VERSION 5.8 ;
BUSBITCHARS "[]" ;
DIVIDERCHAR "/" ;
UNITS
    DATABASE MICRONS 1000 ;
END UNITS

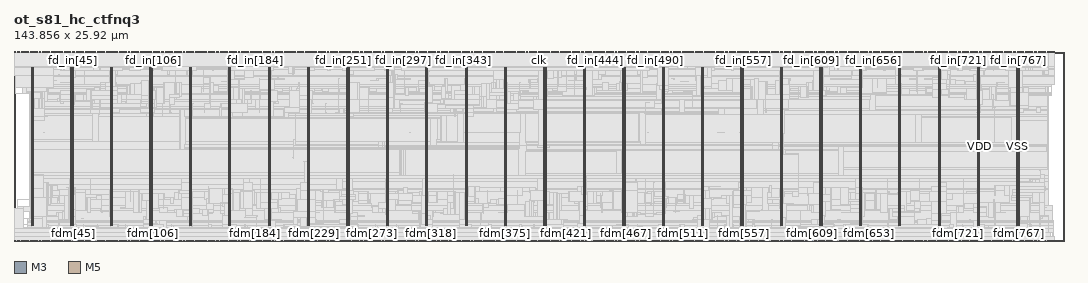
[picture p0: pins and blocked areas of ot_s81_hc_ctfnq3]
MACRO ot_s81_hc_ctfnq3
  FOREIGN ot_s81_hc_ctfnq3 0 0 ;
  CLASS BLOCK ;
  SIZE 143.856 BY 25.92 ;
  PIN clk
    DIRECTION INPUT ;
    USE SIGNAL ;
    PORT
      LAYER M3 ;
        RECT  71.892 25.882 71.91 25.92 ;
    END
  END clk
  PIN fd_in[0]
    DIRECTION INPUT ;
    USE SIGNAL ;
    PORT
      LAYER M5 ;
        RECT  0.048 25.836 0.072 25.92 ;
    END
  END fd_in[0]
  PIN fd_in[100]
    DIRECTION INPUT ;
    USE SIGNAL ;
    PORT
      LAYER M5 ;
        RECT  18 25.836 18.024 25.92 ;
    END
  END fd_in[100]
  PIN fd_in[101]
    DIRECTION INPUT ;
    USE SIGNAL ;
    PORT
      LAYER M5 ;
        RECT  18.192 25.836 18.216 25.92 ;
    END
  END fd_in[101]
  PIN fd_in[102]
    DIRECTION INPUT ;
    USE SIGNAL ;
    PORT
      LAYER M5 ;
        RECT  18.336 25.836 18.36 25.92 ;
    END
  END fd_in[102]
  PIN fd_in[103]
    DIRECTION INPUT ;
    USE SIGNAL ;
    PORT
      LAYER M5 ;
        RECT  18.528 25.836 18.552 25.92 ;
    END
  END fd_in[103]
  PIN fd_in[104]
    DIRECTION INPUT ;
    USE SIGNAL ;
    PORT
      LAYER M5 ;
        RECT  18.72 25.836 18.744 25.92 ;
    END
  END fd_in[104]
  PIN fd_in[105]
    DIRECTION INPUT ;
    USE SIGNAL ;
    PORT
      LAYER M5 ;
        RECT  18.864 25.836 18.888 25.92 ;
    END
  END fd_in[105]
  PIN fd_in[106]
    DIRECTION INPUT ;
    USE SIGNAL ;
    PORT
      LAYER M5 ;
        RECT  19.056 25.836 19.08 25.92 ;
    END
  END fd_in[106]
  PIN fd_in[107]
    DIRECTION INPUT ;
    USE SIGNAL ;
    PORT
      LAYER M5 ;
        RECT  19.248 25.836 19.272 25.92 ;
    END
  END fd_in[107]
  PIN fd_in[108]
    DIRECTION INPUT ;
    USE SIGNAL ;
    PORT
      LAYER M5 ;
        RECT  19.44 25.836 19.464 25.92 ;
    END
  END fd_in[108]
  PIN fd_in[109]
    DIRECTION INPUT ;
    USE SIGNAL ;
    PORT
      LAYER M5 ;
        RECT  19.584 25.836 19.608 25.92 ;
    END
  END fd_in[109]
  PIN fd_in[10]
    DIRECTION INPUT ;
    USE SIGNAL ;
    PORT
      LAYER M5 ;
        RECT  1.872 25.836 1.896 25.92 ;
    END
  END fd_in[10]
  PIN fd_in[110]
    DIRECTION INPUT ;
    USE SIGNAL ;
    PORT
      LAYER M5 ;
        RECT  19.776 25.836 19.8 25.92 ;
    END
  END fd_in[110]
  PIN fd_in[111]
    DIRECTION INPUT ;
    USE SIGNAL ;
    PORT
      LAYER M5 ;
        RECT  19.968 25.836 19.992 25.92 ;
    END
  END fd_in[111]
  PIN fd_in[112]
    DIRECTION INPUT ;
    USE SIGNAL ;
    PORT
      LAYER M5 ;
        RECT  20.16 25.836 20.184 25.92 ;
    END
  END fd_in[112]
  PIN fd_in[113]
    DIRECTION INPUT ;
    USE SIGNAL ;
    PORT
      LAYER M5 ;
        RECT  20.304 25.836 20.328 25.92 ;
    END
  END fd_in[113]
  PIN fd_in[114]
    DIRECTION INPUT ;
    USE SIGNAL ;
    PORT
      LAYER M5 ;
        RECT  20.496 25.836 20.52 25.92 ;
    END
  END fd_in[114]
  PIN fd_in[115]
    DIRECTION INPUT ;
    USE SIGNAL ;
    PORT
      LAYER M5 ;
        RECT  20.688 25.836 20.712 25.92 ;
    END
  END fd_in[115]
  PIN fd_in[116]
    DIRECTION INPUT ;
    USE SIGNAL ;
    PORT
      LAYER M5 ;
        RECT  20.88 25.836 20.904 25.92 ;
    END
  END fd_in[116]
  PIN fd_in[117]
    DIRECTION INPUT ;
    USE SIGNAL ;
    PORT
      LAYER M5 ;
        RECT  21.024 25.836 21.048 25.92 ;
    END
  END fd_in[117]
  PIN fd_in[118]
    DIRECTION INPUT ;
    USE SIGNAL ;
    PORT
      LAYER M5 ;
        RECT  21.216 25.836 21.24 25.92 ;
    END
  END fd_in[118]
  PIN fd_in[119]
    DIRECTION INPUT ;
    USE SIGNAL ;
    PORT
      LAYER M5 ;
        RECT  21.408 25.836 21.432 25.92 ;
    END
  END fd_in[119]
  PIN fd_in[11]
    DIRECTION INPUT ;
    USE SIGNAL ;
    PORT
      LAYER M5 ;
        RECT  2.016 25.836 2.04 25.92 ;
    END
  END fd_in[11]
  PIN fd_in[120]
    DIRECTION INPUT ;
    USE SIGNAL ;
    PORT
      LAYER M5 ;
        RECT  21.552 25.836 21.576 25.92 ;
    END
  END fd_in[120]
  PIN fd_in[121]
    DIRECTION INPUT ;
    USE SIGNAL ;
    PORT
      LAYER M5 ;
        RECT  21.744 25.836 21.768 25.92 ;
    END
  END fd_in[121]
  PIN fd_in[122]
    DIRECTION INPUT ;
    USE SIGNAL ;
    PORT
      LAYER M5 ;
        RECT  21.936 25.836 21.96 25.92 ;
    END
  END fd_in[122]
  PIN fd_in[123]
    DIRECTION INPUT ;
    USE SIGNAL ;
    PORT
      LAYER M5 ;
        RECT  22.128 25.836 22.152 25.92 ;
    END
  END fd_in[123]
  PIN fd_in[124]
    DIRECTION INPUT ;
    USE SIGNAL ;
    PORT
      LAYER M5 ;
        RECT  22.272 25.836 22.296 25.92 ;
    END
  END fd_in[124]
  PIN fd_in[125]
    DIRECTION INPUT ;
    USE SIGNAL ;
    PORT
      LAYER M5 ;
        RECT  22.464 25.836 22.488 25.92 ;
    END
  END fd_in[125]
  PIN fd_in[126]
    DIRECTION INPUT ;
    USE SIGNAL ;
    PORT
      LAYER M5 ;
        RECT  22.656 25.836 22.68 25.92 ;
    END
  END fd_in[126]
  PIN fd_in[127]
    DIRECTION INPUT ;
    USE SIGNAL ;
    PORT
      LAYER M5 ;
        RECT  22.848 25.836 22.872 25.92 ;
    END
  END fd_in[127]
  PIN fd_in[128]
    DIRECTION INPUT ;
    USE SIGNAL ;
    PORT
      LAYER M5 ;
        RECT  22.992 25.836 23.016 25.92 ;
    END
  END fd_in[128]
  PIN fd_in[129]
    DIRECTION INPUT ;
    USE SIGNAL ;
    PORT
      LAYER M5 ;
        RECT  23.184 25.836 23.208 25.92 ;
    END
  END fd_in[129]
  PIN fd_in[12]
    DIRECTION INPUT ;
    USE SIGNAL ;
    PORT
      LAYER M5 ;
        RECT  2.208 25.836 2.232 25.92 ;
    END
  END fd_in[12]
  PIN fd_in[130]
    DIRECTION INPUT ;
    USE SIGNAL ;
    PORT
      LAYER M5 ;
        RECT  23.376 25.836 23.4 25.92 ;
    END
  END fd_in[130]
  PIN fd_in[131]
    DIRECTION INPUT ;
    USE SIGNAL ;
    PORT
      LAYER M5 ;
        RECT  23.568 25.836 23.592 25.92 ;
    END
  END fd_in[131]
  PIN fd_in[132]
    DIRECTION INPUT ;
    USE SIGNAL ;
    PORT
      LAYER M5 ;
        RECT  23.712 25.836 23.736 25.92 ;
    END
  END fd_in[132]
  PIN fd_in[133]
    DIRECTION INPUT ;
    USE SIGNAL ;
    PORT
      LAYER M5 ;
        RECT  23.904 25.836 23.928 25.92 ;
    END
  END fd_in[133]
  PIN fd_in[134]
    DIRECTION INPUT ;
    USE SIGNAL ;
    PORT
      LAYER M5 ;
        RECT  24.096 25.836 24.12 25.92 ;
    END
  END fd_in[134]
  PIN fd_in[135]
    DIRECTION INPUT ;
    USE SIGNAL ;
    PORT
      LAYER M5 ;
        RECT  24.288 25.836 24.312 25.92 ;
    END
  END fd_in[135]
  PIN fd_in[136]
    DIRECTION INPUT ;
    USE SIGNAL ;
    PORT
      LAYER M5 ;
        RECT  24.432 25.836 24.456 25.92 ;
    END
  END fd_in[136]
  PIN fd_in[137]
    DIRECTION INPUT ;
    USE SIGNAL ;
    PORT
      LAYER M5 ;
        RECT  24.624 25.836 24.648 25.92 ;
    END
  END fd_in[137]
  PIN fd_in[138]
    DIRECTION INPUT ;
    USE SIGNAL ;
    PORT
      LAYER M5 ;
        RECT  24.816 25.836 24.84 25.92 ;
    END
  END fd_in[138]
  PIN fd_in[139]
    DIRECTION INPUT ;
    USE SIGNAL ;
    PORT
      LAYER M5 ;
        RECT  24.96 25.836 24.984 25.92 ;
    END
  END fd_in[139]
  PIN fd_in[13]
    DIRECTION INPUT ;
    USE SIGNAL ;
    PORT
      LAYER M5 ;
        RECT  2.4 25.836 2.424 25.92 ;
    END
  END fd_in[13]
  PIN fd_in[140]
    DIRECTION INPUT ;
    USE SIGNAL ;
    PORT
      LAYER M5 ;
        RECT  25.152 25.836 25.176 25.92 ;
    END
  END fd_in[140]
  PIN fd_in[141]
    DIRECTION INPUT ;
    USE SIGNAL ;
    PORT
      LAYER M5 ;
        RECT  25.344 25.836 25.368 25.92 ;
    END
  END fd_in[141]
  PIN fd_in[142]
    DIRECTION INPUT ;
    USE SIGNAL ;
    PORT
      LAYER M5 ;
        RECT  25.536 25.836 25.56 25.92 ;
    END
  END fd_in[142]
  PIN fd_in[143]
    DIRECTION INPUT ;
    USE SIGNAL ;
    PORT
      LAYER M5 ;
        RECT  25.68 25.836 25.704 25.92 ;
    END
  END fd_in[143]
  PIN fd_in[144]
    DIRECTION INPUT ;
    USE SIGNAL ;
    PORT
      LAYER M5 ;
        RECT  25.872 25.836 25.896 25.92 ;
    END
  END fd_in[144]
  PIN fd_in[145]
    DIRECTION INPUT ;
    USE SIGNAL ;
    PORT
      LAYER M5 ;
        RECT  26.064 25.836 26.088 25.92 ;
    END
  END fd_in[145]
  PIN fd_in[146]
    DIRECTION INPUT ;
    USE SIGNAL ;
    PORT
      LAYER M5 ;
        RECT  26.256 25.836 26.28 25.92 ;
    END
  END fd_in[146]
  PIN fd_in[147]
    DIRECTION INPUT ;
    USE SIGNAL ;
    PORT
      LAYER M5 ;
        RECT  26.4 25.836 26.424 25.92 ;
    END
  END fd_in[147]
  PIN fd_in[148]
    DIRECTION INPUT ;
    USE SIGNAL ;
    PORT
      LAYER M5 ;
        RECT  26.592 25.836 26.616 25.92 ;
    END
  END fd_in[148]
  PIN fd_in[149]
    DIRECTION INPUT ;
    USE SIGNAL ;
    PORT
      LAYER M5 ;
        RECT  26.784 25.836 26.808 25.92 ;
    END
  END fd_in[149]
  PIN fd_in[14]
    DIRECTION INPUT ;
    USE SIGNAL ;
    PORT
      LAYER M5 ;
        RECT  2.544 25.836 2.568 25.92 ;
    END
  END fd_in[14]
  PIN fd_in[150]
    DIRECTION INPUT ;
    USE SIGNAL ;
    PORT
      LAYER M5 ;
        RECT  26.976 25.836 27 25.92 ;
    END
  END fd_in[150]
  PIN fd_in[151]
    DIRECTION INPUT ;
    USE SIGNAL ;
    PORT
      LAYER M5 ;
        RECT  27.12 25.836 27.144 25.92 ;
    END
  END fd_in[151]
  PIN fd_in[152]
    DIRECTION INPUT ;
    USE SIGNAL ;
    PORT
      LAYER M5 ;
        RECT  27.312 25.836 27.336 25.92 ;
    END
  END fd_in[152]
  PIN fd_in[153]
    DIRECTION INPUT ;
    USE SIGNAL ;
    PORT
      LAYER M5 ;
        RECT  27.504 25.836 27.528 25.92 ;
    END
  END fd_in[153]
  PIN fd_in[154]
    DIRECTION INPUT ;
    USE SIGNAL ;
    PORT
      LAYER M5 ;
        RECT  27.696 25.836 27.72 25.92 ;
    END
  END fd_in[154]
  PIN fd_in[155]
    DIRECTION INPUT ;
    USE SIGNAL ;
    PORT
      LAYER M5 ;
        RECT  27.84 25.836 27.864 25.92 ;
    END
  END fd_in[155]
  PIN fd_in[156]
    DIRECTION INPUT ;
    USE SIGNAL ;
    PORT
      LAYER M5 ;
        RECT  28.032 25.836 28.056 25.92 ;
    END
  END fd_in[156]
  PIN fd_in[157]
    DIRECTION INPUT ;
    USE SIGNAL ;
    PORT
      LAYER M5 ;
        RECT  28.224 25.836 28.248 25.92 ;
    END
  END fd_in[157]
  PIN fd_in[158]
    DIRECTION INPUT ;
    USE SIGNAL ;
    PORT
      LAYER M5 ;
        RECT  28.368 25.836 28.392 25.92 ;
    END
  END fd_in[158]
  PIN fd_in[159]
    DIRECTION INPUT ;
    USE SIGNAL ;
    PORT
      LAYER M5 ;
        RECT  28.56 25.836 28.584 25.92 ;
    END
  END fd_in[159]
  PIN fd_in[15]
    DIRECTION INPUT ;
    USE SIGNAL ;
    PORT
      LAYER M5 ;
        RECT  2.736 25.836 2.76 25.92 ;
    END
  END fd_in[15]
  PIN fd_in[160]
    DIRECTION INPUT ;
    USE SIGNAL ;
    PORT
      LAYER M5 ;
        RECT  28.752 25.836 28.776 25.92 ;
    END
  END fd_in[160]
  PIN fd_in[161]
    DIRECTION INPUT ;
    USE SIGNAL ;
    PORT
      LAYER M5 ;
        RECT  28.944 25.836 28.968 25.92 ;
    END
  END fd_in[161]
  PIN fd_in[162]
    DIRECTION INPUT ;
    USE SIGNAL ;
    PORT
      LAYER M5 ;
        RECT  29.088 25.836 29.112 25.92 ;
    END
  END fd_in[162]
  PIN fd_in[163]
    DIRECTION INPUT ;
    USE SIGNAL ;
    PORT
      LAYER M5 ;
        RECT  29.28 25.836 29.304 25.92 ;
    END
  END fd_in[163]
  PIN fd_in[164]
    DIRECTION INPUT ;
    USE SIGNAL ;
    PORT
      LAYER M5 ;
        RECT  29.472 25.836 29.496 25.92 ;
    END
  END fd_in[164]
  PIN fd_in[165]
    DIRECTION INPUT ;
    USE SIGNAL ;
    PORT
      LAYER M5 ;
        RECT  29.664 25.836 29.688 25.92 ;
    END
  END fd_in[165]
  PIN fd_in[166]
    DIRECTION INPUT ;
    USE SIGNAL ;
    PORT
      LAYER M5 ;
        RECT  29.808 25.836 29.832 25.92 ;
    END
  END fd_in[166]
  PIN fd_in[167]
    DIRECTION INPUT ;
    USE SIGNAL ;
    PORT
      LAYER M5 ;
        RECT  30 25.836 30.024 25.92 ;
    END
  END fd_in[167]
  PIN fd_in[168]
    DIRECTION INPUT ;
    USE SIGNAL ;
    PORT
      LAYER M5 ;
        RECT  30.192 25.836 30.216 25.92 ;
    END
  END fd_in[168]
  PIN fd_in[169]
    DIRECTION INPUT ;
    USE SIGNAL ;
    PORT
      LAYER M5 ;
        RECT  30.384 25.836 30.408 25.92 ;
    END
  END fd_in[169]
  PIN fd_in[16]
    DIRECTION INPUT ;
    USE SIGNAL ;
    PORT
      LAYER M5 ;
        RECT  2.928 25.836 2.952 25.92 ;
    END
  END fd_in[16]
  PIN fd_in[170]
    DIRECTION INPUT ;
    USE SIGNAL ;
    PORT
      LAYER M5 ;
        RECT  30.528 25.836 30.552 25.92 ;
    END
  END fd_in[170]
  PIN fd_in[171]
    DIRECTION INPUT ;
    USE SIGNAL ;
    PORT
      LAYER M5 ;
        RECT  30.72 25.836 30.744 25.92 ;
    END
  END fd_in[171]
  PIN fd_in[172]
    DIRECTION INPUT ;
    USE SIGNAL ;
    PORT
      LAYER M5 ;
        RECT  30.912 25.836 30.936 25.92 ;
    END
  END fd_in[172]
  PIN fd_in[173]
    DIRECTION INPUT ;
    USE SIGNAL ;
    PORT
      LAYER M5 ;
        RECT  31.104 25.836 31.128 25.92 ;
    END
  END fd_in[173]
  PIN fd_in[174]
    DIRECTION INPUT ;
    USE SIGNAL ;
    PORT
      LAYER M5 ;
        RECT  31.248 25.836 31.272 25.92 ;
    END
  END fd_in[174]
  PIN fd_in[175]
    DIRECTION INPUT ;
    USE SIGNAL ;
    PORT
      LAYER M5 ;
        RECT  31.44 25.836 31.464 25.92 ;
    END
  END fd_in[175]
  PIN fd_in[176]
    DIRECTION INPUT ;
    USE SIGNAL ;
    PORT
      LAYER M5 ;
        RECT  31.632 25.836 31.656 25.92 ;
    END
  END fd_in[176]
  PIN fd_in[177]
    DIRECTION INPUT ;
    USE SIGNAL ;
    PORT
      LAYER M5 ;
        RECT  31.776 25.836 31.8 25.92 ;
    END
  END fd_in[177]
  PIN fd_in[178]
    DIRECTION INPUT ;
    USE SIGNAL ;
    PORT
      LAYER M5 ;
        RECT  31.968 25.836 31.992 25.92 ;
    END
  END fd_in[178]
  PIN fd_in[179]
    DIRECTION INPUT ;
    USE SIGNAL ;
    PORT
      LAYER M5 ;
        RECT  32.16 25.836 32.184 25.92 ;
    END
  END fd_in[179]
  PIN fd_in[17]
    DIRECTION INPUT ;
    USE SIGNAL ;
    PORT
      LAYER M5 ;
        RECT  3.12 25.836 3.144 25.92 ;
    END
  END fd_in[17]
  PIN fd_in[180]
    DIRECTION INPUT ;
    USE SIGNAL ;
    PORT
      LAYER M5 ;
        RECT  32.352 25.836 32.376 25.92 ;
    END
  END fd_in[180]
  PIN fd_in[181]
    DIRECTION INPUT ;
    USE SIGNAL ;
    PORT
      LAYER M5 ;
        RECT  32.496 25.836 32.52 25.92 ;
    END
  END fd_in[181]
  PIN fd_in[182]
    DIRECTION INPUT ;
    USE SIGNAL ;
    PORT
      LAYER M5 ;
        RECT  32.688 25.836 32.712 25.92 ;
    END
  END fd_in[182]
  PIN fd_in[183]
    DIRECTION INPUT ;
    USE SIGNAL ;
    PORT
      LAYER M5 ;
        RECT  32.88 25.836 32.904 25.92 ;
    END
  END fd_in[183]
  PIN fd_in[184]
    DIRECTION INPUT ;
    USE SIGNAL ;
    PORT
      LAYER M5 ;
        RECT  33.072 25.836 33.096 25.92 ;
    END
  END fd_in[184]
  PIN fd_in[185]
    DIRECTION INPUT ;
    USE SIGNAL ;
    PORT
      LAYER M5 ;
        RECT  33.216 25.836 33.24 25.92 ;
    END
  END fd_in[185]
  PIN fd_in[186]
    DIRECTION INPUT ;
    USE SIGNAL ;
    PORT
      LAYER M5 ;
        RECT  33.408 25.836 33.432 25.92 ;
    END
  END fd_in[186]
  PIN fd_in[187]
    DIRECTION INPUT ;
    USE SIGNAL ;
    PORT
      LAYER M5 ;
        RECT  33.6 25.836 33.624 25.92 ;
    END
  END fd_in[187]
  PIN fd_in[188]
    DIRECTION INPUT ;
    USE SIGNAL ;
    PORT
      LAYER M5 ;
        RECT  33.792 25.836 33.816 25.92 ;
    END
  END fd_in[188]
  PIN fd_in[189]
    DIRECTION INPUT ;
    USE SIGNAL ;
    PORT
      LAYER M5 ;
        RECT  33.936 25.836 33.96 25.92 ;
    END
  END fd_in[189]
  PIN fd_in[18]
    DIRECTION INPUT ;
    USE SIGNAL ;
    PORT
      LAYER M5 ;
        RECT  3.264 25.836 3.288 25.92 ;
    END
  END fd_in[18]
  PIN fd_in[190]
    DIRECTION INPUT ;
    USE SIGNAL ;
    PORT
      LAYER M5 ;
        RECT  34.128 25.836 34.152 25.92 ;
    END
  END fd_in[190]
  PIN fd_in[191]
    DIRECTION INPUT ;
    USE SIGNAL ;
    PORT
      LAYER M5 ;
        RECT  34.32 25.836 34.344 25.92 ;
    END
  END fd_in[191]
  PIN fd_in[192]
    DIRECTION INPUT ;
    USE SIGNAL ;
    PORT
      LAYER M5 ;
        RECT  34.512 25.836 34.536 25.92 ;
    END
  END fd_in[192]
  PIN fd_in[193]
    DIRECTION INPUT ;
    USE SIGNAL ;
    PORT
      LAYER M5 ;
        RECT  34.656 25.836 34.68 25.92 ;
    END
  END fd_in[193]
  PIN fd_in[194]
    DIRECTION INPUT ;
    USE SIGNAL ;
    PORT
      LAYER M5 ;
        RECT  34.848 25.836 34.872 25.92 ;
    END
  END fd_in[194]
  PIN fd_in[195]
    DIRECTION INPUT ;
    USE SIGNAL ;
    PORT
      LAYER M5 ;
        RECT  35.04 25.836 35.064 25.92 ;
    END
  END fd_in[195]
  PIN fd_in[196]
    DIRECTION INPUT ;
    USE SIGNAL ;
    PORT
      LAYER M5 ;
        RECT  35.184 25.836 35.208 25.92 ;
    END
  END fd_in[196]
  PIN fd_in[197]
    DIRECTION INPUT ;
    USE SIGNAL ;
    PORT
      LAYER M5 ;
        RECT  35.376 25.836 35.4 25.92 ;
    END
  END fd_in[197]
  PIN fd_in[198]
    DIRECTION INPUT ;
    USE SIGNAL ;
    PORT
      LAYER M5 ;
        RECT  35.568 25.836 35.592 25.92 ;
    END
  END fd_in[198]
  PIN fd_in[199]
    DIRECTION INPUT ;
    USE SIGNAL ;
    PORT
      LAYER M5 ;
        RECT  35.76 25.836 35.784 25.92 ;
    END
  END fd_in[199]
  PIN fd_in[19]
    DIRECTION INPUT ;
    USE SIGNAL ;
    PORT
      LAYER M5 ;
        RECT  3.456 25.836 3.48 25.92 ;
    END
  END fd_in[19]
  PIN fd_in[1]
    DIRECTION INPUT ;
    USE SIGNAL ;
    PORT
      LAYER M5 ;
        RECT  0.24 25.836 0.264 25.92 ;
    END
  END fd_in[1]
  PIN fd_in[200]
    DIRECTION INPUT ;
    USE SIGNAL ;
    PORT
      LAYER M5 ;
        RECT  35.904 25.836 35.928 25.92 ;
    END
  END fd_in[200]
  PIN fd_in[201]
    DIRECTION INPUT ;
    USE SIGNAL ;
    PORT
      LAYER M5 ;
        RECT  36.096 25.836 36.12 25.92 ;
    END
  END fd_in[201]
  PIN fd_in[202]
    DIRECTION INPUT ;
    USE SIGNAL ;
    PORT
      LAYER M5 ;
        RECT  36.288 25.836 36.312 25.92 ;
    END
  END fd_in[202]
  PIN fd_in[203]
    DIRECTION INPUT ;
    USE SIGNAL ;
    PORT
      LAYER M5 ;
        RECT  36.48 25.836 36.504 25.92 ;
    END
  END fd_in[203]
  PIN fd_in[204]
    DIRECTION INPUT ;
    USE SIGNAL ;
    PORT
      LAYER M5 ;
        RECT  36.624 25.836 36.648 25.92 ;
    END
  END fd_in[204]
  PIN fd_in[205]
    DIRECTION INPUT ;
    USE SIGNAL ;
    PORT
      LAYER M5 ;
        RECT  36.816 25.836 36.84 25.92 ;
    END
  END fd_in[205]
  PIN fd_in[206]
    DIRECTION INPUT ;
    USE SIGNAL ;
    PORT
      LAYER M5 ;
        RECT  37.008 25.836 37.032 25.92 ;
    END
  END fd_in[206]
  PIN fd_in[207]
    DIRECTION INPUT ;
    USE SIGNAL ;
    PORT
      LAYER M5 ;
        RECT  37.2 25.836 37.224 25.92 ;
    END
  END fd_in[207]
  PIN fd_in[208]
    DIRECTION INPUT ;
    USE SIGNAL ;
    PORT
      LAYER M5 ;
        RECT  37.344 25.836 37.368 25.92 ;
    END
  END fd_in[208]
  PIN fd_in[209]
    DIRECTION INPUT ;
    USE SIGNAL ;
    PORT
      LAYER M5 ;
        RECT  37.536 25.836 37.56 25.92 ;
    END
  END fd_in[209]
  PIN fd_in[20]
    DIRECTION INPUT ;
    USE SIGNAL ;
    PORT
      LAYER M5 ;
        RECT  3.648 25.836 3.672 25.92 ;
    END
  END fd_in[20]
  PIN fd_in[210]
    DIRECTION INPUT ;
    USE SIGNAL ;
    PORT
      LAYER M5 ;
        RECT  37.728 25.836 37.752 25.92 ;
    END
  END fd_in[210]
  PIN fd_in[211]
    DIRECTION INPUT ;
    USE SIGNAL ;
    PORT
      LAYER M5 ;
        RECT  37.92 25.836 37.944 25.92 ;
    END
  END fd_in[211]
  PIN fd_in[212]
    DIRECTION INPUT ;
    USE SIGNAL ;
    PORT
      LAYER M5 ;
        RECT  38.064 25.836 38.088 25.92 ;
    END
  END fd_in[212]
  PIN fd_in[213]
    DIRECTION INPUT ;
    USE SIGNAL ;
    PORT
      LAYER M5 ;
        RECT  38.256 25.836 38.28 25.92 ;
    END
  END fd_in[213]
  PIN fd_in[214]
    DIRECTION INPUT ;
    USE SIGNAL ;
    PORT
      LAYER M5 ;
        RECT  38.448 25.836 38.472 25.92 ;
    END
  END fd_in[214]
  PIN fd_in[215]
    DIRECTION INPUT ;
    USE SIGNAL ;
    PORT
      LAYER M5 ;
        RECT  38.592 25.836 38.616 25.92 ;
    END
  END fd_in[215]
  PIN fd_in[216]
    DIRECTION INPUT ;
    USE SIGNAL ;
    PORT
      LAYER M5 ;
        RECT  38.784 25.836 38.808 25.92 ;
    END
  END fd_in[216]
  PIN fd_in[217]
    DIRECTION INPUT ;
    USE SIGNAL ;
    PORT
      LAYER M5 ;
        RECT  38.976 25.836 39 25.92 ;
    END
  END fd_in[217]
  PIN fd_in[218]
    DIRECTION INPUT ;
    USE SIGNAL ;
    PORT
      LAYER M5 ;
        RECT  39.168 25.836 39.192 25.92 ;
    END
  END fd_in[218]
  PIN fd_in[219]
    DIRECTION INPUT ;
    USE SIGNAL ;
    PORT
      LAYER M5 ;
        RECT  39.312 25.836 39.336 25.92 ;
    END
  END fd_in[219]
  PIN fd_in[21]
    DIRECTION INPUT ;
    USE SIGNAL ;
    PORT
      LAYER M5 ;
        RECT  3.84 25.836 3.864 25.92 ;
    END
  END fd_in[21]
  PIN fd_in[220]
    DIRECTION INPUT ;
    USE SIGNAL ;
    PORT
      LAYER M5 ;
        RECT  39.504 25.836 39.528 25.92 ;
    END
  END fd_in[220]
  PIN fd_in[221]
    DIRECTION INPUT ;
    USE SIGNAL ;
    PORT
      LAYER M5 ;
        RECT  39.696 25.836 39.72 25.92 ;
    END
  END fd_in[221]
  PIN fd_in[222]
    DIRECTION INPUT ;
    USE SIGNAL ;
    PORT
      LAYER M5 ;
        RECT  39.888 25.836 39.912 25.92 ;
    END
  END fd_in[222]
  PIN fd_in[223]
    DIRECTION INPUT ;
    USE SIGNAL ;
    PORT
      LAYER M5 ;
        RECT  40.032 25.836 40.056 25.92 ;
    END
  END fd_in[223]
  PIN fd_in[224]
    DIRECTION INPUT ;
    USE SIGNAL ;
    PORT
      LAYER M5 ;
        RECT  40.224 25.836 40.248 25.92 ;
    END
  END fd_in[224]
  PIN fd_in[225]
    DIRECTION INPUT ;
    USE SIGNAL ;
    PORT
      LAYER M5 ;
        RECT  40.416 25.836 40.44 25.92 ;
    END
  END fd_in[225]
  PIN fd_in[226]
    DIRECTION INPUT ;
    USE SIGNAL ;
    PORT
      LAYER M5 ;
        RECT  40.608 25.836 40.632 25.92 ;
    END
  END fd_in[226]
  PIN fd_in[227]
    DIRECTION INPUT ;
    USE SIGNAL ;
    PORT
      LAYER M5 ;
        RECT  40.752 25.836 40.776 25.92 ;
    END
  END fd_in[227]
  PIN fd_in[228]
    DIRECTION INPUT ;
    USE SIGNAL ;
    PORT
      LAYER M5 ;
        RECT  40.944 25.836 40.968 25.92 ;
    END
  END fd_in[228]
  PIN fd_in[229]
    DIRECTION INPUT ;
    USE SIGNAL ;
    PORT
      LAYER M5 ;
        RECT  41.136 25.836 41.16 25.92 ;
    END
  END fd_in[229]
  PIN fd_in[22]
    DIRECTION INPUT ;
    USE SIGNAL ;
    PORT
      LAYER M5 ;
        RECT  3.984 25.836 4.008 25.92 ;
    END
  END fd_in[22]
  PIN fd_in[230]
    DIRECTION INPUT ;
    USE SIGNAL ;
    PORT
      LAYER M5 ;
        RECT  41.28 25.836 41.304 25.92 ;
    END
  END fd_in[230]
  PIN fd_in[231]
    DIRECTION INPUT ;
    USE SIGNAL ;
    PORT
      LAYER M5 ;
        RECT  41.472 25.836 41.496 25.92 ;
    END
  END fd_in[231]
  PIN fd_in[232]
    DIRECTION INPUT ;
    USE SIGNAL ;
    PORT
      LAYER M5 ;
        RECT  41.664 25.836 41.688 25.92 ;
    END
  END fd_in[232]
  PIN fd_in[233]
    DIRECTION INPUT ;
    USE SIGNAL ;
    PORT
      LAYER M5 ;
        RECT  41.856 25.836 41.88 25.92 ;
    END
  END fd_in[233]
  PIN fd_in[234]
    DIRECTION INPUT ;
    USE SIGNAL ;
    PORT
      LAYER M5 ;
        RECT  42 25.836 42.024 25.92 ;
    END
  END fd_in[234]
  PIN fd_in[235]
    DIRECTION INPUT ;
    USE SIGNAL ;
    PORT
      LAYER M5 ;
        RECT  42.192 25.836 42.216 25.92 ;
    END
  END fd_in[235]
  PIN fd_in[236]
    DIRECTION INPUT ;
    USE SIGNAL ;
    PORT
      LAYER M5 ;
        RECT  42.384 25.836 42.408 25.92 ;
    END
  END fd_in[236]
  PIN fd_in[237]
    DIRECTION INPUT ;
    USE SIGNAL ;
    PORT
      LAYER M5 ;
        RECT  42.576 25.836 42.6 25.92 ;
    END
  END fd_in[237]
  PIN fd_in[238]
    DIRECTION INPUT ;
    USE SIGNAL ;
    PORT
      LAYER M5 ;
        RECT  42.72 25.836 42.744 25.92 ;
    END
  END fd_in[238]
  PIN fd_in[239]
    DIRECTION INPUT ;
    USE SIGNAL ;
    PORT
      LAYER M5 ;
        RECT  42.912 25.836 42.936 25.92 ;
    END
  END fd_in[239]
  PIN fd_in[23]
    DIRECTION INPUT ;
    USE SIGNAL ;
    PORT
      LAYER M5 ;
        RECT  4.176 25.836 4.2 25.92 ;
    END
  END fd_in[23]
  PIN fd_in[240]
    DIRECTION INPUT ;
    USE SIGNAL ;
    PORT
      LAYER M5 ;
        RECT  43.104 25.836 43.128 25.92 ;
    END
  END fd_in[240]
  PIN fd_in[241]
    DIRECTION INPUT ;
    USE SIGNAL ;
    PORT
      LAYER M5 ;
        RECT  43.296 25.836 43.32 25.92 ;
    END
  END fd_in[241]
  PIN fd_in[242]
    DIRECTION INPUT ;
    USE SIGNAL ;
    PORT
      LAYER M5 ;
        RECT  43.44 25.836 43.464 25.92 ;
    END
  END fd_in[242]
  PIN fd_in[243]
    DIRECTION INPUT ;
    USE SIGNAL ;
    PORT
      LAYER M5 ;
        RECT  43.632 25.836 43.656 25.92 ;
    END
  END fd_in[243]
  PIN fd_in[244]
    DIRECTION INPUT ;
    USE SIGNAL ;
    PORT
      LAYER M5 ;
        RECT  43.824 25.836 43.848 25.92 ;
    END
  END fd_in[244]
  PIN fd_in[245]
    DIRECTION INPUT ;
    USE SIGNAL ;
    PORT
      LAYER M5 ;
        RECT  44.016 25.836 44.04 25.92 ;
    END
  END fd_in[245]
  PIN fd_in[246]
    DIRECTION INPUT ;
    USE SIGNAL ;
    PORT
      LAYER M5 ;
        RECT  44.16 25.836 44.184 25.92 ;
    END
  END fd_in[246]
  PIN fd_in[247]
    DIRECTION INPUT ;
    USE SIGNAL ;
    PORT
      LAYER M5 ;
        RECT  44.352 25.836 44.376 25.92 ;
    END
  END fd_in[247]
  PIN fd_in[248]
    DIRECTION INPUT ;
    USE SIGNAL ;
    PORT
      LAYER M5 ;
        RECT  44.544 25.836 44.568 25.92 ;
    END
  END fd_in[248]
  PIN fd_in[249]
    DIRECTION INPUT ;
    USE SIGNAL ;
    PORT
      LAYER M5 ;
        RECT  44.688 25.836 44.712 25.92 ;
    END
  END fd_in[249]
  PIN fd_in[24]
    DIRECTION INPUT ;
    USE SIGNAL ;
    PORT
      LAYER M5 ;
        RECT  4.368 25.836 4.392 25.92 ;
    END
  END fd_in[24]
  PIN fd_in[250]
    DIRECTION INPUT ;
    USE SIGNAL ;
    PORT
      LAYER M5 ;
        RECT  44.88 25.836 44.904 25.92 ;
    END
  END fd_in[250]
  PIN fd_in[251]
    DIRECTION INPUT ;
    USE SIGNAL ;
    PORT
      LAYER M5 ;
        RECT  45.072 25.836 45.096 25.92 ;
    END
  END fd_in[251]
  PIN fd_in[252]
    DIRECTION INPUT ;
    USE SIGNAL ;
    PORT
      LAYER M5 ;
        RECT  45.264 25.836 45.288 25.92 ;
    END
  END fd_in[252]
  PIN fd_in[253]
    DIRECTION INPUT ;
    USE SIGNAL ;
    PORT
      LAYER M5 ;
        RECT  45.408 25.836 45.432 25.92 ;
    END
  END fd_in[253]
  PIN fd_in[254]
    DIRECTION INPUT ;
    USE SIGNAL ;
    PORT
      LAYER M5 ;
        RECT  45.6 25.836 45.624 25.92 ;
    END
  END fd_in[254]
  PIN fd_in[255]
    DIRECTION INPUT ;
    USE SIGNAL ;
    PORT
      LAYER M5 ;
        RECT  45.792 25.836 45.816 25.92 ;
    END
  END fd_in[255]
  PIN fd_in[256]
    DIRECTION INPUT ;
    USE SIGNAL ;
    PORT
      LAYER M5 ;
        RECT  45.984 25.836 46.008 25.92 ;
    END
  END fd_in[256]
  PIN fd_in[257]
    DIRECTION INPUT ;
    USE SIGNAL ;
    PORT
      LAYER M5 ;
        RECT  46.128 25.836 46.152 25.92 ;
    END
  END fd_in[257]
  PIN fd_in[258]
    DIRECTION INPUT ;
    USE SIGNAL ;
    PORT
      LAYER M5 ;
        RECT  46.32 25.836 46.344 25.92 ;
    END
  END fd_in[258]
  PIN fd_in[259]
    DIRECTION INPUT ;
    USE SIGNAL ;
    PORT
      LAYER M5 ;
        RECT  46.512 25.836 46.536 25.92 ;
    END
  END fd_in[259]
  PIN fd_in[25]
    DIRECTION INPUT ;
    USE SIGNAL ;
    PORT
      LAYER M5 ;
        RECT  4.56 25.836 4.584 25.92 ;
    END
  END fd_in[25]
  PIN fd_in[260]
    DIRECTION INPUT ;
    USE SIGNAL ;
    PORT
      LAYER M5 ;
        RECT  46.704 25.836 46.728 25.92 ;
    END
  END fd_in[260]
  PIN fd_in[261]
    DIRECTION INPUT ;
    USE SIGNAL ;
    PORT
      LAYER M5 ;
        RECT  46.848 25.836 46.872 25.92 ;
    END
  END fd_in[261]
  PIN fd_in[262]
    DIRECTION INPUT ;
    USE SIGNAL ;
    PORT
      LAYER M5 ;
        RECT  47.04 25.836 47.064 25.92 ;
    END
  END fd_in[262]
  PIN fd_in[263]
    DIRECTION INPUT ;
    USE SIGNAL ;
    PORT
      LAYER M5 ;
        RECT  47.232 25.836 47.256 25.92 ;
    END
  END fd_in[263]
  PIN fd_in[264]
    DIRECTION INPUT ;
    USE SIGNAL ;
    PORT
      LAYER M5 ;
        RECT  47.424 25.836 47.448 25.92 ;
    END
  END fd_in[264]
  PIN fd_in[265]
    DIRECTION INPUT ;
    USE SIGNAL ;
    PORT
      LAYER M5 ;
        RECT  47.568 25.836 47.592 25.92 ;
    END
  END fd_in[265]
  PIN fd_in[266]
    DIRECTION INPUT ;
    USE SIGNAL ;
    PORT
      LAYER M5 ;
        RECT  47.76 25.836 47.784 25.92 ;
    END
  END fd_in[266]
  PIN fd_in[267]
    DIRECTION INPUT ;
    USE SIGNAL ;
    PORT
      LAYER M5 ;
        RECT  47.952 25.836 47.976 25.92 ;
    END
  END fd_in[267]
  PIN fd_in[268]
    DIRECTION INPUT ;
    USE SIGNAL ;
    PORT
      LAYER M5 ;
        RECT  48.096 25.836 48.12 25.92 ;
    END
  END fd_in[268]
  PIN fd_in[269]
    DIRECTION INPUT ;
    USE SIGNAL ;
    PORT
      LAYER M5 ;
        RECT  48.288 25.836 48.312 25.92 ;
    END
  END fd_in[269]
  PIN fd_in[26]
    DIRECTION INPUT ;
    USE SIGNAL ;
    PORT
      LAYER M5 ;
        RECT  4.704 25.836 4.728 25.92 ;
    END
  END fd_in[26]
  PIN fd_in[270]
    DIRECTION INPUT ;
    USE SIGNAL ;
    PORT
      LAYER M5 ;
        RECT  48.48 25.836 48.504 25.92 ;
    END
  END fd_in[270]
  PIN fd_in[271]
    DIRECTION INPUT ;
    USE SIGNAL ;
    PORT
      LAYER M5 ;
        RECT  48.672 25.836 48.696 25.92 ;
    END
  END fd_in[271]
  PIN fd_in[272]
    DIRECTION INPUT ;
    USE SIGNAL ;
    PORT
      LAYER M5 ;
        RECT  48.816 25.836 48.84 25.92 ;
    END
  END fd_in[272]
  PIN fd_in[273]
    DIRECTION INPUT ;
    USE SIGNAL ;
    PORT
      LAYER M5 ;
        RECT  49.008 25.836 49.032 25.92 ;
    END
  END fd_in[273]
  PIN fd_in[274]
    DIRECTION INPUT ;
    USE SIGNAL ;
    PORT
      LAYER M5 ;
        RECT  49.2 25.836 49.224 25.92 ;
    END
  END fd_in[274]
  PIN fd_in[275]
    DIRECTION INPUT ;
    USE SIGNAL ;
    PORT
      LAYER M5 ;
        RECT  49.392 25.836 49.416 25.92 ;
    END
  END fd_in[275]
  PIN fd_in[276]
    DIRECTION INPUT ;
    USE SIGNAL ;
    PORT
      LAYER M5 ;
        RECT  49.536 25.836 49.56 25.92 ;
    END
  END fd_in[276]
  PIN fd_in[277]
    DIRECTION INPUT ;
    USE SIGNAL ;
    PORT
      LAYER M5 ;
        RECT  49.728 25.836 49.752 25.92 ;
    END
  END fd_in[277]
  PIN fd_in[278]
    DIRECTION INPUT ;
    USE SIGNAL ;
    PORT
      LAYER M5 ;
        RECT  49.92 25.836 49.944 25.92 ;
    END
  END fd_in[278]
  PIN fd_in[279]
    DIRECTION INPUT ;
    USE SIGNAL ;
    PORT
      LAYER M5 ;
        RECT  50.112 25.836 50.136 25.92 ;
    END
  END fd_in[279]
  PIN fd_in[27]
    DIRECTION INPUT ;
    USE SIGNAL ;
    PORT
      LAYER M5 ;
        RECT  4.896 25.836 4.92 25.92 ;
    END
  END fd_in[27]
  PIN fd_in[280]
    DIRECTION INPUT ;
    USE SIGNAL ;
    PORT
      LAYER M5 ;
        RECT  50.256 25.836 50.28 25.92 ;
    END
  END fd_in[280]
  PIN fd_in[281]
    DIRECTION INPUT ;
    USE SIGNAL ;
    PORT
      LAYER M5 ;
        RECT  50.448 25.836 50.472 25.92 ;
    END
  END fd_in[281]
  PIN fd_in[282]
    DIRECTION INPUT ;
    USE SIGNAL ;
    PORT
      LAYER M5 ;
        RECT  50.64 25.836 50.664 25.92 ;
    END
  END fd_in[282]
  PIN fd_in[283]
    DIRECTION INPUT ;
    USE SIGNAL ;
    PORT
      LAYER M5 ;
        RECT  50.832 25.836 50.856 25.92 ;
    END
  END fd_in[283]
  PIN fd_in[284]
    DIRECTION INPUT ;
    USE SIGNAL ;
    PORT
      LAYER M5 ;
        RECT  50.976 25.836 51 25.92 ;
    END
  END fd_in[284]
  PIN fd_in[285]
    DIRECTION INPUT ;
    USE SIGNAL ;
    PORT
      LAYER M5 ;
        RECT  51.168 25.836 51.192 25.92 ;
    END
  END fd_in[285]
  PIN fd_in[286]
    DIRECTION INPUT ;
    USE SIGNAL ;
    PORT
      LAYER M5 ;
        RECT  51.36 25.836 51.384 25.92 ;
    END
  END fd_in[286]
  PIN fd_in[287]
    DIRECTION INPUT ;
    USE SIGNAL ;
    PORT
      LAYER M5 ;
        RECT  51.504 25.836 51.528 25.92 ;
    END
  END fd_in[287]
  PIN fd_in[288]
    DIRECTION INPUT ;
    USE SIGNAL ;
    PORT
      LAYER M5 ;
        RECT  51.696 25.836 51.72 25.92 ;
    END
  END fd_in[288]
  PIN fd_in[289]
    DIRECTION INPUT ;
    USE SIGNAL ;
    PORT
      LAYER M5 ;
        RECT  51.888 25.836 51.912 25.92 ;
    END
  END fd_in[289]
  PIN fd_in[28]
    DIRECTION INPUT ;
    USE SIGNAL ;
    PORT
      LAYER M5 ;
        RECT  5.088 25.836 5.112 25.92 ;
    END
  END fd_in[28]
  PIN fd_in[290]
    DIRECTION INPUT ;
    USE SIGNAL ;
    PORT
      LAYER M5 ;
        RECT  52.08 25.836 52.104 25.92 ;
    END
  END fd_in[290]
  PIN fd_in[291]
    DIRECTION INPUT ;
    USE SIGNAL ;
    PORT
      LAYER M5 ;
        RECT  52.224 25.836 52.248 25.92 ;
    END
  END fd_in[291]
  PIN fd_in[292]
    DIRECTION INPUT ;
    USE SIGNAL ;
    PORT
      LAYER M5 ;
        RECT  52.416 25.836 52.44 25.92 ;
    END
  END fd_in[292]
  PIN fd_in[293]
    DIRECTION INPUT ;
    USE SIGNAL ;
    PORT
      LAYER M5 ;
        RECT  52.608 25.836 52.632 25.92 ;
    END
  END fd_in[293]
  PIN fd_in[294]
    DIRECTION INPUT ;
    USE SIGNAL ;
    PORT
      LAYER M5 ;
        RECT  52.8 25.836 52.824 25.92 ;
    END
  END fd_in[294]
  PIN fd_in[295]
    DIRECTION INPUT ;
    USE SIGNAL ;
    PORT
      LAYER M5 ;
        RECT  52.944 25.836 52.968 25.92 ;
    END
  END fd_in[295]
  PIN fd_in[296]
    DIRECTION INPUT ;
    USE SIGNAL ;
    PORT
      LAYER M5 ;
        RECT  53.136 25.836 53.16 25.92 ;
    END
  END fd_in[296]
  PIN fd_in[297]
    DIRECTION INPUT ;
    USE SIGNAL ;
    PORT
      LAYER M5 ;
        RECT  53.328 25.836 53.352 25.92 ;
    END
  END fd_in[297]
  PIN fd_in[298]
    DIRECTION INPUT ;
    USE SIGNAL ;
    PORT
      LAYER M5 ;
        RECT  53.52 25.836 53.544 25.92 ;
    END
  END fd_in[298]
  PIN fd_in[299]
    DIRECTION INPUT ;
    USE SIGNAL ;
    PORT
      LAYER M5 ;
        RECT  53.664 25.836 53.688 25.92 ;
    END
  END fd_in[299]
  PIN fd_in[29]
    DIRECTION INPUT ;
    USE SIGNAL ;
    PORT
      LAYER M5 ;
        RECT  5.232 25.836 5.256 25.92 ;
    END
  END fd_in[29]
  PIN fd_in[2]
    DIRECTION INPUT ;
    USE SIGNAL ;
    PORT
      LAYER M5 ;
        RECT  0.432 25.836 0.456 25.92 ;
    END
  END fd_in[2]
  PIN fd_in[300]
    DIRECTION INPUT ;
    USE SIGNAL ;
    PORT
      LAYER M5 ;
        RECT  53.856 25.836 53.88 25.92 ;
    END
  END fd_in[300]
  PIN fd_in[301]
    DIRECTION INPUT ;
    USE SIGNAL ;
    PORT
      LAYER M5 ;
        RECT  54.048 25.836 54.072 25.92 ;
    END
  END fd_in[301]
  PIN fd_in[302]
    DIRECTION INPUT ;
    USE SIGNAL ;
    PORT
      LAYER M5 ;
        RECT  54.24 25.836 54.264 25.92 ;
    END
  END fd_in[302]
  PIN fd_in[303]
    DIRECTION INPUT ;
    USE SIGNAL ;
    PORT
      LAYER M5 ;
        RECT  54.384 25.836 54.408 25.92 ;
    END
  END fd_in[303]
  PIN fd_in[304]
    DIRECTION INPUT ;
    USE SIGNAL ;
    PORT
      LAYER M5 ;
        RECT  54.576 25.836 54.6 25.92 ;
    END
  END fd_in[304]
  PIN fd_in[305]
    DIRECTION INPUT ;
    USE SIGNAL ;
    PORT
      LAYER M5 ;
        RECT  54.768 25.836 54.792 25.92 ;
    END
  END fd_in[305]
  PIN fd_in[306]
    DIRECTION INPUT ;
    USE SIGNAL ;
    PORT
      LAYER M5 ;
        RECT  54.912 25.836 54.936 25.92 ;
    END
  END fd_in[306]
  PIN fd_in[307]
    DIRECTION INPUT ;
    USE SIGNAL ;
    PORT
      LAYER M5 ;
        RECT  55.104 25.836 55.128 25.92 ;
    END
  END fd_in[307]
  PIN fd_in[308]
    DIRECTION INPUT ;
    USE SIGNAL ;
    PORT
      LAYER M5 ;
        RECT  55.296 25.836 55.32 25.92 ;
    END
  END fd_in[308]
  PIN fd_in[309]
    DIRECTION INPUT ;
    USE SIGNAL ;
    PORT
      LAYER M5 ;
        RECT  55.488 25.836 55.512 25.92 ;
    END
  END fd_in[309]
  PIN fd_in[30]
    DIRECTION INPUT ;
    USE SIGNAL ;
    PORT
      LAYER M5 ;
        RECT  5.424 25.836 5.448 25.92 ;
    END
  END fd_in[30]
  PIN fd_in[310]
    DIRECTION INPUT ;
    USE SIGNAL ;
    PORT
      LAYER M5 ;
        RECT  55.632 25.836 55.656 25.92 ;
    END
  END fd_in[310]
  PIN fd_in[311]
    DIRECTION INPUT ;
    USE SIGNAL ;
    PORT
      LAYER M5 ;
        RECT  55.824 25.836 55.848 25.92 ;
    END
  END fd_in[311]
  PIN fd_in[312]
    DIRECTION INPUT ;
    USE SIGNAL ;
    PORT
      LAYER M5 ;
        RECT  56.016 25.836 56.04 25.92 ;
    END
  END fd_in[312]
  PIN fd_in[313]
    DIRECTION INPUT ;
    USE SIGNAL ;
    PORT
      LAYER M5 ;
        RECT  56.208 25.836 56.232 25.92 ;
    END
  END fd_in[313]
  PIN fd_in[314]
    DIRECTION INPUT ;
    USE SIGNAL ;
    PORT
      LAYER M5 ;
        RECT  56.352 25.836 56.376 25.92 ;
    END
  END fd_in[314]
  PIN fd_in[315]
    DIRECTION INPUT ;
    USE SIGNAL ;
    PORT
      LAYER M5 ;
        RECT  56.544 25.836 56.568 25.92 ;
    END
  END fd_in[315]
  PIN fd_in[316]
    DIRECTION INPUT ;
    USE SIGNAL ;
    PORT
      LAYER M5 ;
        RECT  56.736 25.836 56.76 25.92 ;
    END
  END fd_in[316]
  PIN fd_in[317]
    DIRECTION INPUT ;
    USE SIGNAL ;
    PORT
      LAYER M5 ;
        RECT  56.928 25.836 56.952 25.92 ;
    END
  END fd_in[317]
  PIN fd_in[318]
    DIRECTION INPUT ;
    USE SIGNAL ;
    PORT
      LAYER M5 ;
        RECT  57.072 25.836 57.096 25.92 ;
    END
  END fd_in[318]
  PIN fd_in[319]
    DIRECTION INPUT ;
    USE SIGNAL ;
    PORT
      LAYER M5 ;
        RECT  57.264 25.836 57.288 25.92 ;
    END
  END fd_in[319]
  PIN fd_in[31]
    DIRECTION INPUT ;
    USE SIGNAL ;
    PORT
      LAYER M5 ;
        RECT  5.616 25.836 5.64 25.92 ;
    END
  END fd_in[31]
  PIN fd_in[320]
    DIRECTION INPUT ;
    USE SIGNAL ;
    PORT
      LAYER M5 ;
        RECT  57.456 25.836 57.48 25.92 ;
    END
  END fd_in[320]
  PIN fd_in[321]
    DIRECTION INPUT ;
    USE SIGNAL ;
    PORT
      LAYER M5 ;
        RECT  57.6 25.836 57.624 25.92 ;
    END
  END fd_in[321]
  PIN fd_in[322]
    DIRECTION INPUT ;
    USE SIGNAL ;
    PORT
      LAYER M5 ;
        RECT  57.792 25.836 57.816 25.92 ;
    END
  END fd_in[322]
  PIN fd_in[323]
    DIRECTION INPUT ;
    USE SIGNAL ;
    PORT
      LAYER M5 ;
        RECT  57.984 25.836 58.008 25.92 ;
    END
  END fd_in[323]
  PIN fd_in[324]
    DIRECTION INPUT ;
    USE SIGNAL ;
    PORT
      LAYER M5 ;
        RECT  58.176 25.836 58.2 25.92 ;
    END
  END fd_in[324]
  PIN fd_in[325]
    DIRECTION INPUT ;
    USE SIGNAL ;
    PORT
      LAYER M5 ;
        RECT  58.32 25.836 58.344 25.92 ;
    END
  END fd_in[325]
  PIN fd_in[326]
    DIRECTION INPUT ;
    USE SIGNAL ;
    PORT
      LAYER M5 ;
        RECT  58.512 25.836 58.536 25.92 ;
    END
  END fd_in[326]
  PIN fd_in[327]
    DIRECTION INPUT ;
    USE SIGNAL ;
    PORT
      LAYER M5 ;
        RECT  58.704 25.836 58.728 25.92 ;
    END
  END fd_in[327]
  PIN fd_in[328]
    DIRECTION INPUT ;
    USE SIGNAL ;
    PORT
      LAYER M5 ;
        RECT  58.896 25.836 58.92 25.92 ;
    END
  END fd_in[328]
  PIN fd_in[329]
    DIRECTION INPUT ;
    USE SIGNAL ;
    PORT
      LAYER M5 ;
        RECT  59.04 25.836 59.064 25.92 ;
    END
  END fd_in[329]
  PIN fd_in[32]
    DIRECTION INPUT ;
    USE SIGNAL ;
    PORT
      LAYER M5 ;
        RECT  5.808 25.836 5.832 25.92 ;
    END
  END fd_in[32]
  PIN fd_in[330]
    DIRECTION INPUT ;
    USE SIGNAL ;
    PORT
      LAYER M5 ;
        RECT  59.232 25.836 59.256 25.92 ;
    END
  END fd_in[330]
  PIN fd_in[331]
    DIRECTION INPUT ;
    USE SIGNAL ;
    PORT
      LAYER M5 ;
        RECT  59.424 25.836 59.448 25.92 ;
    END
  END fd_in[331]
  PIN fd_in[332]
    DIRECTION INPUT ;
    USE SIGNAL ;
    PORT
      LAYER M5 ;
        RECT  59.616 25.836 59.64 25.92 ;
    END
  END fd_in[332]
  PIN fd_in[333]
    DIRECTION INPUT ;
    USE SIGNAL ;
    PORT
      LAYER M5 ;
        RECT  59.76 25.836 59.784 25.92 ;
    END
  END fd_in[333]
  PIN fd_in[334]
    DIRECTION INPUT ;
    USE SIGNAL ;
    PORT
      LAYER M5 ;
        RECT  59.952 25.836 59.976 25.92 ;
    END
  END fd_in[334]
  PIN fd_in[335]
    DIRECTION INPUT ;
    USE SIGNAL ;
    PORT
      LAYER M5 ;
        RECT  60.144 25.836 60.168 25.92 ;
    END
  END fd_in[335]
  PIN fd_in[336]
    DIRECTION INPUT ;
    USE SIGNAL ;
    PORT
      LAYER M5 ;
        RECT  60.336 25.836 60.36 25.92 ;
    END
  END fd_in[336]
  PIN fd_in[337]
    DIRECTION INPUT ;
    USE SIGNAL ;
    PORT
      LAYER M5 ;
        RECT  60.48 25.836 60.504 25.92 ;
    END
  END fd_in[337]
  PIN fd_in[338]
    DIRECTION INPUT ;
    USE SIGNAL ;
    PORT
      LAYER M5 ;
        RECT  60.672 25.836 60.696 25.92 ;
    END
  END fd_in[338]
  PIN fd_in[339]
    DIRECTION INPUT ;
    USE SIGNAL ;
    PORT
      LAYER M5 ;
        RECT  60.864 25.836 60.888 25.92 ;
    END
  END fd_in[339]
  PIN fd_in[33]
    DIRECTION INPUT ;
    USE SIGNAL ;
    PORT
      LAYER M5 ;
        RECT  5.952 25.836 5.976 25.92 ;
    END
  END fd_in[33]
  PIN fd_in[340]
    DIRECTION INPUT ;
    USE SIGNAL ;
    PORT
      LAYER M5 ;
        RECT  61.008 25.836 61.032 25.92 ;
    END
  END fd_in[340]
  PIN fd_in[341]
    DIRECTION INPUT ;
    USE SIGNAL ;
    PORT
      LAYER M5 ;
        RECT  61.2 25.836 61.224 25.92 ;
    END
  END fd_in[341]
  PIN fd_in[342]
    DIRECTION INPUT ;
    USE SIGNAL ;
    PORT
      LAYER M5 ;
        RECT  61.392 25.836 61.416 25.92 ;
    END
  END fd_in[342]
  PIN fd_in[343]
    DIRECTION INPUT ;
    USE SIGNAL ;
    PORT
      LAYER M5 ;
        RECT  61.584 25.836 61.608 25.92 ;
    END
  END fd_in[343]
  PIN fd_in[344]
    DIRECTION INPUT ;
    USE SIGNAL ;
    PORT
      LAYER M5 ;
        RECT  61.728 25.836 61.752 25.92 ;
    END
  END fd_in[344]
  PIN fd_in[345]
    DIRECTION INPUT ;
    USE SIGNAL ;
    PORT
      LAYER M5 ;
        RECT  61.92 25.836 61.944 25.92 ;
    END
  END fd_in[345]
  PIN fd_in[346]
    DIRECTION INPUT ;
    USE SIGNAL ;
    PORT
      LAYER M5 ;
        RECT  62.112 25.836 62.136 25.92 ;
    END
  END fd_in[346]
  PIN fd_in[347]
    DIRECTION INPUT ;
    USE SIGNAL ;
    PORT
      LAYER M5 ;
        RECT  62.304 25.836 62.328 25.92 ;
    END
  END fd_in[347]
  PIN fd_in[348]
    DIRECTION INPUT ;
    USE SIGNAL ;
    PORT
      LAYER M5 ;
        RECT  62.448 25.836 62.472 25.92 ;
    END
  END fd_in[348]
  PIN fd_in[349]
    DIRECTION INPUT ;
    USE SIGNAL ;
    PORT
      LAYER M5 ;
        RECT  62.64 25.836 62.664 25.92 ;
    END
  END fd_in[349]
  PIN fd_in[34]
    DIRECTION INPUT ;
    USE SIGNAL ;
    PORT
      LAYER M5 ;
        RECT  6.144 25.836 6.168 25.92 ;
    END
  END fd_in[34]
  PIN fd_in[350]
    DIRECTION INPUT ;
    USE SIGNAL ;
    PORT
      LAYER M5 ;
        RECT  62.832 25.836 62.856 25.92 ;
    END
  END fd_in[350]
  PIN fd_in[351]
    DIRECTION INPUT ;
    USE SIGNAL ;
    PORT
      LAYER M5 ;
        RECT  63.024 25.836 63.048 25.92 ;
    END
  END fd_in[351]
  PIN fd_in[352]
    DIRECTION INPUT ;
    USE SIGNAL ;
    PORT
      LAYER M5 ;
        RECT  63.168 25.836 63.192 25.92 ;
    END
  END fd_in[352]
  PIN fd_in[353]
    DIRECTION INPUT ;
    USE SIGNAL ;
    PORT
      LAYER M5 ;
        RECT  63.36 25.836 63.384 25.92 ;
    END
  END fd_in[353]
  PIN fd_in[354]
    DIRECTION INPUT ;
    USE SIGNAL ;
    PORT
      LAYER M5 ;
        RECT  63.552 25.836 63.576 25.92 ;
    END
  END fd_in[354]
  PIN fd_in[355]
    DIRECTION INPUT ;
    USE SIGNAL ;
    PORT
      LAYER M5 ;
        RECT  63.744 25.836 63.768 25.92 ;
    END
  END fd_in[355]
  PIN fd_in[356]
    DIRECTION INPUT ;
    USE SIGNAL ;
    PORT
      LAYER M5 ;
        RECT  63.888 25.836 63.912 25.92 ;
    END
  END fd_in[356]
  PIN fd_in[357]
    DIRECTION INPUT ;
    USE SIGNAL ;
    PORT
      LAYER M5 ;
        RECT  64.08 25.836 64.104 25.92 ;
    END
  END fd_in[357]
  PIN fd_in[358]
    DIRECTION INPUT ;
    USE SIGNAL ;
    PORT
      LAYER M5 ;
        RECT  64.272 25.836 64.296 25.92 ;
    END
  END fd_in[358]
  PIN fd_in[359]
    DIRECTION INPUT ;
    USE SIGNAL ;
    PORT
      LAYER M5 ;
        RECT  64.416 25.836 64.44 25.92 ;
    END
  END fd_in[359]
  PIN fd_in[35]
    DIRECTION INPUT ;
    USE SIGNAL ;
    PORT
      LAYER M5 ;
        RECT  6.336 25.836 6.36 25.92 ;
    END
  END fd_in[35]
  PIN fd_in[360]
    DIRECTION INPUT ;
    USE SIGNAL ;
    PORT
      LAYER M5 ;
        RECT  64.608 25.836 64.632 25.92 ;
    END
  END fd_in[360]
  PIN fd_in[361]
    DIRECTION INPUT ;
    USE SIGNAL ;
    PORT
      LAYER M5 ;
        RECT  64.8 25.836 64.824 25.92 ;
    END
  END fd_in[361]
  PIN fd_in[362]
    DIRECTION INPUT ;
    USE SIGNAL ;
    PORT
      LAYER M5 ;
        RECT  64.992 25.836 65.016 25.92 ;
    END
  END fd_in[362]
  PIN fd_in[363]
    DIRECTION INPUT ;
    USE SIGNAL ;
    PORT
      LAYER M5 ;
        RECT  65.136 25.836 65.16 25.92 ;
    END
  END fd_in[363]
  PIN fd_in[364]
    DIRECTION INPUT ;
    USE SIGNAL ;
    PORT
      LAYER M5 ;
        RECT  65.328 25.836 65.352 25.92 ;
    END
  END fd_in[364]
  PIN fd_in[365]
    DIRECTION INPUT ;
    USE SIGNAL ;
    PORT
      LAYER M5 ;
        RECT  65.52 25.836 65.544 25.92 ;
    END
  END fd_in[365]
  PIN fd_in[366]
    DIRECTION INPUT ;
    USE SIGNAL ;
    PORT
      LAYER M5 ;
        RECT  65.712 25.836 65.736 25.92 ;
    END
  END fd_in[366]
  PIN fd_in[367]
    DIRECTION INPUT ;
    USE SIGNAL ;
    PORT
      LAYER M5 ;
        RECT  65.856 25.836 65.88 25.92 ;
    END
  END fd_in[367]
  PIN fd_in[368]
    DIRECTION INPUT ;
    USE SIGNAL ;
    PORT
      LAYER M5 ;
        RECT  66.048 25.836 66.072 25.92 ;
    END
  END fd_in[368]
  PIN fd_in[369]
    DIRECTION INPUT ;
    USE SIGNAL ;
    PORT
      LAYER M5 ;
        RECT  66.24 25.836 66.264 25.92 ;
    END
  END fd_in[369]
  PIN fd_in[36]
    DIRECTION INPUT ;
    USE SIGNAL ;
    PORT
      LAYER M5 ;
        RECT  6.528 25.836 6.552 25.92 ;
    END
  END fd_in[36]
  PIN fd_in[370]
    DIRECTION INPUT ;
    USE SIGNAL ;
    PORT
      LAYER M5 ;
        RECT  66.432 25.836 66.456 25.92 ;
    END
  END fd_in[370]
  PIN fd_in[371]
    DIRECTION INPUT ;
    USE SIGNAL ;
    PORT
      LAYER M5 ;
        RECT  66.576 25.836 66.6 25.92 ;
    END
  END fd_in[371]
  PIN fd_in[372]
    DIRECTION INPUT ;
    USE SIGNAL ;
    PORT
      LAYER M5 ;
        RECT  66.768 25.836 66.792 25.92 ;
    END
  END fd_in[372]
  PIN fd_in[373]
    DIRECTION INPUT ;
    USE SIGNAL ;
    PORT
      LAYER M5 ;
        RECT  66.96 25.836 66.984 25.92 ;
    END
  END fd_in[373]
  PIN fd_in[374]
    DIRECTION INPUT ;
    USE SIGNAL ;
    PORT
      LAYER M5 ;
        RECT  67.152 25.836 67.176 25.92 ;
    END
  END fd_in[374]
  PIN fd_in[375]
    DIRECTION INPUT ;
    USE SIGNAL ;
    PORT
      LAYER M5 ;
        RECT  67.296 25.836 67.32 25.92 ;
    END
  END fd_in[375]
  PIN fd_in[376]
    DIRECTION INPUT ;
    USE SIGNAL ;
    PORT
      LAYER M5 ;
        RECT  67.488 25.836 67.512 25.92 ;
    END
  END fd_in[376]
  PIN fd_in[377]
    DIRECTION INPUT ;
    USE SIGNAL ;
    PORT
      LAYER M5 ;
        RECT  67.68 25.836 67.704 25.92 ;
    END
  END fd_in[377]
  PIN fd_in[378]
    DIRECTION INPUT ;
    USE SIGNAL ;
    PORT
      LAYER M5 ;
        RECT  67.824 25.836 67.848 25.92 ;
    END
  END fd_in[378]
  PIN fd_in[379]
    DIRECTION INPUT ;
    USE SIGNAL ;
    PORT
      LAYER M5 ;
        RECT  68.016 25.836 68.04 25.92 ;
    END
  END fd_in[379]
  PIN fd_in[37]
    DIRECTION INPUT ;
    USE SIGNAL ;
    PORT
      LAYER M5 ;
        RECT  6.672 25.836 6.696 25.92 ;
    END
  END fd_in[37]
  PIN fd_in[380]
    DIRECTION INPUT ;
    USE SIGNAL ;
    PORT
      LAYER M5 ;
        RECT  68.208 25.836 68.232 25.92 ;
    END
  END fd_in[380]
  PIN fd_in[381]
    DIRECTION INPUT ;
    USE SIGNAL ;
    PORT
      LAYER M5 ;
        RECT  68.4 25.836 68.424 25.92 ;
    END
  END fd_in[381]
  PIN fd_in[382]
    DIRECTION INPUT ;
    USE SIGNAL ;
    PORT
      LAYER M5 ;
        RECT  68.544 25.836 68.568 25.92 ;
    END
  END fd_in[382]
  PIN fd_in[383]
    DIRECTION INPUT ;
    USE SIGNAL ;
    PORT
      LAYER M5 ;
        RECT  68.736 25.836 68.76 25.92 ;
    END
  END fd_in[383]
  PIN fd_in[384]
    DIRECTION INPUT ;
    USE SIGNAL ;
    PORT
      LAYER M5 ;
        RECT  68.928 25.836 68.952 25.92 ;
    END
  END fd_in[384]
  PIN fd_in[385]
    DIRECTION INPUT ;
    USE SIGNAL ;
    PORT
      LAYER M5 ;
        RECT  69.12 25.836 69.144 25.92 ;
    END
  END fd_in[385]
  PIN fd_in[386]
    DIRECTION INPUT ;
    USE SIGNAL ;
    PORT
      LAYER M5 ;
        RECT  69.264 25.836 69.288 25.92 ;
    END
  END fd_in[386]
  PIN fd_in[387]
    DIRECTION INPUT ;
    USE SIGNAL ;
    PORT
      LAYER M5 ;
        RECT  69.456 25.836 69.48 25.92 ;
    END
  END fd_in[387]
  PIN fd_in[388]
    DIRECTION INPUT ;
    USE SIGNAL ;
    PORT
      LAYER M5 ;
        RECT  69.648 25.836 69.672 25.92 ;
    END
  END fd_in[388]
  PIN fd_in[389]
    DIRECTION INPUT ;
    USE SIGNAL ;
    PORT
      LAYER M5 ;
        RECT  69.84 25.836 69.864 25.92 ;
    END
  END fd_in[389]
  PIN fd_in[38]
    DIRECTION INPUT ;
    USE SIGNAL ;
    PORT
      LAYER M5 ;
        RECT  6.864 25.836 6.888 25.92 ;
    END
  END fd_in[38]
  PIN fd_in[390]
    DIRECTION INPUT ;
    USE SIGNAL ;
    PORT
      LAYER M5 ;
        RECT  69.984 25.836 70.008 25.92 ;
    END
  END fd_in[390]
  PIN fd_in[391]
    DIRECTION INPUT ;
    USE SIGNAL ;
    PORT
      LAYER M5 ;
        RECT  70.176 25.836 70.2 25.92 ;
    END
  END fd_in[391]
  PIN fd_in[392]
    DIRECTION INPUT ;
    USE SIGNAL ;
    PORT
      LAYER M5 ;
        RECT  70.368 25.836 70.392 25.92 ;
    END
  END fd_in[392]
  PIN fd_in[393]
    DIRECTION INPUT ;
    USE SIGNAL ;
    PORT
      LAYER M5 ;
        RECT  70.56 25.836 70.584 25.92 ;
    END
  END fd_in[393]
  PIN fd_in[394]
    DIRECTION INPUT ;
    USE SIGNAL ;
    PORT
      LAYER M5 ;
        RECT  70.704 25.836 70.728 25.92 ;
    END
  END fd_in[394]
  PIN fd_in[395]
    DIRECTION INPUT ;
    USE SIGNAL ;
    PORT
      LAYER M5 ;
        RECT  70.896 25.836 70.92 25.92 ;
    END
  END fd_in[395]
  PIN fd_in[396]
    DIRECTION INPUT ;
    USE SIGNAL ;
    PORT
      LAYER M5 ;
        RECT  71.088 25.836 71.112 25.92 ;
    END
  END fd_in[396]
  PIN fd_in[397]
    DIRECTION INPUT ;
    USE SIGNAL ;
    PORT
      LAYER M5 ;
        RECT  71.232 25.836 71.256 25.92 ;
    END
  END fd_in[397]
  PIN fd_in[398]
    DIRECTION INPUT ;
    USE SIGNAL ;
    PORT
      LAYER M5 ;
        RECT  71.424 25.836 71.448 25.92 ;
    END
  END fd_in[398]
  PIN fd_in[399]
    DIRECTION INPUT ;
    USE SIGNAL ;
    PORT
      LAYER M5 ;
        RECT  71.616 25.836 71.64 25.92 ;
    END
  END fd_in[399]
  PIN fd_in[39]
    DIRECTION INPUT ;
    USE SIGNAL ;
    PORT
      LAYER M5 ;
        RECT  7.056 25.836 7.08 25.92 ;
    END
  END fd_in[39]
  PIN fd_in[3]
    DIRECTION INPUT ;
    USE SIGNAL ;
    PORT
      LAYER M5 ;
        RECT  0.576 25.836 0.6 25.92 ;
    END
  END fd_in[3]
  PIN fd_in[400]
    DIRECTION INPUT ;
    USE SIGNAL ;
    PORT
      LAYER M5 ;
        RECT  71.808 25.836 71.832 25.92 ;
    END
  END fd_in[400]
  PIN fd_in[401]
    DIRECTION INPUT ;
    USE SIGNAL ;
    PORT
      LAYER M5 ;
        RECT  71.952 25.836 71.976 25.92 ;
    END
  END fd_in[401]
  PIN fd_in[402]
    DIRECTION INPUT ;
    USE SIGNAL ;
    PORT
      LAYER M5 ;
        RECT  72.144 25.836 72.168 25.92 ;
    END
  END fd_in[402]
  PIN fd_in[403]
    DIRECTION INPUT ;
    USE SIGNAL ;
    PORT
      LAYER M5 ;
        RECT  72.336 25.836 72.36 25.92 ;
    END
  END fd_in[403]
  PIN fd_in[404]
    DIRECTION INPUT ;
    USE SIGNAL ;
    PORT
      LAYER M5 ;
        RECT  72.528 25.836 72.552 25.92 ;
    END
  END fd_in[404]
  PIN fd_in[405]
    DIRECTION INPUT ;
    USE SIGNAL ;
    PORT
      LAYER M5 ;
        RECT  72.672 25.836 72.696 25.92 ;
    END
  END fd_in[405]
  PIN fd_in[406]
    DIRECTION INPUT ;
    USE SIGNAL ;
    PORT
      LAYER M5 ;
        RECT  72.864 25.836 72.888 25.92 ;
    END
  END fd_in[406]
  PIN fd_in[407]
    DIRECTION INPUT ;
    USE SIGNAL ;
    PORT
      LAYER M5 ;
        RECT  73.056 25.836 73.08 25.92 ;
    END
  END fd_in[407]
  PIN fd_in[408]
    DIRECTION INPUT ;
    USE SIGNAL ;
    PORT
      LAYER M5 ;
        RECT  73.248 25.836 73.272 25.92 ;
    END
  END fd_in[408]
  PIN fd_in[409]
    DIRECTION INPUT ;
    USE SIGNAL ;
    PORT
      LAYER M5 ;
        RECT  73.392 25.836 73.416 25.92 ;
    END
  END fd_in[409]
  PIN fd_in[40]
    DIRECTION INPUT ;
    USE SIGNAL ;
    PORT
      LAYER M5 ;
        RECT  7.248 25.836 7.272 25.92 ;
    END
  END fd_in[40]
  PIN fd_in[410]
    DIRECTION INPUT ;
    USE SIGNAL ;
    PORT
      LAYER M5 ;
        RECT  73.584 25.836 73.608 25.92 ;
    END
  END fd_in[410]
  PIN fd_in[411]
    DIRECTION INPUT ;
    USE SIGNAL ;
    PORT
      LAYER M5 ;
        RECT  73.776 25.836 73.8 25.92 ;
    END
  END fd_in[411]
  PIN fd_in[412]
    DIRECTION INPUT ;
    USE SIGNAL ;
    PORT
      LAYER M5 ;
        RECT  73.92 25.836 73.944 25.92 ;
    END
  END fd_in[412]
  PIN fd_in[413]
    DIRECTION INPUT ;
    USE SIGNAL ;
    PORT
      LAYER M5 ;
        RECT  74.112 25.836 74.136 25.92 ;
    END
  END fd_in[413]
  PIN fd_in[414]
    DIRECTION INPUT ;
    USE SIGNAL ;
    PORT
      LAYER M5 ;
        RECT  74.304 25.836 74.328 25.92 ;
    END
  END fd_in[414]
  PIN fd_in[415]
    DIRECTION INPUT ;
    USE SIGNAL ;
    PORT
      LAYER M5 ;
        RECT  74.496 25.836 74.52 25.92 ;
    END
  END fd_in[415]
  PIN fd_in[416]
    DIRECTION INPUT ;
    USE SIGNAL ;
    PORT
      LAYER M5 ;
        RECT  74.64 25.836 74.664 25.92 ;
    END
  END fd_in[416]
  PIN fd_in[417]
    DIRECTION INPUT ;
    USE SIGNAL ;
    PORT
      LAYER M5 ;
        RECT  74.832 25.836 74.856 25.92 ;
    END
  END fd_in[417]
  PIN fd_in[418]
    DIRECTION INPUT ;
    USE SIGNAL ;
    PORT
      LAYER M5 ;
        RECT  75.024 25.836 75.048 25.92 ;
    END
  END fd_in[418]
  PIN fd_in[419]
    DIRECTION INPUT ;
    USE SIGNAL ;
    PORT
      LAYER M5 ;
        RECT  75.216 25.836 75.24 25.92 ;
    END
  END fd_in[419]
  PIN fd_in[41]
    DIRECTION INPUT ;
    USE SIGNAL ;
    PORT
      LAYER M5 ;
        RECT  7.392 25.836 7.416 25.92 ;
    END
  END fd_in[41]
  PIN fd_in[420]
    DIRECTION INPUT ;
    USE SIGNAL ;
    PORT
      LAYER M5 ;
        RECT  75.36 25.836 75.384 25.92 ;
    END
  END fd_in[420]
  PIN fd_in[421]
    DIRECTION INPUT ;
    USE SIGNAL ;
    PORT
      LAYER M5 ;
        RECT  75.552 25.836 75.576 25.92 ;
    END
  END fd_in[421]
  PIN fd_in[422]
    DIRECTION INPUT ;
    USE SIGNAL ;
    PORT
      LAYER M5 ;
        RECT  75.744 25.836 75.768 25.92 ;
    END
  END fd_in[422]
  PIN fd_in[423]
    DIRECTION INPUT ;
    USE SIGNAL ;
    PORT
      LAYER M5 ;
        RECT  75.936 25.836 75.96 25.92 ;
    END
  END fd_in[423]
  PIN fd_in[424]
    DIRECTION INPUT ;
    USE SIGNAL ;
    PORT
      LAYER M5 ;
        RECT  76.08 25.836 76.104 25.92 ;
    END
  END fd_in[424]
  PIN fd_in[425]
    DIRECTION INPUT ;
    USE SIGNAL ;
    PORT
      LAYER M5 ;
        RECT  76.272 25.836 76.296 25.92 ;
    END
  END fd_in[425]
  PIN fd_in[426]
    DIRECTION INPUT ;
    USE SIGNAL ;
    PORT
      LAYER M5 ;
        RECT  76.464 25.836 76.488 25.92 ;
    END
  END fd_in[426]
  PIN fd_in[427]
    DIRECTION INPUT ;
    USE SIGNAL ;
    PORT
      LAYER M5 ;
        RECT  76.656 25.836 76.68 25.92 ;
    END
  END fd_in[427]
  PIN fd_in[428]
    DIRECTION INPUT ;
    USE SIGNAL ;
    PORT
      LAYER M5 ;
        RECT  76.8 25.836 76.824 25.92 ;
    END
  END fd_in[428]
  PIN fd_in[429]
    DIRECTION INPUT ;
    USE SIGNAL ;
    PORT
      LAYER M5 ;
        RECT  76.992 25.836 77.016 25.92 ;
    END
  END fd_in[429]
  PIN fd_in[42]
    DIRECTION INPUT ;
    USE SIGNAL ;
    PORT
      LAYER M5 ;
        RECT  7.584 25.836 7.608 25.92 ;
    END
  END fd_in[42]
  PIN fd_in[430]
    DIRECTION INPUT ;
    USE SIGNAL ;
    PORT
      LAYER M5 ;
        RECT  77.184 25.836 77.208 25.92 ;
    END
  END fd_in[430]
  PIN fd_in[431]
    DIRECTION INPUT ;
    USE SIGNAL ;
    PORT
      LAYER M5 ;
        RECT  77.328 25.836 77.352 25.92 ;
    END
  END fd_in[431]
  PIN fd_in[432]
    DIRECTION INPUT ;
    USE SIGNAL ;
    PORT
      LAYER M5 ;
        RECT  77.52 25.836 77.544 25.92 ;
    END
  END fd_in[432]
  PIN fd_in[433]
    DIRECTION INPUT ;
    USE SIGNAL ;
    PORT
      LAYER M5 ;
        RECT  77.712 25.836 77.736 25.92 ;
    END
  END fd_in[433]
  PIN fd_in[434]
    DIRECTION INPUT ;
    USE SIGNAL ;
    PORT
      LAYER M5 ;
        RECT  77.904 25.836 77.928 25.92 ;
    END
  END fd_in[434]
  PIN fd_in[435]
    DIRECTION INPUT ;
    USE SIGNAL ;
    PORT
      LAYER M5 ;
        RECT  78.048 25.836 78.072 25.92 ;
    END
  END fd_in[435]
  PIN fd_in[436]
    DIRECTION INPUT ;
    USE SIGNAL ;
    PORT
      LAYER M5 ;
        RECT  78.24 25.836 78.264 25.92 ;
    END
  END fd_in[436]
  PIN fd_in[437]
    DIRECTION INPUT ;
    USE SIGNAL ;
    PORT
      LAYER M5 ;
        RECT  78.432 25.836 78.456 25.92 ;
    END
  END fd_in[437]
  PIN fd_in[438]
    DIRECTION INPUT ;
    USE SIGNAL ;
    PORT
      LAYER M5 ;
        RECT  78.624 25.836 78.648 25.92 ;
    END
  END fd_in[438]
  PIN fd_in[439]
    DIRECTION INPUT ;
    USE SIGNAL ;
    PORT
      LAYER M5 ;
        RECT  78.768 25.836 78.792 25.92 ;
    END
  END fd_in[439]
  PIN fd_in[43]
    DIRECTION INPUT ;
    USE SIGNAL ;
    PORT
      LAYER M5 ;
        RECT  7.776 25.836 7.8 25.92 ;
    END
  END fd_in[43]
  PIN fd_in[440]
    DIRECTION INPUT ;
    USE SIGNAL ;
    PORT
      LAYER M5 ;
        RECT  78.96 25.836 78.984 25.92 ;
    END
  END fd_in[440]
  PIN fd_in[441]
    DIRECTION INPUT ;
    USE SIGNAL ;
    PORT
      LAYER M5 ;
        RECT  79.152 25.836 79.176 25.92 ;
    END
  END fd_in[441]
  PIN fd_in[442]
    DIRECTION INPUT ;
    USE SIGNAL ;
    PORT
      LAYER M5 ;
        RECT  79.344 25.836 79.368 25.92 ;
    END
  END fd_in[442]
  PIN fd_in[443]
    DIRECTION INPUT ;
    USE SIGNAL ;
    PORT
      LAYER M5 ;
        RECT  79.488 25.836 79.512 25.92 ;
    END
  END fd_in[443]
  PIN fd_in[444]
    DIRECTION INPUT ;
    USE SIGNAL ;
    PORT
      LAYER M5 ;
        RECT  79.68 25.836 79.704 25.92 ;
    END
  END fd_in[444]
  PIN fd_in[445]
    DIRECTION INPUT ;
    USE SIGNAL ;
    PORT
      LAYER M5 ;
        RECT  79.872 25.836 79.896 25.92 ;
    END
  END fd_in[445]
  PIN fd_in[446]
    DIRECTION INPUT ;
    USE SIGNAL ;
    PORT
      LAYER M5 ;
        RECT  80.064 25.836 80.088 25.92 ;
    END
  END fd_in[446]
  PIN fd_in[447]
    DIRECTION INPUT ;
    USE SIGNAL ;
    PORT
      LAYER M5 ;
        RECT  80.208 25.836 80.232 25.92 ;
    END
  END fd_in[447]
  PIN fd_in[448]
    DIRECTION INPUT ;
    USE SIGNAL ;
    PORT
      LAYER M5 ;
        RECT  80.4 25.836 80.424 25.92 ;
    END
  END fd_in[448]
  PIN fd_in[449]
    DIRECTION INPUT ;
    USE SIGNAL ;
    PORT
      LAYER M5 ;
        RECT  80.592 25.836 80.616 25.92 ;
    END
  END fd_in[449]
  PIN fd_in[44]
    DIRECTION INPUT ;
    USE SIGNAL ;
    PORT
      LAYER M5 ;
        RECT  7.968 25.836 7.992 25.92 ;
    END
  END fd_in[44]
  PIN fd_in[450]
    DIRECTION INPUT ;
    USE SIGNAL ;
    PORT
      LAYER M5 ;
        RECT  80.736 25.836 80.76 25.92 ;
    END
  END fd_in[450]
  PIN fd_in[451]
    DIRECTION INPUT ;
    USE SIGNAL ;
    PORT
      LAYER M5 ;
        RECT  80.928 25.836 80.952 25.92 ;
    END
  END fd_in[451]
  PIN fd_in[452]
    DIRECTION INPUT ;
    USE SIGNAL ;
    PORT
      LAYER M5 ;
        RECT  81.12 25.836 81.144 25.92 ;
    END
  END fd_in[452]
  PIN fd_in[453]
    DIRECTION INPUT ;
    USE SIGNAL ;
    PORT
      LAYER M5 ;
        RECT  81.312 25.836 81.336 25.92 ;
    END
  END fd_in[453]
  PIN fd_in[454]
    DIRECTION INPUT ;
    USE SIGNAL ;
    PORT
      LAYER M5 ;
        RECT  81.456 25.836 81.48 25.92 ;
    END
  END fd_in[454]
  PIN fd_in[455]
    DIRECTION INPUT ;
    USE SIGNAL ;
    PORT
      LAYER M5 ;
        RECT  81.648 25.836 81.672 25.92 ;
    END
  END fd_in[455]
  PIN fd_in[456]
    DIRECTION INPUT ;
    USE SIGNAL ;
    PORT
      LAYER M5 ;
        RECT  81.84 25.836 81.864 25.92 ;
    END
  END fd_in[456]
  PIN fd_in[457]
    DIRECTION INPUT ;
    USE SIGNAL ;
    PORT
      LAYER M5 ;
        RECT  82.032 25.836 82.056 25.92 ;
    END
  END fd_in[457]
  PIN fd_in[458]
    DIRECTION INPUT ;
    USE SIGNAL ;
    PORT
      LAYER M5 ;
        RECT  82.176 25.836 82.2 25.92 ;
    END
  END fd_in[458]
  PIN fd_in[459]
    DIRECTION INPUT ;
    USE SIGNAL ;
    PORT
      LAYER M5 ;
        RECT  82.368 25.836 82.392 25.92 ;
    END
  END fd_in[459]
  PIN fd_in[45]
    DIRECTION INPUT ;
    USE SIGNAL ;
    PORT
      LAYER M5 ;
        RECT  8.112 25.836 8.136 25.92 ;
    END
  END fd_in[45]
  PIN fd_in[460]
    DIRECTION INPUT ;
    USE SIGNAL ;
    PORT
      LAYER M5 ;
        RECT  82.56 25.836 82.584 25.92 ;
    END
  END fd_in[460]
  PIN fd_in[461]
    DIRECTION INPUT ;
    USE SIGNAL ;
    PORT
      LAYER M5 ;
        RECT  82.752 25.836 82.776 25.92 ;
    END
  END fd_in[461]
  PIN fd_in[462]
    DIRECTION INPUT ;
    USE SIGNAL ;
    PORT
      LAYER M5 ;
        RECT  82.896 25.836 82.92 25.92 ;
    END
  END fd_in[462]
  PIN fd_in[463]
    DIRECTION INPUT ;
    USE SIGNAL ;
    PORT
      LAYER M5 ;
        RECT  83.088 25.836 83.112 25.92 ;
    END
  END fd_in[463]
  PIN fd_in[464]
    DIRECTION INPUT ;
    USE SIGNAL ;
    PORT
      LAYER M5 ;
        RECT  83.28 25.836 83.304 25.92 ;
    END
  END fd_in[464]
  PIN fd_in[465]
    DIRECTION INPUT ;
    USE SIGNAL ;
    PORT
      LAYER M5 ;
        RECT  83.472 25.836 83.496 25.92 ;
    END
  END fd_in[465]
  PIN fd_in[466]
    DIRECTION INPUT ;
    USE SIGNAL ;
    PORT
      LAYER M5 ;
        RECT  83.616 25.836 83.64 25.92 ;
    END
  END fd_in[466]
  PIN fd_in[467]
    DIRECTION INPUT ;
    USE SIGNAL ;
    PORT
      LAYER M5 ;
        RECT  83.808 25.836 83.832 25.92 ;
    END
  END fd_in[467]
  PIN fd_in[468]
    DIRECTION INPUT ;
    USE SIGNAL ;
    PORT
      LAYER M5 ;
        RECT  84 25.836 84.024 25.92 ;
    END
  END fd_in[468]
  PIN fd_in[469]
    DIRECTION INPUT ;
    USE SIGNAL ;
    PORT
      LAYER M5 ;
        RECT  84.144 25.836 84.168 25.92 ;
    END
  END fd_in[469]
  PIN fd_in[46]
    DIRECTION INPUT ;
    USE SIGNAL ;
    PORT
      LAYER M5 ;
        RECT  8.304 25.836 8.328 25.92 ;
    END
  END fd_in[46]
  PIN fd_in[470]
    DIRECTION INPUT ;
    USE SIGNAL ;
    PORT
      LAYER M5 ;
        RECT  84.336 25.836 84.36 25.92 ;
    END
  END fd_in[470]
  PIN fd_in[471]
    DIRECTION INPUT ;
    USE SIGNAL ;
    PORT
      LAYER M5 ;
        RECT  84.528 25.836 84.552 25.92 ;
    END
  END fd_in[471]
  PIN fd_in[472]
    DIRECTION INPUT ;
    USE SIGNAL ;
    PORT
      LAYER M5 ;
        RECT  84.72 25.836 84.744 25.92 ;
    END
  END fd_in[472]
  PIN fd_in[473]
    DIRECTION INPUT ;
    USE SIGNAL ;
    PORT
      LAYER M5 ;
        RECT  84.864 25.836 84.888 25.92 ;
    END
  END fd_in[473]
  PIN fd_in[474]
    DIRECTION INPUT ;
    USE SIGNAL ;
    PORT
      LAYER M5 ;
        RECT  85.056 25.836 85.08 25.92 ;
    END
  END fd_in[474]
  PIN fd_in[475]
    DIRECTION INPUT ;
    USE SIGNAL ;
    PORT
      LAYER M5 ;
        RECT  85.248 25.836 85.272 25.92 ;
    END
  END fd_in[475]
  PIN fd_in[476]
    DIRECTION INPUT ;
    USE SIGNAL ;
    PORT
      LAYER M5 ;
        RECT  85.44 25.836 85.464 25.92 ;
    END
  END fd_in[476]
  PIN fd_in[477]
    DIRECTION INPUT ;
    USE SIGNAL ;
    PORT
      LAYER M5 ;
        RECT  85.584 25.836 85.608 25.92 ;
    END
  END fd_in[477]
  PIN fd_in[478]
    DIRECTION INPUT ;
    USE SIGNAL ;
    PORT
      LAYER M5 ;
        RECT  85.776 25.836 85.8 25.92 ;
    END
  END fd_in[478]
  PIN fd_in[479]
    DIRECTION INPUT ;
    USE SIGNAL ;
    PORT
      LAYER M5 ;
        RECT  85.968 25.836 85.992 25.92 ;
    END
  END fd_in[479]
  PIN fd_in[47]
    DIRECTION INPUT ;
    USE SIGNAL ;
    PORT
      LAYER M5 ;
        RECT  8.496 25.836 8.52 25.92 ;
    END
  END fd_in[47]
  PIN fd_in[480]
    DIRECTION INPUT ;
    USE SIGNAL ;
    PORT
      LAYER M5 ;
        RECT  86.16 25.836 86.184 25.92 ;
    END
  END fd_in[480]
  PIN fd_in[481]
    DIRECTION INPUT ;
    USE SIGNAL ;
    PORT
      LAYER M5 ;
        RECT  86.304 25.836 86.328 25.92 ;
    END
  END fd_in[481]
  PIN fd_in[482]
    DIRECTION INPUT ;
    USE SIGNAL ;
    PORT
      LAYER M5 ;
        RECT  86.496 25.836 86.52 25.92 ;
    END
  END fd_in[482]
  PIN fd_in[483]
    DIRECTION INPUT ;
    USE SIGNAL ;
    PORT
      LAYER M5 ;
        RECT  86.688 25.836 86.712 25.92 ;
    END
  END fd_in[483]
  PIN fd_in[484]
    DIRECTION INPUT ;
    USE SIGNAL ;
    PORT
      LAYER M5 ;
        RECT  86.88 25.836 86.904 25.92 ;
    END
  END fd_in[484]
  PIN fd_in[485]
    DIRECTION INPUT ;
    USE SIGNAL ;
    PORT
      LAYER M5 ;
        RECT  87.024 25.836 87.048 25.92 ;
    END
  END fd_in[485]
  PIN fd_in[486]
    DIRECTION INPUT ;
    USE SIGNAL ;
    PORT
      LAYER M5 ;
        RECT  87.216 25.836 87.24 25.92 ;
    END
  END fd_in[486]
  PIN fd_in[487]
    DIRECTION INPUT ;
    USE SIGNAL ;
    PORT
      LAYER M5 ;
        RECT  87.408 25.836 87.432 25.92 ;
    END
  END fd_in[487]
  PIN fd_in[488]
    DIRECTION INPUT ;
    USE SIGNAL ;
    PORT
      LAYER M5 ;
        RECT  87.552 25.836 87.576 25.92 ;
    END
  END fd_in[488]
  PIN fd_in[489]
    DIRECTION INPUT ;
    USE SIGNAL ;
    PORT
      LAYER M5 ;
        RECT  87.744 25.836 87.768 25.92 ;
    END
  END fd_in[489]
  PIN fd_in[48]
    DIRECTION INPUT ;
    USE SIGNAL ;
    PORT
      LAYER M5 ;
        RECT  8.64 25.836 8.664 25.92 ;
    END
  END fd_in[48]
  PIN fd_in[490]
    DIRECTION INPUT ;
    USE SIGNAL ;
    PORT
      LAYER M5 ;
        RECT  87.936 25.836 87.96 25.92 ;
    END
  END fd_in[490]
  PIN fd_in[491]
    DIRECTION INPUT ;
    USE SIGNAL ;
    PORT
      LAYER M5 ;
        RECT  88.128 25.836 88.152 25.92 ;
    END
  END fd_in[491]
  PIN fd_in[492]
    DIRECTION INPUT ;
    USE SIGNAL ;
    PORT
      LAYER M5 ;
        RECT  88.272 25.836 88.296 25.92 ;
    END
  END fd_in[492]
  PIN fd_in[493]
    DIRECTION INPUT ;
    USE SIGNAL ;
    PORT
      LAYER M5 ;
        RECT  88.464 25.836 88.488 25.92 ;
    END
  END fd_in[493]
  PIN fd_in[494]
    DIRECTION INPUT ;
    USE SIGNAL ;
    PORT
      LAYER M5 ;
        RECT  88.656 25.836 88.68 25.92 ;
    END
  END fd_in[494]
  PIN fd_in[495]
    DIRECTION INPUT ;
    USE SIGNAL ;
    PORT
      LAYER M5 ;
        RECT  88.848 25.836 88.872 25.92 ;
    END
  END fd_in[495]
  PIN fd_in[496]
    DIRECTION INPUT ;
    USE SIGNAL ;
    PORT
      LAYER M5 ;
        RECT  88.992 25.836 89.016 25.92 ;
    END
  END fd_in[496]
  PIN fd_in[497]
    DIRECTION INPUT ;
    USE SIGNAL ;
    PORT
      LAYER M5 ;
        RECT  89.184 25.836 89.208 25.92 ;
    END
  END fd_in[497]
  PIN fd_in[498]
    DIRECTION INPUT ;
    USE SIGNAL ;
    PORT
      LAYER M5 ;
        RECT  89.376 25.836 89.4 25.92 ;
    END
  END fd_in[498]
  PIN fd_in[499]
    DIRECTION INPUT ;
    USE SIGNAL ;
    PORT
      LAYER M5 ;
        RECT  89.568 25.836 89.592 25.92 ;
    END
  END fd_in[499]
  PIN fd_in[49]
    DIRECTION INPUT ;
    USE SIGNAL ;
    PORT
      LAYER M5 ;
        RECT  8.832 25.836 8.856 25.92 ;
    END
  END fd_in[49]
  PIN fd_in[4]
    DIRECTION INPUT ;
    USE SIGNAL ;
    PORT
      LAYER M5 ;
        RECT  0.768 25.836 0.792 25.92 ;
    END
  END fd_in[4]
  PIN fd_in[500]
    DIRECTION INPUT ;
    USE SIGNAL ;
    PORT
      LAYER M5 ;
        RECT  89.712 25.836 89.736 25.92 ;
    END
  END fd_in[500]
  PIN fd_in[501]
    DIRECTION INPUT ;
    USE SIGNAL ;
    PORT
      LAYER M5 ;
        RECT  89.904 25.836 89.928 25.92 ;
    END
  END fd_in[501]
  PIN fd_in[502]
    DIRECTION INPUT ;
    USE SIGNAL ;
    PORT
      LAYER M5 ;
        RECT  90.096 25.836 90.12 25.92 ;
    END
  END fd_in[502]
  PIN fd_in[503]
    DIRECTION INPUT ;
    USE SIGNAL ;
    PORT
      LAYER M5 ;
        RECT  90.288 25.836 90.312 25.92 ;
    END
  END fd_in[503]
  PIN fd_in[504]
    DIRECTION INPUT ;
    USE SIGNAL ;
    PORT
      LAYER M5 ;
        RECT  90.432 25.836 90.456 25.92 ;
    END
  END fd_in[504]
  PIN fd_in[505]
    DIRECTION INPUT ;
    USE SIGNAL ;
    PORT
      LAYER M5 ;
        RECT  90.624 25.836 90.648 25.92 ;
    END
  END fd_in[505]
  PIN fd_in[506]
    DIRECTION INPUT ;
    USE SIGNAL ;
    PORT
      LAYER M5 ;
        RECT  90.816 25.836 90.84 25.92 ;
    END
  END fd_in[506]
  PIN fd_in[507]
    DIRECTION INPUT ;
    USE SIGNAL ;
    PORT
      LAYER M5 ;
        RECT  90.96 25.836 90.984 25.92 ;
    END
  END fd_in[507]
  PIN fd_in[508]
    DIRECTION INPUT ;
    USE SIGNAL ;
    PORT
      LAYER M5 ;
        RECT  91.152 25.836 91.176 25.92 ;
    END
  END fd_in[508]
  PIN fd_in[509]
    DIRECTION INPUT ;
    USE SIGNAL ;
    PORT
      LAYER M5 ;
        RECT  91.344 25.836 91.368 25.92 ;
    END
  END fd_in[509]
  PIN fd_in[50]
    DIRECTION INPUT ;
    USE SIGNAL ;
    PORT
      LAYER M5 ;
        RECT  9.024 25.836 9.048 25.92 ;
    END
  END fd_in[50]
  PIN fd_in[510]
    DIRECTION INPUT ;
    USE SIGNAL ;
    PORT
      LAYER M5 ;
        RECT  91.536 25.836 91.56 25.92 ;
    END
  END fd_in[510]
  PIN fd_in[511]
    DIRECTION INPUT ;
    USE SIGNAL ;
    PORT
      LAYER M5 ;
        RECT  91.68 25.836 91.704 25.92 ;
    END
  END fd_in[511]
  PIN fd_in[512]
    DIRECTION INPUT ;
    USE SIGNAL ;
    PORT
      LAYER M5 ;
        RECT  91.872 25.836 91.896 25.92 ;
    END
  END fd_in[512]
  PIN fd_in[513]
    DIRECTION INPUT ;
    USE SIGNAL ;
    PORT
      LAYER M5 ;
        RECT  92.064 25.836 92.088 25.92 ;
    END
  END fd_in[513]
  PIN fd_in[514]
    DIRECTION INPUT ;
    USE SIGNAL ;
    PORT
      LAYER M5 ;
        RECT  92.256 25.836 92.28 25.92 ;
    END
  END fd_in[514]
  PIN fd_in[515]
    DIRECTION INPUT ;
    USE SIGNAL ;
    PORT
      LAYER M5 ;
        RECT  92.4 25.836 92.424 25.92 ;
    END
  END fd_in[515]
  PIN fd_in[516]
    DIRECTION INPUT ;
    USE SIGNAL ;
    PORT
      LAYER M5 ;
        RECT  92.592 25.836 92.616 25.92 ;
    END
  END fd_in[516]
  PIN fd_in[517]
    DIRECTION INPUT ;
    USE SIGNAL ;
    PORT
      LAYER M5 ;
        RECT  92.784 25.836 92.808 25.92 ;
    END
  END fd_in[517]
  PIN fd_in[518]
    DIRECTION INPUT ;
    USE SIGNAL ;
    PORT
      LAYER M5 ;
        RECT  92.976 25.836 93 25.92 ;
    END
  END fd_in[518]
  PIN fd_in[519]
    DIRECTION INPUT ;
    USE SIGNAL ;
    PORT
      LAYER M5 ;
        RECT  93.12 25.836 93.144 25.92 ;
    END
  END fd_in[519]
  PIN fd_in[51]
    DIRECTION INPUT ;
    USE SIGNAL ;
    PORT
      LAYER M5 ;
        RECT  9.216 25.836 9.24 25.92 ;
    END
  END fd_in[51]
  PIN fd_in[520]
    DIRECTION INPUT ;
    USE SIGNAL ;
    PORT
      LAYER M5 ;
        RECT  93.312 25.836 93.336 25.92 ;
    END
  END fd_in[520]
  PIN fd_in[521]
    DIRECTION INPUT ;
    USE SIGNAL ;
    PORT
      LAYER M5 ;
        RECT  93.504 25.836 93.528 25.92 ;
    END
  END fd_in[521]
  PIN fd_in[522]
    DIRECTION INPUT ;
    USE SIGNAL ;
    PORT
      LAYER M5 ;
        RECT  93.648 25.836 93.672 25.92 ;
    END
  END fd_in[522]
  PIN fd_in[523]
    DIRECTION INPUT ;
    USE SIGNAL ;
    PORT
      LAYER M5 ;
        RECT  93.84 25.836 93.864 25.92 ;
    END
  END fd_in[523]
  PIN fd_in[524]
    DIRECTION INPUT ;
    USE SIGNAL ;
    PORT
      LAYER M5 ;
        RECT  94.032 25.836 94.056 25.92 ;
    END
  END fd_in[524]
  PIN fd_in[525]
    DIRECTION INPUT ;
    USE SIGNAL ;
    PORT
      LAYER M5 ;
        RECT  94.224 25.836 94.248 25.92 ;
    END
  END fd_in[525]
  PIN fd_in[526]
    DIRECTION INPUT ;
    USE SIGNAL ;
    PORT
      LAYER M5 ;
        RECT  94.368 25.836 94.392 25.92 ;
    END
  END fd_in[526]
  PIN fd_in[527]
    DIRECTION INPUT ;
    USE SIGNAL ;
    PORT
      LAYER M5 ;
        RECT  94.56 25.836 94.584 25.92 ;
    END
  END fd_in[527]
  PIN fd_in[528]
    DIRECTION INPUT ;
    USE SIGNAL ;
    PORT
      LAYER M5 ;
        RECT  94.752 25.836 94.776 25.92 ;
    END
  END fd_in[528]
  PIN fd_in[529]
    DIRECTION INPUT ;
    USE SIGNAL ;
    PORT
      LAYER M5 ;
        RECT  94.944 25.836 94.968 25.92 ;
    END
  END fd_in[529]
  PIN fd_in[52]
    DIRECTION INPUT ;
    USE SIGNAL ;
    PORT
      LAYER M5 ;
        RECT  9.36 25.836 9.384 25.92 ;
    END
  END fd_in[52]
  PIN fd_in[530]
    DIRECTION INPUT ;
    USE SIGNAL ;
    PORT
      LAYER M5 ;
        RECT  95.088 25.836 95.112 25.92 ;
    END
  END fd_in[530]
  PIN fd_in[531]
    DIRECTION INPUT ;
    USE SIGNAL ;
    PORT
      LAYER M5 ;
        RECT  95.28 25.836 95.304 25.92 ;
    END
  END fd_in[531]
  PIN fd_in[532]
    DIRECTION INPUT ;
    USE SIGNAL ;
    PORT
      LAYER M5 ;
        RECT  95.472 25.836 95.496 25.92 ;
    END
  END fd_in[532]
  PIN fd_in[533]
    DIRECTION INPUT ;
    USE SIGNAL ;
    PORT
      LAYER M5 ;
        RECT  95.664 25.836 95.688 25.92 ;
    END
  END fd_in[533]
  PIN fd_in[534]
    DIRECTION INPUT ;
    USE SIGNAL ;
    PORT
      LAYER M5 ;
        RECT  95.808 25.836 95.832 25.92 ;
    END
  END fd_in[534]
  PIN fd_in[535]
    DIRECTION INPUT ;
    USE SIGNAL ;
    PORT
      LAYER M5 ;
        RECT  96 25.836 96.024 25.92 ;
    END
  END fd_in[535]
  PIN fd_in[536]
    DIRECTION INPUT ;
    USE SIGNAL ;
    PORT
      LAYER M5 ;
        RECT  96.192 25.836 96.216 25.92 ;
    END
  END fd_in[536]
  PIN fd_in[537]
    DIRECTION INPUT ;
    USE SIGNAL ;
    PORT
      LAYER M5 ;
        RECT  96.384 25.836 96.408 25.92 ;
    END
  END fd_in[537]
  PIN fd_in[538]
    DIRECTION INPUT ;
    USE SIGNAL ;
    PORT
      LAYER M5 ;
        RECT  96.528 25.836 96.552 25.92 ;
    END
  END fd_in[538]
  PIN fd_in[539]
    DIRECTION INPUT ;
    USE SIGNAL ;
    PORT
      LAYER M5 ;
        RECT  96.72 25.836 96.744 25.92 ;
    END
  END fd_in[539]
  PIN fd_in[53]
    DIRECTION INPUT ;
    USE SIGNAL ;
    PORT
      LAYER M5 ;
        RECT  9.552 25.836 9.576 25.92 ;
    END
  END fd_in[53]
  PIN fd_in[540]
    DIRECTION INPUT ;
    USE SIGNAL ;
    PORT
      LAYER M5 ;
        RECT  96.912 25.836 96.936 25.92 ;
    END
  END fd_in[540]
  PIN fd_in[541]
    DIRECTION INPUT ;
    USE SIGNAL ;
    PORT
      LAYER M5 ;
        RECT  97.056 25.836 97.08 25.92 ;
    END
  END fd_in[541]
  PIN fd_in[542]
    DIRECTION INPUT ;
    USE SIGNAL ;
    PORT
      LAYER M5 ;
        RECT  97.248 25.836 97.272 25.92 ;
    END
  END fd_in[542]
  PIN fd_in[543]
    DIRECTION INPUT ;
    USE SIGNAL ;
    PORT
      LAYER M5 ;
        RECT  97.44 25.836 97.464 25.92 ;
    END
  END fd_in[543]
  PIN fd_in[544]
    DIRECTION INPUT ;
    USE SIGNAL ;
    PORT
      LAYER M5 ;
        RECT  97.632 25.836 97.656 25.92 ;
    END
  END fd_in[544]
  PIN fd_in[545]
    DIRECTION INPUT ;
    USE SIGNAL ;
    PORT
      LAYER M5 ;
        RECT  97.776 25.836 97.8 25.92 ;
    END
  END fd_in[545]
  PIN fd_in[546]
    DIRECTION INPUT ;
    USE SIGNAL ;
    PORT
      LAYER M5 ;
        RECT  97.968 25.836 97.992 25.92 ;
    END
  END fd_in[546]
  PIN fd_in[547]
    DIRECTION INPUT ;
    USE SIGNAL ;
    PORT
      LAYER M5 ;
        RECT  98.16 25.836 98.184 25.92 ;
    END
  END fd_in[547]
  PIN fd_in[548]
    DIRECTION INPUT ;
    USE SIGNAL ;
    PORT
      LAYER M5 ;
        RECT  98.352 25.836 98.376 25.92 ;
    END
  END fd_in[548]
  PIN fd_in[549]
    DIRECTION INPUT ;
    USE SIGNAL ;
    PORT
      LAYER M5 ;
        RECT  98.496 25.836 98.52 25.92 ;
    END
  END fd_in[549]
  PIN fd_in[54]
    DIRECTION INPUT ;
    USE SIGNAL ;
    PORT
      LAYER M5 ;
        RECT  9.744 25.836 9.768 25.92 ;
    END
  END fd_in[54]
  PIN fd_in[550]
    DIRECTION INPUT ;
    USE SIGNAL ;
    PORT
      LAYER M5 ;
        RECT  98.688 25.836 98.712 25.92 ;
    END
  END fd_in[550]
  PIN fd_in[551]
    DIRECTION INPUT ;
    USE SIGNAL ;
    PORT
      LAYER M5 ;
        RECT  98.88 25.836 98.904 25.92 ;
    END
  END fd_in[551]
  PIN fd_in[552]
    DIRECTION INPUT ;
    USE SIGNAL ;
    PORT
      LAYER M5 ;
        RECT  99.072 25.836 99.096 25.92 ;
    END
  END fd_in[552]
  PIN fd_in[553]
    DIRECTION INPUT ;
    USE SIGNAL ;
    PORT
      LAYER M5 ;
        RECT  99.216 25.836 99.24 25.92 ;
    END
  END fd_in[553]
  PIN fd_in[554]
    DIRECTION INPUT ;
    USE SIGNAL ;
    PORT
      LAYER M5 ;
        RECT  99.408 25.836 99.432 25.92 ;
    END
  END fd_in[554]
  PIN fd_in[555]
    DIRECTION INPUT ;
    USE SIGNAL ;
    PORT
      LAYER M5 ;
        RECT  99.6 25.836 99.624 25.92 ;
    END
  END fd_in[555]
  PIN fd_in[556]
    DIRECTION INPUT ;
    USE SIGNAL ;
    PORT
      LAYER M5 ;
        RECT  99.792 25.836 99.816 25.92 ;
    END
  END fd_in[556]
  PIN fd_in[557]
    DIRECTION INPUT ;
    USE SIGNAL ;
    PORT
      LAYER M5 ;
        RECT  99.936 25.836 99.96 25.92 ;
    END
  END fd_in[557]
  PIN fd_in[558]
    DIRECTION INPUT ;
    USE SIGNAL ;
    PORT
      LAYER M5 ;
        RECT  100.128 25.836 100.152 25.92 ;
    END
  END fd_in[558]
  PIN fd_in[559]
    DIRECTION INPUT ;
    USE SIGNAL ;
    PORT
      LAYER M5 ;
        RECT  100.32 25.836 100.344 25.92 ;
    END
  END fd_in[559]
  PIN fd_in[55]
    DIRECTION INPUT ;
    USE SIGNAL ;
    PORT
      LAYER M5 ;
        RECT  9.936 25.836 9.96 25.92 ;
    END
  END fd_in[55]
  PIN fd_in[560]
    DIRECTION INPUT ;
    USE SIGNAL ;
    PORT
      LAYER M5 ;
        RECT  100.464 25.836 100.488 25.92 ;
    END
  END fd_in[560]
  PIN fd_in[561]
    DIRECTION INPUT ;
    USE SIGNAL ;
    PORT
      LAYER M5 ;
        RECT  100.656 25.836 100.68 25.92 ;
    END
  END fd_in[561]
  PIN fd_in[562]
    DIRECTION INPUT ;
    USE SIGNAL ;
    PORT
      LAYER M5 ;
        RECT  100.848 25.836 100.872 25.92 ;
    END
  END fd_in[562]
  PIN fd_in[563]
    DIRECTION INPUT ;
    USE SIGNAL ;
    PORT
      LAYER M5 ;
        RECT  101.04 25.836 101.064 25.92 ;
    END
  END fd_in[563]
  PIN fd_in[564]
    DIRECTION INPUT ;
    USE SIGNAL ;
    PORT
      LAYER M5 ;
        RECT  101.184 25.836 101.208 25.92 ;
    END
  END fd_in[564]
  PIN fd_in[565]
    DIRECTION INPUT ;
    USE SIGNAL ;
    PORT
      LAYER M5 ;
        RECT  101.376 25.836 101.4 25.92 ;
    END
  END fd_in[565]
  PIN fd_in[566]
    DIRECTION INPUT ;
    USE SIGNAL ;
    PORT
      LAYER M5 ;
        RECT  101.568 25.836 101.592 25.92 ;
    END
  END fd_in[566]
  PIN fd_in[567]
    DIRECTION INPUT ;
    USE SIGNAL ;
    PORT
      LAYER M5 ;
        RECT  101.76 25.836 101.784 25.92 ;
    END
  END fd_in[567]
  PIN fd_in[568]
    DIRECTION INPUT ;
    USE SIGNAL ;
    PORT
      LAYER M5 ;
        RECT  101.904 25.836 101.928 25.92 ;
    END
  END fd_in[568]
  PIN fd_in[569]
    DIRECTION INPUT ;
    USE SIGNAL ;
    PORT
      LAYER M5 ;
        RECT  102.096 25.836 102.12 25.92 ;
    END
  END fd_in[569]
  PIN fd_in[56]
    DIRECTION INPUT ;
    USE SIGNAL ;
    PORT
      LAYER M5 ;
        RECT  10.08 25.836 10.104 25.92 ;
    END
  END fd_in[56]
  PIN fd_in[570]
    DIRECTION INPUT ;
    USE SIGNAL ;
    PORT
      LAYER M5 ;
        RECT  102.288 25.836 102.312 25.92 ;
    END
  END fd_in[570]
  PIN fd_in[571]
    DIRECTION INPUT ;
    USE SIGNAL ;
    PORT
      LAYER M5 ;
        RECT  102.48 25.836 102.504 25.92 ;
    END
  END fd_in[571]
  PIN fd_in[572]
    DIRECTION INPUT ;
    USE SIGNAL ;
    PORT
      LAYER M5 ;
        RECT  102.624 25.836 102.648 25.92 ;
    END
  END fd_in[572]
  PIN fd_in[573]
    DIRECTION INPUT ;
    USE SIGNAL ;
    PORT
      LAYER M5 ;
        RECT  102.816 25.836 102.84 25.92 ;
    END
  END fd_in[573]
  PIN fd_in[574]
    DIRECTION INPUT ;
    USE SIGNAL ;
    PORT
      LAYER M5 ;
        RECT  103.008 25.836 103.032 25.92 ;
    END
  END fd_in[574]
  PIN fd_in[575]
    DIRECTION INPUT ;
    USE SIGNAL ;
    PORT
      LAYER M5 ;
        RECT  103.2 25.836 103.224 25.92 ;
    END
  END fd_in[575]
  PIN fd_in[576]
    DIRECTION INPUT ;
    USE SIGNAL ;
    PORT
      LAYER M5 ;
        RECT  103.344 25.836 103.368 25.92 ;
    END
  END fd_in[576]
  PIN fd_in[577]
    DIRECTION INPUT ;
    USE SIGNAL ;
    PORT
      LAYER M5 ;
        RECT  103.536 25.836 103.56 25.92 ;
    END
  END fd_in[577]
  PIN fd_in[578]
    DIRECTION INPUT ;
    USE SIGNAL ;
    PORT
      LAYER M5 ;
        RECT  103.728 25.836 103.752 25.92 ;
    END
  END fd_in[578]
  PIN fd_in[579]
    DIRECTION INPUT ;
    USE SIGNAL ;
    PORT
      LAYER M5 ;
        RECT  103.872 25.836 103.896 25.92 ;
    END
  END fd_in[579]
  PIN fd_in[57]
    DIRECTION INPUT ;
    USE SIGNAL ;
    PORT
      LAYER M5 ;
        RECT  10.272 25.836 10.296 25.92 ;
    END
  END fd_in[57]
  PIN fd_in[580]
    DIRECTION INPUT ;
    USE SIGNAL ;
    PORT
      LAYER M5 ;
        RECT  104.064 25.836 104.088 25.92 ;
    END
  END fd_in[580]
  PIN fd_in[581]
    DIRECTION INPUT ;
    USE SIGNAL ;
    PORT
      LAYER M5 ;
        RECT  104.256 25.836 104.28 25.92 ;
    END
  END fd_in[581]
  PIN fd_in[582]
    DIRECTION INPUT ;
    USE SIGNAL ;
    PORT
      LAYER M5 ;
        RECT  104.448 25.836 104.472 25.92 ;
    END
  END fd_in[582]
  PIN fd_in[583]
    DIRECTION INPUT ;
    USE SIGNAL ;
    PORT
      LAYER M5 ;
        RECT  104.592 25.836 104.616 25.92 ;
    END
  END fd_in[583]
  PIN fd_in[584]
    DIRECTION INPUT ;
    USE SIGNAL ;
    PORT
      LAYER M5 ;
        RECT  104.784 25.836 104.808 25.92 ;
    END
  END fd_in[584]
  PIN fd_in[585]
    DIRECTION INPUT ;
    USE SIGNAL ;
    PORT
      LAYER M5 ;
        RECT  104.976 25.836 105 25.92 ;
    END
  END fd_in[585]
  PIN fd_in[586]
    DIRECTION INPUT ;
    USE SIGNAL ;
    PORT
      LAYER M5 ;
        RECT  105.168 25.836 105.192 25.92 ;
    END
  END fd_in[586]
  PIN fd_in[587]
    DIRECTION INPUT ;
    USE SIGNAL ;
    PORT
      LAYER M5 ;
        RECT  105.312 25.836 105.336 25.92 ;
    END
  END fd_in[587]
  PIN fd_in[588]
    DIRECTION INPUT ;
    USE SIGNAL ;
    PORT
      LAYER M5 ;
        RECT  105.504 25.836 105.528 25.92 ;
    END
  END fd_in[588]
  PIN fd_in[589]
    DIRECTION INPUT ;
    USE SIGNAL ;
    PORT
      LAYER M5 ;
        RECT  105.696 25.836 105.72 25.92 ;
    END
  END fd_in[589]
  PIN fd_in[58]
    DIRECTION INPUT ;
    USE SIGNAL ;
    PORT
      LAYER M5 ;
        RECT  10.464 25.836 10.488 25.92 ;
    END
  END fd_in[58]
  PIN fd_in[590]
    DIRECTION INPUT ;
    USE SIGNAL ;
    PORT
      LAYER M5 ;
        RECT  105.888 25.836 105.912 25.92 ;
    END
  END fd_in[590]
  PIN fd_in[591]
    DIRECTION INPUT ;
    USE SIGNAL ;
    PORT
      LAYER M5 ;
        RECT  106.032 25.836 106.056 25.92 ;
    END
  END fd_in[591]
  PIN fd_in[592]
    DIRECTION INPUT ;
    USE SIGNAL ;
    PORT
      LAYER M5 ;
        RECT  106.224 25.836 106.248 25.92 ;
    END
  END fd_in[592]
  PIN fd_in[593]
    DIRECTION INPUT ;
    USE SIGNAL ;
    PORT
      LAYER M5 ;
        RECT  106.416 25.836 106.44 25.92 ;
    END
  END fd_in[593]
  PIN fd_in[594]
    DIRECTION INPUT ;
    USE SIGNAL ;
    PORT
      LAYER M5 ;
        RECT  106.608 25.836 106.632 25.92 ;
    END
  END fd_in[594]
  PIN fd_in[595]
    DIRECTION INPUT ;
    USE SIGNAL ;
    PORT
      LAYER M5 ;
        RECT  106.752 25.836 106.776 25.92 ;
    END
  END fd_in[595]
  PIN fd_in[596]
    DIRECTION INPUT ;
    USE SIGNAL ;
    PORT
      LAYER M5 ;
        RECT  106.944 25.836 106.968 25.92 ;
    END
  END fd_in[596]
  PIN fd_in[597]
    DIRECTION INPUT ;
    USE SIGNAL ;
    PORT
      LAYER M5 ;
        RECT  107.136 25.836 107.16 25.92 ;
    END
  END fd_in[597]
  PIN fd_in[598]
    DIRECTION INPUT ;
    USE SIGNAL ;
    PORT
      LAYER M5 ;
        RECT  107.28 25.836 107.304 25.92 ;
    END
  END fd_in[598]
  PIN fd_in[599]
    DIRECTION INPUT ;
    USE SIGNAL ;
    PORT
      LAYER M5 ;
        RECT  107.472 25.836 107.496 25.92 ;
    END
  END fd_in[599]
  PIN fd_in[59]
    DIRECTION INPUT ;
    USE SIGNAL ;
    PORT
      LAYER M5 ;
        RECT  10.656 25.836 10.68 25.92 ;
    END
  END fd_in[59]
  PIN fd_in[5]
    DIRECTION INPUT ;
    USE SIGNAL ;
    PORT
      LAYER M5 ;
        RECT  0.96 25.836 0.984 25.92 ;
    END
  END fd_in[5]
  PIN fd_in[600]
    DIRECTION INPUT ;
    USE SIGNAL ;
    PORT
      LAYER M5 ;
        RECT  107.664 25.836 107.688 25.92 ;
    END
  END fd_in[600]
  PIN fd_in[601]
    DIRECTION INPUT ;
    USE SIGNAL ;
    PORT
      LAYER M5 ;
        RECT  107.856 25.836 107.88 25.92 ;
    END
  END fd_in[601]
  PIN fd_in[602]
    DIRECTION INPUT ;
    USE SIGNAL ;
    PORT
      LAYER M5 ;
        RECT  108 25.836 108.024 25.92 ;
    END
  END fd_in[602]
  PIN fd_in[603]
    DIRECTION INPUT ;
    USE SIGNAL ;
    PORT
      LAYER M5 ;
        RECT  108.192 25.836 108.216 25.92 ;
    END
  END fd_in[603]
  PIN fd_in[604]
    DIRECTION INPUT ;
    USE SIGNAL ;
    PORT
      LAYER M5 ;
        RECT  108.384 25.836 108.408 25.92 ;
    END
  END fd_in[604]
  PIN fd_in[605]
    DIRECTION INPUT ;
    USE SIGNAL ;
    PORT
      LAYER M5 ;
        RECT  108.576 25.836 108.6 25.92 ;
    END
  END fd_in[605]
  PIN fd_in[606]
    DIRECTION INPUT ;
    USE SIGNAL ;
    PORT
      LAYER M5 ;
        RECT  108.72 25.836 108.744 25.92 ;
    END
  END fd_in[606]
  PIN fd_in[607]
    DIRECTION INPUT ;
    USE SIGNAL ;
    PORT
      LAYER M5 ;
        RECT  108.912 25.836 108.936 25.92 ;
    END
  END fd_in[607]
  PIN fd_in[608]
    DIRECTION INPUT ;
    USE SIGNAL ;
    PORT
      LAYER M5 ;
        RECT  109.104 25.836 109.128 25.92 ;
    END
  END fd_in[608]
  PIN fd_in[609]
    DIRECTION INPUT ;
    USE SIGNAL ;
    PORT
      LAYER M5 ;
        RECT  109.296 25.836 109.32 25.92 ;
    END
  END fd_in[609]
  PIN fd_in[60]
    DIRECTION INPUT ;
    USE SIGNAL ;
    PORT
      LAYER M5 ;
        RECT  10.8 25.836 10.824 25.92 ;
    END
  END fd_in[60]
  PIN fd_in[610]
    DIRECTION INPUT ;
    USE SIGNAL ;
    PORT
      LAYER M5 ;
        RECT  109.44 25.836 109.464 25.92 ;
    END
  END fd_in[610]
  PIN fd_in[611]
    DIRECTION INPUT ;
    USE SIGNAL ;
    PORT
      LAYER M5 ;
        RECT  109.632 25.836 109.656 25.92 ;
    END
  END fd_in[611]
  PIN fd_in[612]
    DIRECTION INPUT ;
    USE SIGNAL ;
    PORT
      LAYER M5 ;
        RECT  109.824 25.836 109.848 25.92 ;
    END
  END fd_in[612]
  PIN fd_in[613]
    DIRECTION INPUT ;
    USE SIGNAL ;
    PORT
      LAYER M5 ;
        RECT  109.968 25.836 109.992 25.92 ;
    END
  END fd_in[613]
  PIN fd_in[614]
    DIRECTION INPUT ;
    USE SIGNAL ;
    PORT
      LAYER M5 ;
        RECT  110.16 25.836 110.184 25.92 ;
    END
  END fd_in[614]
  PIN fd_in[615]
    DIRECTION INPUT ;
    USE SIGNAL ;
    PORT
      LAYER M5 ;
        RECT  110.352 25.836 110.376 25.92 ;
    END
  END fd_in[615]
  PIN fd_in[616]
    DIRECTION INPUT ;
    USE SIGNAL ;
    PORT
      LAYER M5 ;
        RECT  110.544 25.836 110.568 25.92 ;
    END
  END fd_in[616]
  PIN fd_in[617]
    DIRECTION INPUT ;
    USE SIGNAL ;
    PORT
      LAYER M5 ;
        RECT  110.688 25.836 110.712 25.92 ;
    END
  END fd_in[617]
  PIN fd_in[618]
    DIRECTION INPUT ;
    USE SIGNAL ;
    PORT
      LAYER M5 ;
        RECT  110.88 25.836 110.904 25.92 ;
    END
  END fd_in[618]
  PIN fd_in[619]
    DIRECTION INPUT ;
    USE SIGNAL ;
    PORT
      LAYER M5 ;
        RECT  111.072 25.836 111.096 25.92 ;
    END
  END fd_in[619]
  PIN fd_in[61]
    DIRECTION INPUT ;
    USE SIGNAL ;
    PORT
      LAYER M5 ;
        RECT  10.992 25.836 11.016 25.92 ;
    END
  END fd_in[61]
  PIN fd_in[620]
    DIRECTION INPUT ;
    USE SIGNAL ;
    PORT
      LAYER M5 ;
        RECT  111.264 25.836 111.288 25.92 ;
    END
  END fd_in[620]
  PIN fd_in[621]
    DIRECTION INPUT ;
    USE SIGNAL ;
    PORT
      LAYER M5 ;
        RECT  111.408 25.836 111.432 25.92 ;
    END
  END fd_in[621]
  PIN fd_in[622]
    DIRECTION INPUT ;
    USE SIGNAL ;
    PORT
      LAYER M5 ;
        RECT  111.6 25.836 111.624 25.92 ;
    END
  END fd_in[622]
  PIN fd_in[623]
    DIRECTION INPUT ;
    USE SIGNAL ;
    PORT
      LAYER M5 ;
        RECT  111.792 25.836 111.816 25.92 ;
    END
  END fd_in[623]
  PIN fd_in[624]
    DIRECTION INPUT ;
    USE SIGNAL ;
    PORT
      LAYER M5 ;
        RECT  111.984 25.836 112.008 25.92 ;
    END
  END fd_in[624]
  PIN fd_in[625]
    DIRECTION INPUT ;
    USE SIGNAL ;
    PORT
      LAYER M5 ;
        RECT  112.128 25.836 112.152 25.92 ;
    END
  END fd_in[625]
  PIN fd_in[626]
    DIRECTION INPUT ;
    USE SIGNAL ;
    PORT
      LAYER M5 ;
        RECT  112.32 25.836 112.344 25.92 ;
    END
  END fd_in[626]
  PIN fd_in[627]
    DIRECTION INPUT ;
    USE SIGNAL ;
    PORT
      LAYER M5 ;
        RECT  112.512 25.836 112.536 25.92 ;
    END
  END fd_in[627]
  PIN fd_in[628]
    DIRECTION INPUT ;
    USE SIGNAL ;
    PORT
      LAYER M5 ;
        RECT  112.704 25.836 112.728 25.92 ;
    END
  END fd_in[628]
  PIN fd_in[629]
    DIRECTION INPUT ;
    USE SIGNAL ;
    PORT
      LAYER M5 ;
        RECT  112.848 25.836 112.872 25.92 ;
    END
  END fd_in[629]
  PIN fd_in[62]
    DIRECTION INPUT ;
    USE SIGNAL ;
    PORT
      LAYER M5 ;
        RECT  11.184 25.836 11.208 25.92 ;
    END
  END fd_in[62]
  PIN fd_in[630]
    DIRECTION INPUT ;
    USE SIGNAL ;
    PORT
      LAYER M5 ;
        RECT  113.04 25.836 113.064 25.92 ;
    END
  END fd_in[630]
  PIN fd_in[631]
    DIRECTION INPUT ;
    USE SIGNAL ;
    PORT
      LAYER M5 ;
        RECT  113.232 25.836 113.256 25.92 ;
    END
  END fd_in[631]
  PIN fd_in[632]
    DIRECTION INPUT ;
    USE SIGNAL ;
    PORT
      LAYER M5 ;
        RECT  113.376 25.836 113.4 25.92 ;
    END
  END fd_in[632]
  PIN fd_in[633]
    DIRECTION INPUT ;
    USE SIGNAL ;
    PORT
      LAYER M5 ;
        RECT  113.568 25.836 113.592 25.92 ;
    END
  END fd_in[633]
  PIN fd_in[634]
    DIRECTION INPUT ;
    USE SIGNAL ;
    PORT
      LAYER M5 ;
        RECT  113.76 25.836 113.784 25.92 ;
    END
  END fd_in[634]
  PIN fd_in[635]
    DIRECTION INPUT ;
    USE SIGNAL ;
    PORT
      LAYER M5 ;
        RECT  113.952 25.836 113.976 25.92 ;
    END
  END fd_in[635]
  PIN fd_in[636]
    DIRECTION INPUT ;
    USE SIGNAL ;
    PORT
      LAYER M5 ;
        RECT  114.096 25.836 114.12 25.92 ;
    END
  END fd_in[636]
  PIN fd_in[637]
    DIRECTION INPUT ;
    USE SIGNAL ;
    PORT
      LAYER M5 ;
        RECT  114.288 25.836 114.312 25.92 ;
    END
  END fd_in[637]
  PIN fd_in[638]
    DIRECTION INPUT ;
    USE SIGNAL ;
    PORT
      LAYER M5 ;
        RECT  114.48 25.836 114.504 25.92 ;
    END
  END fd_in[638]
  PIN fd_in[639]
    DIRECTION INPUT ;
    USE SIGNAL ;
    PORT
      LAYER M5 ;
        RECT  114.672 25.836 114.696 25.92 ;
    END
  END fd_in[639]
  PIN fd_in[63]
    DIRECTION INPUT ;
    USE SIGNAL ;
    PORT
      LAYER M5 ;
        RECT  11.376 25.836 11.4 25.92 ;
    END
  END fd_in[63]
  PIN fd_in[640]
    DIRECTION INPUT ;
    USE SIGNAL ;
    PORT
      LAYER M5 ;
        RECT  114.816 25.836 114.84 25.92 ;
    END
  END fd_in[640]
  PIN fd_in[641]
    DIRECTION INPUT ;
    USE SIGNAL ;
    PORT
      LAYER M5 ;
        RECT  115.008 25.836 115.032 25.92 ;
    END
  END fd_in[641]
  PIN fd_in[642]
    DIRECTION INPUT ;
    USE SIGNAL ;
    PORT
      LAYER M5 ;
        RECT  115.2 25.836 115.224 25.92 ;
    END
  END fd_in[642]
  PIN fd_in[643]
    DIRECTION INPUT ;
    USE SIGNAL ;
    PORT
      LAYER M5 ;
        RECT  115.392 25.836 115.416 25.92 ;
    END
  END fd_in[643]
  PIN fd_in[644]
    DIRECTION INPUT ;
    USE SIGNAL ;
    PORT
      LAYER M5 ;
        RECT  115.536 25.836 115.56 25.92 ;
    END
  END fd_in[644]
  PIN fd_in[645]
    DIRECTION INPUT ;
    USE SIGNAL ;
    PORT
      LAYER M5 ;
        RECT  115.728 25.836 115.752 25.92 ;
    END
  END fd_in[645]
  PIN fd_in[646]
    DIRECTION INPUT ;
    USE SIGNAL ;
    PORT
      LAYER M5 ;
        RECT  115.92 25.836 115.944 25.92 ;
    END
  END fd_in[646]
  PIN fd_in[647]
    DIRECTION INPUT ;
    USE SIGNAL ;
    PORT
      LAYER M5 ;
        RECT  116.112 25.836 116.136 25.92 ;
    END
  END fd_in[647]
  PIN fd_in[648]
    DIRECTION INPUT ;
    USE SIGNAL ;
    PORT
      LAYER M5 ;
        RECT  116.256 25.836 116.28 25.92 ;
    END
  END fd_in[648]
  PIN fd_in[649]
    DIRECTION INPUT ;
    USE SIGNAL ;
    PORT
      LAYER M5 ;
        RECT  116.448 25.836 116.472 25.92 ;
    END
  END fd_in[649]
  PIN fd_in[64]
    DIRECTION INPUT ;
    USE SIGNAL ;
    PORT
      LAYER M5 ;
        RECT  11.52 25.836 11.544 25.92 ;
    END
  END fd_in[64]
  PIN fd_in[650]
    DIRECTION INPUT ;
    USE SIGNAL ;
    PORT
      LAYER M5 ;
        RECT  116.64 25.836 116.664 25.92 ;
    END
  END fd_in[650]
  PIN fd_in[651]
    DIRECTION INPUT ;
    USE SIGNAL ;
    PORT
      LAYER M5 ;
        RECT  116.784 25.836 116.808 25.92 ;
    END
  END fd_in[651]
  PIN fd_in[652]
    DIRECTION INPUT ;
    USE SIGNAL ;
    PORT
      LAYER M5 ;
        RECT  116.976 25.836 117 25.92 ;
    END
  END fd_in[652]
  PIN fd_in[653]
    DIRECTION INPUT ;
    USE SIGNAL ;
    PORT
      LAYER M5 ;
        RECT  117.168 25.836 117.192 25.92 ;
    END
  END fd_in[653]
  PIN fd_in[654]
    DIRECTION INPUT ;
    USE SIGNAL ;
    PORT
      LAYER M5 ;
        RECT  117.36 25.836 117.384 25.92 ;
    END
  END fd_in[654]
  PIN fd_in[655]
    DIRECTION INPUT ;
    USE SIGNAL ;
    PORT
      LAYER M5 ;
        RECT  117.504 25.836 117.528 25.92 ;
    END
  END fd_in[655]
  PIN fd_in[656]
    DIRECTION INPUT ;
    USE SIGNAL ;
    PORT
      LAYER M5 ;
        RECT  117.696 25.836 117.72 25.92 ;
    END
  END fd_in[656]
  PIN fd_in[657]
    DIRECTION INPUT ;
    USE SIGNAL ;
    PORT
      LAYER M5 ;
        RECT  117.888 25.836 117.912 25.92 ;
    END
  END fd_in[657]
  PIN fd_in[658]
    DIRECTION INPUT ;
    USE SIGNAL ;
    PORT
      LAYER M5 ;
        RECT  118.08 25.836 118.104 25.92 ;
    END
  END fd_in[658]
  PIN fd_in[659]
    DIRECTION INPUT ;
    USE SIGNAL ;
    PORT
      LAYER M5 ;
        RECT  118.224 25.836 118.248 25.92 ;
    END
  END fd_in[659]
  PIN fd_in[65]
    DIRECTION INPUT ;
    USE SIGNAL ;
    PORT
      LAYER M5 ;
        RECT  11.712 25.836 11.736 25.92 ;
    END
  END fd_in[65]
  PIN fd_in[660]
    DIRECTION INPUT ;
    USE SIGNAL ;
    PORT
      LAYER M5 ;
        RECT  118.416 25.836 118.44 25.92 ;
    END
  END fd_in[660]
  PIN fd_in[661]
    DIRECTION INPUT ;
    USE SIGNAL ;
    PORT
      LAYER M5 ;
        RECT  118.608 25.836 118.632 25.92 ;
    END
  END fd_in[661]
  PIN fd_in[662]
    DIRECTION INPUT ;
    USE SIGNAL ;
    PORT
      LAYER M5 ;
        RECT  118.8 25.836 118.824 25.92 ;
    END
  END fd_in[662]
  PIN fd_in[663]
    DIRECTION INPUT ;
    USE SIGNAL ;
    PORT
      LAYER M5 ;
        RECT  118.944 25.836 118.968 25.92 ;
    END
  END fd_in[663]
  PIN fd_in[664]
    DIRECTION INPUT ;
    USE SIGNAL ;
    PORT
      LAYER M5 ;
        RECT  119.136 25.836 119.16 25.92 ;
    END
  END fd_in[664]
  PIN fd_in[665]
    DIRECTION INPUT ;
    USE SIGNAL ;
    PORT
      LAYER M5 ;
        RECT  119.328 25.836 119.352 25.92 ;
    END
  END fd_in[665]
  PIN fd_in[666]
    DIRECTION INPUT ;
    USE SIGNAL ;
    PORT
      LAYER M5 ;
        RECT  119.52 25.836 119.544 25.92 ;
    END
  END fd_in[666]
  PIN fd_in[667]
    DIRECTION INPUT ;
    USE SIGNAL ;
    PORT
      LAYER M5 ;
        RECT  119.664 25.836 119.688 25.92 ;
    END
  END fd_in[667]
  PIN fd_in[668]
    DIRECTION INPUT ;
    USE SIGNAL ;
    PORT
      LAYER M5 ;
        RECT  119.856 25.836 119.88 25.92 ;
    END
  END fd_in[668]
  PIN fd_in[669]
    DIRECTION INPUT ;
    USE SIGNAL ;
    PORT
      LAYER M5 ;
        RECT  120.048 25.836 120.072 25.92 ;
    END
  END fd_in[669]
  PIN fd_in[66]
    DIRECTION INPUT ;
    USE SIGNAL ;
    PORT
      LAYER M5 ;
        RECT  11.904 25.836 11.928 25.92 ;
    END
  END fd_in[66]
  PIN fd_in[670]
    DIRECTION INPUT ;
    USE SIGNAL ;
    PORT
      LAYER M5 ;
        RECT  120.192 25.836 120.216 25.92 ;
    END
  END fd_in[670]
  PIN fd_in[671]
    DIRECTION INPUT ;
    USE SIGNAL ;
    PORT
      LAYER M5 ;
        RECT  120.384 25.836 120.408 25.92 ;
    END
  END fd_in[671]
  PIN fd_in[672]
    DIRECTION INPUT ;
    USE SIGNAL ;
    PORT
      LAYER M5 ;
        RECT  120.576 25.836 120.6 25.92 ;
    END
  END fd_in[672]
  PIN fd_in[673]
    DIRECTION INPUT ;
    USE SIGNAL ;
    PORT
      LAYER M5 ;
        RECT  120.768 25.836 120.792 25.92 ;
    END
  END fd_in[673]
  PIN fd_in[674]
    DIRECTION INPUT ;
    USE SIGNAL ;
    PORT
      LAYER M5 ;
        RECT  120.912 25.836 120.936 25.92 ;
    END
  END fd_in[674]
  PIN fd_in[675]
    DIRECTION INPUT ;
    USE SIGNAL ;
    PORT
      LAYER M5 ;
        RECT  121.104 25.836 121.128 25.92 ;
    END
  END fd_in[675]
  PIN fd_in[676]
    DIRECTION INPUT ;
    USE SIGNAL ;
    PORT
      LAYER M5 ;
        RECT  121.296 25.836 121.32 25.92 ;
    END
  END fd_in[676]
  PIN fd_in[677]
    DIRECTION INPUT ;
    USE SIGNAL ;
    PORT
      LAYER M5 ;
        RECT  121.488 25.836 121.512 25.92 ;
    END
  END fd_in[677]
  PIN fd_in[678]
    DIRECTION INPUT ;
    USE SIGNAL ;
    PORT
      LAYER M5 ;
        RECT  121.632 25.836 121.656 25.92 ;
    END
  END fd_in[678]
  PIN fd_in[679]
    DIRECTION INPUT ;
    USE SIGNAL ;
    PORT
      LAYER M5 ;
        RECT  121.824 25.836 121.848 25.92 ;
    END
  END fd_in[679]
  PIN fd_in[67]
    DIRECTION INPUT ;
    USE SIGNAL ;
    PORT
      LAYER M5 ;
        RECT  12.048 25.836 12.072 25.92 ;
    END
  END fd_in[67]
  PIN fd_in[680]
    DIRECTION INPUT ;
    USE SIGNAL ;
    PORT
      LAYER M5 ;
        RECT  122.016 25.836 122.04 25.92 ;
    END
  END fd_in[680]
  PIN fd_in[681]
    DIRECTION INPUT ;
    USE SIGNAL ;
    PORT
      LAYER M5 ;
        RECT  122.208 25.836 122.232 25.92 ;
    END
  END fd_in[681]
  PIN fd_in[682]
    DIRECTION INPUT ;
    USE SIGNAL ;
    PORT
      LAYER M5 ;
        RECT  122.352 25.836 122.376 25.92 ;
    END
  END fd_in[682]
  PIN fd_in[683]
    DIRECTION INPUT ;
    USE SIGNAL ;
    PORT
      LAYER M5 ;
        RECT  122.544 25.836 122.568 25.92 ;
    END
  END fd_in[683]
  PIN fd_in[684]
    DIRECTION INPUT ;
    USE SIGNAL ;
    PORT
      LAYER M5 ;
        RECT  122.736 25.836 122.76 25.92 ;
    END
  END fd_in[684]
  PIN fd_in[685]
    DIRECTION INPUT ;
    USE SIGNAL ;
    PORT
      LAYER M5 ;
        RECT  122.928 25.836 122.952 25.92 ;
    END
  END fd_in[685]
  PIN fd_in[686]
    DIRECTION INPUT ;
    USE SIGNAL ;
    PORT
      LAYER M5 ;
        RECT  123.072 25.836 123.096 25.92 ;
    END
  END fd_in[686]
  PIN fd_in[687]
    DIRECTION INPUT ;
    USE SIGNAL ;
    PORT
      LAYER M5 ;
        RECT  123.264 25.836 123.288 25.92 ;
    END
  END fd_in[687]
  PIN fd_in[688]
    DIRECTION INPUT ;
    USE SIGNAL ;
    PORT
      LAYER M5 ;
        RECT  123.456 25.836 123.48 25.92 ;
    END
  END fd_in[688]
  PIN fd_in[689]
    DIRECTION INPUT ;
    USE SIGNAL ;
    PORT
      LAYER M5 ;
        RECT  123.6 25.836 123.624 25.92 ;
    END
  END fd_in[689]
  PIN fd_in[68]
    DIRECTION INPUT ;
    USE SIGNAL ;
    PORT
      LAYER M5 ;
        RECT  12.24 25.836 12.264 25.92 ;
    END
  END fd_in[68]
  PIN fd_in[690]
    DIRECTION INPUT ;
    USE SIGNAL ;
    PORT
      LAYER M5 ;
        RECT  123.792 25.836 123.816 25.92 ;
    END
  END fd_in[690]
  PIN fd_in[691]
    DIRECTION INPUT ;
    USE SIGNAL ;
    PORT
      LAYER M5 ;
        RECT  123.984 25.836 124.008 25.92 ;
    END
  END fd_in[691]
  PIN fd_in[692]
    DIRECTION INPUT ;
    USE SIGNAL ;
    PORT
      LAYER M5 ;
        RECT  124.176 25.836 124.2 25.92 ;
    END
  END fd_in[692]
  PIN fd_in[693]
    DIRECTION INPUT ;
    USE SIGNAL ;
    PORT
      LAYER M5 ;
        RECT  124.32 25.836 124.344 25.92 ;
    END
  END fd_in[693]
  PIN fd_in[694]
    DIRECTION INPUT ;
    USE SIGNAL ;
    PORT
      LAYER M5 ;
        RECT  124.512 25.836 124.536 25.92 ;
    END
  END fd_in[694]
  PIN fd_in[695]
    DIRECTION INPUT ;
    USE SIGNAL ;
    PORT
      LAYER M5 ;
        RECT  124.704 25.836 124.728 25.92 ;
    END
  END fd_in[695]
  PIN fd_in[696]
    DIRECTION INPUT ;
    USE SIGNAL ;
    PORT
      LAYER M5 ;
        RECT  124.896 25.836 124.92 25.92 ;
    END
  END fd_in[696]
  PIN fd_in[697]
    DIRECTION INPUT ;
    USE SIGNAL ;
    PORT
      LAYER M5 ;
        RECT  125.04 25.836 125.064 25.92 ;
    END
  END fd_in[697]
  PIN fd_in[698]
    DIRECTION INPUT ;
    USE SIGNAL ;
    PORT
      LAYER M5 ;
        RECT  125.232 25.836 125.256 25.92 ;
    END
  END fd_in[698]
  PIN fd_in[699]
    DIRECTION INPUT ;
    USE SIGNAL ;
    PORT
      LAYER M5 ;
        RECT  125.424 25.836 125.448 25.92 ;
    END
  END fd_in[699]
  PIN fd_in[69]
    DIRECTION INPUT ;
    USE SIGNAL ;
    PORT
      LAYER M5 ;
        RECT  12.432 25.836 12.456 25.92 ;
    END
  END fd_in[69]
  PIN fd_in[6]
    DIRECTION INPUT ;
    USE SIGNAL ;
    PORT
      LAYER M5 ;
        RECT  1.152 25.836 1.176 25.92 ;
    END
  END fd_in[6]
  PIN fd_in[700]
    DIRECTION INPUT ;
    USE SIGNAL ;
    PORT
      LAYER M5 ;
        RECT  125.616 25.836 125.64 25.92 ;
    END
  END fd_in[700]
  PIN fd_in[701]
    DIRECTION INPUT ;
    USE SIGNAL ;
    PORT
      LAYER M5 ;
        RECT  125.76 25.836 125.784 25.92 ;
    END
  END fd_in[701]
  PIN fd_in[702]
    DIRECTION INPUT ;
    USE SIGNAL ;
    PORT
      LAYER M5 ;
        RECT  125.952 25.836 125.976 25.92 ;
    END
  END fd_in[702]
  PIN fd_in[703]
    DIRECTION INPUT ;
    USE SIGNAL ;
    PORT
      LAYER M5 ;
        RECT  126.144 25.836 126.168 25.92 ;
    END
  END fd_in[703]
  PIN fd_in[704]
    DIRECTION INPUT ;
    USE SIGNAL ;
    PORT
      LAYER M5 ;
        RECT  126.288 25.836 126.312 25.92 ;
    END
  END fd_in[704]
  PIN fd_in[705]
    DIRECTION INPUT ;
    USE SIGNAL ;
    PORT
      LAYER M5 ;
        RECT  126.48 25.836 126.504 25.92 ;
    END
  END fd_in[705]
  PIN fd_in[706]
    DIRECTION INPUT ;
    USE SIGNAL ;
    PORT
      LAYER M5 ;
        RECT  126.672 25.836 126.696 25.92 ;
    END
  END fd_in[706]
  PIN fd_in[707]
    DIRECTION INPUT ;
    USE SIGNAL ;
    PORT
      LAYER M5 ;
        RECT  126.864 25.836 126.888 25.92 ;
    END
  END fd_in[707]
  PIN fd_in[708]
    DIRECTION INPUT ;
    USE SIGNAL ;
    PORT
      LAYER M5 ;
        RECT  127.008 25.836 127.032 25.92 ;
    END
  END fd_in[708]
  PIN fd_in[709]
    DIRECTION INPUT ;
    USE SIGNAL ;
    PORT
      LAYER M5 ;
        RECT  127.2 25.836 127.224 25.92 ;
    END
  END fd_in[709]
  PIN fd_in[70]
    DIRECTION INPUT ;
    USE SIGNAL ;
    PORT
      LAYER M5 ;
        RECT  12.624 25.836 12.648 25.92 ;
    END
  END fd_in[70]
  PIN fd_in[710]
    DIRECTION INPUT ;
    USE SIGNAL ;
    PORT
      LAYER M5 ;
        RECT  127.392 25.836 127.416 25.92 ;
    END
  END fd_in[710]
  PIN fd_in[711]
    DIRECTION INPUT ;
    USE SIGNAL ;
    PORT
      LAYER M5 ;
        RECT  127.584 25.836 127.608 25.92 ;
    END
  END fd_in[711]
  PIN fd_in[712]
    DIRECTION INPUT ;
    USE SIGNAL ;
    PORT
      LAYER M5 ;
        RECT  127.728 25.836 127.752 25.92 ;
    END
  END fd_in[712]
  PIN fd_in[713]
    DIRECTION INPUT ;
    USE SIGNAL ;
    PORT
      LAYER M5 ;
        RECT  127.92 25.836 127.944 25.92 ;
    END
  END fd_in[713]
  PIN fd_in[714]
    DIRECTION INPUT ;
    USE SIGNAL ;
    PORT
      LAYER M5 ;
        RECT  128.112 25.836 128.136 25.92 ;
    END
  END fd_in[714]
  PIN fd_in[715]
    DIRECTION INPUT ;
    USE SIGNAL ;
    PORT
      LAYER M5 ;
        RECT  128.304 25.836 128.328 25.92 ;
    END
  END fd_in[715]
  PIN fd_in[716]
    DIRECTION INPUT ;
    USE SIGNAL ;
    PORT
      LAYER M5 ;
        RECT  128.448 25.836 128.472 25.92 ;
    END
  END fd_in[716]
  PIN fd_in[717]
    DIRECTION INPUT ;
    USE SIGNAL ;
    PORT
      LAYER M5 ;
        RECT  128.64 25.836 128.664 25.92 ;
    END
  END fd_in[717]
  PIN fd_in[718]
    DIRECTION INPUT ;
    USE SIGNAL ;
    PORT
      LAYER M5 ;
        RECT  128.832 25.836 128.856 25.92 ;
    END
  END fd_in[718]
  PIN fd_in[719]
    DIRECTION INPUT ;
    USE SIGNAL ;
    PORT
      LAYER M5 ;
        RECT  129.024 25.836 129.048 25.92 ;
    END
  END fd_in[719]
  PIN fd_in[71]
    DIRECTION INPUT ;
    USE SIGNAL ;
    PORT
      LAYER M5 ;
        RECT  12.768 25.836 12.792 25.92 ;
    END
  END fd_in[71]
  PIN fd_in[720]
    DIRECTION INPUT ;
    USE SIGNAL ;
    PORT
      LAYER M5 ;
        RECT  129.168 25.836 129.192 25.92 ;
    END
  END fd_in[720]
  PIN fd_in[721]
    DIRECTION INPUT ;
    USE SIGNAL ;
    PORT
      LAYER M5 ;
        RECT  129.36 25.836 129.384 25.92 ;
    END
  END fd_in[721]
  PIN fd_in[722]
    DIRECTION INPUT ;
    USE SIGNAL ;
    PORT
      LAYER M5 ;
        RECT  129.552 25.836 129.576 25.92 ;
    END
  END fd_in[722]
  PIN fd_in[723]
    DIRECTION INPUT ;
    USE SIGNAL ;
    PORT
      LAYER M5 ;
        RECT  129.696 25.836 129.72 25.92 ;
    END
  END fd_in[723]
  PIN fd_in[724]
    DIRECTION INPUT ;
    USE SIGNAL ;
    PORT
      LAYER M5 ;
        RECT  129.888 25.836 129.912 25.92 ;
    END
  END fd_in[724]
  PIN fd_in[725]
    DIRECTION INPUT ;
    USE SIGNAL ;
    PORT
      LAYER M5 ;
        RECT  130.08 25.836 130.104 25.92 ;
    END
  END fd_in[725]
  PIN fd_in[726]
    DIRECTION INPUT ;
    USE SIGNAL ;
    PORT
      LAYER M5 ;
        RECT  130.272 25.836 130.296 25.92 ;
    END
  END fd_in[726]
  PIN fd_in[727]
    DIRECTION INPUT ;
    USE SIGNAL ;
    PORT
      LAYER M5 ;
        RECT  130.416 25.836 130.44 25.92 ;
    END
  END fd_in[727]
  PIN fd_in[728]
    DIRECTION INPUT ;
    USE SIGNAL ;
    PORT
      LAYER M5 ;
        RECT  130.608 25.836 130.632 25.92 ;
    END
  END fd_in[728]
  PIN fd_in[729]
    DIRECTION INPUT ;
    USE SIGNAL ;
    PORT
      LAYER M5 ;
        RECT  130.8 25.836 130.824 25.92 ;
    END
  END fd_in[729]
  PIN fd_in[72]
    DIRECTION INPUT ;
    USE SIGNAL ;
    PORT
      LAYER M5 ;
        RECT  12.96 25.836 12.984 25.92 ;
    END
  END fd_in[72]
  PIN fd_in[730]
    DIRECTION INPUT ;
    USE SIGNAL ;
    PORT
      LAYER M5 ;
        RECT  130.992 25.836 131.016 25.92 ;
    END
  END fd_in[730]
  PIN fd_in[731]
    DIRECTION INPUT ;
    USE SIGNAL ;
    PORT
      LAYER M5 ;
        RECT  131.136 25.836 131.16 25.92 ;
    END
  END fd_in[731]
  PIN fd_in[732]
    DIRECTION INPUT ;
    USE SIGNAL ;
    PORT
      LAYER M5 ;
        RECT  131.328 25.836 131.352 25.92 ;
    END
  END fd_in[732]
  PIN fd_in[733]
    DIRECTION INPUT ;
    USE SIGNAL ;
    PORT
      LAYER M5 ;
        RECT  131.52 25.836 131.544 25.92 ;
    END
  END fd_in[733]
  PIN fd_in[734]
    DIRECTION INPUT ;
    USE SIGNAL ;
    PORT
      LAYER M5 ;
        RECT  131.712 25.836 131.736 25.92 ;
    END
  END fd_in[734]
  PIN fd_in[735]
    DIRECTION INPUT ;
    USE SIGNAL ;
    PORT
      LAYER M5 ;
        RECT  131.856 25.836 131.88 25.92 ;
    END
  END fd_in[735]
  PIN fd_in[736]
    DIRECTION INPUT ;
    USE SIGNAL ;
    PORT
      LAYER M5 ;
        RECT  132.048 25.836 132.072 25.92 ;
    END
  END fd_in[736]
  PIN fd_in[737]
    DIRECTION INPUT ;
    USE SIGNAL ;
    PORT
      LAYER M5 ;
        RECT  132.24 25.836 132.264 25.92 ;
    END
  END fd_in[737]
  PIN fd_in[738]
    DIRECTION INPUT ;
    USE SIGNAL ;
    PORT
      LAYER M5 ;
        RECT  132.432 25.836 132.456 25.92 ;
    END
  END fd_in[738]
  PIN fd_in[739]
    DIRECTION INPUT ;
    USE SIGNAL ;
    PORT
      LAYER M5 ;
        RECT  132.576 25.836 132.6 25.92 ;
    END
  END fd_in[739]
  PIN fd_in[73]
    DIRECTION INPUT ;
    USE SIGNAL ;
    PORT
      LAYER M5 ;
        RECT  13.152 25.836 13.176 25.92 ;
    END
  END fd_in[73]
  PIN fd_in[740]
    DIRECTION INPUT ;
    USE SIGNAL ;
    PORT
      LAYER M5 ;
        RECT  132.768 25.836 132.792 25.92 ;
    END
  END fd_in[740]
  PIN fd_in[741]
    DIRECTION INPUT ;
    USE SIGNAL ;
    PORT
      LAYER M5 ;
        RECT  132.96 25.836 132.984 25.92 ;
    END
  END fd_in[741]
  PIN fd_in[742]
    DIRECTION INPUT ;
    USE SIGNAL ;
    PORT
      LAYER M5 ;
        RECT  133.104 25.836 133.128 25.92 ;
    END
  END fd_in[742]
  PIN fd_in[743]
    DIRECTION INPUT ;
    USE SIGNAL ;
    PORT
      LAYER M5 ;
        RECT  133.296 25.836 133.32 25.92 ;
    END
  END fd_in[743]
  PIN fd_in[744]
    DIRECTION INPUT ;
    USE SIGNAL ;
    PORT
      LAYER M5 ;
        RECT  133.488 25.836 133.512 25.92 ;
    END
  END fd_in[744]
  PIN fd_in[745]
    DIRECTION INPUT ;
    USE SIGNAL ;
    PORT
      LAYER M5 ;
        RECT  133.68 25.836 133.704 25.92 ;
    END
  END fd_in[745]
  PIN fd_in[746]
    DIRECTION INPUT ;
    USE SIGNAL ;
    PORT
      LAYER M5 ;
        RECT  133.824 25.836 133.848 25.92 ;
    END
  END fd_in[746]
  PIN fd_in[747]
    DIRECTION INPUT ;
    USE SIGNAL ;
    PORT
      LAYER M5 ;
        RECT  134.016 25.836 134.04 25.92 ;
    END
  END fd_in[747]
  PIN fd_in[748]
    DIRECTION INPUT ;
    USE SIGNAL ;
    PORT
      LAYER M5 ;
        RECT  134.208 25.836 134.232 25.92 ;
    END
  END fd_in[748]
  PIN fd_in[749]
    DIRECTION INPUT ;
    USE SIGNAL ;
    PORT
      LAYER M5 ;
        RECT  134.4 25.836 134.424 25.92 ;
    END
  END fd_in[749]
  PIN fd_in[74]
    DIRECTION INPUT ;
    USE SIGNAL ;
    PORT
      LAYER M5 ;
        RECT  13.344 25.836 13.368 25.92 ;
    END
  END fd_in[74]
  PIN fd_in[750]
    DIRECTION INPUT ;
    USE SIGNAL ;
    PORT
      LAYER M5 ;
        RECT  134.544 25.836 134.568 25.92 ;
    END
  END fd_in[750]
  PIN fd_in[751]
    DIRECTION INPUT ;
    USE SIGNAL ;
    PORT
      LAYER M5 ;
        RECT  134.736 25.836 134.76 25.92 ;
    END
  END fd_in[751]
  PIN fd_in[752]
    DIRECTION INPUT ;
    USE SIGNAL ;
    PORT
      LAYER M5 ;
        RECT  134.928 25.836 134.952 25.92 ;
    END
  END fd_in[752]
  PIN fd_in[753]
    DIRECTION INPUT ;
    USE SIGNAL ;
    PORT
      LAYER M5 ;
        RECT  135.12 25.836 135.144 25.92 ;
    END
  END fd_in[753]
  PIN fd_in[754]
    DIRECTION INPUT ;
    USE SIGNAL ;
    PORT
      LAYER M5 ;
        RECT  135.264 25.836 135.288 25.92 ;
    END
  END fd_in[754]
  PIN fd_in[755]
    DIRECTION INPUT ;
    USE SIGNAL ;
    PORT
      LAYER M5 ;
        RECT  135.456 25.836 135.48 25.92 ;
    END
  END fd_in[755]
  PIN fd_in[756]
    DIRECTION INPUT ;
    USE SIGNAL ;
    PORT
      LAYER M5 ;
        RECT  135.648 25.836 135.672 25.92 ;
    END
  END fd_in[756]
  PIN fd_in[757]
    DIRECTION INPUT ;
    USE SIGNAL ;
    PORT
      LAYER M5 ;
        RECT  135.84 25.836 135.864 25.92 ;
    END
  END fd_in[757]
  PIN fd_in[758]
    DIRECTION INPUT ;
    USE SIGNAL ;
    PORT
      LAYER M5 ;
        RECT  135.984 25.836 136.008 25.92 ;
    END
  END fd_in[758]
  PIN fd_in[759]
    DIRECTION INPUT ;
    USE SIGNAL ;
    PORT
      LAYER M5 ;
        RECT  136.176 25.836 136.2 25.92 ;
    END
  END fd_in[759]
  PIN fd_in[75]
    DIRECTION INPUT ;
    USE SIGNAL ;
    PORT
      LAYER M5 ;
        RECT  13.488 25.836 13.512 25.92 ;
    END
  END fd_in[75]
  PIN fd_in[760]
    DIRECTION INPUT ;
    USE SIGNAL ;
    PORT
      LAYER M5 ;
        RECT  136.368 25.836 136.392 25.92 ;
    END
  END fd_in[760]
  PIN fd_in[761]
    DIRECTION INPUT ;
    USE SIGNAL ;
    PORT
      LAYER M5 ;
        RECT  136.512 25.836 136.536 25.92 ;
    END
  END fd_in[761]
  PIN fd_in[762]
    DIRECTION INPUT ;
    USE SIGNAL ;
    PORT
      LAYER M5 ;
        RECT  136.704 25.836 136.728 25.92 ;
    END
  END fd_in[762]
  PIN fd_in[763]
    DIRECTION INPUT ;
    USE SIGNAL ;
    PORT
      LAYER M5 ;
        RECT  136.896 25.836 136.92 25.92 ;
    END
  END fd_in[763]
  PIN fd_in[764]
    DIRECTION INPUT ;
    USE SIGNAL ;
    PORT
      LAYER M5 ;
        RECT  137.088 25.836 137.112 25.92 ;
    END
  END fd_in[764]
  PIN fd_in[765]
    DIRECTION INPUT ;
    USE SIGNAL ;
    PORT
      LAYER M5 ;
        RECT  137.232 25.836 137.256 25.92 ;
    END
  END fd_in[765]
  PIN fd_in[766]
    DIRECTION INPUT ;
    USE SIGNAL ;
    PORT
      LAYER M5 ;
        RECT  137.424 25.836 137.448 25.92 ;
    END
  END fd_in[766]
  PIN fd_in[767]
    DIRECTION INPUT ;
    USE SIGNAL ;
    PORT
      LAYER M5 ;
        RECT  137.616 25.836 137.64 25.92 ;
    END
  END fd_in[767]
  PIN fd_in[768]
    DIRECTION INPUT ;
    USE SIGNAL ;
    PORT
      LAYER M5 ;
        RECT  137.808 25.836 137.832 25.92 ;
    END
  END fd_in[768]
  PIN fd_in[769]
    DIRECTION INPUT ;
    USE SIGNAL ;
    PORT
      LAYER M5 ;
        RECT  137.952 25.836 137.976 25.92 ;
    END
  END fd_in[769]
  PIN fd_in[76]
    DIRECTION INPUT ;
    USE SIGNAL ;
    PORT
      LAYER M5 ;
        RECT  13.68 25.836 13.704 25.92 ;
    END
  END fd_in[76]
  PIN fd_in[770]
    DIRECTION INPUT ;
    USE SIGNAL ;
    PORT
      LAYER M5 ;
        RECT  138.144 25.836 138.168 25.92 ;
    END
  END fd_in[770]
  PIN fd_in[771]
    DIRECTION INPUT ;
    USE SIGNAL ;
    PORT
      LAYER M5 ;
        RECT  138.336 25.836 138.36 25.92 ;
    END
  END fd_in[771]
  PIN fd_in[772]
    DIRECTION INPUT ;
    USE SIGNAL ;
    PORT
      LAYER M5 ;
        RECT  138.528 25.836 138.552 25.92 ;
    END
  END fd_in[772]
  PIN fd_in[773]
    DIRECTION INPUT ;
    USE SIGNAL ;
    PORT
      LAYER M5 ;
        RECT  138.672 25.836 138.696 25.92 ;
    END
  END fd_in[773]
  PIN fd_in[774]
    DIRECTION INPUT ;
    USE SIGNAL ;
    PORT
      LAYER M5 ;
        RECT  138.864 25.836 138.888 25.92 ;
    END
  END fd_in[774]
  PIN fd_in[775]
    DIRECTION INPUT ;
    USE SIGNAL ;
    PORT
      LAYER M5 ;
        RECT  139.056 25.836 139.08 25.92 ;
    END
  END fd_in[775]
  PIN fd_in[776]
    DIRECTION INPUT ;
    USE SIGNAL ;
    PORT
      LAYER M5 ;
        RECT  139.248 25.836 139.272 25.92 ;
    END
  END fd_in[776]
  PIN fd_in[777]
    DIRECTION INPUT ;
    USE SIGNAL ;
    PORT
      LAYER M5 ;
        RECT  139.392 25.836 139.416 25.92 ;
    END
  END fd_in[777]
  PIN fd_in[778]
    DIRECTION INPUT ;
    USE SIGNAL ;
    PORT
      LAYER M5 ;
        RECT  139.584 25.836 139.608 25.92 ;
    END
  END fd_in[778]
  PIN fd_in[779]
    DIRECTION INPUT ;
    USE SIGNAL ;
    PORT
      LAYER M5 ;
        RECT  139.776 25.836 139.8 25.92 ;
    END
  END fd_in[779]
  PIN fd_in[77]
    DIRECTION INPUT ;
    USE SIGNAL ;
    PORT
      LAYER M5 ;
        RECT  13.872 25.836 13.896 25.92 ;
    END
  END fd_in[77]
  PIN fd_in[780]
    DIRECTION INPUT ;
    USE SIGNAL ;
    PORT
      LAYER M5 ;
        RECT  139.92 25.836 139.944 25.92 ;
    END
  END fd_in[780]
  PIN fd_in[781]
    DIRECTION INPUT ;
    USE SIGNAL ;
    PORT
      LAYER M5 ;
        RECT  140.112 25.836 140.136 25.92 ;
    END
  END fd_in[781]
  PIN fd_in[782]
    DIRECTION INPUT ;
    USE SIGNAL ;
    PORT
      LAYER M5 ;
        RECT  140.304 25.836 140.328 25.92 ;
    END
  END fd_in[782]
  PIN fd_in[783]
    DIRECTION INPUT ;
    USE SIGNAL ;
    PORT
      LAYER M5 ;
        RECT  140.496 25.836 140.52 25.92 ;
    END
  END fd_in[783]
  PIN fd_in[784]
    DIRECTION INPUT ;
    USE SIGNAL ;
    PORT
      LAYER M5 ;
        RECT  140.64 25.836 140.664 25.92 ;
    END
  END fd_in[784]
  PIN fd_in[785]
    DIRECTION INPUT ;
    USE SIGNAL ;
    PORT
      LAYER M5 ;
        RECT  140.832 25.836 140.856 25.92 ;
    END
  END fd_in[785]
  PIN fd_in[786]
    DIRECTION INPUT ;
    USE SIGNAL ;
    PORT
      LAYER M5 ;
        RECT  141.024 25.836 141.048 25.92 ;
    END
  END fd_in[786]
  PIN fd_in[787]
    DIRECTION INPUT ;
    USE SIGNAL ;
    PORT
      LAYER M5 ;
        RECT  141.216 25.836 141.24 25.92 ;
    END
  END fd_in[787]
  PIN fd_in[788]
    DIRECTION INPUT ;
    USE SIGNAL ;
    PORT
      LAYER M5 ;
        RECT  141.36 25.836 141.384 25.92 ;
    END
  END fd_in[788]
  PIN fd_in[789]
    DIRECTION INPUT ;
    USE SIGNAL ;
    PORT
      LAYER M5 ;
        RECT  141.552 25.836 141.576 25.92 ;
    END
  END fd_in[789]
  PIN fd_in[78]
    DIRECTION INPUT ;
    USE SIGNAL ;
    PORT
      LAYER M5 ;
        RECT  14.064 25.836 14.088 25.92 ;
    END
  END fd_in[78]
  PIN fd_in[790]
    DIRECTION INPUT ;
    USE SIGNAL ;
    PORT
      LAYER M5 ;
        RECT  141.744 25.836 141.768 25.92 ;
    END
  END fd_in[790]
  PIN fd_in[791]
    DIRECTION INPUT ;
    USE SIGNAL ;
    PORT
      LAYER M5 ;
        RECT  141.936 25.836 141.96 25.92 ;
    END
  END fd_in[791]
  PIN fd_in[792]
    DIRECTION INPUT ;
    USE SIGNAL ;
    PORT
      LAYER M5 ;
        RECT  142.08 25.836 142.104 25.92 ;
    END
  END fd_in[792]
  PIN fd_in[793]
    DIRECTION INPUT ;
    USE SIGNAL ;
    PORT
      LAYER M5 ;
        RECT  142.272 25.836 142.296 25.92 ;
    END
  END fd_in[793]
  PIN fd_in[794]
    DIRECTION INPUT ;
    USE SIGNAL ;
    PORT
      LAYER M5 ;
        RECT  142.464 25.836 142.488 25.92 ;
    END
  END fd_in[794]
  PIN fd_in[79]
    DIRECTION INPUT ;
    USE SIGNAL ;
    PORT
      LAYER M5 ;
        RECT  14.208 25.836 14.232 25.92 ;
    END
  END fd_in[79]
  PIN fd_in[7]
    DIRECTION INPUT ;
    USE SIGNAL ;
    PORT
      LAYER M5 ;
        RECT  1.296 25.836 1.32 25.92 ;
    END
  END fd_in[7]
  PIN fd_in[80]
    DIRECTION INPUT ;
    USE SIGNAL ;
    PORT
      LAYER M5 ;
        RECT  14.4 25.836 14.424 25.92 ;
    END
  END fd_in[80]
  PIN fd_in[81]
    DIRECTION INPUT ;
    USE SIGNAL ;
    PORT
      LAYER M5 ;
        RECT  14.592 25.836 14.616 25.92 ;
    END
  END fd_in[81]
  PIN fd_in[82]
    DIRECTION INPUT ;
    USE SIGNAL ;
    PORT
      LAYER M5 ;
        RECT  14.784 25.836 14.808 25.92 ;
    END
  END fd_in[82]
  PIN fd_in[83]
    DIRECTION INPUT ;
    USE SIGNAL ;
    PORT
      LAYER M5 ;
        RECT  14.928 25.836 14.952 25.92 ;
    END
  END fd_in[83]
  PIN fd_in[84]
    DIRECTION INPUT ;
    USE SIGNAL ;
    PORT
      LAYER M5 ;
        RECT  15.12 25.836 15.144 25.92 ;
    END
  END fd_in[84]
  PIN fd_in[85]
    DIRECTION INPUT ;
    USE SIGNAL ;
    PORT
      LAYER M5 ;
        RECT  15.312 25.836 15.336 25.92 ;
    END
  END fd_in[85]
  PIN fd_in[86]
    DIRECTION INPUT ;
    USE SIGNAL ;
    PORT
      LAYER M5 ;
        RECT  15.456 25.836 15.48 25.92 ;
    END
  END fd_in[86]
  PIN fd_in[87]
    DIRECTION INPUT ;
    USE SIGNAL ;
    PORT
      LAYER M5 ;
        RECT  15.648 25.836 15.672 25.92 ;
    END
  END fd_in[87]
  PIN fd_in[88]
    DIRECTION INPUT ;
    USE SIGNAL ;
    PORT
      LAYER M5 ;
        RECT  15.84 25.836 15.864 25.92 ;
    END
  END fd_in[88]
  PIN fd_in[89]
    DIRECTION INPUT ;
    USE SIGNAL ;
    PORT
      LAYER M5 ;
        RECT  16.032 25.836 16.056 25.92 ;
    END
  END fd_in[89]
  PIN fd_in[8]
    DIRECTION INPUT ;
    USE SIGNAL ;
    PORT
      LAYER M5 ;
        RECT  1.488 25.836 1.512 25.92 ;
    END
  END fd_in[8]
  PIN fd_in[90]
    DIRECTION INPUT ;
    USE SIGNAL ;
    PORT
      LAYER M5 ;
        RECT  16.176 25.836 16.2 25.92 ;
    END
  END fd_in[90]
  PIN fd_in[91]
    DIRECTION INPUT ;
    USE SIGNAL ;
    PORT
      LAYER M5 ;
        RECT  16.368 25.836 16.392 25.92 ;
    END
  END fd_in[91]
  PIN fd_in[92]
    DIRECTION INPUT ;
    USE SIGNAL ;
    PORT
      LAYER M5 ;
        RECT  16.56 25.836 16.584 25.92 ;
    END
  END fd_in[92]
  PIN fd_in[93]
    DIRECTION INPUT ;
    USE SIGNAL ;
    PORT
      LAYER M5 ;
        RECT  16.752 25.836 16.776 25.92 ;
    END
  END fd_in[93]
  PIN fd_in[94]
    DIRECTION INPUT ;
    USE SIGNAL ;
    PORT
      LAYER M5 ;
        RECT  16.896 25.836 16.92 25.92 ;
    END
  END fd_in[94]
  PIN fd_in[95]
    DIRECTION INPUT ;
    USE SIGNAL ;
    PORT
      LAYER M5 ;
        RECT  17.088 25.836 17.112 25.92 ;
    END
  END fd_in[95]
  PIN fd_in[96]
    DIRECTION INPUT ;
    USE SIGNAL ;
    PORT
      LAYER M5 ;
        RECT  17.28 25.836 17.304 25.92 ;
    END
  END fd_in[96]
  PIN fd_in[97]
    DIRECTION INPUT ;
    USE SIGNAL ;
    PORT
      LAYER M5 ;
        RECT  17.472 25.836 17.496 25.92 ;
    END
  END fd_in[97]
  PIN fd_in[98]
    DIRECTION INPUT ;
    USE SIGNAL ;
    PORT
      LAYER M5 ;
        RECT  17.616 25.836 17.64 25.92 ;
    END
  END fd_in[98]
  PIN fd_in[99]
    DIRECTION INPUT ;
    USE SIGNAL ;
    PORT
      LAYER M5 ;
        RECT  17.808 25.836 17.832 25.92 ;
    END
  END fd_in[99]
  PIN fd_in[9]
    DIRECTION INPUT ;
    USE SIGNAL ;
    PORT
      LAYER M5 ;
        RECT  1.68 25.836 1.704 25.92 ;
    END
  END fd_in[9]
  PIN fdm[0]
    DIRECTION OUTPUT ;
    USE SIGNAL ;
    PORT
      LAYER M5 ;
        RECT  0.048 0 0.072 0.084 ;
    END
  END fdm[0]
  PIN fdm[100]
    DIRECTION OUTPUT ;
    USE SIGNAL ;
    PORT
      LAYER M5 ;
        RECT  18 0 18.024 0.084 ;
    END
  END fdm[100]
  PIN fdm[101]
    DIRECTION OUTPUT ;
    USE SIGNAL ;
    PORT
      LAYER M5 ;
        RECT  18.192 0 18.216 0.084 ;
    END
  END fdm[101]
  PIN fdm[102]
    DIRECTION OUTPUT ;
    USE SIGNAL ;
    PORT
      LAYER M5 ;
        RECT  18.336 0 18.36 0.084 ;
    END
  END fdm[102]
  PIN fdm[103]
    DIRECTION OUTPUT ;
    USE SIGNAL ;
    PORT
      LAYER M5 ;
        RECT  18.528 0 18.552 0.084 ;
    END
  END fdm[103]
  PIN fdm[104]
    DIRECTION OUTPUT ;
    USE SIGNAL ;
    PORT
      LAYER M5 ;
        RECT  18.72 0 18.744 0.084 ;
    END
  END fdm[104]
  PIN fdm[105]
    DIRECTION OUTPUT ;
    USE SIGNAL ;
    PORT
      LAYER M5 ;
        RECT  18.864 0 18.888 0.084 ;
    END
  END fdm[105]
  PIN fdm[106]
    DIRECTION OUTPUT ;
    USE SIGNAL ;
    PORT
      LAYER M5 ;
        RECT  19.056 0 19.08 0.084 ;
    END
  END fdm[106]
  PIN fdm[107]
    DIRECTION OUTPUT ;
    USE SIGNAL ;
    PORT
      LAYER M5 ;
        RECT  19.248 0 19.272 0.084 ;
    END
  END fdm[107]
  PIN fdm[108]
    DIRECTION OUTPUT ;
    USE SIGNAL ;
    PORT
      LAYER M5 ;
        RECT  19.44 0 19.464 0.084 ;
    END
  END fdm[108]
  PIN fdm[109]
    DIRECTION OUTPUT ;
    USE SIGNAL ;
    PORT
      LAYER M5 ;
        RECT  19.584 0 19.608 0.084 ;
    END
  END fdm[109]
  PIN fdm[10]
    DIRECTION OUTPUT ;
    USE SIGNAL ;
    PORT
      LAYER M5 ;
        RECT  1.872 0 1.896 0.084 ;
    END
  END fdm[10]
  PIN fdm[110]
    DIRECTION OUTPUT ;
    USE SIGNAL ;
    PORT
      LAYER M5 ;
        RECT  19.776 0 19.8 0.084 ;
    END
  END fdm[110]
  PIN fdm[111]
    DIRECTION OUTPUT ;
    USE SIGNAL ;
    PORT
      LAYER M5 ;
        RECT  19.968 0 19.992 0.084 ;
    END
  END fdm[111]
  PIN fdm[112]
    DIRECTION OUTPUT ;
    USE SIGNAL ;
    PORT
      LAYER M5 ;
        RECT  20.16 0 20.184 0.084 ;
    END
  END fdm[112]
  PIN fdm[113]
    DIRECTION OUTPUT ;
    USE SIGNAL ;
    PORT
      LAYER M5 ;
        RECT  20.304 0 20.328 0.084 ;
    END
  END fdm[113]
  PIN fdm[114]
    DIRECTION OUTPUT ;
    USE SIGNAL ;
    PORT
      LAYER M5 ;
        RECT  20.496 0 20.52 0.084 ;
    END
  END fdm[114]
  PIN fdm[115]
    DIRECTION OUTPUT ;
    USE SIGNAL ;
    PORT
      LAYER M5 ;
        RECT  20.688 0 20.712 0.084 ;
    END
  END fdm[115]
  PIN fdm[116]
    DIRECTION OUTPUT ;
    USE SIGNAL ;
    PORT
      LAYER M5 ;
        RECT  20.88 0 20.904 0.084 ;
    END
  END fdm[116]
  PIN fdm[117]
    DIRECTION OUTPUT ;
    USE SIGNAL ;
    PORT
      LAYER M5 ;
        RECT  21.024 0 21.048 0.084 ;
    END
  END fdm[117]
  PIN fdm[118]
    DIRECTION OUTPUT ;
    USE SIGNAL ;
    PORT
      LAYER M5 ;
        RECT  21.216 0 21.24 0.084 ;
    END
  END fdm[118]
  PIN fdm[119]
    DIRECTION OUTPUT ;
    USE SIGNAL ;
    PORT
      LAYER M5 ;
        RECT  21.408 0 21.432 0.084 ;
    END
  END fdm[119]
  PIN fdm[11]
    DIRECTION OUTPUT ;
    USE SIGNAL ;
    PORT
      LAYER M5 ;
        RECT  2.016 0 2.04 0.084 ;
    END
  END fdm[11]
  PIN fdm[120]
    DIRECTION OUTPUT ;
    USE SIGNAL ;
    PORT
      LAYER M5 ;
        RECT  21.552 0 21.576 0.084 ;
    END
  END fdm[120]
  PIN fdm[121]
    DIRECTION OUTPUT ;
    USE SIGNAL ;
    PORT
      LAYER M5 ;
        RECT  21.744 0 21.768 0.084 ;
    END
  END fdm[121]
  PIN fdm[122]
    DIRECTION OUTPUT ;
    USE SIGNAL ;
    PORT
      LAYER M5 ;
        RECT  21.936 0 21.96 0.084 ;
    END
  END fdm[122]
  PIN fdm[123]
    DIRECTION OUTPUT ;
    USE SIGNAL ;
    PORT
      LAYER M5 ;
        RECT  22.128 0 22.152 0.084 ;
    END
  END fdm[123]
  PIN fdm[124]
    DIRECTION OUTPUT ;
    USE SIGNAL ;
    PORT
      LAYER M5 ;
        RECT  22.272 0 22.296 0.084 ;
    END
  END fdm[124]
  PIN fdm[125]
    DIRECTION OUTPUT ;
    USE SIGNAL ;
    PORT
      LAYER M5 ;
        RECT  22.464 0 22.488 0.084 ;
    END
  END fdm[125]
  PIN fdm[126]
    DIRECTION OUTPUT ;
    USE SIGNAL ;
    PORT
      LAYER M5 ;
        RECT  22.656 0 22.68 0.084 ;
    END
  END fdm[126]
  PIN fdm[127]
    DIRECTION OUTPUT ;
    USE SIGNAL ;
    PORT
      LAYER M5 ;
        RECT  22.848 0 22.872 0.084 ;
    END
  END fdm[127]
  PIN fdm[128]
    DIRECTION OUTPUT ;
    USE SIGNAL ;
    PORT
      LAYER M5 ;
        RECT  22.992 0 23.016 0.084 ;
    END
  END fdm[128]
  PIN fdm[129]
    DIRECTION OUTPUT ;
    USE SIGNAL ;
    PORT
      LAYER M5 ;
        RECT  23.184 0 23.208 0.084 ;
    END
  END fdm[129]
  PIN fdm[12]
    DIRECTION OUTPUT ;
    USE SIGNAL ;
    PORT
      LAYER M5 ;
        RECT  2.208 0 2.232 0.084 ;
    END
  END fdm[12]
  PIN fdm[130]
    DIRECTION OUTPUT ;
    USE SIGNAL ;
    PORT
      LAYER M5 ;
        RECT  23.376 0 23.4 0.084 ;
    END
  END fdm[130]
  PIN fdm[131]
    DIRECTION OUTPUT ;
    USE SIGNAL ;
    PORT
      LAYER M5 ;
        RECT  23.568 0 23.592 0.084 ;
    END
  END fdm[131]
  PIN fdm[132]
    DIRECTION OUTPUT ;
    USE SIGNAL ;
    PORT
      LAYER M5 ;
        RECT  23.712 0 23.736 0.084 ;
    END
  END fdm[132]
  PIN fdm[133]
    DIRECTION OUTPUT ;
    USE SIGNAL ;
    PORT
      LAYER M5 ;
        RECT  23.904 0 23.928 0.084 ;
    END
  END fdm[133]
  PIN fdm[134]
    DIRECTION OUTPUT ;
    USE SIGNAL ;
    PORT
      LAYER M5 ;
        RECT  24.096 0 24.12 0.084 ;
    END
  END fdm[134]
  PIN fdm[135]
    DIRECTION OUTPUT ;
    USE SIGNAL ;
    PORT
      LAYER M5 ;
        RECT  24.288 0 24.312 0.084 ;
    END
  END fdm[135]
  PIN fdm[136]
    DIRECTION OUTPUT ;
    USE SIGNAL ;
    PORT
      LAYER M5 ;
        RECT  24.432 0 24.456 0.084 ;
    END
  END fdm[136]
  PIN fdm[137]
    DIRECTION OUTPUT ;
    USE SIGNAL ;
    PORT
      LAYER M5 ;
        RECT  24.624 0 24.648 0.084 ;
    END
  END fdm[137]
  PIN fdm[138]
    DIRECTION OUTPUT ;
    USE SIGNAL ;
    PORT
      LAYER M5 ;
        RECT  24.816 0 24.84 0.084 ;
    END
  END fdm[138]
  PIN fdm[139]
    DIRECTION OUTPUT ;
    USE SIGNAL ;
    PORT
      LAYER M5 ;
        RECT  24.96 0 24.984 0.084 ;
    END
  END fdm[139]
  PIN fdm[13]
    DIRECTION OUTPUT ;
    USE SIGNAL ;
    PORT
      LAYER M5 ;
        RECT  2.4 0 2.424 0.084 ;
    END
  END fdm[13]
  PIN fdm[140]
    DIRECTION OUTPUT ;
    USE SIGNAL ;
    PORT
      LAYER M5 ;
        RECT  25.152 0 25.176 0.084 ;
    END
  END fdm[140]
  PIN fdm[141]
    DIRECTION OUTPUT ;
    USE SIGNAL ;
    PORT
      LAYER M5 ;
        RECT  25.344 0 25.368 0.084 ;
    END
  END fdm[141]
  PIN fdm[142]
    DIRECTION OUTPUT ;
    USE SIGNAL ;
    PORT
      LAYER M5 ;
        RECT  25.536 0 25.56 0.084 ;
    END
  END fdm[142]
  PIN fdm[143]
    DIRECTION OUTPUT ;
    USE SIGNAL ;
    PORT
      LAYER M5 ;
        RECT  25.68 0 25.704 0.084 ;
    END
  END fdm[143]
  PIN fdm[144]
    DIRECTION OUTPUT ;
    USE SIGNAL ;
    PORT
      LAYER M5 ;
        RECT  25.872 0 25.896 0.084 ;
    END
  END fdm[144]
  PIN fdm[145]
    DIRECTION OUTPUT ;
    USE SIGNAL ;
    PORT
      LAYER M5 ;
        RECT  26.064 0 26.088 0.084 ;
    END
  END fdm[145]
  PIN fdm[146]
    DIRECTION OUTPUT ;
    USE SIGNAL ;
    PORT
      LAYER M5 ;
        RECT  26.256 0 26.28 0.084 ;
    END
  END fdm[146]
  PIN fdm[147]
    DIRECTION OUTPUT ;
    USE SIGNAL ;
    PORT
      LAYER M5 ;
        RECT  26.4 0 26.424 0.084 ;
    END
  END fdm[147]
  PIN fdm[148]
    DIRECTION OUTPUT ;
    USE SIGNAL ;
    PORT
      LAYER M5 ;
        RECT  26.592 0 26.616 0.084 ;
    END
  END fdm[148]
  PIN fdm[149]
    DIRECTION OUTPUT ;
    USE SIGNAL ;
    PORT
      LAYER M5 ;
        RECT  26.784 0 26.808 0.084 ;
    END
  END fdm[149]
  PIN fdm[14]
    DIRECTION OUTPUT ;
    USE SIGNAL ;
    PORT
      LAYER M5 ;
        RECT  2.544 0 2.568 0.084 ;
    END
  END fdm[14]
  PIN fdm[150]
    DIRECTION OUTPUT ;
    USE SIGNAL ;
    PORT
      LAYER M5 ;
        RECT  26.976 0 27 0.084 ;
    END
  END fdm[150]
  PIN fdm[151]
    DIRECTION OUTPUT ;
    USE SIGNAL ;
    PORT
      LAYER M5 ;
        RECT  27.12 0 27.144 0.084 ;
    END
  END fdm[151]
  PIN fdm[152]
    DIRECTION OUTPUT ;
    USE SIGNAL ;
    PORT
      LAYER M5 ;
        RECT  27.312 0 27.336 0.084 ;
    END
  END fdm[152]
  PIN fdm[153]
    DIRECTION OUTPUT ;
    USE SIGNAL ;
    PORT
      LAYER M5 ;
        RECT  27.504 0 27.528 0.084 ;
    END
  END fdm[153]
  PIN fdm[154]
    DIRECTION OUTPUT ;
    USE SIGNAL ;
    PORT
      LAYER M5 ;
        RECT  27.696 0 27.72 0.084 ;
    END
  END fdm[154]
  PIN fdm[155]
    DIRECTION OUTPUT ;
    USE SIGNAL ;
    PORT
      LAYER M5 ;
        RECT  27.84 0 27.864 0.084 ;
    END
  END fdm[155]
  PIN fdm[156]
    DIRECTION OUTPUT ;
    USE SIGNAL ;
    PORT
      LAYER M5 ;
        RECT  28.032 0 28.056 0.084 ;
    END
  END fdm[156]
  PIN fdm[157]
    DIRECTION OUTPUT ;
    USE SIGNAL ;
    PORT
      LAYER M5 ;
        RECT  28.224 0 28.248 0.084 ;
    END
  END fdm[157]
  PIN fdm[158]
    DIRECTION OUTPUT ;
    USE SIGNAL ;
    PORT
      LAYER M5 ;
        RECT  28.368 0 28.392 0.084 ;
    END
  END fdm[158]
  PIN fdm[159]
    DIRECTION OUTPUT ;
    USE SIGNAL ;
    PORT
      LAYER M5 ;
        RECT  28.56 0 28.584 0.084 ;
    END
  END fdm[159]
  PIN fdm[15]
    DIRECTION OUTPUT ;
    USE SIGNAL ;
    PORT
      LAYER M5 ;
        RECT  2.736 0 2.76 0.084 ;
    END
  END fdm[15]
  PIN fdm[160]
    DIRECTION OUTPUT ;
    USE SIGNAL ;
    PORT
      LAYER M5 ;
        RECT  28.752 0 28.776 0.084 ;
    END
  END fdm[160]
  PIN fdm[161]
    DIRECTION OUTPUT ;
    USE SIGNAL ;
    PORT
      LAYER M5 ;
        RECT  28.944 0 28.968 0.084 ;
    END
  END fdm[161]
  PIN fdm[162]
    DIRECTION OUTPUT ;
    USE SIGNAL ;
    PORT
      LAYER M5 ;
        RECT  29.088 0 29.112 0.084 ;
    END
  END fdm[162]
  PIN fdm[163]
    DIRECTION OUTPUT ;
    USE SIGNAL ;
    PORT
      LAYER M5 ;
        RECT  29.28 0 29.304 0.084 ;
    END
  END fdm[163]
  PIN fdm[164]
    DIRECTION OUTPUT ;
    USE SIGNAL ;
    PORT
      LAYER M5 ;
        RECT  29.472 0 29.496 0.084 ;
    END
  END fdm[164]
  PIN fdm[165]
    DIRECTION OUTPUT ;
    USE SIGNAL ;
    PORT
      LAYER M5 ;
        RECT  29.664 0 29.688 0.084 ;
    END
  END fdm[165]
  PIN fdm[166]
    DIRECTION OUTPUT ;
    USE SIGNAL ;
    PORT
      LAYER M5 ;
        RECT  29.808 0 29.832 0.084 ;
    END
  END fdm[166]
  PIN fdm[167]
    DIRECTION OUTPUT ;
    USE SIGNAL ;
    PORT
      LAYER M5 ;
        RECT  30 0 30.024 0.084 ;
    END
  END fdm[167]
  PIN fdm[168]
    DIRECTION OUTPUT ;
    USE SIGNAL ;
    PORT
      LAYER M5 ;
        RECT  30.192 0 30.216 0.084 ;
    END
  END fdm[168]
  PIN fdm[169]
    DIRECTION OUTPUT ;
    USE SIGNAL ;
    PORT
      LAYER M5 ;
        RECT  30.384 0 30.408 0.084 ;
    END
  END fdm[169]
  PIN fdm[16]
    DIRECTION OUTPUT ;
    USE SIGNAL ;
    PORT
      LAYER M5 ;
        RECT  2.928 0 2.952 0.084 ;
    END
  END fdm[16]
  PIN fdm[170]
    DIRECTION OUTPUT ;
    USE SIGNAL ;
    PORT
      LAYER M5 ;
        RECT  30.528 0 30.552 0.084 ;
    END
  END fdm[170]
  PIN fdm[171]
    DIRECTION OUTPUT ;
    USE SIGNAL ;
    PORT
      LAYER M5 ;
        RECT  30.72 0 30.744 0.084 ;
    END
  END fdm[171]
  PIN fdm[172]
    DIRECTION OUTPUT ;
    USE SIGNAL ;
    PORT
      LAYER M5 ;
        RECT  30.912 0 30.936 0.084 ;
    END
  END fdm[172]
  PIN fdm[173]
    DIRECTION OUTPUT ;
    USE SIGNAL ;
    PORT
      LAYER M5 ;
        RECT  31.104 0 31.128 0.084 ;
    END
  END fdm[173]
  PIN fdm[174]
    DIRECTION OUTPUT ;
    USE SIGNAL ;
    PORT
      LAYER M5 ;
        RECT  31.248 0 31.272 0.084 ;
    END
  END fdm[174]
  PIN fdm[175]
    DIRECTION OUTPUT ;
    USE SIGNAL ;
    PORT
      LAYER M5 ;
        RECT  31.44 0 31.464 0.084 ;
    END
  END fdm[175]
  PIN fdm[176]
    DIRECTION OUTPUT ;
    USE SIGNAL ;
    PORT
      LAYER M5 ;
        RECT  31.632 0 31.656 0.084 ;
    END
  END fdm[176]
  PIN fdm[177]
    DIRECTION OUTPUT ;
    USE SIGNAL ;
    PORT
      LAYER M5 ;
        RECT  31.776 0 31.8 0.084 ;
    END
  END fdm[177]
  PIN fdm[178]
    DIRECTION OUTPUT ;
    USE SIGNAL ;
    PORT
      LAYER M5 ;
        RECT  31.968 0 31.992 0.084 ;
    END
  END fdm[178]
  PIN fdm[179]
    DIRECTION OUTPUT ;
    USE SIGNAL ;
    PORT
      LAYER M5 ;
        RECT  32.16 0 32.184 0.084 ;
    END
  END fdm[179]
  PIN fdm[17]
    DIRECTION OUTPUT ;
    USE SIGNAL ;
    PORT
      LAYER M5 ;
        RECT  3.12 0 3.144 0.084 ;
    END
  END fdm[17]
  PIN fdm[180]
    DIRECTION OUTPUT ;
    USE SIGNAL ;
    PORT
      LAYER M5 ;
        RECT  32.352 0 32.376 0.084 ;
    END
  END fdm[180]
  PIN fdm[181]
    DIRECTION OUTPUT ;
    USE SIGNAL ;
    PORT
      LAYER M5 ;
        RECT  32.496 0 32.52 0.084 ;
    END
  END fdm[181]
  PIN fdm[182]
    DIRECTION OUTPUT ;
    USE SIGNAL ;
    PORT
      LAYER M5 ;
        RECT  32.688 0 32.712 0.084 ;
    END
  END fdm[182]
  PIN fdm[183]
    DIRECTION OUTPUT ;
    USE SIGNAL ;
    PORT
      LAYER M5 ;
        RECT  32.88 0 32.904 0.084 ;
    END
  END fdm[183]
  PIN fdm[184]
    DIRECTION OUTPUT ;
    USE SIGNAL ;
    PORT
      LAYER M5 ;
        RECT  33.072 0 33.096 0.084 ;
    END
  END fdm[184]
  PIN fdm[185]
    DIRECTION OUTPUT ;
    USE SIGNAL ;
    PORT
      LAYER M5 ;
        RECT  33.216 0 33.24 0.084 ;
    END
  END fdm[185]
  PIN fdm[186]
    DIRECTION OUTPUT ;
    USE SIGNAL ;
    PORT
      LAYER M5 ;
        RECT  33.408 0 33.432 0.084 ;
    END
  END fdm[186]
  PIN fdm[187]
    DIRECTION OUTPUT ;
    USE SIGNAL ;
    PORT
      LAYER M5 ;
        RECT  33.6 0 33.624 0.084 ;
    END
  END fdm[187]
  PIN fdm[188]
    DIRECTION OUTPUT ;
    USE SIGNAL ;
    PORT
      LAYER M5 ;
        RECT  33.792 0 33.816 0.084 ;
    END
  END fdm[188]
  PIN fdm[189]
    DIRECTION OUTPUT ;
    USE SIGNAL ;
    PORT
      LAYER M5 ;
        RECT  33.936 0 33.96 0.084 ;
    END
  END fdm[189]
  PIN fdm[18]
    DIRECTION OUTPUT ;
    USE SIGNAL ;
    PORT
      LAYER M5 ;
        RECT  3.264 0 3.288 0.084 ;
    END
  END fdm[18]
  PIN fdm[190]
    DIRECTION OUTPUT ;
    USE SIGNAL ;
    PORT
      LAYER M5 ;
        RECT  34.128 0 34.152 0.084 ;
    END
  END fdm[190]
  PIN fdm[191]
    DIRECTION OUTPUT ;
    USE SIGNAL ;
    PORT
      LAYER M5 ;
        RECT  34.32 0 34.344 0.084 ;
    END
  END fdm[191]
  PIN fdm[192]
    DIRECTION OUTPUT ;
    USE SIGNAL ;
    PORT
      LAYER M5 ;
        RECT  34.512 0 34.536 0.084 ;
    END
  END fdm[192]
  PIN fdm[193]
    DIRECTION OUTPUT ;
    USE SIGNAL ;
    PORT
      LAYER M5 ;
        RECT  34.656 0 34.68 0.084 ;
    END
  END fdm[193]
  PIN fdm[194]
    DIRECTION OUTPUT ;
    USE SIGNAL ;
    PORT
      LAYER M5 ;
        RECT  34.848 0 34.872 0.084 ;
    END
  END fdm[194]
  PIN fdm[195]
    DIRECTION OUTPUT ;
    USE SIGNAL ;
    PORT
      LAYER M5 ;
        RECT  35.04 0 35.064 0.084 ;
    END
  END fdm[195]
  PIN fdm[196]
    DIRECTION OUTPUT ;
    USE SIGNAL ;
    PORT
      LAYER M5 ;
        RECT  35.184 0 35.208 0.084 ;
    END
  END fdm[196]
  PIN fdm[197]
    DIRECTION OUTPUT ;
    USE SIGNAL ;
    PORT
      LAYER M5 ;
        RECT  35.376 0 35.4 0.084 ;
    END
  END fdm[197]
  PIN fdm[198]
    DIRECTION OUTPUT ;
    USE SIGNAL ;
    PORT
      LAYER M5 ;
        RECT  35.568 0 35.592 0.084 ;
    END
  END fdm[198]
  PIN fdm[199]
    DIRECTION OUTPUT ;
    USE SIGNAL ;
    PORT
      LAYER M5 ;
        RECT  35.76 0 35.784 0.084 ;
    END
  END fdm[199]
  PIN fdm[19]
    DIRECTION OUTPUT ;
    USE SIGNAL ;
    PORT
      LAYER M5 ;
        RECT  3.456 0 3.48 0.084 ;
    END
  END fdm[19]
  PIN fdm[1]
    DIRECTION OUTPUT ;
    USE SIGNAL ;
    PORT
      LAYER M5 ;
        RECT  0.24 0 0.264 0.084 ;
    END
  END fdm[1]
  PIN fdm[200]
    DIRECTION OUTPUT ;
    USE SIGNAL ;
    PORT
      LAYER M5 ;
        RECT  35.904 0 35.928 0.084 ;
    END
  END fdm[200]
  PIN fdm[201]
    DIRECTION OUTPUT ;
    USE SIGNAL ;
    PORT
      LAYER M5 ;
        RECT  36.096 0 36.12 0.084 ;
    END
  END fdm[201]
  PIN fdm[202]
    DIRECTION OUTPUT ;
    USE SIGNAL ;
    PORT
      LAYER M5 ;
        RECT  36.288 0 36.312 0.084 ;
    END
  END fdm[202]
  PIN fdm[203]
    DIRECTION OUTPUT ;
    USE SIGNAL ;
    PORT
      LAYER M5 ;
        RECT  36.48 0 36.504 0.084 ;
    END
  END fdm[203]
  PIN fdm[204]
    DIRECTION OUTPUT ;
    USE SIGNAL ;
    PORT
      LAYER M5 ;
        RECT  36.624 0 36.648 0.084 ;
    END
  END fdm[204]
  PIN fdm[205]
    DIRECTION OUTPUT ;
    USE SIGNAL ;
    PORT
      LAYER M5 ;
        RECT  36.816 0 36.84 0.084 ;
    END
  END fdm[205]
  PIN fdm[206]
    DIRECTION OUTPUT ;
    USE SIGNAL ;
    PORT
      LAYER M5 ;
        RECT  37.008 0 37.032 0.084 ;
    END
  END fdm[206]
  PIN fdm[207]
    DIRECTION OUTPUT ;
    USE SIGNAL ;
    PORT
      LAYER M5 ;
        RECT  37.2 0 37.224 0.084 ;
    END
  END fdm[207]
  PIN fdm[208]
    DIRECTION OUTPUT ;
    USE SIGNAL ;
    PORT
      LAYER M5 ;
        RECT  37.344 0 37.368 0.084 ;
    END
  END fdm[208]
  PIN fdm[209]
    DIRECTION OUTPUT ;
    USE SIGNAL ;
    PORT
      LAYER M5 ;
        RECT  37.536 0 37.56 0.084 ;
    END
  END fdm[209]
  PIN fdm[20]
    DIRECTION OUTPUT ;
    USE SIGNAL ;
    PORT
      LAYER M5 ;
        RECT  3.648 0 3.672 0.084 ;
    END
  END fdm[20]
  PIN fdm[210]
    DIRECTION OUTPUT ;
    USE SIGNAL ;
    PORT
      LAYER M5 ;
        RECT  37.728 0 37.752 0.084 ;
    END
  END fdm[210]
  PIN fdm[211]
    DIRECTION OUTPUT ;
    USE SIGNAL ;
    PORT
      LAYER M5 ;
        RECT  37.92 0 37.944 0.084 ;
    END
  END fdm[211]
  PIN fdm[212]
    DIRECTION OUTPUT ;
    USE SIGNAL ;
    PORT
      LAYER M5 ;
        RECT  38.064 0 38.088 0.084 ;
    END
  END fdm[212]
  PIN fdm[213]
    DIRECTION OUTPUT ;
    USE SIGNAL ;
    PORT
      LAYER M5 ;
        RECT  38.256 0 38.28 0.084 ;
    END
  END fdm[213]
  PIN fdm[214]
    DIRECTION OUTPUT ;
    USE SIGNAL ;
    PORT
      LAYER M5 ;
        RECT  38.448 0 38.472 0.084 ;
    END
  END fdm[214]
  PIN fdm[215]
    DIRECTION OUTPUT ;
    USE SIGNAL ;
    PORT
      LAYER M5 ;
        RECT  38.592 0 38.616 0.084 ;
    END
  END fdm[215]
  PIN fdm[216]
    DIRECTION OUTPUT ;
    USE SIGNAL ;
    PORT
      LAYER M5 ;
        RECT  38.784 0 38.808 0.084 ;
    END
  END fdm[216]
  PIN fdm[217]
    DIRECTION OUTPUT ;
    USE SIGNAL ;
    PORT
      LAYER M5 ;
        RECT  38.976 0 39 0.084 ;
    END
  END fdm[217]
  PIN fdm[218]
    DIRECTION OUTPUT ;
    USE SIGNAL ;
    PORT
      LAYER M5 ;
        RECT  39.168 0 39.192 0.084 ;
    END
  END fdm[218]
  PIN fdm[219]
    DIRECTION OUTPUT ;
    USE SIGNAL ;
    PORT
      LAYER M5 ;
        RECT  39.312 0 39.336 0.084 ;
    END
  END fdm[219]
  PIN fdm[21]
    DIRECTION OUTPUT ;
    USE SIGNAL ;
    PORT
      LAYER M5 ;
        RECT  3.84 0 3.864 0.084 ;
    END
  END fdm[21]
  PIN fdm[220]
    DIRECTION OUTPUT ;
    USE SIGNAL ;
    PORT
      LAYER M5 ;
        RECT  39.504 0 39.528 0.084 ;
    END
  END fdm[220]
  PIN fdm[221]
    DIRECTION OUTPUT ;
    USE SIGNAL ;
    PORT
      LAYER M5 ;
        RECT  39.696 0 39.72 0.084 ;
    END
  END fdm[221]
  PIN fdm[222]
    DIRECTION OUTPUT ;
    USE SIGNAL ;
    PORT
      LAYER M5 ;
        RECT  39.888 0 39.912 0.084 ;
    END
  END fdm[222]
  PIN fdm[223]
    DIRECTION OUTPUT ;
    USE SIGNAL ;
    PORT
      LAYER M5 ;
        RECT  40.032 0 40.056 0.084 ;
    END
  END fdm[223]
  PIN fdm[224]
    DIRECTION OUTPUT ;
    USE SIGNAL ;
    PORT
      LAYER M5 ;
        RECT  40.224 0 40.248 0.084 ;
    END
  END fdm[224]
  PIN fdm[225]
    DIRECTION OUTPUT ;
    USE SIGNAL ;
    PORT
      LAYER M5 ;
        RECT  40.416 0 40.44 0.084 ;
    END
  END fdm[225]
  PIN fdm[226]
    DIRECTION OUTPUT ;
    USE SIGNAL ;
    PORT
      LAYER M5 ;
        RECT  40.608 0 40.632 0.084 ;
    END
  END fdm[226]
  PIN fdm[227]
    DIRECTION OUTPUT ;
    USE SIGNAL ;
    PORT
      LAYER M5 ;
        RECT  40.752 0 40.776 0.084 ;
    END
  END fdm[227]
  PIN fdm[228]
    DIRECTION OUTPUT ;
    USE SIGNAL ;
    PORT
      LAYER M5 ;
        RECT  40.944 0 40.968 0.084 ;
    END
  END fdm[228]
  PIN fdm[229]
    DIRECTION OUTPUT ;
    USE SIGNAL ;
    PORT
      LAYER M5 ;
        RECT  41.136 0 41.16 0.084 ;
    END
  END fdm[229]
  PIN fdm[22]
    DIRECTION OUTPUT ;
    USE SIGNAL ;
    PORT
      LAYER M5 ;
        RECT  3.984 0 4.008 0.084 ;
    END
  END fdm[22]
  PIN fdm[230]
    DIRECTION OUTPUT ;
    USE SIGNAL ;
    PORT
      LAYER M5 ;
        RECT  41.28 0 41.304 0.084 ;
    END
  END fdm[230]
  PIN fdm[231]
    DIRECTION OUTPUT ;
    USE SIGNAL ;
    PORT
      LAYER M5 ;
        RECT  41.472 0 41.496 0.084 ;
    END
  END fdm[231]
  PIN fdm[232]
    DIRECTION OUTPUT ;
    USE SIGNAL ;
    PORT
      LAYER M5 ;
        RECT  41.664 0 41.688 0.084 ;
    END
  END fdm[232]
  PIN fdm[233]
    DIRECTION OUTPUT ;
    USE SIGNAL ;
    PORT
      LAYER M5 ;
        RECT  41.856 0 41.88 0.084 ;
    END
  END fdm[233]
  PIN fdm[234]
    DIRECTION OUTPUT ;
    USE SIGNAL ;
    PORT
      LAYER M5 ;
        RECT  42 0 42.024 0.084 ;
    END
  END fdm[234]
  PIN fdm[235]
    DIRECTION OUTPUT ;
    USE SIGNAL ;
    PORT
      LAYER M5 ;
        RECT  42.192 0 42.216 0.084 ;
    END
  END fdm[235]
  PIN fdm[236]
    DIRECTION OUTPUT ;
    USE SIGNAL ;
    PORT
      LAYER M5 ;
        RECT  42.384 0 42.408 0.084 ;
    END
  END fdm[236]
  PIN fdm[237]
    DIRECTION OUTPUT ;
    USE SIGNAL ;
    PORT
      LAYER M5 ;
        RECT  42.576 0 42.6 0.084 ;
    END
  END fdm[237]
  PIN fdm[238]
    DIRECTION OUTPUT ;
    USE SIGNAL ;
    PORT
      LAYER M5 ;
        RECT  42.72 0 42.744 0.084 ;
    END
  END fdm[238]
  PIN fdm[239]
    DIRECTION OUTPUT ;
    USE SIGNAL ;
    PORT
      LAYER M5 ;
        RECT  42.912 0 42.936 0.084 ;
    END
  END fdm[239]
  PIN fdm[23]
    DIRECTION OUTPUT ;
    USE SIGNAL ;
    PORT
      LAYER M5 ;
        RECT  4.176 0 4.2 0.084 ;
    END
  END fdm[23]
  PIN fdm[240]
    DIRECTION OUTPUT ;
    USE SIGNAL ;
    PORT
      LAYER M5 ;
        RECT  43.104 0 43.128 0.084 ;
    END
  END fdm[240]
  PIN fdm[241]
    DIRECTION OUTPUT ;
    USE SIGNAL ;
    PORT
      LAYER M5 ;
        RECT  43.296 0 43.32 0.084 ;
    END
  END fdm[241]
  PIN fdm[242]
    DIRECTION OUTPUT ;
    USE SIGNAL ;
    PORT
      LAYER M5 ;
        RECT  43.44 0 43.464 0.084 ;
    END
  END fdm[242]
  PIN fdm[243]
    DIRECTION OUTPUT ;
    USE SIGNAL ;
    PORT
      LAYER M5 ;
        RECT  43.632 0 43.656 0.084 ;
    END
  END fdm[243]
  PIN fdm[244]
    DIRECTION OUTPUT ;
    USE SIGNAL ;
    PORT
      LAYER M5 ;
        RECT  43.824 0 43.848 0.084 ;
    END
  END fdm[244]
  PIN fdm[245]
    DIRECTION OUTPUT ;
    USE SIGNAL ;
    PORT
      LAYER M5 ;
        RECT  44.016 0 44.04 0.084 ;
    END
  END fdm[245]
  PIN fdm[246]
    DIRECTION OUTPUT ;
    USE SIGNAL ;
    PORT
      LAYER M5 ;
        RECT  44.16 0 44.184 0.084 ;
    END
  END fdm[246]
  PIN fdm[247]
    DIRECTION OUTPUT ;
    USE SIGNAL ;
    PORT
      LAYER M5 ;
        RECT  44.352 0 44.376 0.084 ;
    END
  END fdm[247]
  PIN fdm[248]
    DIRECTION OUTPUT ;
    USE SIGNAL ;
    PORT
      LAYER M5 ;
        RECT  44.544 0 44.568 0.084 ;
    END
  END fdm[248]
  PIN fdm[249]
    DIRECTION OUTPUT ;
    USE SIGNAL ;
    PORT
      LAYER M5 ;
        RECT  44.688 0 44.712 0.084 ;
    END
  END fdm[249]
  PIN fdm[24]
    DIRECTION OUTPUT ;
    USE SIGNAL ;
    PORT
      LAYER M5 ;
        RECT  4.368 0 4.392 0.084 ;
    END
  END fdm[24]
  PIN fdm[250]
    DIRECTION OUTPUT ;
    USE SIGNAL ;
    PORT
      LAYER M5 ;
        RECT  44.88 0 44.904 0.084 ;
    END
  END fdm[250]
  PIN fdm[251]
    DIRECTION OUTPUT ;
    USE SIGNAL ;
    PORT
      LAYER M5 ;
        RECT  45.072 0 45.096 0.084 ;
    END
  END fdm[251]
  PIN fdm[252]
    DIRECTION OUTPUT ;
    USE SIGNAL ;
    PORT
      LAYER M5 ;
        RECT  45.264 0 45.288 0.084 ;
    END
  END fdm[252]
  PIN fdm[253]
    DIRECTION OUTPUT ;
    USE SIGNAL ;
    PORT
      LAYER M5 ;
        RECT  45.408 0 45.432 0.084 ;
    END
  END fdm[253]
  PIN fdm[254]
    DIRECTION OUTPUT ;
    USE SIGNAL ;
    PORT
      LAYER M5 ;
        RECT  45.6 0 45.624 0.084 ;
    END
  END fdm[254]
  PIN fdm[255]
    DIRECTION OUTPUT ;
    USE SIGNAL ;
    PORT
      LAYER M5 ;
        RECT  45.792 0 45.816 0.084 ;
    END
  END fdm[255]
  PIN fdm[256]
    DIRECTION OUTPUT ;
    USE SIGNAL ;
    PORT
      LAYER M5 ;
        RECT  45.984 0 46.008 0.084 ;
    END
  END fdm[256]
  PIN fdm[257]
    DIRECTION OUTPUT ;
    USE SIGNAL ;
    PORT
      LAYER M5 ;
        RECT  46.128 0 46.152 0.084 ;
    END
  END fdm[257]
  PIN fdm[258]
    DIRECTION OUTPUT ;
    USE SIGNAL ;
    PORT
      LAYER M5 ;
        RECT  46.32 0 46.344 0.084 ;
    END
  END fdm[258]
  PIN fdm[259]
    DIRECTION OUTPUT ;
    USE SIGNAL ;
    PORT
      LAYER M5 ;
        RECT  46.512 0 46.536 0.084 ;
    END
  END fdm[259]
  PIN fdm[25]
    DIRECTION OUTPUT ;
    USE SIGNAL ;
    PORT
      LAYER M5 ;
        RECT  4.56 0 4.584 0.084 ;
    END
  END fdm[25]
  PIN fdm[260]
    DIRECTION OUTPUT ;
    USE SIGNAL ;
    PORT
      LAYER M5 ;
        RECT  46.704 0 46.728 0.084 ;
    END
  END fdm[260]
  PIN fdm[261]
    DIRECTION OUTPUT ;
    USE SIGNAL ;
    PORT
      LAYER M5 ;
        RECT  46.848 0 46.872 0.084 ;
    END
  END fdm[261]
  PIN fdm[262]
    DIRECTION OUTPUT ;
    USE SIGNAL ;
    PORT
      LAYER M5 ;
        RECT  47.04 0 47.064 0.084 ;
    END
  END fdm[262]
  PIN fdm[263]
    DIRECTION OUTPUT ;
    USE SIGNAL ;
    PORT
      LAYER M5 ;
        RECT  47.232 0 47.256 0.084 ;
    END
  END fdm[263]
  PIN fdm[264]
    DIRECTION OUTPUT ;
    USE SIGNAL ;
    PORT
      LAYER M5 ;
        RECT  47.424 0 47.448 0.084 ;
    END
  END fdm[264]
  PIN fdm[265]
    DIRECTION OUTPUT ;
    USE SIGNAL ;
    PORT
      LAYER M5 ;
        RECT  47.568 0 47.592 0.084 ;
    END
  END fdm[265]
  PIN fdm[266]
    DIRECTION OUTPUT ;
    USE SIGNAL ;
    PORT
      LAYER M5 ;
        RECT  47.76 0 47.784 0.084 ;
    END
  END fdm[266]
  PIN fdm[267]
    DIRECTION OUTPUT ;
    USE SIGNAL ;
    PORT
      LAYER M5 ;
        RECT  47.952 0 47.976 0.084 ;
    END
  END fdm[267]
  PIN fdm[268]
    DIRECTION OUTPUT ;
    USE SIGNAL ;
    PORT
      LAYER M5 ;
        RECT  48.096 0 48.12 0.084 ;
    END
  END fdm[268]
  PIN fdm[269]
    DIRECTION OUTPUT ;
    USE SIGNAL ;
    PORT
      LAYER M5 ;
        RECT  48.288 0 48.312 0.084 ;
    END
  END fdm[269]
  PIN fdm[26]
    DIRECTION OUTPUT ;
    USE SIGNAL ;
    PORT
      LAYER M5 ;
        RECT  4.704 0 4.728 0.084 ;
    END
  END fdm[26]
  PIN fdm[270]
    DIRECTION OUTPUT ;
    USE SIGNAL ;
    PORT
      LAYER M5 ;
        RECT  48.48 0 48.504 0.084 ;
    END
  END fdm[270]
  PIN fdm[271]
    DIRECTION OUTPUT ;
    USE SIGNAL ;
    PORT
      LAYER M5 ;
        RECT  48.672 0 48.696 0.084 ;
    END
  END fdm[271]
  PIN fdm[272]
    DIRECTION OUTPUT ;
    USE SIGNAL ;
    PORT
      LAYER M5 ;
        RECT  48.816 0 48.84 0.084 ;
    END
  END fdm[272]
  PIN fdm[273]
    DIRECTION OUTPUT ;
    USE SIGNAL ;
    PORT
      LAYER M5 ;
        RECT  49.008 0 49.032 0.084 ;
    END
  END fdm[273]
  PIN fdm[274]
    DIRECTION OUTPUT ;
    USE SIGNAL ;
    PORT
      LAYER M5 ;
        RECT  49.2 0 49.224 0.084 ;
    END
  END fdm[274]
  PIN fdm[275]
    DIRECTION OUTPUT ;
    USE SIGNAL ;
    PORT
      LAYER M5 ;
        RECT  49.392 0 49.416 0.084 ;
    END
  END fdm[275]
  PIN fdm[276]
    DIRECTION OUTPUT ;
    USE SIGNAL ;
    PORT
      LAYER M5 ;
        RECT  49.536 0 49.56 0.084 ;
    END
  END fdm[276]
  PIN fdm[277]
    DIRECTION OUTPUT ;
    USE SIGNAL ;
    PORT
      LAYER M5 ;
        RECT  49.728 0 49.752 0.084 ;
    END
  END fdm[277]
  PIN fdm[278]
    DIRECTION OUTPUT ;
    USE SIGNAL ;
    PORT
      LAYER M5 ;
        RECT  49.92 0 49.944 0.084 ;
    END
  END fdm[278]
  PIN fdm[279]
    DIRECTION OUTPUT ;
    USE SIGNAL ;
    PORT
      LAYER M5 ;
        RECT  50.112 0 50.136 0.084 ;
    END
  END fdm[279]
  PIN fdm[27]
    DIRECTION OUTPUT ;
    USE SIGNAL ;
    PORT
      LAYER M5 ;
        RECT  4.896 0 4.92 0.084 ;
    END
  END fdm[27]
  PIN fdm[280]
    DIRECTION OUTPUT ;
    USE SIGNAL ;
    PORT
      LAYER M5 ;
        RECT  50.256 0 50.28 0.084 ;
    END
  END fdm[280]
  PIN fdm[281]
    DIRECTION OUTPUT ;
    USE SIGNAL ;
    PORT
      LAYER M5 ;
        RECT  50.448 0 50.472 0.084 ;
    END
  END fdm[281]
  PIN fdm[282]
    DIRECTION OUTPUT ;
    USE SIGNAL ;
    PORT
      LAYER M5 ;
        RECT  50.64 0 50.664 0.084 ;
    END
  END fdm[282]
  PIN fdm[283]
    DIRECTION OUTPUT ;
    USE SIGNAL ;
    PORT
      LAYER M5 ;
        RECT  50.832 0 50.856 0.084 ;
    END
  END fdm[283]
  PIN fdm[284]
    DIRECTION OUTPUT ;
    USE SIGNAL ;
    PORT
      LAYER M5 ;
        RECT  50.976 0 51 0.084 ;
    END
  END fdm[284]
  PIN fdm[285]
    DIRECTION OUTPUT ;
    USE SIGNAL ;
    PORT
      LAYER M5 ;
        RECT  51.168 0 51.192 0.084 ;
    END
  END fdm[285]
  PIN fdm[286]
    DIRECTION OUTPUT ;
    USE SIGNAL ;
    PORT
      LAYER M5 ;
        RECT  51.36 0 51.384 0.084 ;
    END
  END fdm[286]
  PIN fdm[287]
    DIRECTION OUTPUT ;
    USE SIGNAL ;
    PORT
      LAYER M5 ;
        RECT  51.504 0 51.528 0.084 ;
    END
  END fdm[287]
  PIN fdm[288]
    DIRECTION OUTPUT ;
    USE SIGNAL ;
    PORT
      LAYER M5 ;
        RECT  51.696 0 51.72 0.084 ;
    END
  END fdm[288]
  PIN fdm[289]
    DIRECTION OUTPUT ;
    USE SIGNAL ;
    PORT
      LAYER M5 ;
        RECT  51.888 0 51.912 0.084 ;
    END
  END fdm[289]
  PIN fdm[28]
    DIRECTION OUTPUT ;
    USE SIGNAL ;
    PORT
      LAYER M5 ;
        RECT  5.088 0 5.112 0.084 ;
    END
  END fdm[28]
  PIN fdm[290]
    DIRECTION OUTPUT ;
    USE SIGNAL ;
    PORT
      LAYER M5 ;
        RECT  52.08 0 52.104 0.084 ;
    END
  END fdm[290]
  PIN fdm[291]
    DIRECTION OUTPUT ;
    USE SIGNAL ;
    PORT
      LAYER M5 ;
        RECT  52.224 0 52.248 0.084 ;
    END
  END fdm[291]
  PIN fdm[292]
    DIRECTION OUTPUT ;
    USE SIGNAL ;
    PORT
      LAYER M5 ;
        RECT  52.416 0 52.44 0.084 ;
    END
  END fdm[292]
  PIN fdm[293]
    DIRECTION OUTPUT ;
    USE SIGNAL ;
    PORT
      LAYER M5 ;
        RECT  52.608 0 52.632 0.084 ;
    END
  END fdm[293]
  PIN fdm[294]
    DIRECTION OUTPUT ;
    USE SIGNAL ;
    PORT
      LAYER M5 ;
        RECT  52.8 0 52.824 0.084 ;
    END
  END fdm[294]
  PIN fdm[295]
    DIRECTION OUTPUT ;
    USE SIGNAL ;
    PORT
      LAYER M5 ;
        RECT  52.944 0 52.968 0.084 ;
    END
  END fdm[295]
  PIN fdm[296]
    DIRECTION OUTPUT ;
    USE SIGNAL ;
    PORT
      LAYER M5 ;
        RECT  53.136 0 53.16 0.084 ;
    END
  END fdm[296]
  PIN fdm[297]
    DIRECTION OUTPUT ;
    USE SIGNAL ;
    PORT
      LAYER M5 ;
        RECT  53.328 0 53.352 0.084 ;
    END
  END fdm[297]
  PIN fdm[298]
    DIRECTION OUTPUT ;
    USE SIGNAL ;
    PORT
      LAYER M5 ;
        RECT  53.52 0 53.544 0.084 ;
    END
  END fdm[298]
  PIN fdm[299]
    DIRECTION OUTPUT ;
    USE SIGNAL ;
    PORT
      LAYER M5 ;
        RECT  53.664 0 53.688 0.084 ;
    END
  END fdm[299]
  PIN fdm[29]
    DIRECTION OUTPUT ;
    USE SIGNAL ;
    PORT
      LAYER M5 ;
        RECT  5.232 0 5.256 0.084 ;
    END
  END fdm[29]
  PIN fdm[2]
    DIRECTION OUTPUT ;
    USE SIGNAL ;
    PORT
      LAYER M5 ;
        RECT  0.432 0 0.456 0.084 ;
    END
  END fdm[2]
  PIN fdm[300]
    DIRECTION OUTPUT ;
    USE SIGNAL ;
    PORT
      LAYER M5 ;
        RECT  53.856 0 53.88 0.084 ;
    END
  END fdm[300]
  PIN fdm[301]
    DIRECTION OUTPUT ;
    USE SIGNAL ;
    PORT
      LAYER M5 ;
        RECT  54.048 0 54.072 0.084 ;
    END
  END fdm[301]
  PIN fdm[302]
    DIRECTION OUTPUT ;
    USE SIGNAL ;
    PORT
      LAYER M5 ;
        RECT  54.24 0 54.264 0.084 ;
    END
  END fdm[302]
  PIN fdm[303]
    DIRECTION OUTPUT ;
    USE SIGNAL ;
    PORT
      LAYER M5 ;
        RECT  54.384 0 54.408 0.084 ;
    END
  END fdm[303]
  PIN fdm[304]
    DIRECTION OUTPUT ;
    USE SIGNAL ;
    PORT
      LAYER M5 ;
        RECT  54.576 0 54.6 0.084 ;
    END
  END fdm[304]
  PIN fdm[305]
    DIRECTION OUTPUT ;
    USE SIGNAL ;
    PORT
      LAYER M5 ;
        RECT  54.768 0 54.792 0.084 ;
    END
  END fdm[305]
  PIN fdm[306]
    DIRECTION OUTPUT ;
    USE SIGNAL ;
    PORT
      LAYER M5 ;
        RECT  54.912 0 54.936 0.084 ;
    END
  END fdm[306]
  PIN fdm[307]
    DIRECTION OUTPUT ;
    USE SIGNAL ;
    PORT
      LAYER M5 ;
        RECT  55.104 0 55.128 0.084 ;
    END
  END fdm[307]
  PIN fdm[308]
    DIRECTION OUTPUT ;
    USE SIGNAL ;
    PORT
      LAYER M5 ;
        RECT  55.296 0 55.32 0.084 ;
    END
  END fdm[308]
  PIN fdm[309]
    DIRECTION OUTPUT ;
    USE SIGNAL ;
    PORT
      LAYER M5 ;
        RECT  55.488 0 55.512 0.084 ;
    END
  END fdm[309]
  PIN fdm[30]
    DIRECTION OUTPUT ;
    USE SIGNAL ;
    PORT
      LAYER M5 ;
        RECT  5.424 0 5.448 0.084 ;
    END
  END fdm[30]
  PIN fdm[310]
    DIRECTION OUTPUT ;
    USE SIGNAL ;
    PORT
      LAYER M5 ;
        RECT  55.632 0 55.656 0.084 ;
    END
  END fdm[310]
  PIN fdm[311]
    DIRECTION OUTPUT ;
    USE SIGNAL ;
    PORT
      LAYER M5 ;
        RECT  55.824 0 55.848 0.084 ;
    END
  END fdm[311]
  PIN fdm[312]
    DIRECTION OUTPUT ;
    USE SIGNAL ;
    PORT
      LAYER M5 ;
        RECT  56.016 0 56.04 0.084 ;
    END
  END fdm[312]
  PIN fdm[313]
    DIRECTION OUTPUT ;
    USE SIGNAL ;
    PORT
      LAYER M5 ;
        RECT  56.208 0 56.232 0.084 ;
    END
  END fdm[313]
  PIN fdm[314]
    DIRECTION OUTPUT ;
    USE SIGNAL ;
    PORT
      LAYER M5 ;
        RECT  56.352 0 56.376 0.084 ;
    END
  END fdm[314]
  PIN fdm[315]
    DIRECTION OUTPUT ;
    USE SIGNAL ;
    PORT
      LAYER M5 ;
        RECT  56.544 0 56.568 0.084 ;
    END
  END fdm[315]
  PIN fdm[316]
    DIRECTION OUTPUT ;
    USE SIGNAL ;
    PORT
      LAYER M5 ;
        RECT  56.736 0 56.76 0.084 ;
    END
  END fdm[316]
  PIN fdm[317]
    DIRECTION OUTPUT ;
    USE SIGNAL ;
    PORT
      LAYER M5 ;
        RECT  56.928 0 56.952 0.084 ;
    END
  END fdm[317]
  PIN fdm[318]
    DIRECTION OUTPUT ;
    USE SIGNAL ;
    PORT
      LAYER M5 ;
        RECT  57.072 0 57.096 0.084 ;
    END
  END fdm[318]
  PIN fdm[319]
    DIRECTION OUTPUT ;
    USE SIGNAL ;
    PORT
      LAYER M5 ;
        RECT  57.264 0 57.288 0.084 ;
    END
  END fdm[319]
  PIN fdm[31]
    DIRECTION OUTPUT ;
    USE SIGNAL ;
    PORT
      LAYER M5 ;
        RECT  5.616 0 5.64 0.084 ;
    END
  END fdm[31]
  PIN fdm[320]
    DIRECTION OUTPUT ;
    USE SIGNAL ;
    PORT
      LAYER M5 ;
        RECT  57.456 0 57.48 0.084 ;
    END
  END fdm[320]
  PIN fdm[321]
    DIRECTION OUTPUT ;
    USE SIGNAL ;
    PORT
      LAYER M5 ;
        RECT  57.6 0 57.624 0.084 ;
    END
  END fdm[321]
  PIN fdm[322]
    DIRECTION OUTPUT ;
    USE SIGNAL ;
    PORT
      LAYER M5 ;
        RECT  57.792 0 57.816 0.084 ;
    END
  END fdm[322]
  PIN fdm[323]
    DIRECTION OUTPUT ;
    USE SIGNAL ;
    PORT
      LAYER M5 ;
        RECT  57.984 0 58.008 0.084 ;
    END
  END fdm[323]
  PIN fdm[324]
    DIRECTION OUTPUT ;
    USE SIGNAL ;
    PORT
      LAYER M5 ;
        RECT  58.176 0 58.2 0.084 ;
    END
  END fdm[324]
  PIN fdm[325]
    DIRECTION OUTPUT ;
    USE SIGNAL ;
    PORT
      LAYER M5 ;
        RECT  58.32 0 58.344 0.084 ;
    END
  END fdm[325]
  PIN fdm[326]
    DIRECTION OUTPUT ;
    USE SIGNAL ;
    PORT
      LAYER M5 ;
        RECT  58.512 0 58.536 0.084 ;
    END
  END fdm[326]
  PIN fdm[327]
    DIRECTION OUTPUT ;
    USE SIGNAL ;
    PORT
      LAYER M5 ;
        RECT  58.704 0 58.728 0.084 ;
    END
  END fdm[327]
  PIN fdm[328]
    DIRECTION OUTPUT ;
    USE SIGNAL ;
    PORT
      LAYER M5 ;
        RECT  58.896 0 58.92 0.084 ;
    END
  END fdm[328]
  PIN fdm[329]
    DIRECTION OUTPUT ;
    USE SIGNAL ;
    PORT
      LAYER M5 ;
        RECT  59.04 0 59.064 0.084 ;
    END
  END fdm[329]
  PIN fdm[32]
    DIRECTION OUTPUT ;
    USE SIGNAL ;
    PORT
      LAYER M5 ;
        RECT  5.808 0 5.832 0.084 ;
    END
  END fdm[32]
  PIN fdm[330]
    DIRECTION OUTPUT ;
    USE SIGNAL ;
    PORT
      LAYER M5 ;
        RECT  59.232 0 59.256 0.084 ;
    END
  END fdm[330]
  PIN fdm[331]
    DIRECTION OUTPUT ;
    USE SIGNAL ;
    PORT
      LAYER M5 ;
        RECT  59.424 0 59.448 0.084 ;
    END
  END fdm[331]
  PIN fdm[332]
    DIRECTION OUTPUT ;
    USE SIGNAL ;
    PORT
      LAYER M5 ;
        RECT  59.616 0 59.64 0.084 ;
    END
  END fdm[332]
  PIN fdm[333]
    DIRECTION OUTPUT ;
    USE SIGNAL ;
    PORT
      LAYER M5 ;
        RECT  59.76 0 59.784 0.084 ;
    END
  END fdm[333]
  PIN fdm[334]
    DIRECTION OUTPUT ;
    USE SIGNAL ;
    PORT
      LAYER M5 ;
        RECT  59.952 0 59.976 0.084 ;
    END
  END fdm[334]
  PIN fdm[335]
    DIRECTION OUTPUT ;
    USE SIGNAL ;
    PORT
      LAYER M5 ;
        RECT  60.144 0 60.168 0.084 ;
    END
  END fdm[335]
  PIN fdm[336]
    DIRECTION OUTPUT ;
    USE SIGNAL ;
    PORT
      LAYER M5 ;
        RECT  60.336 0 60.36 0.084 ;
    END
  END fdm[336]
  PIN fdm[337]
    DIRECTION OUTPUT ;
    USE SIGNAL ;
    PORT
      LAYER M5 ;
        RECT  60.48 0 60.504 0.084 ;
    END
  END fdm[337]
  PIN fdm[338]
    DIRECTION OUTPUT ;
    USE SIGNAL ;
    PORT
      LAYER M5 ;
        RECT  60.672 0 60.696 0.084 ;
    END
  END fdm[338]
  PIN fdm[339]
    DIRECTION OUTPUT ;
    USE SIGNAL ;
    PORT
      LAYER M5 ;
        RECT  60.864 0 60.888 0.084 ;
    END
  END fdm[339]
  PIN fdm[33]
    DIRECTION OUTPUT ;
    USE SIGNAL ;
    PORT
      LAYER M5 ;
        RECT  5.952 0 5.976 0.084 ;
    END
  END fdm[33]
  PIN fdm[340]
    DIRECTION OUTPUT ;
    USE SIGNAL ;
    PORT
      LAYER M5 ;
        RECT  61.008 0 61.032 0.084 ;
    END
  END fdm[340]
  PIN fdm[341]
    DIRECTION OUTPUT ;
    USE SIGNAL ;
    PORT
      LAYER M5 ;
        RECT  61.2 0 61.224 0.084 ;
    END
  END fdm[341]
  PIN fdm[342]
    DIRECTION OUTPUT ;
    USE SIGNAL ;
    PORT
      LAYER M5 ;
        RECT  61.392 0 61.416 0.084 ;
    END
  END fdm[342]
  PIN fdm[343]
    DIRECTION OUTPUT ;
    USE SIGNAL ;
    PORT
      LAYER M5 ;
        RECT  61.584 0 61.608 0.084 ;
    END
  END fdm[343]
  PIN fdm[344]
    DIRECTION OUTPUT ;
    USE SIGNAL ;
    PORT
      LAYER M5 ;
        RECT  61.728 0 61.752 0.084 ;
    END
  END fdm[344]
  PIN fdm[345]
    DIRECTION OUTPUT ;
    USE SIGNAL ;
    PORT
      LAYER M5 ;
        RECT  61.92 0 61.944 0.084 ;
    END
  END fdm[345]
  PIN fdm[346]
    DIRECTION OUTPUT ;
    USE SIGNAL ;
    PORT
      LAYER M5 ;
        RECT  62.112 0 62.136 0.084 ;
    END
  END fdm[346]
  PIN fdm[347]
    DIRECTION OUTPUT ;
    USE SIGNAL ;
    PORT
      LAYER M5 ;
        RECT  62.304 0 62.328 0.084 ;
    END
  END fdm[347]
  PIN fdm[348]
    DIRECTION OUTPUT ;
    USE SIGNAL ;
    PORT
      LAYER M5 ;
        RECT  62.448 0 62.472 0.084 ;
    END
  END fdm[348]
  PIN fdm[349]
    DIRECTION OUTPUT ;
    USE SIGNAL ;
    PORT
      LAYER M5 ;
        RECT  62.64 0 62.664 0.084 ;
    END
  END fdm[349]
  PIN fdm[34]
    DIRECTION OUTPUT ;
    USE SIGNAL ;
    PORT
      LAYER M5 ;
        RECT  6.144 0 6.168 0.084 ;
    END
  END fdm[34]
  PIN fdm[350]
    DIRECTION OUTPUT ;
    USE SIGNAL ;
    PORT
      LAYER M5 ;
        RECT  62.832 0 62.856 0.084 ;
    END
  END fdm[350]
  PIN fdm[351]
    DIRECTION OUTPUT ;
    USE SIGNAL ;
    PORT
      LAYER M5 ;
        RECT  63.024 0 63.048 0.084 ;
    END
  END fdm[351]
  PIN fdm[352]
    DIRECTION OUTPUT ;
    USE SIGNAL ;
    PORT
      LAYER M5 ;
        RECT  63.168 0 63.192 0.084 ;
    END
  END fdm[352]
  PIN fdm[353]
    DIRECTION OUTPUT ;
    USE SIGNAL ;
    PORT
      LAYER M5 ;
        RECT  63.36 0 63.384 0.084 ;
    END
  END fdm[353]
  PIN fdm[354]
    DIRECTION OUTPUT ;
    USE SIGNAL ;
    PORT
      LAYER M5 ;
        RECT  63.552 0 63.576 0.084 ;
    END
  END fdm[354]
  PIN fdm[355]
    DIRECTION OUTPUT ;
    USE SIGNAL ;
    PORT
      LAYER M5 ;
        RECT  63.744 0 63.768 0.084 ;
    END
  END fdm[355]
  PIN fdm[356]
    DIRECTION OUTPUT ;
    USE SIGNAL ;
    PORT
      LAYER M5 ;
        RECT  63.888 0 63.912 0.084 ;
    END
  END fdm[356]
  PIN fdm[357]
    DIRECTION OUTPUT ;
    USE SIGNAL ;
    PORT
      LAYER M5 ;
        RECT  64.08 0 64.104 0.084 ;
    END
  END fdm[357]
  PIN fdm[358]
    DIRECTION OUTPUT ;
    USE SIGNAL ;
    PORT
      LAYER M5 ;
        RECT  64.272 0 64.296 0.084 ;
    END
  END fdm[358]
  PIN fdm[359]
    DIRECTION OUTPUT ;
    USE SIGNAL ;
    PORT
      LAYER M5 ;
        RECT  64.416 0 64.44 0.084 ;
    END
  END fdm[359]
  PIN fdm[35]
    DIRECTION OUTPUT ;
    USE SIGNAL ;
    PORT
      LAYER M5 ;
        RECT  6.336 0 6.36 0.084 ;
    END
  END fdm[35]
  PIN fdm[360]
    DIRECTION OUTPUT ;
    USE SIGNAL ;
    PORT
      LAYER M5 ;
        RECT  64.608 0 64.632 0.084 ;
    END
  END fdm[360]
  PIN fdm[361]
    DIRECTION OUTPUT ;
    USE SIGNAL ;
    PORT
      LAYER M5 ;
        RECT  64.8 0 64.824 0.084 ;
    END
  END fdm[361]
  PIN fdm[362]
    DIRECTION OUTPUT ;
    USE SIGNAL ;
    PORT
      LAYER M5 ;
        RECT  64.992 0 65.016 0.084 ;
    END
  END fdm[362]
  PIN fdm[363]
    DIRECTION OUTPUT ;
    USE SIGNAL ;
    PORT
      LAYER M5 ;
        RECT  65.136 0 65.16 0.084 ;
    END
  END fdm[363]
  PIN fdm[364]
    DIRECTION OUTPUT ;
    USE SIGNAL ;
    PORT
      LAYER M5 ;
        RECT  65.328 0 65.352 0.084 ;
    END
  END fdm[364]
  PIN fdm[365]
    DIRECTION OUTPUT ;
    USE SIGNAL ;
    PORT
      LAYER M5 ;
        RECT  65.52 0 65.544 0.084 ;
    END
  END fdm[365]
  PIN fdm[366]
    DIRECTION OUTPUT ;
    USE SIGNAL ;
    PORT
      LAYER M5 ;
        RECT  65.712 0 65.736 0.084 ;
    END
  END fdm[366]
  PIN fdm[367]
    DIRECTION OUTPUT ;
    USE SIGNAL ;
    PORT
      LAYER M5 ;
        RECT  65.856 0 65.88 0.084 ;
    END
  END fdm[367]
  PIN fdm[368]
    DIRECTION OUTPUT ;
    USE SIGNAL ;
    PORT
      LAYER M5 ;
        RECT  66.048 0 66.072 0.084 ;
    END
  END fdm[368]
  PIN fdm[369]
    DIRECTION OUTPUT ;
    USE SIGNAL ;
    PORT
      LAYER M5 ;
        RECT  66.24 0 66.264 0.084 ;
    END
  END fdm[369]
  PIN fdm[36]
    DIRECTION OUTPUT ;
    USE SIGNAL ;
    PORT
      LAYER M5 ;
        RECT  6.528 0 6.552 0.084 ;
    END
  END fdm[36]
  PIN fdm[370]
    DIRECTION OUTPUT ;
    USE SIGNAL ;
    PORT
      LAYER M5 ;
        RECT  66.432 0 66.456 0.084 ;
    END
  END fdm[370]
  PIN fdm[371]
    DIRECTION OUTPUT ;
    USE SIGNAL ;
    PORT
      LAYER M5 ;
        RECT  66.576 0 66.6 0.084 ;
    END
  END fdm[371]
  PIN fdm[372]
    DIRECTION OUTPUT ;
    USE SIGNAL ;
    PORT
      LAYER M5 ;
        RECT  66.768 0 66.792 0.084 ;
    END
  END fdm[372]
  PIN fdm[373]
    DIRECTION OUTPUT ;
    USE SIGNAL ;
    PORT
      LAYER M5 ;
        RECT  66.96 0 66.984 0.084 ;
    END
  END fdm[373]
  PIN fdm[374]
    DIRECTION OUTPUT ;
    USE SIGNAL ;
    PORT
      LAYER M5 ;
        RECT  67.152 0 67.176 0.084 ;
    END
  END fdm[374]
  PIN fdm[375]
    DIRECTION OUTPUT ;
    USE SIGNAL ;
    PORT
      LAYER M5 ;
        RECT  67.296 0 67.32 0.084 ;
    END
  END fdm[375]
  PIN fdm[376]
    DIRECTION OUTPUT ;
    USE SIGNAL ;
    PORT
      LAYER M5 ;
        RECT  67.488 0 67.512 0.084 ;
    END
  END fdm[376]
  PIN fdm[377]
    DIRECTION OUTPUT ;
    USE SIGNAL ;
    PORT
      LAYER M5 ;
        RECT  67.68 0 67.704 0.084 ;
    END
  END fdm[377]
  PIN fdm[378]
    DIRECTION OUTPUT ;
    USE SIGNAL ;
    PORT
      LAYER M5 ;
        RECT  67.824 0 67.848 0.084 ;
    END
  END fdm[378]
  PIN fdm[379]
    DIRECTION OUTPUT ;
    USE SIGNAL ;
    PORT
      LAYER M5 ;
        RECT  68.016 0 68.04 0.084 ;
    END
  END fdm[379]
  PIN fdm[37]
    DIRECTION OUTPUT ;
    USE SIGNAL ;
    PORT
      LAYER M5 ;
        RECT  6.672 0 6.696 0.084 ;
    END
  END fdm[37]
  PIN fdm[380]
    DIRECTION OUTPUT ;
    USE SIGNAL ;
    PORT
      LAYER M5 ;
        RECT  68.208 0 68.232 0.084 ;
    END
  END fdm[380]
  PIN fdm[381]
    DIRECTION OUTPUT ;
    USE SIGNAL ;
    PORT
      LAYER M5 ;
        RECT  68.4 0 68.424 0.084 ;
    END
  END fdm[381]
  PIN fdm[382]
    DIRECTION OUTPUT ;
    USE SIGNAL ;
    PORT
      LAYER M5 ;
        RECT  68.544 0 68.568 0.084 ;
    END
  END fdm[382]
  PIN fdm[383]
    DIRECTION OUTPUT ;
    USE SIGNAL ;
    PORT
      LAYER M5 ;
        RECT  68.736 0 68.76 0.084 ;
    END
  END fdm[383]
  PIN fdm[384]
    DIRECTION OUTPUT ;
    USE SIGNAL ;
    PORT
      LAYER M5 ;
        RECT  68.928 0 68.952 0.084 ;
    END
  END fdm[384]
  PIN fdm[385]
    DIRECTION OUTPUT ;
    USE SIGNAL ;
    PORT
      LAYER M5 ;
        RECT  69.12 0 69.144 0.084 ;
    END
  END fdm[385]
  PIN fdm[386]
    DIRECTION OUTPUT ;
    USE SIGNAL ;
    PORT
      LAYER M5 ;
        RECT  69.264 0 69.288 0.084 ;
    END
  END fdm[386]
  PIN fdm[387]
    DIRECTION OUTPUT ;
    USE SIGNAL ;
    PORT
      LAYER M5 ;
        RECT  69.456 0 69.48 0.084 ;
    END
  END fdm[387]
  PIN fdm[388]
    DIRECTION OUTPUT ;
    USE SIGNAL ;
    PORT
      LAYER M5 ;
        RECT  69.648 0 69.672 0.084 ;
    END
  END fdm[388]
  PIN fdm[389]
    DIRECTION OUTPUT ;
    USE SIGNAL ;
    PORT
      LAYER M5 ;
        RECT  69.84 0 69.864 0.084 ;
    END
  END fdm[389]
  PIN fdm[38]
    DIRECTION OUTPUT ;
    USE SIGNAL ;
    PORT
      LAYER M5 ;
        RECT  6.864 0 6.888 0.084 ;
    END
  END fdm[38]
  PIN fdm[390]
    DIRECTION OUTPUT ;
    USE SIGNAL ;
    PORT
      LAYER M5 ;
        RECT  69.984 0 70.008 0.084 ;
    END
  END fdm[390]
  PIN fdm[391]
    DIRECTION OUTPUT ;
    USE SIGNAL ;
    PORT
      LAYER M5 ;
        RECT  70.176 0 70.2 0.084 ;
    END
  END fdm[391]
  PIN fdm[392]
    DIRECTION OUTPUT ;
    USE SIGNAL ;
    PORT
      LAYER M5 ;
        RECT  70.368 0 70.392 0.084 ;
    END
  END fdm[392]
  PIN fdm[393]
    DIRECTION OUTPUT ;
    USE SIGNAL ;
    PORT
      LAYER M5 ;
        RECT  70.56 0 70.584 0.084 ;
    END
  END fdm[393]
  PIN fdm[394]
    DIRECTION OUTPUT ;
    USE SIGNAL ;
    PORT
      LAYER M5 ;
        RECT  70.704 0 70.728 0.084 ;
    END
  END fdm[394]
  PIN fdm[395]
    DIRECTION OUTPUT ;
    USE SIGNAL ;
    PORT
      LAYER M5 ;
        RECT  70.896 0 70.92 0.084 ;
    END
  END fdm[395]
  PIN fdm[396]
    DIRECTION OUTPUT ;
    USE SIGNAL ;
    PORT
      LAYER M5 ;
        RECT  71.088 0 71.112 0.084 ;
    END
  END fdm[396]
  PIN fdm[397]
    DIRECTION OUTPUT ;
    USE SIGNAL ;
    PORT
      LAYER M5 ;
        RECT  71.232 0 71.256 0.084 ;
    END
  END fdm[397]
  PIN fdm[398]
    DIRECTION OUTPUT ;
    USE SIGNAL ;
    PORT
      LAYER M5 ;
        RECT  71.424 0 71.448 0.084 ;
    END
  END fdm[398]
  PIN fdm[399]
    DIRECTION OUTPUT ;
    USE SIGNAL ;
    PORT
      LAYER M5 ;
        RECT  71.616 0 71.64 0.084 ;
    END
  END fdm[399]
  PIN fdm[39]
    DIRECTION OUTPUT ;
    USE SIGNAL ;
    PORT
      LAYER M5 ;
        RECT  7.056 0 7.08 0.084 ;
    END
  END fdm[39]
  PIN fdm[3]
    DIRECTION OUTPUT ;
    USE SIGNAL ;
    PORT
      LAYER M5 ;
        RECT  0.576 0 0.6 0.084 ;
    END
  END fdm[3]
  PIN fdm[400]
    DIRECTION OUTPUT ;
    USE SIGNAL ;
    PORT
      LAYER M5 ;
        RECT  71.808 0 71.832 0.084 ;
    END
  END fdm[400]
  PIN fdm[401]
    DIRECTION OUTPUT ;
    USE SIGNAL ;
    PORT
      LAYER M5 ;
        RECT  71.952 0 71.976 0.084 ;
    END
  END fdm[401]
  PIN fdm[402]
    DIRECTION OUTPUT ;
    USE SIGNAL ;
    PORT
      LAYER M5 ;
        RECT  72.144 0 72.168 0.084 ;
    END
  END fdm[402]
  PIN fdm[403]
    DIRECTION OUTPUT ;
    USE SIGNAL ;
    PORT
      LAYER M5 ;
        RECT  72.336 0 72.36 0.084 ;
    END
  END fdm[403]
  PIN fdm[404]
    DIRECTION OUTPUT ;
    USE SIGNAL ;
    PORT
      LAYER M5 ;
        RECT  72.528 0 72.552 0.084 ;
    END
  END fdm[404]
  PIN fdm[405]
    DIRECTION OUTPUT ;
    USE SIGNAL ;
    PORT
      LAYER M5 ;
        RECT  72.672 0 72.696 0.084 ;
    END
  END fdm[405]
  PIN fdm[406]
    DIRECTION OUTPUT ;
    USE SIGNAL ;
    PORT
      LAYER M5 ;
        RECT  72.864 0 72.888 0.084 ;
    END
  END fdm[406]
  PIN fdm[407]
    DIRECTION OUTPUT ;
    USE SIGNAL ;
    PORT
      LAYER M5 ;
        RECT  73.056 0 73.08 0.084 ;
    END
  END fdm[407]
  PIN fdm[408]
    DIRECTION OUTPUT ;
    USE SIGNAL ;
    PORT
      LAYER M5 ;
        RECT  73.248 0 73.272 0.084 ;
    END
  END fdm[408]
  PIN fdm[409]
    DIRECTION OUTPUT ;
    USE SIGNAL ;
    PORT
      LAYER M5 ;
        RECT  73.392 0 73.416 0.084 ;
    END
  END fdm[409]
  PIN fdm[40]
    DIRECTION OUTPUT ;
    USE SIGNAL ;
    PORT
      LAYER M5 ;
        RECT  7.248 0 7.272 0.084 ;
    END
  END fdm[40]
  PIN fdm[410]
    DIRECTION OUTPUT ;
    USE SIGNAL ;
    PORT
      LAYER M5 ;
        RECT  73.584 0 73.608 0.084 ;
    END
  END fdm[410]
  PIN fdm[411]
    DIRECTION OUTPUT ;
    USE SIGNAL ;
    PORT
      LAYER M5 ;
        RECT  73.776 0 73.8 0.084 ;
    END
  END fdm[411]
  PIN fdm[412]
    DIRECTION OUTPUT ;
    USE SIGNAL ;
    PORT
      LAYER M5 ;
        RECT  73.92 0 73.944 0.084 ;
    END
  END fdm[412]
  PIN fdm[413]
    DIRECTION OUTPUT ;
    USE SIGNAL ;
    PORT
      LAYER M5 ;
        RECT  74.112 0 74.136 0.084 ;
    END
  END fdm[413]
  PIN fdm[414]
    DIRECTION OUTPUT ;
    USE SIGNAL ;
    PORT
      LAYER M5 ;
        RECT  74.304 0 74.328 0.084 ;
    END
  END fdm[414]
  PIN fdm[415]
    DIRECTION OUTPUT ;
    USE SIGNAL ;
    PORT
      LAYER M5 ;
        RECT  74.496 0 74.52 0.084 ;
    END
  END fdm[415]
  PIN fdm[416]
    DIRECTION OUTPUT ;
    USE SIGNAL ;
    PORT
      LAYER M5 ;
        RECT  74.64 0 74.664 0.084 ;
    END
  END fdm[416]
  PIN fdm[417]
    DIRECTION OUTPUT ;
    USE SIGNAL ;
    PORT
      LAYER M5 ;
        RECT  74.832 0 74.856 0.084 ;
    END
  END fdm[417]
  PIN fdm[418]
    DIRECTION OUTPUT ;
    USE SIGNAL ;
    PORT
      LAYER M5 ;
        RECT  75.024 0 75.048 0.084 ;
    END
  END fdm[418]
  PIN fdm[419]
    DIRECTION OUTPUT ;
    USE SIGNAL ;
    PORT
      LAYER M5 ;
        RECT  75.216 0 75.24 0.084 ;
    END
  END fdm[419]
  PIN fdm[41]
    DIRECTION OUTPUT ;
    USE SIGNAL ;
    PORT
      LAYER M5 ;
        RECT  7.392 0 7.416 0.084 ;
    END
  END fdm[41]
  PIN fdm[420]
    DIRECTION OUTPUT ;
    USE SIGNAL ;
    PORT
      LAYER M5 ;
        RECT  75.36 0 75.384 0.084 ;
    END
  END fdm[420]
  PIN fdm[421]
    DIRECTION OUTPUT ;
    USE SIGNAL ;
    PORT
      LAYER M5 ;
        RECT  75.552 0 75.576 0.084 ;
    END
  END fdm[421]
  PIN fdm[422]
    DIRECTION OUTPUT ;
    USE SIGNAL ;
    PORT
      LAYER M5 ;
        RECT  75.744 0 75.768 0.084 ;
    END
  END fdm[422]
  PIN fdm[423]
    DIRECTION OUTPUT ;
    USE SIGNAL ;
    PORT
      LAYER M5 ;
        RECT  75.936 0 75.96 0.084 ;
    END
  END fdm[423]
  PIN fdm[424]
    DIRECTION OUTPUT ;
    USE SIGNAL ;
    PORT
      LAYER M5 ;
        RECT  76.08 0 76.104 0.084 ;
    END
  END fdm[424]
  PIN fdm[425]
    DIRECTION OUTPUT ;
    USE SIGNAL ;
    PORT
      LAYER M5 ;
        RECT  76.272 0 76.296 0.084 ;
    END
  END fdm[425]
  PIN fdm[426]
    DIRECTION OUTPUT ;
    USE SIGNAL ;
    PORT
      LAYER M5 ;
        RECT  76.464 0 76.488 0.084 ;
    END
  END fdm[426]
  PIN fdm[427]
    DIRECTION OUTPUT ;
    USE SIGNAL ;
    PORT
      LAYER M5 ;
        RECT  76.656 0 76.68 0.084 ;
    END
  END fdm[427]
  PIN fdm[428]
    DIRECTION OUTPUT ;
    USE SIGNAL ;
    PORT
      LAYER M5 ;
        RECT  76.8 0 76.824 0.084 ;
    END
  END fdm[428]
  PIN fdm[429]
    DIRECTION OUTPUT ;
    USE SIGNAL ;
    PORT
      LAYER M5 ;
        RECT  76.992 0 77.016 0.084 ;
    END
  END fdm[429]
  PIN fdm[42]
    DIRECTION OUTPUT ;
    USE SIGNAL ;
    PORT
      LAYER M5 ;
        RECT  7.584 0 7.608 0.084 ;
    END
  END fdm[42]
  PIN fdm[430]
    DIRECTION OUTPUT ;
    USE SIGNAL ;
    PORT
      LAYER M5 ;
        RECT  77.184 0 77.208 0.084 ;
    END
  END fdm[430]
  PIN fdm[431]
    DIRECTION OUTPUT ;
    USE SIGNAL ;
    PORT
      LAYER M5 ;
        RECT  77.328 0 77.352 0.084 ;
    END
  END fdm[431]
  PIN fdm[432]
    DIRECTION OUTPUT ;
    USE SIGNAL ;
    PORT
      LAYER M5 ;
        RECT  77.52 0 77.544 0.084 ;
    END
  END fdm[432]
  PIN fdm[433]
    DIRECTION OUTPUT ;
    USE SIGNAL ;
    PORT
      LAYER M5 ;
        RECT  77.712 0 77.736 0.084 ;
    END
  END fdm[433]
  PIN fdm[434]
    DIRECTION OUTPUT ;
    USE SIGNAL ;
    PORT
      LAYER M5 ;
        RECT  77.904 0 77.928 0.084 ;
    END
  END fdm[434]
  PIN fdm[435]
    DIRECTION OUTPUT ;
    USE SIGNAL ;
    PORT
      LAYER M5 ;
        RECT  78.048 0 78.072 0.084 ;
    END
  END fdm[435]
  PIN fdm[436]
    DIRECTION OUTPUT ;
    USE SIGNAL ;
    PORT
      LAYER M5 ;
        RECT  78.24 0 78.264 0.084 ;
    END
  END fdm[436]
  PIN fdm[437]
    DIRECTION OUTPUT ;
    USE SIGNAL ;
    PORT
      LAYER M5 ;
        RECT  78.432 0 78.456 0.084 ;
    END
  END fdm[437]
  PIN fdm[438]
    DIRECTION OUTPUT ;
    USE SIGNAL ;
    PORT
      LAYER M5 ;
        RECT  78.624 0 78.648 0.084 ;
    END
  END fdm[438]
  PIN fdm[439]
    DIRECTION OUTPUT ;
    USE SIGNAL ;
    PORT
      LAYER M5 ;
        RECT  78.768 0 78.792 0.084 ;
    END
  END fdm[439]
  PIN fdm[43]
    DIRECTION OUTPUT ;
    USE SIGNAL ;
    PORT
      LAYER M5 ;
        RECT  7.776 0 7.8 0.084 ;
    END
  END fdm[43]
  PIN fdm[440]
    DIRECTION OUTPUT ;
    USE SIGNAL ;
    PORT
      LAYER M5 ;
        RECT  78.96 0 78.984 0.084 ;
    END
  END fdm[440]
  PIN fdm[441]
    DIRECTION OUTPUT ;
    USE SIGNAL ;
    PORT
      LAYER M5 ;
        RECT  79.152 0 79.176 0.084 ;
    END
  END fdm[441]
  PIN fdm[442]
    DIRECTION OUTPUT ;
    USE SIGNAL ;
    PORT
      LAYER M5 ;
        RECT  79.344 0 79.368 0.084 ;
    END
  END fdm[442]
  PIN fdm[443]
    DIRECTION OUTPUT ;
    USE SIGNAL ;
    PORT
      LAYER M5 ;
        RECT  79.488 0 79.512 0.084 ;
    END
  END fdm[443]
  PIN fdm[444]
    DIRECTION OUTPUT ;
    USE SIGNAL ;
    PORT
      LAYER M5 ;
        RECT  79.68 0 79.704 0.084 ;
    END
  END fdm[444]
  PIN fdm[445]
    DIRECTION OUTPUT ;
    USE SIGNAL ;
    PORT
      LAYER M5 ;
        RECT  79.872 0 79.896 0.084 ;
    END
  END fdm[445]
  PIN fdm[446]
    DIRECTION OUTPUT ;
    USE SIGNAL ;
    PORT
      LAYER M5 ;
        RECT  80.064 0 80.088 0.084 ;
    END
  END fdm[446]
  PIN fdm[447]
    DIRECTION OUTPUT ;
    USE SIGNAL ;
    PORT
      LAYER M5 ;
        RECT  80.208 0 80.232 0.084 ;
    END
  END fdm[447]
  PIN fdm[448]
    DIRECTION OUTPUT ;
    USE SIGNAL ;
    PORT
      LAYER M5 ;
        RECT  80.4 0 80.424 0.084 ;
    END
  END fdm[448]
  PIN fdm[449]
    DIRECTION OUTPUT ;
    USE SIGNAL ;
    PORT
      LAYER M5 ;
        RECT  80.592 0 80.616 0.084 ;
    END
  END fdm[449]
  PIN fdm[44]
    DIRECTION OUTPUT ;
    USE SIGNAL ;
    PORT
      LAYER M5 ;
        RECT  7.968 0 7.992 0.084 ;
    END
  END fdm[44]
  PIN fdm[450]
    DIRECTION OUTPUT ;
    USE SIGNAL ;
    PORT
      LAYER M5 ;
        RECT  80.736 0 80.76 0.084 ;
    END
  END fdm[450]
  PIN fdm[451]
    DIRECTION OUTPUT ;
    USE SIGNAL ;
    PORT
      LAYER M5 ;
        RECT  80.928 0 80.952 0.084 ;
    END
  END fdm[451]
  PIN fdm[452]
    DIRECTION OUTPUT ;
    USE SIGNAL ;
    PORT
      LAYER M5 ;
        RECT  81.12 0 81.144 0.084 ;
    END
  END fdm[452]
  PIN fdm[453]
    DIRECTION OUTPUT ;
    USE SIGNAL ;
    PORT
      LAYER M5 ;
        RECT  81.312 0 81.336 0.084 ;
    END
  END fdm[453]
  PIN fdm[454]
    DIRECTION OUTPUT ;
    USE SIGNAL ;
    PORT
      LAYER M5 ;
        RECT  81.456 0 81.48 0.084 ;
    END
  END fdm[454]
  PIN fdm[455]
    DIRECTION OUTPUT ;
    USE SIGNAL ;
    PORT
      LAYER M5 ;
        RECT  81.648 0 81.672 0.084 ;
    END
  END fdm[455]
  PIN fdm[456]
    DIRECTION OUTPUT ;
    USE SIGNAL ;
    PORT
      LAYER M5 ;
        RECT  81.84 0 81.864 0.084 ;
    END
  END fdm[456]
  PIN fdm[457]
    DIRECTION OUTPUT ;
    USE SIGNAL ;
    PORT
      LAYER M5 ;
        RECT  82.032 0 82.056 0.084 ;
    END
  END fdm[457]
  PIN fdm[458]
    DIRECTION OUTPUT ;
    USE SIGNAL ;
    PORT
      LAYER M5 ;
        RECT  82.176 0 82.2 0.084 ;
    END
  END fdm[458]
  PIN fdm[459]
    DIRECTION OUTPUT ;
    USE SIGNAL ;
    PORT
      LAYER M5 ;
        RECT  82.368 0 82.392 0.084 ;
    END
  END fdm[459]
  PIN fdm[45]
    DIRECTION OUTPUT ;
    USE SIGNAL ;
    PORT
      LAYER M5 ;
        RECT  8.112 0 8.136 0.084 ;
    END
  END fdm[45]
  PIN fdm[460]
    DIRECTION OUTPUT ;
    USE SIGNAL ;
    PORT
      LAYER M5 ;
        RECT  82.56 0 82.584 0.084 ;
    END
  END fdm[460]
  PIN fdm[461]
    DIRECTION OUTPUT ;
    USE SIGNAL ;
    PORT
      LAYER M5 ;
        RECT  82.752 0 82.776 0.084 ;
    END
  END fdm[461]
  PIN fdm[462]
    DIRECTION OUTPUT ;
    USE SIGNAL ;
    PORT
      LAYER M5 ;
        RECT  82.896 0 82.92 0.084 ;
    END
  END fdm[462]
  PIN fdm[463]
    DIRECTION OUTPUT ;
    USE SIGNAL ;
    PORT
      LAYER M5 ;
        RECT  83.088 0 83.112 0.084 ;
    END
  END fdm[463]
  PIN fdm[464]
    DIRECTION OUTPUT ;
    USE SIGNAL ;
    PORT
      LAYER M5 ;
        RECT  83.28 0 83.304 0.084 ;
    END
  END fdm[464]
  PIN fdm[465]
    DIRECTION OUTPUT ;
    USE SIGNAL ;
    PORT
      LAYER M5 ;
        RECT  83.472 0 83.496 0.084 ;
    END
  END fdm[465]
  PIN fdm[466]
    DIRECTION OUTPUT ;
    USE SIGNAL ;
    PORT
      LAYER M5 ;
        RECT  83.616 0 83.64 0.084 ;
    END
  END fdm[466]
  PIN fdm[467]
    DIRECTION OUTPUT ;
    USE SIGNAL ;
    PORT
      LAYER M5 ;
        RECT  83.808 0 83.832 0.084 ;
    END
  END fdm[467]
  PIN fdm[468]
    DIRECTION OUTPUT ;
    USE SIGNAL ;
    PORT
      LAYER M5 ;
        RECT  84 0 84.024 0.084 ;
    END
  END fdm[468]
  PIN fdm[469]
    DIRECTION OUTPUT ;
    USE SIGNAL ;
    PORT
      LAYER M5 ;
        RECT  84.144 0 84.168 0.084 ;
    END
  END fdm[469]
  PIN fdm[46]
    DIRECTION OUTPUT ;
    USE SIGNAL ;
    PORT
      LAYER M5 ;
        RECT  8.304 0 8.328 0.084 ;
    END
  END fdm[46]
  PIN fdm[470]
    DIRECTION OUTPUT ;
    USE SIGNAL ;
    PORT
      LAYER M5 ;
        RECT  84.336 0 84.36 0.084 ;
    END
  END fdm[470]
  PIN fdm[471]
    DIRECTION OUTPUT ;
    USE SIGNAL ;
    PORT
      LAYER M5 ;
        RECT  84.528 0 84.552 0.084 ;
    END
  END fdm[471]
  PIN fdm[472]
    DIRECTION OUTPUT ;
    USE SIGNAL ;
    PORT
      LAYER M5 ;
        RECT  84.72 0 84.744 0.084 ;
    END
  END fdm[472]
  PIN fdm[473]
    DIRECTION OUTPUT ;
    USE SIGNAL ;
    PORT
      LAYER M5 ;
        RECT  84.864 0 84.888 0.084 ;
    END
  END fdm[473]
  PIN fdm[474]
    DIRECTION OUTPUT ;
    USE SIGNAL ;
    PORT
      LAYER M5 ;
        RECT  85.056 0 85.08 0.084 ;
    END
  END fdm[474]
  PIN fdm[475]
    DIRECTION OUTPUT ;
    USE SIGNAL ;
    PORT
      LAYER M5 ;
        RECT  85.248 0 85.272 0.084 ;
    END
  END fdm[475]
  PIN fdm[476]
    DIRECTION OUTPUT ;
    USE SIGNAL ;
    PORT
      LAYER M5 ;
        RECT  85.44 0 85.464 0.084 ;
    END
  END fdm[476]
  PIN fdm[477]
    DIRECTION OUTPUT ;
    USE SIGNAL ;
    PORT
      LAYER M5 ;
        RECT  85.584 0 85.608 0.084 ;
    END
  END fdm[477]
  PIN fdm[478]
    DIRECTION OUTPUT ;
    USE SIGNAL ;
    PORT
      LAYER M5 ;
        RECT  85.776 0 85.8 0.084 ;
    END
  END fdm[478]
  PIN fdm[479]
    DIRECTION OUTPUT ;
    USE SIGNAL ;
    PORT
      LAYER M5 ;
        RECT  85.968 0 85.992 0.084 ;
    END
  END fdm[479]
  PIN fdm[47]
    DIRECTION OUTPUT ;
    USE SIGNAL ;
    PORT
      LAYER M5 ;
        RECT  8.496 0 8.52 0.084 ;
    END
  END fdm[47]
  PIN fdm[480]
    DIRECTION OUTPUT ;
    USE SIGNAL ;
    PORT
      LAYER M5 ;
        RECT  86.16 0 86.184 0.084 ;
    END
  END fdm[480]
  PIN fdm[481]
    DIRECTION OUTPUT ;
    USE SIGNAL ;
    PORT
      LAYER M5 ;
        RECT  86.304 0 86.328 0.084 ;
    END
  END fdm[481]
  PIN fdm[482]
    DIRECTION OUTPUT ;
    USE SIGNAL ;
    PORT
      LAYER M5 ;
        RECT  86.496 0 86.52 0.084 ;
    END
  END fdm[482]
  PIN fdm[483]
    DIRECTION OUTPUT ;
    USE SIGNAL ;
    PORT
      LAYER M5 ;
        RECT  86.688 0 86.712 0.084 ;
    END
  END fdm[483]
  PIN fdm[484]
    DIRECTION OUTPUT ;
    USE SIGNAL ;
    PORT
      LAYER M5 ;
        RECT  86.88 0 86.904 0.084 ;
    END
  END fdm[484]
  PIN fdm[485]
    DIRECTION OUTPUT ;
    USE SIGNAL ;
    PORT
      LAYER M5 ;
        RECT  87.024 0 87.048 0.084 ;
    END
  END fdm[485]
  PIN fdm[486]
    DIRECTION OUTPUT ;
    USE SIGNAL ;
    PORT
      LAYER M5 ;
        RECT  87.216 0 87.24 0.084 ;
    END
  END fdm[486]
  PIN fdm[487]
    DIRECTION OUTPUT ;
    USE SIGNAL ;
    PORT
      LAYER M5 ;
        RECT  87.408 0 87.432 0.084 ;
    END
  END fdm[487]
  PIN fdm[488]
    DIRECTION OUTPUT ;
    USE SIGNAL ;
    PORT
      LAYER M5 ;
        RECT  87.552 0 87.576 0.084 ;
    END
  END fdm[488]
  PIN fdm[489]
    DIRECTION OUTPUT ;
    USE SIGNAL ;
    PORT
      LAYER M5 ;
        RECT  87.744 0 87.768 0.084 ;
    END
  END fdm[489]
  PIN fdm[48]
    DIRECTION OUTPUT ;
    USE SIGNAL ;
    PORT
      LAYER M5 ;
        RECT  8.64 0 8.664 0.084 ;
    END
  END fdm[48]
  PIN fdm[490]
    DIRECTION OUTPUT ;
    USE SIGNAL ;
    PORT
      LAYER M5 ;
        RECT  87.936 0 87.96 0.084 ;
    END
  END fdm[490]
  PIN fdm[491]
    DIRECTION OUTPUT ;
    USE SIGNAL ;
    PORT
      LAYER M5 ;
        RECT  88.128 0 88.152 0.084 ;
    END
  END fdm[491]
  PIN fdm[492]
    DIRECTION OUTPUT ;
    USE SIGNAL ;
    PORT
      LAYER M5 ;
        RECT  88.272 0 88.296 0.084 ;
    END
  END fdm[492]
  PIN fdm[493]
    DIRECTION OUTPUT ;
    USE SIGNAL ;
    PORT
      LAYER M5 ;
        RECT  88.464 0 88.488 0.084 ;
    END
  END fdm[493]
  PIN fdm[494]
    DIRECTION OUTPUT ;
    USE SIGNAL ;
    PORT
      LAYER M5 ;
        RECT  88.656 0 88.68 0.084 ;
    END
  END fdm[494]
  PIN fdm[495]
    DIRECTION OUTPUT ;
    USE SIGNAL ;
    PORT
      LAYER M5 ;
        RECT  88.848 0 88.872 0.084 ;
    END
  END fdm[495]
  PIN fdm[496]
    DIRECTION OUTPUT ;
    USE SIGNAL ;
    PORT
      LAYER M5 ;
        RECT  88.992 0 89.016 0.084 ;
    END
  END fdm[496]
  PIN fdm[497]
    DIRECTION OUTPUT ;
    USE SIGNAL ;
    PORT
      LAYER M5 ;
        RECT  89.184 0 89.208 0.084 ;
    END
  END fdm[497]
  PIN fdm[498]
    DIRECTION OUTPUT ;
    USE SIGNAL ;
    PORT
      LAYER M5 ;
        RECT  89.376 0 89.4 0.084 ;
    END
  END fdm[498]
  PIN fdm[499]
    DIRECTION OUTPUT ;
    USE SIGNAL ;
    PORT
      LAYER M5 ;
        RECT  89.568 0 89.592 0.084 ;
    END
  END fdm[499]
  PIN fdm[49]
    DIRECTION OUTPUT ;
    USE SIGNAL ;
    PORT
      LAYER M5 ;
        RECT  8.832 0 8.856 0.084 ;
    END
  END fdm[49]
  PIN fdm[4]
    DIRECTION OUTPUT ;
    USE SIGNAL ;
    PORT
      LAYER M5 ;
        RECT  0.768 0 0.792 0.084 ;
    END
  END fdm[4]
  PIN fdm[500]
    DIRECTION OUTPUT ;
    USE SIGNAL ;
    PORT
      LAYER M5 ;
        RECT  89.712 0 89.736 0.084 ;
    END
  END fdm[500]
  PIN fdm[501]
    DIRECTION OUTPUT ;
    USE SIGNAL ;
    PORT
      LAYER M5 ;
        RECT  89.904 0 89.928 0.084 ;
    END
  END fdm[501]
  PIN fdm[502]
    DIRECTION OUTPUT ;
    USE SIGNAL ;
    PORT
      LAYER M5 ;
        RECT  90.096 0 90.12 0.084 ;
    END
  END fdm[502]
  PIN fdm[503]
    DIRECTION OUTPUT ;
    USE SIGNAL ;
    PORT
      LAYER M5 ;
        RECT  90.288 0 90.312 0.084 ;
    END
  END fdm[503]
  PIN fdm[504]
    DIRECTION OUTPUT ;
    USE SIGNAL ;
    PORT
      LAYER M5 ;
        RECT  90.432 0 90.456 0.084 ;
    END
  END fdm[504]
  PIN fdm[505]
    DIRECTION OUTPUT ;
    USE SIGNAL ;
    PORT
      LAYER M5 ;
        RECT  90.624 0 90.648 0.084 ;
    END
  END fdm[505]
  PIN fdm[506]
    DIRECTION OUTPUT ;
    USE SIGNAL ;
    PORT
      LAYER M5 ;
        RECT  90.816 0 90.84 0.084 ;
    END
  END fdm[506]
  PIN fdm[507]
    DIRECTION OUTPUT ;
    USE SIGNAL ;
    PORT
      LAYER M5 ;
        RECT  90.96 0 90.984 0.084 ;
    END
  END fdm[507]
  PIN fdm[508]
    DIRECTION OUTPUT ;
    USE SIGNAL ;
    PORT
      LAYER M5 ;
        RECT  91.152 0 91.176 0.084 ;
    END
  END fdm[508]
  PIN fdm[509]
    DIRECTION OUTPUT ;
    USE SIGNAL ;
    PORT
      LAYER M5 ;
        RECT  91.344 0 91.368 0.084 ;
    END
  END fdm[509]
  PIN fdm[50]
    DIRECTION OUTPUT ;
    USE SIGNAL ;
    PORT
      LAYER M5 ;
        RECT  9.024 0 9.048 0.084 ;
    END
  END fdm[50]
  PIN fdm[510]
    DIRECTION OUTPUT ;
    USE SIGNAL ;
    PORT
      LAYER M5 ;
        RECT  91.536 0 91.56 0.084 ;
    END
  END fdm[510]
  PIN fdm[511]
    DIRECTION OUTPUT ;
    USE SIGNAL ;
    PORT
      LAYER M5 ;
        RECT  91.68 0 91.704 0.084 ;
    END
  END fdm[511]
  PIN fdm[512]
    DIRECTION OUTPUT ;
    USE SIGNAL ;
    PORT
      LAYER M5 ;
        RECT  91.872 0 91.896 0.084 ;
    END
  END fdm[512]
  PIN fdm[513]
    DIRECTION OUTPUT ;
    USE SIGNAL ;
    PORT
      LAYER M5 ;
        RECT  92.064 0 92.088 0.084 ;
    END
  END fdm[513]
  PIN fdm[514]
    DIRECTION OUTPUT ;
    USE SIGNAL ;
    PORT
      LAYER M5 ;
        RECT  92.256 0 92.28 0.084 ;
    END
  END fdm[514]
  PIN fdm[515]
    DIRECTION OUTPUT ;
    USE SIGNAL ;
    PORT
      LAYER M5 ;
        RECT  92.4 0 92.424 0.084 ;
    END
  END fdm[515]
  PIN fdm[516]
    DIRECTION OUTPUT ;
    USE SIGNAL ;
    PORT
      LAYER M5 ;
        RECT  92.592 0 92.616 0.084 ;
    END
  END fdm[516]
  PIN fdm[517]
    DIRECTION OUTPUT ;
    USE SIGNAL ;
    PORT
      LAYER M5 ;
        RECT  92.784 0 92.808 0.084 ;
    END
  END fdm[517]
  PIN fdm[518]
    DIRECTION OUTPUT ;
    USE SIGNAL ;
    PORT
      LAYER M5 ;
        RECT  92.976 0 93 0.084 ;
    END
  END fdm[518]
  PIN fdm[519]
    DIRECTION OUTPUT ;
    USE SIGNAL ;
    PORT
      LAYER M5 ;
        RECT  93.12 0 93.144 0.084 ;
    END
  END fdm[519]
  PIN fdm[51]
    DIRECTION OUTPUT ;
    USE SIGNAL ;
    PORT
      LAYER M5 ;
        RECT  9.216 0 9.24 0.084 ;
    END
  END fdm[51]
  PIN fdm[520]
    DIRECTION OUTPUT ;
    USE SIGNAL ;
    PORT
      LAYER M5 ;
        RECT  93.312 0 93.336 0.084 ;
    END
  END fdm[520]
  PIN fdm[521]
    DIRECTION OUTPUT ;
    USE SIGNAL ;
    PORT
      LAYER M5 ;
        RECT  93.504 0 93.528 0.084 ;
    END
  END fdm[521]
  PIN fdm[522]
    DIRECTION OUTPUT ;
    USE SIGNAL ;
    PORT
      LAYER M5 ;
        RECT  93.648 0 93.672 0.084 ;
    END
  END fdm[522]
  PIN fdm[523]
    DIRECTION OUTPUT ;
    USE SIGNAL ;
    PORT
      LAYER M5 ;
        RECT  93.84 0 93.864 0.084 ;
    END
  END fdm[523]
  PIN fdm[524]
    DIRECTION OUTPUT ;
    USE SIGNAL ;
    PORT
      LAYER M5 ;
        RECT  94.032 0 94.056 0.084 ;
    END
  END fdm[524]
  PIN fdm[525]
    DIRECTION OUTPUT ;
    USE SIGNAL ;
    PORT
      LAYER M5 ;
        RECT  94.224 0 94.248 0.084 ;
    END
  END fdm[525]
  PIN fdm[526]
    DIRECTION OUTPUT ;
    USE SIGNAL ;
    PORT
      LAYER M5 ;
        RECT  94.368 0 94.392 0.084 ;
    END
  END fdm[526]
  PIN fdm[527]
    DIRECTION OUTPUT ;
    USE SIGNAL ;
    PORT
      LAYER M5 ;
        RECT  94.56 0 94.584 0.084 ;
    END
  END fdm[527]
  PIN fdm[528]
    DIRECTION OUTPUT ;
    USE SIGNAL ;
    PORT
      LAYER M5 ;
        RECT  94.752 0 94.776 0.084 ;
    END
  END fdm[528]
  PIN fdm[529]
    DIRECTION OUTPUT ;
    USE SIGNAL ;
    PORT
      LAYER M5 ;
        RECT  94.944 0 94.968 0.084 ;
    END
  END fdm[529]
  PIN fdm[52]
    DIRECTION OUTPUT ;
    USE SIGNAL ;
    PORT
      LAYER M5 ;
        RECT  9.36 0 9.384 0.084 ;
    END
  END fdm[52]
  PIN fdm[530]
    DIRECTION OUTPUT ;
    USE SIGNAL ;
    PORT
      LAYER M5 ;
        RECT  95.088 0 95.112 0.084 ;
    END
  END fdm[530]
  PIN fdm[531]
    DIRECTION OUTPUT ;
    USE SIGNAL ;
    PORT
      LAYER M5 ;
        RECT  95.28 0 95.304 0.084 ;
    END
  END fdm[531]
  PIN fdm[532]
    DIRECTION OUTPUT ;
    USE SIGNAL ;
    PORT
      LAYER M5 ;
        RECT  95.472 0 95.496 0.084 ;
    END
  END fdm[532]
  PIN fdm[533]
    DIRECTION OUTPUT ;
    USE SIGNAL ;
    PORT
      LAYER M5 ;
        RECT  95.664 0 95.688 0.084 ;
    END
  END fdm[533]
  PIN fdm[534]
    DIRECTION OUTPUT ;
    USE SIGNAL ;
    PORT
      LAYER M5 ;
        RECT  95.808 0 95.832 0.084 ;
    END
  END fdm[534]
  PIN fdm[535]
    DIRECTION OUTPUT ;
    USE SIGNAL ;
    PORT
      LAYER M5 ;
        RECT  96 0 96.024 0.084 ;
    END
  END fdm[535]
  PIN fdm[536]
    DIRECTION OUTPUT ;
    USE SIGNAL ;
    PORT
      LAYER M5 ;
        RECT  96.192 0 96.216 0.084 ;
    END
  END fdm[536]
  PIN fdm[537]
    DIRECTION OUTPUT ;
    USE SIGNAL ;
    PORT
      LAYER M5 ;
        RECT  96.384 0 96.408 0.084 ;
    END
  END fdm[537]
  PIN fdm[538]
    DIRECTION OUTPUT ;
    USE SIGNAL ;
    PORT
      LAYER M5 ;
        RECT  96.528 0 96.552 0.084 ;
    END
  END fdm[538]
  PIN fdm[539]
    DIRECTION OUTPUT ;
    USE SIGNAL ;
    PORT
      LAYER M5 ;
        RECT  96.72 0 96.744 0.084 ;
    END
  END fdm[539]
  PIN fdm[53]
    DIRECTION OUTPUT ;
    USE SIGNAL ;
    PORT
      LAYER M5 ;
        RECT  9.552 0 9.576 0.084 ;
    END
  END fdm[53]
  PIN fdm[540]
    DIRECTION OUTPUT ;
    USE SIGNAL ;
    PORT
      LAYER M5 ;
        RECT  96.912 0 96.936 0.084 ;
    END
  END fdm[540]
  PIN fdm[541]
    DIRECTION OUTPUT ;
    USE SIGNAL ;
    PORT
      LAYER M5 ;
        RECT  97.056 0 97.08 0.084 ;
    END
  END fdm[541]
  PIN fdm[542]
    DIRECTION OUTPUT ;
    USE SIGNAL ;
    PORT
      LAYER M5 ;
        RECT  97.248 0 97.272 0.084 ;
    END
  END fdm[542]
  PIN fdm[543]
    DIRECTION OUTPUT ;
    USE SIGNAL ;
    PORT
      LAYER M5 ;
        RECT  97.44 0 97.464 0.084 ;
    END
  END fdm[543]
  PIN fdm[544]
    DIRECTION OUTPUT ;
    USE SIGNAL ;
    PORT
      LAYER M5 ;
        RECT  97.632 0 97.656 0.084 ;
    END
  END fdm[544]
  PIN fdm[545]
    DIRECTION OUTPUT ;
    USE SIGNAL ;
    PORT
      LAYER M5 ;
        RECT  97.776 0 97.8 0.084 ;
    END
  END fdm[545]
  PIN fdm[546]
    DIRECTION OUTPUT ;
    USE SIGNAL ;
    PORT
      LAYER M5 ;
        RECT  97.968 0 97.992 0.084 ;
    END
  END fdm[546]
  PIN fdm[547]
    DIRECTION OUTPUT ;
    USE SIGNAL ;
    PORT
      LAYER M5 ;
        RECT  98.16 0 98.184 0.084 ;
    END
  END fdm[547]
  PIN fdm[548]
    DIRECTION OUTPUT ;
    USE SIGNAL ;
    PORT
      LAYER M5 ;
        RECT  98.352 0 98.376 0.084 ;
    END
  END fdm[548]
  PIN fdm[549]
    DIRECTION OUTPUT ;
    USE SIGNAL ;
    PORT
      LAYER M5 ;
        RECT  98.496 0 98.52 0.084 ;
    END
  END fdm[549]
  PIN fdm[54]
    DIRECTION OUTPUT ;
    USE SIGNAL ;
    PORT
      LAYER M5 ;
        RECT  9.744 0 9.768 0.084 ;
    END
  END fdm[54]
  PIN fdm[550]
    DIRECTION OUTPUT ;
    USE SIGNAL ;
    PORT
      LAYER M5 ;
        RECT  98.688 0 98.712 0.084 ;
    END
  END fdm[550]
  PIN fdm[551]
    DIRECTION OUTPUT ;
    USE SIGNAL ;
    PORT
      LAYER M5 ;
        RECT  98.88 0 98.904 0.084 ;
    END
  END fdm[551]
  PIN fdm[552]
    DIRECTION OUTPUT ;
    USE SIGNAL ;
    PORT
      LAYER M5 ;
        RECT  99.072 0 99.096 0.084 ;
    END
  END fdm[552]
  PIN fdm[553]
    DIRECTION OUTPUT ;
    USE SIGNAL ;
    PORT
      LAYER M5 ;
        RECT  99.216 0 99.24 0.084 ;
    END
  END fdm[553]
  PIN fdm[554]
    DIRECTION OUTPUT ;
    USE SIGNAL ;
    PORT
      LAYER M5 ;
        RECT  99.408 0 99.432 0.084 ;
    END
  END fdm[554]
  PIN fdm[555]
    DIRECTION OUTPUT ;
    USE SIGNAL ;
    PORT
      LAYER M5 ;
        RECT  99.6 0 99.624 0.084 ;
    END
  END fdm[555]
  PIN fdm[556]
    DIRECTION OUTPUT ;
    USE SIGNAL ;
    PORT
      LAYER M5 ;
        RECT  99.792 0 99.816 0.084 ;
    END
  END fdm[556]
  PIN fdm[557]
    DIRECTION OUTPUT ;
    USE SIGNAL ;
    PORT
      LAYER M5 ;
        RECT  99.936 0 99.96 0.084 ;
    END
  END fdm[557]
  PIN fdm[558]
    DIRECTION OUTPUT ;
    USE SIGNAL ;
    PORT
      LAYER M5 ;
        RECT  100.128 0 100.152 0.084 ;
    END
  END fdm[558]
  PIN fdm[559]
    DIRECTION OUTPUT ;
    USE SIGNAL ;
    PORT
      LAYER M5 ;
        RECT  100.32 0 100.344 0.084 ;
    END
  END fdm[559]
  PIN fdm[55]
    DIRECTION OUTPUT ;
    USE SIGNAL ;
    PORT
      LAYER M5 ;
        RECT  9.936 0 9.96 0.084 ;
    END
  END fdm[55]
  PIN fdm[560]
    DIRECTION OUTPUT ;
    USE SIGNAL ;
    PORT
      LAYER M5 ;
        RECT  100.464 0 100.488 0.084 ;
    END
  END fdm[560]
  PIN fdm[561]
    DIRECTION OUTPUT ;
    USE SIGNAL ;
    PORT
      LAYER M5 ;
        RECT  100.656 0 100.68 0.084 ;
    END
  END fdm[561]
  PIN fdm[562]
    DIRECTION OUTPUT ;
    USE SIGNAL ;
    PORT
      LAYER M5 ;
        RECT  100.848 0 100.872 0.084 ;
    END
  END fdm[562]
  PIN fdm[563]
    DIRECTION OUTPUT ;
    USE SIGNAL ;
    PORT
      LAYER M5 ;
        RECT  101.04 0 101.064 0.084 ;
    END
  END fdm[563]
  PIN fdm[564]
    DIRECTION OUTPUT ;
    USE SIGNAL ;
    PORT
      LAYER M5 ;
        RECT  101.184 0 101.208 0.084 ;
    END
  END fdm[564]
  PIN fdm[565]
    DIRECTION OUTPUT ;
    USE SIGNAL ;
    PORT
      LAYER M5 ;
        RECT  101.376 0 101.4 0.084 ;
    END
  END fdm[565]
  PIN fdm[566]
    DIRECTION OUTPUT ;
    USE SIGNAL ;
    PORT
      LAYER M5 ;
        RECT  101.568 0 101.592 0.084 ;
    END
  END fdm[566]
  PIN fdm[567]
    DIRECTION OUTPUT ;
    USE SIGNAL ;
    PORT
      LAYER M5 ;
        RECT  101.76 0 101.784 0.084 ;
    END
  END fdm[567]
  PIN fdm[568]
    DIRECTION OUTPUT ;
    USE SIGNAL ;
    PORT
      LAYER M5 ;
        RECT  101.904 0 101.928 0.084 ;
    END
  END fdm[568]
  PIN fdm[569]
    DIRECTION OUTPUT ;
    USE SIGNAL ;
    PORT
      LAYER M5 ;
        RECT  102.096 0 102.12 0.084 ;
    END
  END fdm[569]
  PIN fdm[56]
    DIRECTION OUTPUT ;
    USE SIGNAL ;
    PORT
      LAYER M5 ;
        RECT  10.08 0 10.104 0.084 ;
    END
  END fdm[56]
  PIN fdm[570]
    DIRECTION OUTPUT ;
    USE SIGNAL ;
    PORT
      LAYER M5 ;
        RECT  102.288 0 102.312 0.084 ;
    END
  END fdm[570]
  PIN fdm[571]
    DIRECTION OUTPUT ;
    USE SIGNAL ;
    PORT
      LAYER M5 ;
        RECT  102.48 0 102.504 0.084 ;
    END
  END fdm[571]
  PIN fdm[572]
    DIRECTION OUTPUT ;
    USE SIGNAL ;
    PORT
      LAYER M5 ;
        RECT  102.624 0 102.648 0.084 ;
    END
  END fdm[572]
  PIN fdm[573]
    DIRECTION OUTPUT ;
    USE SIGNAL ;
    PORT
      LAYER M5 ;
        RECT  102.816 0 102.84 0.084 ;
    END
  END fdm[573]
  PIN fdm[574]
    DIRECTION OUTPUT ;
    USE SIGNAL ;
    PORT
      LAYER M5 ;
        RECT  103.008 0 103.032 0.084 ;
    END
  END fdm[574]
  PIN fdm[575]
    DIRECTION OUTPUT ;
    USE SIGNAL ;
    PORT
      LAYER M5 ;
        RECT  103.2 0 103.224 0.084 ;
    END
  END fdm[575]
  PIN fdm[576]
    DIRECTION OUTPUT ;
    USE SIGNAL ;
    PORT
      LAYER M5 ;
        RECT  103.344 0 103.368 0.084 ;
    END
  END fdm[576]
  PIN fdm[577]
    DIRECTION OUTPUT ;
    USE SIGNAL ;
    PORT
      LAYER M5 ;
        RECT  103.536 0 103.56 0.084 ;
    END
  END fdm[577]
  PIN fdm[578]
    DIRECTION OUTPUT ;
    USE SIGNAL ;
    PORT
      LAYER M5 ;
        RECT  103.728 0 103.752 0.084 ;
    END
  END fdm[578]
  PIN fdm[579]
    DIRECTION OUTPUT ;
    USE SIGNAL ;
    PORT
      LAYER M5 ;
        RECT  103.872 0 103.896 0.084 ;
    END
  END fdm[579]
  PIN fdm[57]
    DIRECTION OUTPUT ;
    USE SIGNAL ;
    PORT
      LAYER M5 ;
        RECT  10.272 0 10.296 0.084 ;
    END
  END fdm[57]
  PIN fdm[580]
    DIRECTION OUTPUT ;
    USE SIGNAL ;
    PORT
      LAYER M5 ;
        RECT  104.064 0 104.088 0.084 ;
    END
  END fdm[580]
  PIN fdm[581]
    DIRECTION OUTPUT ;
    USE SIGNAL ;
    PORT
      LAYER M5 ;
        RECT  104.256 0 104.28 0.084 ;
    END
  END fdm[581]
  PIN fdm[582]
    DIRECTION OUTPUT ;
    USE SIGNAL ;
    PORT
      LAYER M5 ;
        RECT  104.448 0 104.472 0.084 ;
    END
  END fdm[582]
  PIN fdm[583]
    DIRECTION OUTPUT ;
    USE SIGNAL ;
    PORT
      LAYER M5 ;
        RECT  104.592 0 104.616 0.084 ;
    END
  END fdm[583]
  PIN fdm[584]
    DIRECTION OUTPUT ;
    USE SIGNAL ;
    PORT
      LAYER M5 ;
        RECT  104.784 0 104.808 0.084 ;
    END
  END fdm[584]
  PIN fdm[585]
    DIRECTION OUTPUT ;
    USE SIGNAL ;
    PORT
      LAYER M5 ;
        RECT  104.976 0 105 0.084 ;
    END
  END fdm[585]
  PIN fdm[586]
    DIRECTION OUTPUT ;
    USE SIGNAL ;
    PORT
      LAYER M5 ;
        RECT  105.168 0 105.192 0.084 ;
    END
  END fdm[586]
  PIN fdm[587]
    DIRECTION OUTPUT ;
    USE SIGNAL ;
    PORT
      LAYER M5 ;
        RECT  105.312 0 105.336 0.084 ;
    END
  END fdm[587]
  PIN fdm[588]
    DIRECTION OUTPUT ;
    USE SIGNAL ;
    PORT
      LAYER M5 ;
        RECT  105.504 0 105.528 0.084 ;
    END
  END fdm[588]
  PIN fdm[589]
    DIRECTION OUTPUT ;
    USE SIGNAL ;
    PORT
      LAYER M5 ;
        RECT  105.696 0 105.72 0.084 ;
    END
  END fdm[589]
  PIN fdm[58]
    DIRECTION OUTPUT ;
    USE SIGNAL ;
    PORT
      LAYER M5 ;
        RECT  10.464 0 10.488 0.084 ;
    END
  END fdm[58]
  PIN fdm[590]
    DIRECTION OUTPUT ;
    USE SIGNAL ;
    PORT
      LAYER M5 ;
        RECT  105.888 0 105.912 0.084 ;
    END
  END fdm[590]
  PIN fdm[591]
    DIRECTION OUTPUT ;
    USE SIGNAL ;
    PORT
      LAYER M5 ;
        RECT  106.032 0 106.056 0.084 ;
    END
  END fdm[591]
  PIN fdm[592]
    DIRECTION OUTPUT ;
    USE SIGNAL ;
    PORT
      LAYER M5 ;
        RECT  106.224 0 106.248 0.084 ;
    END
  END fdm[592]
  PIN fdm[593]
    DIRECTION OUTPUT ;
    USE SIGNAL ;
    PORT
      LAYER M5 ;
        RECT  106.416 0 106.44 0.084 ;
    END
  END fdm[593]
  PIN fdm[594]
    DIRECTION OUTPUT ;
    USE SIGNAL ;
    PORT
      LAYER M5 ;
        RECT  106.608 0 106.632 0.084 ;
    END
  END fdm[594]
  PIN fdm[595]
    DIRECTION OUTPUT ;
    USE SIGNAL ;
    PORT
      LAYER M5 ;
        RECT  106.752 0 106.776 0.084 ;
    END
  END fdm[595]
  PIN fdm[596]
    DIRECTION OUTPUT ;
    USE SIGNAL ;
    PORT
      LAYER M5 ;
        RECT  106.944 0 106.968 0.084 ;
    END
  END fdm[596]
  PIN fdm[597]
    DIRECTION OUTPUT ;
    USE SIGNAL ;
    PORT
      LAYER M5 ;
        RECT  107.136 0 107.16 0.084 ;
    END
  END fdm[597]
  PIN fdm[598]
    DIRECTION OUTPUT ;
    USE SIGNAL ;
    PORT
      LAYER M5 ;
        RECT  107.28 0 107.304 0.084 ;
    END
  END fdm[598]
  PIN fdm[599]
    DIRECTION OUTPUT ;
    USE SIGNAL ;
    PORT
      LAYER M5 ;
        RECT  107.472 0 107.496 0.084 ;
    END
  END fdm[599]
  PIN fdm[59]
    DIRECTION OUTPUT ;
    USE SIGNAL ;
    PORT
      LAYER M5 ;
        RECT  10.656 0 10.68 0.084 ;
    END
  END fdm[59]
  PIN fdm[5]
    DIRECTION OUTPUT ;
    USE SIGNAL ;
    PORT
      LAYER M5 ;
        RECT  0.96 0 0.984 0.084 ;
    END
  END fdm[5]
  PIN fdm[600]
    DIRECTION OUTPUT ;
    USE SIGNAL ;
    PORT
      LAYER M5 ;
        RECT  107.664 0 107.688 0.084 ;
    END
  END fdm[600]
  PIN fdm[601]
    DIRECTION OUTPUT ;
    USE SIGNAL ;
    PORT
      LAYER M5 ;
        RECT  107.856 0 107.88 0.084 ;
    END
  END fdm[601]
  PIN fdm[602]
    DIRECTION OUTPUT ;
    USE SIGNAL ;
    PORT
      LAYER M5 ;
        RECT  108 0 108.024 0.084 ;
    END
  END fdm[602]
  PIN fdm[603]
    DIRECTION OUTPUT ;
    USE SIGNAL ;
    PORT
      LAYER M5 ;
        RECT  108.192 0 108.216 0.084 ;
    END
  END fdm[603]
  PIN fdm[604]
    DIRECTION OUTPUT ;
    USE SIGNAL ;
    PORT
      LAYER M5 ;
        RECT  108.384 0 108.408 0.084 ;
    END
  END fdm[604]
  PIN fdm[605]
    DIRECTION OUTPUT ;
    USE SIGNAL ;
    PORT
      LAYER M5 ;
        RECT  108.576 0 108.6 0.084 ;
    END
  END fdm[605]
  PIN fdm[606]
    DIRECTION OUTPUT ;
    USE SIGNAL ;
    PORT
      LAYER M5 ;
        RECT  108.72 0 108.744 0.084 ;
    END
  END fdm[606]
  PIN fdm[607]
    DIRECTION OUTPUT ;
    USE SIGNAL ;
    PORT
      LAYER M5 ;
        RECT  108.912 0 108.936 0.084 ;
    END
  END fdm[607]
  PIN fdm[608]
    DIRECTION OUTPUT ;
    USE SIGNAL ;
    PORT
      LAYER M5 ;
        RECT  109.104 0 109.128 0.084 ;
    END
  END fdm[608]
  PIN fdm[609]
    DIRECTION OUTPUT ;
    USE SIGNAL ;
    PORT
      LAYER M5 ;
        RECT  109.296 0 109.32 0.084 ;
    END
  END fdm[609]
  PIN fdm[60]
    DIRECTION OUTPUT ;
    USE SIGNAL ;
    PORT
      LAYER M5 ;
        RECT  10.8 0 10.824 0.084 ;
    END
  END fdm[60]
  PIN fdm[610]
    DIRECTION OUTPUT ;
    USE SIGNAL ;
    PORT
      LAYER M5 ;
        RECT  109.44 0 109.464 0.084 ;
    END
  END fdm[610]
  PIN fdm[611]
    DIRECTION OUTPUT ;
    USE SIGNAL ;
    PORT
      LAYER M5 ;
        RECT  109.632 0 109.656 0.084 ;
    END
  END fdm[611]
  PIN fdm[612]
    DIRECTION OUTPUT ;
    USE SIGNAL ;
    PORT
      LAYER M5 ;
        RECT  109.824 0 109.848 0.084 ;
    END
  END fdm[612]
  PIN fdm[613]
    DIRECTION OUTPUT ;
    USE SIGNAL ;
    PORT
      LAYER M5 ;
        RECT  109.968 0 109.992 0.084 ;
    END
  END fdm[613]
  PIN fdm[614]
    DIRECTION OUTPUT ;
    USE SIGNAL ;
    PORT
      LAYER M5 ;
        RECT  110.16 0 110.184 0.084 ;
    END
  END fdm[614]
  PIN fdm[615]
    DIRECTION OUTPUT ;
    USE SIGNAL ;
    PORT
      LAYER M5 ;
        RECT  110.352 0 110.376 0.084 ;
    END
  END fdm[615]
  PIN fdm[616]
    DIRECTION OUTPUT ;
    USE SIGNAL ;
    PORT
      LAYER M5 ;
        RECT  110.544 0 110.568 0.084 ;
    END
  END fdm[616]
  PIN fdm[617]
    DIRECTION OUTPUT ;
    USE SIGNAL ;
    PORT
      LAYER M5 ;
        RECT  110.688 0 110.712 0.084 ;
    END
  END fdm[617]
  PIN fdm[618]
    DIRECTION OUTPUT ;
    USE SIGNAL ;
    PORT
      LAYER M5 ;
        RECT  110.88 0 110.904 0.084 ;
    END
  END fdm[618]
  PIN fdm[619]
    DIRECTION OUTPUT ;
    USE SIGNAL ;
    PORT
      LAYER M5 ;
        RECT  111.072 0 111.096 0.084 ;
    END
  END fdm[619]
  PIN fdm[61]
    DIRECTION OUTPUT ;
    USE SIGNAL ;
    PORT
      LAYER M5 ;
        RECT  10.992 0 11.016 0.084 ;
    END
  END fdm[61]
  PIN fdm[620]
    DIRECTION OUTPUT ;
    USE SIGNAL ;
    PORT
      LAYER M5 ;
        RECT  111.264 0 111.288 0.084 ;
    END
  END fdm[620]
  PIN fdm[621]
    DIRECTION OUTPUT ;
    USE SIGNAL ;
    PORT
      LAYER M5 ;
        RECT  111.408 0 111.432 0.084 ;
    END
  END fdm[621]
  PIN fdm[622]
    DIRECTION OUTPUT ;
    USE SIGNAL ;
    PORT
      LAYER M5 ;
        RECT  111.6 0 111.624 0.084 ;
    END
  END fdm[622]
  PIN fdm[623]
    DIRECTION OUTPUT ;
    USE SIGNAL ;
    PORT
      LAYER M5 ;
        RECT  111.792 0 111.816 0.084 ;
    END
  END fdm[623]
  PIN fdm[624]
    DIRECTION OUTPUT ;
    USE SIGNAL ;
    PORT
      LAYER M5 ;
        RECT  111.984 0 112.008 0.084 ;
    END
  END fdm[624]
  PIN fdm[625]
    DIRECTION OUTPUT ;
    USE SIGNAL ;
    PORT
      LAYER M5 ;
        RECT  112.128 0 112.152 0.084 ;
    END
  END fdm[625]
  PIN fdm[626]
    DIRECTION OUTPUT ;
    USE SIGNAL ;
    PORT
      LAYER M5 ;
        RECT  112.32 0 112.344 0.084 ;
    END
  END fdm[626]
  PIN fdm[627]
    DIRECTION OUTPUT ;
    USE SIGNAL ;
    PORT
      LAYER M5 ;
        RECT  112.512 0 112.536 0.084 ;
    END
  END fdm[627]
  PIN fdm[628]
    DIRECTION OUTPUT ;
    USE SIGNAL ;
    PORT
      LAYER M5 ;
        RECT  112.704 0 112.728 0.084 ;
    END
  END fdm[628]
  PIN fdm[629]
    DIRECTION OUTPUT ;
    USE SIGNAL ;
    PORT
      LAYER M5 ;
        RECT  112.848 0 112.872 0.084 ;
    END
  END fdm[629]
  PIN fdm[62]
    DIRECTION OUTPUT ;
    USE SIGNAL ;
    PORT
      LAYER M5 ;
        RECT  11.184 0 11.208 0.084 ;
    END
  END fdm[62]
  PIN fdm[630]
    DIRECTION OUTPUT ;
    USE SIGNAL ;
    PORT
      LAYER M5 ;
        RECT  113.04 0 113.064 0.084 ;
    END
  END fdm[630]
  PIN fdm[631]
    DIRECTION OUTPUT ;
    USE SIGNAL ;
    PORT
      LAYER M5 ;
        RECT  113.232 0 113.256 0.084 ;
    END
  END fdm[631]
  PIN fdm[632]
    DIRECTION OUTPUT ;
    USE SIGNAL ;
    PORT
      LAYER M5 ;
        RECT  113.376 0 113.4 0.084 ;
    END
  END fdm[632]
  PIN fdm[633]
    DIRECTION OUTPUT ;
    USE SIGNAL ;
    PORT
      LAYER M5 ;
        RECT  113.568 0 113.592 0.084 ;
    END
  END fdm[633]
  PIN fdm[634]
    DIRECTION OUTPUT ;
    USE SIGNAL ;
    PORT
      LAYER M5 ;
        RECT  113.76 0 113.784 0.084 ;
    END
  END fdm[634]
  PIN fdm[635]
    DIRECTION OUTPUT ;
    USE SIGNAL ;
    PORT
      LAYER M5 ;
        RECT  113.952 0 113.976 0.084 ;
    END
  END fdm[635]
  PIN fdm[636]
    DIRECTION OUTPUT ;
    USE SIGNAL ;
    PORT
      LAYER M5 ;
        RECT  114.096 0 114.12 0.084 ;
    END
  END fdm[636]
  PIN fdm[637]
    DIRECTION OUTPUT ;
    USE SIGNAL ;
    PORT
      LAYER M5 ;
        RECT  114.288 0 114.312 0.084 ;
    END
  END fdm[637]
  PIN fdm[638]
    DIRECTION OUTPUT ;
    USE SIGNAL ;
    PORT
      LAYER M5 ;
        RECT  114.48 0 114.504 0.084 ;
    END
  END fdm[638]
  PIN fdm[639]
    DIRECTION OUTPUT ;
    USE SIGNAL ;
    PORT
      LAYER M5 ;
        RECT  114.672 0 114.696 0.084 ;
    END
  END fdm[639]
  PIN fdm[63]
    DIRECTION OUTPUT ;
    USE SIGNAL ;
    PORT
      LAYER M5 ;
        RECT  11.376 0 11.4 0.084 ;
    END
  END fdm[63]
  PIN fdm[640]
    DIRECTION OUTPUT ;
    USE SIGNAL ;
    PORT
      LAYER M5 ;
        RECT  114.816 0 114.84 0.084 ;
    END
  END fdm[640]
  PIN fdm[641]
    DIRECTION OUTPUT ;
    USE SIGNAL ;
    PORT
      LAYER M5 ;
        RECT  115.008 0 115.032 0.084 ;
    END
  END fdm[641]
  PIN fdm[642]
    DIRECTION OUTPUT ;
    USE SIGNAL ;
    PORT
      LAYER M5 ;
        RECT  115.2 0 115.224 0.084 ;
    END
  END fdm[642]
  PIN fdm[643]
    DIRECTION OUTPUT ;
    USE SIGNAL ;
    PORT
      LAYER M5 ;
        RECT  115.392 0 115.416 0.084 ;
    END
  END fdm[643]
  PIN fdm[644]
    DIRECTION OUTPUT ;
    USE SIGNAL ;
    PORT
      LAYER M5 ;
        RECT  115.536 0 115.56 0.084 ;
    END
  END fdm[644]
  PIN fdm[645]
    DIRECTION OUTPUT ;
    USE SIGNAL ;
    PORT
      LAYER M5 ;
        RECT  115.728 0 115.752 0.084 ;
    END
  END fdm[645]
  PIN fdm[646]
    DIRECTION OUTPUT ;
    USE SIGNAL ;
    PORT
      LAYER M5 ;
        RECT  115.92 0 115.944 0.084 ;
    END
  END fdm[646]
  PIN fdm[647]
    DIRECTION OUTPUT ;
    USE SIGNAL ;
    PORT
      LAYER M5 ;
        RECT  116.112 0 116.136 0.084 ;
    END
  END fdm[647]
  PIN fdm[648]
    DIRECTION OUTPUT ;
    USE SIGNAL ;
    PORT
      LAYER M5 ;
        RECT  116.256 0 116.28 0.084 ;
    END
  END fdm[648]
  PIN fdm[649]
    DIRECTION OUTPUT ;
    USE SIGNAL ;
    PORT
      LAYER M5 ;
        RECT  116.448 0 116.472 0.084 ;
    END
  END fdm[649]
  PIN fdm[64]
    DIRECTION OUTPUT ;
    USE SIGNAL ;
    PORT
      LAYER M5 ;
        RECT  11.52 0 11.544 0.084 ;
    END
  END fdm[64]
  PIN fdm[650]
    DIRECTION OUTPUT ;
    USE SIGNAL ;
    PORT
      LAYER M5 ;
        RECT  116.64 0 116.664 0.084 ;
    END
  END fdm[650]
  PIN fdm[651]
    DIRECTION OUTPUT ;
    USE SIGNAL ;
    PORT
      LAYER M5 ;
        RECT  116.784 0 116.808 0.084 ;
    END
  END fdm[651]
  PIN fdm[652]
    DIRECTION OUTPUT ;
    USE SIGNAL ;
    PORT
      LAYER M5 ;
        RECT  116.976 0 117 0.084 ;
    END
  END fdm[652]
  PIN fdm[653]
    DIRECTION OUTPUT ;
    USE SIGNAL ;
    PORT
      LAYER M5 ;
        RECT  117.168 0 117.192 0.084 ;
    END
  END fdm[653]
  PIN fdm[654]
    DIRECTION OUTPUT ;
    USE SIGNAL ;
    PORT
      LAYER M5 ;
        RECT  117.36 0 117.384 0.084 ;
    END
  END fdm[654]
  PIN fdm[655]
    DIRECTION OUTPUT ;
    USE SIGNAL ;
    PORT
      LAYER M5 ;
        RECT  117.504 0 117.528 0.084 ;
    END
  END fdm[655]
  PIN fdm[656]
    DIRECTION OUTPUT ;
    USE SIGNAL ;
    PORT
      LAYER M5 ;
        RECT  117.696 0 117.72 0.084 ;
    END
  END fdm[656]
  PIN fdm[657]
    DIRECTION OUTPUT ;
    USE SIGNAL ;
    PORT
      LAYER M5 ;
        RECT  117.888 0 117.912 0.084 ;
    END
  END fdm[657]
  PIN fdm[658]
    DIRECTION OUTPUT ;
    USE SIGNAL ;
    PORT
      LAYER M5 ;
        RECT  118.08 0 118.104 0.084 ;
    END
  END fdm[658]
  PIN fdm[659]
    DIRECTION OUTPUT ;
    USE SIGNAL ;
    PORT
      LAYER M5 ;
        RECT  118.224 0 118.248 0.084 ;
    END
  END fdm[659]
  PIN fdm[65]
    DIRECTION OUTPUT ;
    USE SIGNAL ;
    PORT
      LAYER M5 ;
        RECT  11.712 0 11.736 0.084 ;
    END
  END fdm[65]
  PIN fdm[660]
    DIRECTION OUTPUT ;
    USE SIGNAL ;
    PORT
      LAYER M5 ;
        RECT  118.416 0 118.44 0.084 ;
    END
  END fdm[660]
  PIN fdm[661]
    DIRECTION OUTPUT ;
    USE SIGNAL ;
    PORT
      LAYER M5 ;
        RECT  118.608 0 118.632 0.084 ;
    END
  END fdm[661]
  PIN fdm[662]
    DIRECTION OUTPUT ;
    USE SIGNAL ;
    PORT
      LAYER M5 ;
        RECT  118.8 0 118.824 0.084 ;
    END
  END fdm[662]
  PIN fdm[663]
    DIRECTION OUTPUT ;
    USE SIGNAL ;
    PORT
      LAYER M5 ;
        RECT  118.944 0 118.968 0.084 ;
    END
  END fdm[663]
  PIN fdm[664]
    DIRECTION OUTPUT ;
    USE SIGNAL ;
    PORT
      LAYER M5 ;
        RECT  119.136 0 119.16 0.084 ;
    END
  END fdm[664]
  PIN fdm[665]
    DIRECTION OUTPUT ;
    USE SIGNAL ;
    PORT
      LAYER M5 ;
        RECT  119.328 0 119.352 0.084 ;
    END
  END fdm[665]
  PIN fdm[666]
    DIRECTION OUTPUT ;
    USE SIGNAL ;
    PORT
      LAYER M5 ;
        RECT  119.52 0 119.544 0.084 ;
    END
  END fdm[666]
  PIN fdm[667]
    DIRECTION OUTPUT ;
    USE SIGNAL ;
    PORT
      LAYER M5 ;
        RECT  119.664 0 119.688 0.084 ;
    END
  END fdm[667]
  PIN fdm[668]
    DIRECTION OUTPUT ;
    USE SIGNAL ;
    PORT
      LAYER M5 ;
        RECT  119.856 0 119.88 0.084 ;
    END
  END fdm[668]
  PIN fdm[669]
    DIRECTION OUTPUT ;
    USE SIGNAL ;
    PORT
      LAYER M5 ;
        RECT  120.048 0 120.072 0.084 ;
    END
  END fdm[669]
  PIN fdm[66]
    DIRECTION OUTPUT ;
    USE SIGNAL ;
    PORT
      LAYER M5 ;
        RECT  11.904 0 11.928 0.084 ;
    END
  END fdm[66]
  PIN fdm[670]
    DIRECTION OUTPUT ;
    USE SIGNAL ;
    PORT
      LAYER M5 ;
        RECT  120.192 0 120.216 0.084 ;
    END
  END fdm[670]
  PIN fdm[671]
    DIRECTION OUTPUT ;
    USE SIGNAL ;
    PORT
      LAYER M5 ;
        RECT  120.384 0 120.408 0.084 ;
    END
  END fdm[671]
  PIN fdm[672]
    DIRECTION OUTPUT ;
    USE SIGNAL ;
    PORT
      LAYER M5 ;
        RECT  120.576 0 120.6 0.084 ;
    END
  END fdm[672]
  PIN fdm[673]
    DIRECTION OUTPUT ;
    USE SIGNAL ;
    PORT
      LAYER M5 ;
        RECT  120.768 0 120.792 0.084 ;
    END
  END fdm[673]
  PIN fdm[674]
    DIRECTION OUTPUT ;
    USE SIGNAL ;
    PORT
      LAYER M5 ;
        RECT  120.912 0 120.936 0.084 ;
    END
  END fdm[674]
  PIN fdm[675]
    DIRECTION OUTPUT ;
    USE SIGNAL ;
    PORT
      LAYER M5 ;
        RECT  121.104 0 121.128 0.084 ;
    END
  END fdm[675]
  PIN fdm[676]
    DIRECTION OUTPUT ;
    USE SIGNAL ;
    PORT
      LAYER M5 ;
        RECT  121.296 0 121.32 0.084 ;
    END
  END fdm[676]
  PIN fdm[677]
    DIRECTION OUTPUT ;
    USE SIGNAL ;
    PORT
      LAYER M5 ;
        RECT  121.488 0 121.512 0.084 ;
    END
  END fdm[677]
  PIN fdm[678]
    DIRECTION OUTPUT ;
    USE SIGNAL ;
    PORT
      LAYER M5 ;
        RECT  121.632 0 121.656 0.084 ;
    END
  END fdm[678]
  PIN fdm[679]
    DIRECTION OUTPUT ;
    USE SIGNAL ;
    PORT
      LAYER M5 ;
        RECT  121.824 0 121.848 0.084 ;
    END
  END fdm[679]
  PIN fdm[67]
    DIRECTION OUTPUT ;
    USE SIGNAL ;
    PORT
      LAYER M5 ;
        RECT  12.048 0 12.072 0.084 ;
    END
  END fdm[67]
  PIN fdm[680]
    DIRECTION OUTPUT ;
    USE SIGNAL ;
    PORT
      LAYER M5 ;
        RECT  122.016 0 122.04 0.084 ;
    END
  END fdm[680]
  PIN fdm[681]
    DIRECTION OUTPUT ;
    USE SIGNAL ;
    PORT
      LAYER M5 ;
        RECT  122.208 0 122.232 0.084 ;
    END
  END fdm[681]
  PIN fdm[682]
    DIRECTION OUTPUT ;
    USE SIGNAL ;
    PORT
      LAYER M5 ;
        RECT  122.352 0 122.376 0.084 ;
    END
  END fdm[682]
  PIN fdm[683]
    DIRECTION OUTPUT ;
    USE SIGNAL ;
    PORT
      LAYER M5 ;
        RECT  122.544 0 122.568 0.084 ;
    END
  END fdm[683]
  PIN fdm[684]
    DIRECTION OUTPUT ;
    USE SIGNAL ;
    PORT
      LAYER M5 ;
        RECT  122.736 0 122.76 0.084 ;
    END
  END fdm[684]
  PIN fdm[685]
    DIRECTION OUTPUT ;
    USE SIGNAL ;
    PORT
      LAYER M5 ;
        RECT  122.928 0 122.952 0.084 ;
    END
  END fdm[685]
  PIN fdm[686]
    DIRECTION OUTPUT ;
    USE SIGNAL ;
    PORT
      LAYER M5 ;
        RECT  123.072 0 123.096 0.084 ;
    END
  END fdm[686]
  PIN fdm[687]
    DIRECTION OUTPUT ;
    USE SIGNAL ;
    PORT
      LAYER M5 ;
        RECT  123.264 0 123.288 0.084 ;
    END
  END fdm[687]
  PIN fdm[688]
    DIRECTION OUTPUT ;
    USE SIGNAL ;
    PORT
      LAYER M5 ;
        RECT  123.456 0 123.48 0.084 ;
    END
  END fdm[688]
  PIN fdm[689]
    DIRECTION OUTPUT ;
    USE SIGNAL ;
    PORT
      LAYER M5 ;
        RECT  123.6 0 123.624 0.084 ;
    END
  END fdm[689]
  PIN fdm[68]
    DIRECTION OUTPUT ;
    USE SIGNAL ;
    PORT
      LAYER M5 ;
        RECT  12.24 0 12.264 0.084 ;
    END
  END fdm[68]
  PIN fdm[690]
    DIRECTION OUTPUT ;
    USE SIGNAL ;
    PORT
      LAYER M5 ;
        RECT  123.792 0 123.816 0.084 ;
    END
  END fdm[690]
  PIN fdm[691]
    DIRECTION OUTPUT ;
    USE SIGNAL ;
    PORT
      LAYER M5 ;
        RECT  123.984 0 124.008 0.084 ;
    END
  END fdm[691]
  PIN fdm[692]
    DIRECTION OUTPUT ;
    USE SIGNAL ;
    PORT
      LAYER M5 ;
        RECT  124.176 0 124.2 0.084 ;
    END
  END fdm[692]
  PIN fdm[693]
    DIRECTION OUTPUT ;
    USE SIGNAL ;
    PORT
      LAYER M5 ;
        RECT  124.32 0 124.344 0.084 ;
    END
  END fdm[693]
  PIN fdm[694]
    DIRECTION OUTPUT ;
    USE SIGNAL ;
    PORT
      LAYER M5 ;
        RECT  124.512 0 124.536 0.084 ;
    END
  END fdm[694]
  PIN fdm[695]
    DIRECTION OUTPUT ;
    USE SIGNAL ;
    PORT
      LAYER M5 ;
        RECT  124.704 0 124.728 0.084 ;
    END
  END fdm[695]
  PIN fdm[696]
    DIRECTION OUTPUT ;
    USE SIGNAL ;
    PORT
      LAYER M5 ;
        RECT  124.896 0 124.92 0.084 ;
    END
  END fdm[696]
  PIN fdm[697]
    DIRECTION OUTPUT ;
    USE SIGNAL ;
    PORT
      LAYER M5 ;
        RECT  125.04 0 125.064 0.084 ;
    END
  END fdm[697]
  PIN fdm[698]
    DIRECTION OUTPUT ;
    USE SIGNAL ;
    PORT
      LAYER M5 ;
        RECT  125.232 0 125.256 0.084 ;
    END
  END fdm[698]
  PIN fdm[699]
    DIRECTION OUTPUT ;
    USE SIGNAL ;
    PORT
      LAYER M5 ;
        RECT  125.424 0 125.448 0.084 ;
    END
  END fdm[699]
  PIN fdm[69]
    DIRECTION OUTPUT ;
    USE SIGNAL ;
    PORT
      LAYER M5 ;
        RECT  12.432 0 12.456 0.084 ;
    END
  END fdm[69]
  PIN fdm[6]
    DIRECTION OUTPUT ;
    USE SIGNAL ;
    PORT
      LAYER M5 ;
        RECT  1.152 0 1.176 0.084 ;
    END
  END fdm[6]
  PIN fdm[700]
    DIRECTION OUTPUT ;
    USE SIGNAL ;
    PORT
      LAYER M5 ;
        RECT  125.616 0 125.64 0.084 ;
    END
  END fdm[700]
  PIN fdm[701]
    DIRECTION OUTPUT ;
    USE SIGNAL ;
    PORT
      LAYER M5 ;
        RECT  125.76 0 125.784 0.084 ;
    END
  END fdm[701]
  PIN fdm[702]
    DIRECTION OUTPUT ;
    USE SIGNAL ;
    PORT
      LAYER M5 ;
        RECT  125.952 0 125.976 0.084 ;
    END
  END fdm[702]
  PIN fdm[703]
    DIRECTION OUTPUT ;
    USE SIGNAL ;
    PORT
      LAYER M5 ;
        RECT  126.144 0 126.168 0.084 ;
    END
  END fdm[703]
  PIN fdm[704]
    DIRECTION OUTPUT ;
    USE SIGNAL ;
    PORT
      LAYER M5 ;
        RECT  126.288 0 126.312 0.084 ;
    END
  END fdm[704]
  PIN fdm[705]
    DIRECTION OUTPUT ;
    USE SIGNAL ;
    PORT
      LAYER M5 ;
        RECT  126.48 0 126.504 0.084 ;
    END
  END fdm[705]
  PIN fdm[706]
    DIRECTION OUTPUT ;
    USE SIGNAL ;
    PORT
      LAYER M5 ;
        RECT  126.672 0 126.696 0.084 ;
    END
  END fdm[706]
  PIN fdm[707]
    DIRECTION OUTPUT ;
    USE SIGNAL ;
    PORT
      LAYER M5 ;
        RECT  126.864 0 126.888 0.084 ;
    END
  END fdm[707]
  PIN fdm[708]
    DIRECTION OUTPUT ;
    USE SIGNAL ;
    PORT
      LAYER M5 ;
        RECT  127.008 0 127.032 0.084 ;
    END
  END fdm[708]
  PIN fdm[709]
    DIRECTION OUTPUT ;
    USE SIGNAL ;
    PORT
      LAYER M5 ;
        RECT  127.2 0 127.224 0.084 ;
    END
  END fdm[709]
  PIN fdm[70]
    DIRECTION OUTPUT ;
    USE SIGNAL ;
    PORT
      LAYER M5 ;
        RECT  12.624 0 12.648 0.084 ;
    END
  END fdm[70]
  PIN fdm[710]
    DIRECTION OUTPUT ;
    USE SIGNAL ;
    PORT
      LAYER M5 ;
        RECT  127.392 0 127.416 0.084 ;
    END
  END fdm[710]
  PIN fdm[711]
    DIRECTION OUTPUT ;
    USE SIGNAL ;
    PORT
      LAYER M5 ;
        RECT  127.584 0 127.608 0.084 ;
    END
  END fdm[711]
  PIN fdm[712]
    DIRECTION OUTPUT ;
    USE SIGNAL ;
    PORT
      LAYER M5 ;
        RECT  127.728 0 127.752 0.084 ;
    END
  END fdm[712]
  PIN fdm[713]
    DIRECTION OUTPUT ;
    USE SIGNAL ;
    PORT
      LAYER M5 ;
        RECT  127.92 0 127.944 0.084 ;
    END
  END fdm[713]
  PIN fdm[714]
    DIRECTION OUTPUT ;
    USE SIGNAL ;
    PORT
      LAYER M5 ;
        RECT  128.112 0 128.136 0.084 ;
    END
  END fdm[714]
  PIN fdm[715]
    DIRECTION OUTPUT ;
    USE SIGNAL ;
    PORT
      LAYER M5 ;
        RECT  128.304 0 128.328 0.084 ;
    END
  END fdm[715]
  PIN fdm[716]
    DIRECTION OUTPUT ;
    USE SIGNAL ;
    PORT
      LAYER M5 ;
        RECT  128.448 0 128.472 0.084 ;
    END
  END fdm[716]
  PIN fdm[717]
    DIRECTION OUTPUT ;
    USE SIGNAL ;
    PORT
      LAYER M5 ;
        RECT  128.64 0 128.664 0.084 ;
    END
  END fdm[717]
  PIN fdm[718]
    DIRECTION OUTPUT ;
    USE SIGNAL ;
    PORT
      LAYER M5 ;
        RECT  128.832 0 128.856 0.084 ;
    END
  END fdm[718]
  PIN fdm[719]
    DIRECTION OUTPUT ;
    USE SIGNAL ;
    PORT
      LAYER M5 ;
        RECT  129.024 0 129.048 0.084 ;
    END
  END fdm[719]
  PIN fdm[71]
    DIRECTION OUTPUT ;
    USE SIGNAL ;
    PORT
      LAYER M5 ;
        RECT  12.768 0 12.792 0.084 ;
    END
  END fdm[71]
  PIN fdm[720]
    DIRECTION OUTPUT ;
    USE SIGNAL ;
    PORT
      LAYER M5 ;
        RECT  129.168 0 129.192 0.084 ;
    END
  END fdm[720]
  PIN fdm[721]
    DIRECTION OUTPUT ;
    USE SIGNAL ;
    PORT
      LAYER M5 ;
        RECT  129.36 0 129.384 0.084 ;
    END
  END fdm[721]
  PIN fdm[722]
    DIRECTION OUTPUT ;
    USE SIGNAL ;
    PORT
      LAYER M5 ;
        RECT  129.552 0 129.576 0.084 ;
    END
  END fdm[722]
  PIN fdm[723]
    DIRECTION OUTPUT ;
    USE SIGNAL ;
    PORT
      LAYER M5 ;
        RECT  129.696 0 129.72 0.084 ;
    END
  END fdm[723]
  PIN fdm[724]
    DIRECTION OUTPUT ;
    USE SIGNAL ;
    PORT
      LAYER M5 ;
        RECT  129.888 0 129.912 0.084 ;
    END
  END fdm[724]
  PIN fdm[725]
    DIRECTION OUTPUT ;
    USE SIGNAL ;
    PORT
      LAYER M5 ;
        RECT  130.08 0 130.104 0.084 ;
    END
  END fdm[725]
  PIN fdm[726]
    DIRECTION OUTPUT ;
    USE SIGNAL ;
    PORT
      LAYER M5 ;
        RECT  130.272 0 130.296 0.084 ;
    END
  END fdm[726]
  PIN fdm[727]
    DIRECTION OUTPUT ;
    USE SIGNAL ;
    PORT
      LAYER M5 ;
        RECT  130.416 0 130.44 0.084 ;
    END
  END fdm[727]
  PIN fdm[728]
    DIRECTION OUTPUT ;
    USE SIGNAL ;
    PORT
      LAYER M5 ;
        RECT  130.608 0 130.632 0.084 ;
    END
  END fdm[728]
  PIN fdm[729]
    DIRECTION OUTPUT ;
    USE SIGNAL ;
    PORT
      LAYER M5 ;
        RECT  130.8 0 130.824 0.084 ;
    END
  END fdm[729]
  PIN fdm[72]
    DIRECTION OUTPUT ;
    USE SIGNAL ;
    PORT
      LAYER M5 ;
        RECT  12.96 0 12.984 0.084 ;
    END
  END fdm[72]
  PIN fdm[730]
    DIRECTION OUTPUT ;
    USE SIGNAL ;
    PORT
      LAYER M5 ;
        RECT  130.992 0 131.016 0.084 ;
    END
  END fdm[730]
  PIN fdm[731]
    DIRECTION OUTPUT ;
    USE SIGNAL ;
    PORT
      LAYER M5 ;
        RECT  131.136 0 131.16 0.084 ;
    END
  END fdm[731]
  PIN fdm[732]
    DIRECTION OUTPUT ;
    USE SIGNAL ;
    PORT
      LAYER M5 ;
        RECT  131.328 0 131.352 0.084 ;
    END
  END fdm[732]
  PIN fdm[733]
    DIRECTION OUTPUT ;
    USE SIGNAL ;
    PORT
      LAYER M5 ;
        RECT  131.52 0 131.544 0.084 ;
    END
  END fdm[733]
  PIN fdm[734]
    DIRECTION OUTPUT ;
    USE SIGNAL ;
    PORT
      LAYER M5 ;
        RECT  131.712 0 131.736 0.084 ;
    END
  END fdm[734]
  PIN fdm[735]
    DIRECTION OUTPUT ;
    USE SIGNAL ;
    PORT
      LAYER M5 ;
        RECT  131.856 0 131.88 0.084 ;
    END
  END fdm[735]
  PIN fdm[736]
    DIRECTION OUTPUT ;
    USE SIGNAL ;
    PORT
      LAYER M5 ;
        RECT  132.048 0 132.072 0.084 ;
    END
  END fdm[736]
  PIN fdm[737]
    DIRECTION OUTPUT ;
    USE SIGNAL ;
    PORT
      LAYER M5 ;
        RECT  132.24 0 132.264 0.084 ;
    END
  END fdm[737]
  PIN fdm[738]
    DIRECTION OUTPUT ;
    USE SIGNAL ;
    PORT
      LAYER M5 ;
        RECT  132.432 0 132.456 0.084 ;
    END
  END fdm[738]
  PIN fdm[739]
    DIRECTION OUTPUT ;
    USE SIGNAL ;
    PORT
      LAYER M5 ;
        RECT  132.576 0 132.6 0.084 ;
    END
  END fdm[739]
  PIN fdm[73]
    DIRECTION OUTPUT ;
    USE SIGNAL ;
    PORT
      LAYER M5 ;
        RECT  13.152 0 13.176 0.084 ;
    END
  END fdm[73]
  PIN fdm[740]
    DIRECTION OUTPUT ;
    USE SIGNAL ;
    PORT
      LAYER M5 ;
        RECT  132.768 0 132.792 0.084 ;
    END
  END fdm[740]
  PIN fdm[741]
    DIRECTION OUTPUT ;
    USE SIGNAL ;
    PORT
      LAYER M5 ;
        RECT  132.96 0 132.984 0.084 ;
    END
  END fdm[741]
  PIN fdm[742]
    DIRECTION OUTPUT ;
    USE SIGNAL ;
    PORT
      LAYER M5 ;
        RECT  133.104 0 133.128 0.084 ;
    END
  END fdm[742]
  PIN fdm[743]
    DIRECTION OUTPUT ;
    USE SIGNAL ;
    PORT
      LAYER M5 ;
        RECT  133.296 0 133.32 0.084 ;
    END
  END fdm[743]
  PIN fdm[744]
    DIRECTION OUTPUT ;
    USE SIGNAL ;
    PORT
      LAYER M5 ;
        RECT  133.488 0 133.512 0.084 ;
    END
  END fdm[744]
  PIN fdm[745]
    DIRECTION OUTPUT ;
    USE SIGNAL ;
    PORT
      LAYER M5 ;
        RECT  133.68 0 133.704 0.084 ;
    END
  END fdm[745]
  PIN fdm[746]
    DIRECTION OUTPUT ;
    USE SIGNAL ;
    PORT
      LAYER M5 ;
        RECT  133.824 0 133.848 0.084 ;
    END
  END fdm[746]
  PIN fdm[747]
    DIRECTION OUTPUT ;
    USE SIGNAL ;
    PORT
      LAYER M5 ;
        RECT  134.016 0 134.04 0.084 ;
    END
  END fdm[747]
  PIN fdm[748]
    DIRECTION OUTPUT ;
    USE SIGNAL ;
    PORT
      LAYER M5 ;
        RECT  134.208 0 134.232 0.084 ;
    END
  END fdm[748]
  PIN fdm[749]
    DIRECTION OUTPUT ;
    USE SIGNAL ;
    PORT
      LAYER M5 ;
        RECT  134.4 0 134.424 0.084 ;
    END
  END fdm[749]
  PIN fdm[74]
    DIRECTION OUTPUT ;
    USE SIGNAL ;
    PORT
      LAYER M5 ;
        RECT  13.344 0 13.368 0.084 ;
    END
  END fdm[74]
  PIN fdm[750]
    DIRECTION OUTPUT ;
    USE SIGNAL ;
    PORT
      LAYER M5 ;
        RECT  134.544 0 134.568 0.084 ;
    END
  END fdm[750]
  PIN fdm[751]
    DIRECTION OUTPUT ;
    USE SIGNAL ;
    PORT
      LAYER M5 ;
        RECT  134.736 0 134.76 0.084 ;
    END
  END fdm[751]
  PIN fdm[752]
    DIRECTION OUTPUT ;
    USE SIGNAL ;
    PORT
      LAYER M5 ;
        RECT  134.928 0 134.952 0.084 ;
    END
  END fdm[752]
  PIN fdm[753]
    DIRECTION OUTPUT ;
    USE SIGNAL ;
    PORT
      LAYER M5 ;
        RECT  135.12 0 135.144 0.084 ;
    END
  END fdm[753]
  PIN fdm[754]
    DIRECTION OUTPUT ;
    USE SIGNAL ;
    PORT
      LAYER M5 ;
        RECT  135.264 0 135.288 0.084 ;
    END
  END fdm[754]
  PIN fdm[755]
    DIRECTION OUTPUT ;
    USE SIGNAL ;
    PORT
      LAYER M5 ;
        RECT  135.456 0 135.48 0.084 ;
    END
  END fdm[755]
  PIN fdm[756]
    DIRECTION OUTPUT ;
    USE SIGNAL ;
    PORT
      LAYER M5 ;
        RECT  135.648 0 135.672 0.084 ;
    END
  END fdm[756]
  PIN fdm[757]
    DIRECTION OUTPUT ;
    USE SIGNAL ;
    PORT
      LAYER M5 ;
        RECT  135.84 0 135.864 0.084 ;
    END
  END fdm[757]
  PIN fdm[758]
    DIRECTION OUTPUT ;
    USE SIGNAL ;
    PORT
      LAYER M5 ;
        RECT  135.984 0 136.008 0.084 ;
    END
  END fdm[758]
  PIN fdm[759]
    DIRECTION OUTPUT ;
    USE SIGNAL ;
    PORT
      LAYER M5 ;
        RECT  136.176 0 136.2 0.084 ;
    END
  END fdm[759]
  PIN fdm[75]
    DIRECTION OUTPUT ;
    USE SIGNAL ;
    PORT
      LAYER M5 ;
        RECT  13.488 0 13.512 0.084 ;
    END
  END fdm[75]
  PIN fdm[760]
    DIRECTION OUTPUT ;
    USE SIGNAL ;
    PORT
      LAYER M5 ;
        RECT  136.368 0 136.392 0.084 ;
    END
  END fdm[760]
  PIN fdm[761]
    DIRECTION OUTPUT ;
    USE SIGNAL ;
    PORT
      LAYER M5 ;
        RECT  136.512 0 136.536 0.084 ;
    END
  END fdm[761]
  PIN fdm[762]
    DIRECTION OUTPUT ;
    USE SIGNAL ;
    PORT
      LAYER M5 ;
        RECT  136.704 0 136.728 0.084 ;
    END
  END fdm[762]
  PIN fdm[763]
    DIRECTION OUTPUT ;
    USE SIGNAL ;
    PORT
      LAYER M5 ;
        RECT  136.896 0 136.92 0.084 ;
    END
  END fdm[763]
  PIN fdm[764]
    DIRECTION OUTPUT ;
    USE SIGNAL ;
    PORT
      LAYER M5 ;
        RECT  137.088 0 137.112 0.084 ;
    END
  END fdm[764]
  PIN fdm[765]
    DIRECTION OUTPUT ;
    USE SIGNAL ;
    PORT
      LAYER M5 ;
        RECT  137.232 0 137.256 0.084 ;
    END
  END fdm[765]
  PIN fdm[766]
    DIRECTION OUTPUT ;
    USE SIGNAL ;
    PORT
      LAYER M5 ;
        RECT  137.424 0 137.448 0.084 ;
    END
  END fdm[766]
  PIN fdm[767]
    DIRECTION OUTPUT ;
    USE SIGNAL ;
    PORT
      LAYER M5 ;
        RECT  137.616 0 137.64 0.084 ;
    END
  END fdm[767]
  PIN fdm[768]
    DIRECTION OUTPUT ;
    USE SIGNAL ;
    PORT
      LAYER M5 ;
        RECT  137.808 0 137.832 0.084 ;
    END
  END fdm[768]
  PIN fdm[769]
    DIRECTION OUTPUT ;
    USE SIGNAL ;
    PORT
      LAYER M5 ;
        RECT  137.952 0 137.976 0.084 ;
    END
  END fdm[769]
  PIN fdm[76]
    DIRECTION OUTPUT ;
    USE SIGNAL ;
    PORT
      LAYER M5 ;
        RECT  13.68 0 13.704 0.084 ;
    END
  END fdm[76]
  PIN fdm[770]
    DIRECTION OUTPUT ;
    USE SIGNAL ;
    PORT
      LAYER M5 ;
        RECT  138.144 0 138.168 0.084 ;
    END
  END fdm[770]
  PIN fdm[771]
    DIRECTION OUTPUT ;
    USE SIGNAL ;
    PORT
      LAYER M5 ;
        RECT  138.336 0 138.36 0.084 ;
    END
  END fdm[771]
  PIN fdm[772]
    DIRECTION OUTPUT ;
    USE SIGNAL ;
    PORT
      LAYER M5 ;
        RECT  138.528 0 138.552 0.084 ;
    END
  END fdm[772]
  PIN fdm[773]
    DIRECTION OUTPUT ;
    USE SIGNAL ;
    PORT
      LAYER M5 ;
        RECT  138.672 0 138.696 0.084 ;
    END
  END fdm[773]
  PIN fdm[774]
    DIRECTION OUTPUT ;
    USE SIGNAL ;
    PORT
      LAYER M5 ;
        RECT  138.864 0 138.888 0.084 ;
    END
  END fdm[774]
  PIN fdm[775]
    DIRECTION OUTPUT ;
    USE SIGNAL ;
    PORT
      LAYER M5 ;
        RECT  139.056 0 139.08 0.084 ;
    END
  END fdm[775]
  PIN fdm[776]
    DIRECTION OUTPUT ;
    USE SIGNAL ;
    PORT
      LAYER M5 ;
        RECT  139.248 0 139.272 0.084 ;
    END
  END fdm[776]
  PIN fdm[777]
    DIRECTION OUTPUT ;
    USE SIGNAL ;
    PORT
      LAYER M5 ;
        RECT  139.392 0 139.416 0.084 ;
    END
  END fdm[777]
  PIN fdm[778]
    DIRECTION OUTPUT ;
    USE SIGNAL ;
    PORT
      LAYER M5 ;
        RECT  139.584 0 139.608 0.084 ;
    END
  END fdm[778]
  PIN fdm[779]
    DIRECTION OUTPUT ;
    USE SIGNAL ;
    PORT
      LAYER M5 ;
        RECT  139.776 0 139.8 0.084 ;
    END
  END fdm[779]
  PIN fdm[77]
    DIRECTION OUTPUT ;
    USE SIGNAL ;
    PORT
      LAYER M5 ;
        RECT  13.872 0 13.896 0.084 ;
    END
  END fdm[77]
  PIN fdm[780]
    DIRECTION OUTPUT ;
    USE SIGNAL ;
    PORT
      LAYER M5 ;
        RECT  139.92 0 139.944 0.084 ;
    END
  END fdm[780]
  PIN fdm[781]
    DIRECTION OUTPUT ;
    USE SIGNAL ;
    PORT
      LAYER M5 ;
        RECT  140.112 0 140.136 0.084 ;
    END
  END fdm[781]
  PIN fdm[782]
    DIRECTION OUTPUT ;
    USE SIGNAL ;
    PORT
      LAYER M5 ;
        RECT  140.304 0 140.328 0.084 ;
    END
  END fdm[782]
  PIN fdm[783]
    DIRECTION OUTPUT ;
    USE SIGNAL ;
    PORT
      LAYER M5 ;
        RECT  140.496 0 140.52 0.084 ;
    END
  END fdm[783]
  PIN fdm[784]
    DIRECTION OUTPUT ;
    USE SIGNAL ;
    PORT
      LAYER M5 ;
        RECT  140.64 0 140.664 0.084 ;
    END
  END fdm[784]
  PIN fdm[785]
    DIRECTION OUTPUT ;
    USE SIGNAL ;
    PORT
      LAYER M5 ;
        RECT  140.832 0 140.856 0.084 ;
    END
  END fdm[785]
  PIN fdm[786]
    DIRECTION OUTPUT ;
    USE SIGNAL ;
    PORT
      LAYER M5 ;
        RECT  141.024 0 141.048 0.084 ;
    END
  END fdm[786]
  PIN fdm[787]
    DIRECTION OUTPUT ;
    USE SIGNAL ;
    PORT
      LAYER M5 ;
        RECT  141.216 0 141.24 0.084 ;
    END
  END fdm[787]
  PIN fdm[788]
    DIRECTION OUTPUT ;
    USE SIGNAL ;
    PORT
      LAYER M5 ;
        RECT  141.36 0 141.384 0.084 ;
    END
  END fdm[788]
  PIN fdm[789]
    DIRECTION OUTPUT ;
    USE SIGNAL ;
    PORT
      LAYER M5 ;
        RECT  141.552 0 141.576 0.084 ;
    END
  END fdm[789]
  PIN fdm[78]
    DIRECTION OUTPUT ;
    USE SIGNAL ;
    PORT
      LAYER M5 ;
        RECT  14.064 0 14.088 0.084 ;
    END
  END fdm[78]
  PIN fdm[790]
    DIRECTION OUTPUT ;
    USE SIGNAL ;
    PORT
      LAYER M5 ;
        RECT  141.744 0 141.768 0.084 ;
    END
  END fdm[790]
  PIN fdm[791]
    DIRECTION OUTPUT ;
    USE SIGNAL ;
    PORT
      LAYER M5 ;
        RECT  141.936 0 141.96 0.084 ;
    END
  END fdm[791]
  PIN fdm[792]
    DIRECTION OUTPUT ;
    USE SIGNAL ;
    PORT
      LAYER M5 ;
        RECT  142.08 0 142.104 0.084 ;
    END
  END fdm[792]
  PIN fdm[793]
    DIRECTION OUTPUT ;
    USE SIGNAL ;
    PORT
      LAYER M5 ;
        RECT  142.272 0 142.296 0.084 ;
    END
  END fdm[793]
  PIN fdm[794]
    DIRECTION OUTPUT ;
    USE SIGNAL ;
    PORT
      LAYER M5 ;
        RECT  142.464 0 142.488 0.084 ;
    END
  END fdm[794]
  PIN fdm[79]
    DIRECTION OUTPUT ;
    USE SIGNAL ;
    PORT
      LAYER M5 ;
        RECT  14.208 0 14.232 0.084 ;
    END
  END fdm[79]
  PIN fdm[7]
    DIRECTION OUTPUT ;
    USE SIGNAL ;
    PORT
      LAYER M5 ;
        RECT  1.296 0 1.32 0.084 ;
    END
  END fdm[7]
  PIN fdm[80]
    DIRECTION OUTPUT ;
    USE SIGNAL ;
    PORT
      LAYER M5 ;
        RECT  14.4 0 14.424 0.084 ;
    END
  END fdm[80]
  PIN fdm[81]
    DIRECTION OUTPUT ;
    USE SIGNAL ;
    PORT
      LAYER M5 ;
        RECT  14.592 0 14.616 0.084 ;
    END
  END fdm[81]
  PIN fdm[82]
    DIRECTION OUTPUT ;
    USE SIGNAL ;
    PORT
      LAYER M5 ;
        RECT  14.784 0 14.808 0.084 ;
    END
  END fdm[82]
  PIN fdm[83]
    DIRECTION OUTPUT ;
    USE SIGNAL ;
    PORT
      LAYER M5 ;
        RECT  14.928 0 14.952 0.084 ;
    END
  END fdm[83]
  PIN fdm[84]
    DIRECTION OUTPUT ;
    USE SIGNAL ;
    PORT
      LAYER M5 ;
        RECT  15.12 0 15.144 0.084 ;
    END
  END fdm[84]
  PIN fdm[85]
    DIRECTION OUTPUT ;
    USE SIGNAL ;
    PORT
      LAYER M5 ;
        RECT  15.312 0 15.336 0.084 ;
    END
  END fdm[85]
  PIN fdm[86]
    DIRECTION OUTPUT ;
    USE SIGNAL ;
    PORT
      LAYER M5 ;
        RECT  15.456 0 15.48 0.084 ;
    END
  END fdm[86]
  PIN fdm[87]
    DIRECTION OUTPUT ;
    USE SIGNAL ;
    PORT
      LAYER M5 ;
        RECT  15.648 0 15.672 0.084 ;
    END
  END fdm[87]
  PIN fdm[88]
    DIRECTION OUTPUT ;
    USE SIGNAL ;
    PORT
      LAYER M5 ;
        RECT  15.84 0 15.864 0.084 ;
    END
  END fdm[88]
  PIN fdm[89]
    DIRECTION OUTPUT ;
    USE SIGNAL ;
    PORT
      LAYER M5 ;
        RECT  16.032 0 16.056 0.084 ;
    END
  END fdm[89]
  PIN fdm[8]
    DIRECTION OUTPUT ;
    USE SIGNAL ;
    PORT
      LAYER M5 ;
        RECT  1.488 0 1.512 0.084 ;
    END
  END fdm[8]
  PIN fdm[90]
    DIRECTION OUTPUT ;
    USE SIGNAL ;
    PORT
      LAYER M5 ;
        RECT  16.176 0 16.2 0.084 ;
    END
  END fdm[90]
  PIN fdm[91]
    DIRECTION OUTPUT ;
    USE SIGNAL ;
    PORT
      LAYER M5 ;
        RECT  16.368 0 16.392 0.084 ;
    END
  END fdm[91]
  PIN fdm[92]
    DIRECTION OUTPUT ;
    USE SIGNAL ;
    PORT
      LAYER M5 ;
        RECT  16.56 0 16.584 0.084 ;
    END
  END fdm[92]
  PIN fdm[93]
    DIRECTION OUTPUT ;
    USE SIGNAL ;
    PORT
      LAYER M5 ;
        RECT  16.752 0 16.776 0.084 ;
    END
  END fdm[93]
  PIN fdm[94]
    DIRECTION OUTPUT ;
    USE SIGNAL ;
    PORT
      LAYER M5 ;
        RECT  16.896 0 16.92 0.084 ;
    END
  END fdm[94]
  PIN fdm[95]
    DIRECTION OUTPUT ;
    USE SIGNAL ;
    PORT
      LAYER M5 ;
        RECT  17.088 0 17.112 0.084 ;
    END
  END fdm[95]
  PIN fdm[96]
    DIRECTION OUTPUT ;
    USE SIGNAL ;
    PORT
      LAYER M5 ;
        RECT  17.28 0 17.304 0.084 ;
    END
  END fdm[96]
  PIN fdm[97]
    DIRECTION OUTPUT ;
    USE SIGNAL ;
    PORT
      LAYER M5 ;
        RECT  17.472 0 17.496 0.084 ;
    END
  END fdm[97]
  PIN fdm[98]
    DIRECTION OUTPUT ;
    USE SIGNAL ;
    PORT
      LAYER M5 ;
        RECT  17.616 0 17.64 0.084 ;
    END
  END fdm[98]
  PIN fdm[99]
    DIRECTION OUTPUT ;
    USE SIGNAL ;
    PORT
      LAYER M5 ;
        RECT  17.808 0 17.832 0.084 ;
    END
  END fdm[99]
  PIN fdm[9]
    DIRECTION OUTPUT ;
    USE SIGNAL ;
    PORT
      LAYER M5 ;
        RECT  1.68 0 1.704 0.084 ;
    END
  END fdm[9]
  PIN VDD
    DIRECTION INOUT ;
    USE POWER ;
    PORT
      LAYER M5 ;
        RECT  137.592 2.151 137.712 23.769 ;
        RECT  132.192 2.151 132.312 23.769 ;
        RECT  126.792 2.151 126.912 23.769 ;
        RECT  121.392 2.151 121.512 23.769 ;
        RECT  115.992 2.151 116.112 23.769 ;
        RECT  110.592 2.151 110.712 23.769 ;
        RECT  105.192 2.151 105.312 23.769 ;
        RECT  99.792 2.151 99.912 23.769 ;
        RECT  94.392 2.151 94.512 23.769 ;
        RECT  88.992 2.151 89.112 23.769 ;
        RECT  83.592 2.151 83.712 23.769 ;
        RECT  78.192 2.151 78.312 23.769 ;
        RECT  72.792 2.151 72.912 23.769 ;
        RECT  67.392 2.151 67.512 23.769 ;
        RECT  61.992 2.151 62.112 23.769 ;
        RECT  56.592 2.151 56.712 23.769 ;
        RECT  51.192 2.151 51.312 23.769 ;
        RECT  45.792 2.151 45.912 23.769 ;
        RECT  40.392 2.151 40.512 23.769 ;
        RECT  34.992 2.151 35.112 23.769 ;
        RECT  29.592 2.151 29.712 23.769 ;
        RECT  24.192 2.151 24.312 23.769 ;
        RECT  18.792 2.151 18.912 23.769 ;
        RECT  13.392 2.151 13.512 23.769 ;
        RECT  7.992 2.151 8.112 23.769 ;
        RECT  2.592 2.151 2.712 23.769 ;
    END
  END VDD
  PIN VSS
    DIRECTION INOUT ;
    USE GROUND ;
    PORT
      LAYER M5 ;
        RECT  137.4 2.137 137.52 23.783 ;
        RECT  132 2.137 132.12 23.783 ;
        RECT  126.6 2.137 126.72 23.783 ;
        RECT  121.2 2.137 121.32 23.783 ;
        RECT  115.8 2.137 115.92 23.783 ;
        RECT  110.4 2.137 110.52 23.783 ;
        RECT  105 2.137 105.12 23.783 ;
        RECT  99.6 2.137 99.72 23.783 ;
        RECT  94.2 2.137 94.32 23.783 ;
        RECT  88.8 2.137 88.92 23.783 ;
        RECT  83.4 2.137 83.52 23.783 ;
        RECT  78 2.137 78.12 23.783 ;
        RECT  72.6 2.137 72.72 23.783 ;
        RECT  67.2 2.137 67.32 23.783 ;
        RECT  61.8 2.137 61.92 23.783 ;
        RECT  56.4 2.137 56.52 23.783 ;
        RECT  51 2.137 51.12 23.783 ;
        RECT  45.6 2.137 45.72 23.783 ;
        RECT  40.2 2.137 40.32 23.783 ;
        RECT  34.8 2.137 34.92 23.783 ;
        RECT  29.4 2.137 29.52 23.783 ;
        RECT  24 2.137 24.12 23.783 ;
        RECT  18.6 2.137 18.72 23.783 ;
        RECT  13.2 2.137 13.32 23.783 ;
        RECT  7.8 2.137 7.92 23.783 ;
        RECT  2.4 2.137 2.52 23.783 ;
    END
  END VSS
  OBS
    LAYER RVTN ;
     RECT  2.16 2.16 141.696 2.295 ;
     RECT  2.16 2.565 141.696 2.835 ;
     RECT  2.16 3.105 141.696 3.375 ;
     RECT  2.16 3.645 141.696 3.915 ;
     RECT  2.16 4.185 141.696 4.455 ;
     RECT  2.16 4.725 141.696 4.995 ;
     RECT  2.16 5.265 141.696 5.535 ;
     RECT  2.16 5.805 141.696 6.075 ;
     RECT  2.16 6.345 141.696 6.615 ;
     RECT  2.16 6.885 141.696 7.155 ;
     RECT  2.16 7.425 141.696 7.695 ;
     RECT  2.16 7.965 141.696 8.235 ;
     RECT  2.16 8.505 141.696 8.775 ;
     RECT  2.16 9.045 141.696 9.315 ;
     RECT  2.16 9.585 141.696 9.855 ;
     RECT  2.16 10.125 141.696 10.395 ;
     RECT  2.16 10.665 141.696 10.935 ;
     RECT  2.16 11.205 141.696 11.475 ;
     RECT  2.16 11.745 141.696 12.015 ;
     RECT  2.16 12.285 141.696 12.555 ;
     RECT  2.16 12.825 141.696 13.095 ;
     RECT  2.16 13.365 141.696 13.635 ;
     RECT  2.16 13.905 141.696 14.175 ;
     RECT  2.16 14.445 141.696 14.715 ;
     RECT  2.16 14.985 141.696 15.255 ;
     RECT  2.16 15.525 141.696 15.795 ;
     RECT  2.16 16.065 141.696 16.335 ;
     RECT  2.16 16.605 141.696 16.875 ;
     RECT  2.16 17.145 141.696 17.415 ;
     RECT  2.16 17.685 141.696 17.955 ;
     RECT  2.16 18.225 141.696 18.495 ;
     RECT  2.16 18.765 141.696 19.035 ;
     RECT  2.16 19.305 141.696 19.575 ;
     RECT  2.16 19.845 141.696 20.115 ;
     RECT  2.16 20.385 141.696 20.655 ;
     RECT  2.16 20.925 141.696 21.195 ;
     RECT  2.16 21.465 141.696 21.735 ;
     RECT  2.16 22.005 141.696 22.275 ;
     RECT  2.16 22.545 141.696 22.815 ;
     RECT  2.16 23.085 141.696 23.355 ;
     RECT  2.16 23.625 141.696 23.76 ;
    LAYER RVTP ;
     RECT  2.16 2.295 141.696 2.565 ;
     RECT  2.16 2.835 141.696 3.105 ;
     RECT  2.16 3.375 141.696 3.645 ;
     RECT  2.16 3.915 141.696 4.185 ;
     RECT  2.16 4.455 141.696 4.725 ;
     RECT  2.16 4.995 141.696 5.265 ;
     RECT  2.16 5.535 141.696 5.805 ;
     RECT  2.16 6.075 141.696 6.345 ;
     RECT  2.16 6.615 141.696 6.885 ;
     RECT  2.16 7.155 141.696 7.425 ;
     RECT  2.16 7.695 141.696 7.965 ;
     RECT  2.16 8.235 141.696 8.505 ;
     RECT  2.16 8.775 141.696 9.045 ;
     RECT  2.16 9.315 141.696 9.585 ;
     RECT  2.16 9.855 141.696 10.125 ;
     RECT  2.16 10.395 141.696 10.665 ;
     RECT  2.16 10.935 141.696 11.205 ;
     RECT  2.16 11.475 141.696 11.745 ;
     RECT  2.16 12.015 141.696 12.285 ;
     RECT  2.16 12.555 141.696 12.825 ;
     RECT  2.16 13.095 141.696 13.365 ;
     RECT  2.16 13.635 141.696 13.905 ;
     RECT  2.16 14.175 141.696 14.445 ;
     RECT  2.16 14.715 141.696 14.985 ;
     RECT  2.16 15.255 141.696 15.525 ;
     RECT  2.16 15.795 141.696 16.065 ;
     RECT  2.16 16.335 141.696 16.605 ;
     RECT  2.16 16.875 141.696 17.145 ;
     RECT  2.16 17.415 141.696 17.685 ;
     RECT  2.16 17.955 141.696 18.225 ;
     RECT  2.16 18.495 141.696 18.765 ;
     RECT  2.16 19.035 141.696 19.305 ;
     RECT  2.16 19.575 141.696 19.845 ;
     RECT  2.16 20.115 141.696 20.385 ;
     RECT  2.16 20.655 141.696 20.925 ;
     RECT  2.16 21.195 141.696 21.465 ;
     RECT  2.16 21.735 141.696 22.005 ;
     RECT  2.16 22.275 141.696 22.545 ;
     RECT  2.16 22.815 141.696 23.085 ;
     RECT  2.16 23.355 141.696 23.625 ;
    LAYER M1 ;
     RECT  2.16 2.151 141.696 23.769 ;
    LAYER M2 ;
     RECT  0.967 2.196 1.903 2.214 ;
     RECT  1.183 3.114 1.903 3.132 ;
     RECT  1.903 2.196 2.16 3.132 ;
     RECT  2.155 4.158 2.16 4.176 ;
     RECT  1.687 22.59 2.16 22.608 ;
     RECT  2.16 2.151 2.227 23.769 ;
     RECT  2.227 2.106 2.407 23.769 ;
     RECT  2.407 2.07 3.515 23.769 ;
     RECT  3.515 2.106 3.803 23.769 ;
     RECT  3.803 2.151 4.675 23.769 ;
     RECT  4.675 2.106 5.747 23.769 ;
     RECT  5.747 2.151 6.547 23.769 ;
     RECT  6.547 2.106 7.079 23.769 ;
     RECT  7.079 2.151 10.111 23.769 ;
     RECT  10.111 2.106 10.535 23.769 ;
     RECT  10.535 2.151 11.731 23.769 ;
     RECT  11.731 2.106 13.379 23.769 ;
     RECT  13.379 2.151 15.187 23.769 ;
     RECT  15.187 2.106 16.871 23.769 ;
     RECT  16.871 2.151 17.635 23.769 ;
     RECT  17.635 2.106 18.535 23.769 ;
     RECT  18.535 2.106 18.635 23.85 ;
     RECT  18.635 2.106 19.715 23.769 ;
     RECT  19.715 2.151 21.235 23.769 ;
     RECT  21.235 2.106 22.207 23.769 ;
     RECT  22.207 2.034 22.847 23.769 ;
     RECT  22.847 2.106 25.403 23.769 ;
     RECT  25.403 2.151 27.283 23.769 ;
     RECT  27.283 2.106 29.155 23.769 ;
     RECT  29.155 2.034 29.615 23.769 ;
     RECT  29.615 2.106 29.831 23.769 ;
     RECT  29.831 2.151 34.663 23.769 ;
     RECT  34.663 2.106 35.591 23.769 ;
     RECT  35.591 2.151 37.543 23.769 ;
     RECT  37.543 2.106 38.839 23.769 ;
     RECT  38.839 2.034 40.919 23.769 ;
     RECT  40.919 2.106 41.423 23.769 ;
     RECT  41.423 2.151 42.367 23.769 ;
     RECT  42.367 2.106 43.043 23.769 ;
     RECT  43.043 2.151 45.175 23.769 ;
     RECT  45.175 2.151 45.535 23.814 ;
     RECT  45.535 2.106 46.283 23.814 ;
     RECT  46.283 2.106 48.227 23.769 ;
     RECT  48.227 2.151 49.927 23.769 ;
     RECT  49.927 2.106 50.467 23.769 ;
     RECT  50.467 2.034 50.819 23.769 ;
     RECT  50.819 2.106 51.539 23.769 ;
     RECT  51.539 2.151 52.951 23.769 ;
     RECT  52.951 2.106 53.023 23.769 ;
     RECT  53.023 2.07 53.375 23.769 ;
     RECT  53.375 2.106 54.491 23.769 ;
     RECT  54.491 2.151 58.531 23.769 ;
     RECT  58.531 2.106 60.179 23.769 ;
     RECT  60.179 2.151 62.275 23.769 ;
     RECT  62.275 2.106 62.555 23.769 ;
     RECT  62.555 2.151 64.291 23.769 ;
     RECT  64.291 2.106 65.255 23.769 ;
     RECT  65.255 2.151 67.171 23.769 ;
     RECT  67.171 2.106 67.415 23.769 ;
     RECT  67.415 2.151 72.895 23.769 ;
     RECT  72.895 2.106 73.463 23.769 ;
     RECT  73.463 2.151 77.611 23.769 ;
     RECT  77.611 2.106 77.863 23.769 ;
     RECT  77.863 2.034 78.791 23.769 ;
     RECT  80.095 1.152 80.195 1.17 ;
     RECT  78.791 2.151 83.623 23.769 ;
     RECT  85.567 1.152 85.667 1.17 ;
     RECT  83.623 2.106 85.739 23.769 ;
     RECT  85.739 2.151 87.763 23.769 ;
     RECT  87.763 2.106 88.151 23.769 ;
     RECT  88.151 2.151 89.815 23.769 ;
     RECT  89.815 2.106 90.527 23.769 ;
     RECT  90.527 2.151 92.839 23.769 ;
     RECT  92.839 2.106 93.155 23.769 ;
     RECT  93.155 2.151 95.503 23.769 ;
     RECT  95.503 2.034 96.323 23.769 ;
     RECT  96.323 2.151 98.131 23.769 ;
     RECT  98.131 2.106 100.939 23.769 ;
     RECT  100.939 2.034 101.435 23.769 ;
     RECT  101.435 2.151 105.151 23.769 ;
     RECT  105.151 2.106 105.755 23.769 ;
     RECT  105.755 2.151 107.671 23.769 ;
     RECT  107.671 2.106 108.167 23.769 ;
     RECT  108.167 2.151 109.111 23.769 ;
     RECT  109.471 1.152 109.571 1.17 ;
     RECT  109.111 2.106 109.859 23.769 ;
     RECT  109.859 2.151 112.711 23.769 ;
     RECT  112.711 2.106 114.287 23.769 ;
     RECT  115.015 1.152 115.151 1.17 ;
     RECT  114.287 2.151 117.211 23.769 ;
     RECT  117.211 2.106 118.283 23.769 ;
     RECT  118.283 2.151 119.659 23.769 ;
     RECT  119.659 2.106 120.551 23.769 ;
     RECT  120.551 2.151 121.387 23.769 ;
     RECT  121.387 2.106 121.495 23.769 ;
     RECT  121.495 2.034 121.919 23.769 ;
     RECT  121.919 2.151 122.647 23.769 ;
     RECT  122.647 2.106 123.503 23.769 ;
     RECT  123.503 2.151 124.303 23.769 ;
     RECT  124.303 2.106 124.655 23.769 ;
     RECT  124.655 2.151 125.527 23.769 ;
     RECT  125.527 2.034 126.275 23.769 ;
     RECT  126.275 2.106 126.815 23.769 ;
     RECT  126.815 2.151 129.343 23.769 ;
     RECT  129.343 2.106 130.919 23.769 ;
     RECT  130.919 2.151 137.659 23.769 ;
     RECT  137.659 2.106 138.299 23.769 ;
     RECT  138.299 2.151 141.259 23.769 ;
     RECT  141.259 2.106 141.575 23.769 ;
     RECT  141.575 2.151 141.696 23.769 ;
     RECT  141.696 4.896 141.719 5.904 ;
     RECT  141.696 6.822 141.719 6.84 ;
     RECT  141.719 5.886 141.755 5.904 ;
     RECT  141.696 9.792 141.755 9.81 ;
     RECT  141.696 2.376 141.791 3.168 ;
     RECT  141.696 8.136 141.791 8.154 ;
     RECT  141.791 2.376 141.971 2.754 ;
     RECT  141.696 21.24 141.971 21.528 ;
     RECT  141.696 19.926 142.115 19.944 ;
     RECT  141.719 4.896 142.331 4.914 ;
     RECT  141.696 22.554 142.331 22.572 ;
     RECT  141.971 2.736 142.475 2.754 ;
     RECT  141.971 21.51 142.511 21.528 ;
    LAYER M3 ;
     RECT  2.376 0.091 2.394 0.139 ;
     RECT  8.172 0.091 8.19 0.139 ;
     RECT  21.132 0.091 21.69 0.139 ;
     RECT  25.128 0.091 25.146 0.139 ;
     RECT  26.064 0.091 26.406 0.139 ;
     RECT  32.436 0.091 32.454 0.139 ;
     RECT  33.516 0.091 34.722 0.139 ;
     RECT  42.984 0.091 43.002 0.139 ;
     RECT  71.352 0.091 71.37 0.139 ;
     RECT  81.468 0.091 81.486 0.139 ;
     RECT  84.672 0.091 84.69 0.139 ;
     RECT  85.896 0.091 85.914 0.139 ;
     RECT  92.484 0.091 92.502 0.139 ;
     RECT  98.388 0.091 98.406 0.139 ;
     RECT  101.124 0.091 101.142 0.139 ;
     RECT  102.06 0.091 102.798 0.139 ;
     RECT  106.812 0.091 106.83 0.139 ;
     RECT  119.268 0.091 119.286 0.139 ;
     RECT  120.168 0.091 120.186 0.139 ;
     RECT  121.176 0.091 121.194 0.139 ;
     RECT  123.336 0.091 124.506 0.139 ;
     RECT  136.476 0.091 137.106 0.139 ;
     RECT  138.924 0.091 138.942 0.139 ;
     RECT  139.788 0.091 139.95 0.139 ;
     RECT  25.128 0.139 26.406 0.187 ;
     RECT  70.848 0.139 71.37 0.187 ;
     RECT  100.116 0.091 100.134 0.475 ;
     RECT  21.132 0.139 21.87 0.523 ;
     RECT  22.68 0.091 23.778 0.523 ;
     RECT  64.728 0.091 66.654 0.523 ;
     RECT  67.824 0.091 67.842 0.523 ;
     RECT  117.18 0.091 118.206 0.523 ;
     RECT  119.268 0.139 121.194 0.523 ;
     RECT  125.82 0.091 125.838 0.523 ;
     RECT  126.972 0.091 128.358 0.523 ;
     RECT  2.376 0.139 2.934 0.571 ;
     RECT  7.596 0.139 8.19 0.571 ;
     RECT  15.84 0.091 15.858 0.571 ;
     RECT  16.956 0.091 16.974 0.571 ;
     RECT  32.436 0.139 34.722 0.571 ;
     RECT  48.6 0.091 48.618 0.571 ;
     RECT  77.4 0.091 77.418 0.571 ;
     RECT  81.324 0.139 81.486 0.571 ;
     RECT  82.44 0.091 82.458 0.571 ;
     RECT  88.776 0.091 88.794 0.571 ;
     RECT  89.892 0.091 89.91 0.571 ;
     RECT  129.096 0.091 129.114 0.571 ;
     RECT  129.852 0.091 129.87 0.571 ;
     RECT  136.476 0.139 137.214 0.571 ;
     RECT  138.924 0.139 139.95 0.571 ;
     RECT  140.94 0.091 140.958 0.571 ;
     RECT  142.308 0.091 142.326 0.571 ;
     RECT  50.256 0.523 50.274 1.099 ;
     RECT  51.156 0.091 51.174 1.099 ;
     RECT  52.308 0.091 52.326 1.099 ;
     RECT  64.728 0.523 67.842 1.099 ;
     RECT  97.344 0.091 97.362 1.099 ;
     RECT  17.892 0.091 17.91 1.147 ;
     RECT  52.308 1.099 52.47 1.147 ;
     RECT  53.928 0.091 53.946 1.147 ;
     RECT  70.848 0.187 71.514 1.147 ;
     RECT  72.576 0.091 72.594 1.147 ;
     RECT  80.1 0.091 80.118 1.147 ;
     RECT  109.476 0.091 109.494 1.147 ;
     RECT  112.536 0.091 112.554 1.147 ;
     RECT  115.02 0.091 115.038 1.147 ;
     RECT  138.924 0.571 141.57 1.147 ;
     RECT  142.308 0.571 142.47 1.147 ;
     RECT  53.928 1.147 54.594 1.195 ;
     RECT  36.216 0.091 36.558 1.675 ;
     RECT  59.76 0.091 60.426 1.675 ;
     RECT  111.06 0.571 111.222 1.675 ;
     RECT  2.376 0.571 2.97 1.723 ;
     RECT  4.86 1.147 4.878 1.723 ;
     RECT  7.272 0.571 8.19 1.723 ;
     RECT  10.152 0.571 10.17 1.723 ;
     RECT  12.24 0.091 12.762 1.723 ;
     RECT  13.644 0.091 13.662 1.723 ;
     RECT  15.12 0.571 16.974 1.723 ;
     RECT  17.892 1.147 18.342 1.723 ;
     RECT  19.548 1.147 19.566 1.723 ;
     RECT  21.132 0.523 23.778 1.723 ;
     RECT  25.128 0.187 26.442 1.723 ;
     RECT  27.684 0.091 27.702 1.723 ;
     RECT  32.436 0.571 35.37 1.723 ;
     RECT  36.216 1.675 37.17 1.723 ;
     RECT  39.096 0.091 39.114 1.723 ;
     RECT  40.104 0.571 40.122 1.723 ;
     RECT  41.148 0.091 41.166 1.723 ;
     RECT  42.012 1.147 42.03 1.723 ;
     RECT  42.984 0.139 43.254 1.723 ;
     RECT  44.28 0.091 44.298 1.723 ;
     RECT  45.504 0.091 46.782 1.723 ;
     RECT  47.736 0.091 47.754 1.723 ;
     RECT  48.6 0.571 48.942 1.723 ;
     RECT  50.256 1.099 51.174 1.723 ;
     RECT  51.948 1.147 52.47 1.723 ;
     RECT  53.928 1.195 54.666 1.723 ;
     RECT  56.916 0.091 56.934 1.723 ;
     RECT  58.968 0.091 58.986 1.723 ;
     RECT  59.76 1.675 60.57 1.723 ;
     RECT  61.956 0.091 62.334 1.723 ;
     RECT  63.108 0.091 63.738 1.723 ;
     RECT  64.728 1.099 68.346 1.723 ;
     RECT  69.336 1.675 69.354 1.723 ;
     RECT  70.848 1.147 72.594 1.723 ;
     RECT  73.368 1.147 73.386 1.723 ;
     RECT  75.564 0.571 75.582 1.723 ;
     RECT  76.464 0.091 76.482 1.723 ;
     RECT  77.4 0.571 77.742 1.723 ;
     RECT  80.1 1.147 80.19 1.723 ;
     RECT  81.324 0.571 82.458 1.723 ;
     RECT  84.24 0.139 84.69 1.723 ;
     RECT  85.572 0.139 85.914 1.723 ;
     RECT  87.192 0.091 87.21 1.723 ;
     RECT  88.776 0.571 89.91 1.723 ;
     RECT  91.188 0.091 91.206 1.723 ;
     RECT  92.484 0.139 92.826 1.723 ;
     RECT  95.076 0.523 95.094 1.723 ;
     RECT  96.012 0.091 96.03 1.723 ;
     RECT  96.912 1.099 97.362 1.723 ;
     RECT  98.316 0.139 98.406 1.723 ;
     RECT  99.54 0.475 100.134 1.723 ;
     RECT  101.124 0.139 102.798 1.723 ;
     RECT  104.436 0.523 104.454 1.723 ;
     RECT  106.308 0.139 106.83 1.723 ;
     RECT  108.108 0.091 108.126 1.723 ;
     RECT  109.476 1.147 109.566 1.723 ;
     RECT  110.556 1.675 111.222 1.723 ;
     RECT  112.536 1.147 112.842 1.723 ;
     RECT  113.688 0.091 113.706 1.723 ;
     RECT  115.02 1.147 115.146 1.723 ;
     RECT  116.784 0.523 121.194 1.723 ;
     RECT  123.228 0.139 124.506 1.723 ;
     RECT  125.82 0.523 128.358 1.723 ;
     RECT  129.096 0.571 129.87 1.723 ;
     RECT  131.148 0.091 131.382 1.723 ;
     RECT  132.156 0.571 132.174 1.723 ;
     RECT  135.972 0.571 137.214 1.723 ;
     RECT  137.952 0.571 137.97 1.723 ;
     RECT  138.924 1.147 142.47 1.723 ;
     RECT  1.908 1.723 2.97 1.771 ;
     RECT  4.104 1.723 10.242 1.771 ;
     RECT  11.412 1.723 19.926 1.771 ;
     RECT  42.012 1.723 102.978 1.771 ;
     RECT  103.716 1.723 105.354 1.771 ;
     RECT  106.308 1.723 106.974 1.771 ;
     RECT  107.712 1.723 113.994 1.771 ;
     RECT  1.908 1.771 19.998 1.819 ;
     RECT  21.096 1.723 41.166 1.819 ;
     RECT  1.908 1.819 41.166 2.101 ;
     RECT  42.012 1.771 105.426 2.101 ;
     RECT  106.308 1.771 113.994 2.101 ;
     RECT  1.908 2.101 114.282 2.155 ;
     RECT  115.02 1.723 142.47 2.155 ;
     RECT  0.972 1.723 0.99 2.219 ;
     RECT  1.908 2.155 142.47 2.597 ;
     RECT  2.052 2.597 142.47 2.669 ;
     RECT  2.16 2.669 142.47 2.759 ;
     RECT  1.188 2.875 1.206 3.137 ;
     RECT  2.16 2.759 142.326 4.181 ;
     RECT  2.196 4.181 142.326 4.919 ;
     RECT  2.196 4.919 141.786 7.079 ;
     RECT  45 7.079 141.786 7.259 ;
     RECT  2.196 7.079 44.118 7.799 ;
     RECT  45.036 7.259 141.786 8.159 ;
     RECT  2.376 7.799 44.118 8.509 ;
     RECT  2.376 8.509 44.154 8.581 ;
     RECT  45.036 8.159 141.75 8.581 ;
     RECT  2.376 8.581 141.75 8.969 ;
     RECT  70.128 8.969 112.914 9.239 ;
     RECT  2.376 8.969 52.866 9.355 ;
     RECT  113.652 8.969 141.75 9.815 ;
     RECT  113.652 9.815 141.642 10.049 ;
     RECT  113.652 10.049 141.57 12.209 ;
     RECT  70.128 9.239 82.494 12.281 ;
     RECT  70.2 12.281 82.494 12.451 ;
     RECT  83.232 9.239 112.914 12.451 ;
     RECT  2.34 9.355 52.866 12.479 ;
     RECT  70.2 12.451 112.914 12.551 ;
     RECT  23.4 12.479 52.866 12.559 ;
     RECT  53.604 8.969 69.138 12.559 ;
     RECT  23.4 12.559 69.138 12.721 ;
     RECT  23.4 12.721 69.282 12.749 ;
     RECT  104.688 12.551 112.914 12.901 ;
     RECT  113.652 12.209 141.498 12.901 ;
     RECT  50.724 12.749 69.282 12.929 ;
     RECT  104.688 12.901 141.498 13.063 ;
     RECT  104.688 13.063 141.534 13.261 ;
     RECT  23.4 12.749 49.914 13.289 ;
     RECT  70.2 12.551 103.95 13.289 ;
     RECT  104.688 13.261 141.57 13.289 ;
     RECT  70.2 13.289 85.77 13.441 ;
     RECT  86.544 13.289 103.95 13.531 ;
     RECT  104.688 13.289 136.638 13.531 ;
     RECT  57.888 12.929 69.282 13.559 ;
     RECT  86.544 13.531 136.638 13.559 ;
     RECT  57.888 13.559 60.75 13.631 ;
     RECT  70.128 13.441 85.77 13.631 ;
     RECT  23.472 13.289 49.914 13.639 ;
     RECT  50.724 12.929 57.078 13.639 ;
     RECT  2.34 12.479 22.662 13.667 ;
     RECT  2.34 13.667 10.782 13.901 ;
     RECT  57.888 13.631 58.374 13.901 ;
     RECT  61.56 13.559 69.282 14.881 ;
     RECT  137.376 13.289 141.57 16.529 ;
     RECT  23.472 13.639 57.078 16.843 ;
     RECT  57.96 13.901 58.374 16.843 ;
     RECT  124.308 13.559 136.638 16.951 ;
     RECT  23.472 16.843 58.374 16.973 ;
     RECT  11.628 13.667 22.662 17.069 ;
     RECT  23.472 16.973 36.882 17.077 ;
     RECT  124.272 16.951 136.638 17.113 ;
     RECT  137.376 16.529 141.534 17.113 ;
     RECT  2.415 13.901 10.782 17.149 ;
     RECT  37.62 16.973 58.374 17.185 ;
     RECT  59.292 13.631 60.75 17.185 ;
     RECT  86.544 13.559 123.534 17.339 ;
     RECT  102.636 17.339 123.534 17.383 ;
     RECT  124.272 17.113 141.534 17.383 ;
     RECT  2.415 17.149 10.818 17.419 ;
     RECT  11.628 17.069 22.626 17.419 ;
     RECT  37.62 17.185 60.75 17.447 ;
     RECT  45.288 17.447 60.75 17.455 ;
     RECT  61.56 14.881 69.354 17.455 ;
     RECT  70.128 13.631 85.59 17.455 ;
     RECT  86.544 17.339 96.57 17.455 ;
     RECT  45.288 17.455 85.59 17.651 ;
     RECT  60.552 17.651 85.59 17.653 ;
     RECT  86.472 17.455 96.57 17.653 ;
     RECT  60.552 17.653 96.57 17.717 ;
     RECT  45.288 17.651 59.778 17.879 ;
     RECT  102.636 17.383 141.534 17.879 ;
     RECT  2.415 17.419 22.626 17.995 ;
     RECT  23.364 17.077 36.882 17.995 ;
     RECT  37.62 17.447 44.55 17.995 ;
     RECT  118.044 17.879 141.534 17.995 ;
     RECT  2.415 17.995 44.55 18.121 ;
     RECT  45.288 17.879 59.742 18.149 ;
     RECT  102.636 17.879 117.27 18.149 ;
     RECT  2.376 18.121 44.55 18.193 ;
     RECT  45.288 18.149 52.11 18.193 ;
     RECT  60.624 17.717 96.57 18.193 ;
     RECT  97.308 17.339 101.898 18.193 ;
     RECT  102.636 18.149 117.234 18.221 ;
     RECT  60.624 18.193 101.898 18.227 ;
     RECT  2.376 18.193 52.11 18.419 ;
     RECT  118.044 17.995 141.57 18.419 ;
     RECT  52.848 18.149 59.742 18.763 ;
     RECT  2.376 18.419 30.33 19.075 ;
     RECT  52.848 18.763 59.85 19.229 ;
     RECT  64.872 18.227 101.898 19.229 ;
     RECT  104.832 18.221 117.234 19.345 ;
     RECT  59.472 19.229 59.85 19.381 ;
     RECT  60.624 18.227 64.098 19.381 ;
     RECT  69.156 19.229 101.898 19.381 ;
     RECT  102.636 18.221 104.058 19.381 ;
     RECT  2.34 19.075 30.33 19.387 ;
     RECT  31.14 18.419 52.11 19.387 ;
     RECT  52.848 19.229 58.734 19.387 ;
     RECT  69.156 19.381 104.058 19.771 ;
     RECT  104.832 19.345 117.306 19.771 ;
     RECT  59.472 19.381 64.098 19.921 ;
     RECT  64.872 19.229 68.418 19.921 ;
     RECT  118.044 18.419 141.534 19.921 ;
     RECT  2.34 19.387 58.734 20.011 ;
     RECT  69.156 19.771 117.306 20.083 ;
     RECT  118.044 19.921 142.11 20.083 ;
     RECT  59.472 19.921 68.418 20.152 ;
     RECT  69.156 20.083 142.11 20.152 ;
     RECT  2.268 20.011 58.734 20.191 ;
     RECT  59.472 20.152 142.11 20.191 ;
     RECT  2.268 20.191 142.11 20.309 ;
     RECT  2.268 20.309 141.354 20.893 ;
     RECT  2.232 20.893 141.354 21.127 ;
     RECT  142.092 20.309 142.11 21.127 ;
     RECT  2.232 21.127 142.11 21.505 ;
     RECT  2.232 21.505 142.506 22.585 ;
     RECT  1.692 22.585 142.506 22.637 ;
     RECT  2.304 22.637 142.506 23.549 ;
     RECT  71.136 23.549 75.654 23.585 ;
     RECT  102.852 23.549 105.462 23.585 ;
     RECT  114.084 23.549 142.506 23.585 ;
     RECT  10.8 23.549 30.258 23.621 ;
     RECT  58.068 23.549 62.226 23.621 ;
     RECT  84.816 23.549 102.078 23.621 ;
     RECT  106.272 23.549 107.766 23.621 ;
     RECT  108.648 23.549 112.878 23.621 ;
     RECT  114.624 23.585 142.506 23.621 ;
     RECT  58.068 23.621 58.662 23.693 ;
     RECT  71.136 23.585 72.954 23.693 ;
     RECT  114.624 23.621 136.206 23.693 ;
     RECT  2.304 23.549 9.99 23.729 ;
     RECT  10.8 23.621 30.186 23.729 ;
     RECT  31.068 23.549 53.262 23.729 ;
     RECT  63.864 23.549 64.89 23.729 ;
     RECT  66.132 23.549 68.49 23.729 ;
     RECT  73.692 23.585 75.654 23.729 ;
     RECT  77.364 23.549 84.006 23.729 ;
     RECT  102.852 23.585 105.354 23.729 ;
     RECT  106.272 23.621 107.73 23.729 ;
     RECT  114.624 23.693 132.282 23.729 ;
     RECT  133.056 23.693 136.206 23.729 ;
     RECT  31.068 23.729 53.01 23.741 ;
     RECT  69.3 23.549 70.146 23.741 ;
     RECT  107.388 23.729 107.73 23.741 ;
     RECT  23.292 23.729 30.186 23.777 ;
     RECT  54.072 23.549 56.505 23.777 ;
     RECT  10.8 23.729 21.078 23.837 ;
     RECT  2.304 23.729 3.762 23.885 ;
     RECT  10.8 23.837 21.042 23.885 ;
     RECT  24.156 23.777 30.186 23.885 ;
     RECT  31.068 23.741 46.71 23.885 ;
     RECT  66.132 23.729 68.346 23.885 ;
     RECT  71.532 23.693 72.954 23.885 ;
     RECT  84.816 23.621 101.718 23.885 ;
     RECT  108.648 23.621 109.026 23.885 ;
     RECT  114.624 23.729 132.174 23.885 ;
     RECT  2.808 23.885 3.762 23.933 ;
     RECT  4.536 23.729 9.99 23.933 ;
     RECT  10.8 23.885 16.506 23.933 ;
     RECT  17.568 23.885 21.042 23.933 ;
     RECT  24.336 23.885 30.186 23.933 ;
     RECT  31.068 23.885 44.226 23.933 ;
     RECT  45 23.885 45.558 23.933 ;
     RECT  46.548 23.885 46.71 23.933 ;
     RECT  47.664 23.741 53.01 23.933 ;
     RECT  54.072 23.777 56.394 23.933 ;
     RECT  59.436 23.621 62.118 23.933 ;
     RECT  64.08 23.729 64.89 23.933 ;
     RECT  66.132 23.885 67.158 23.933 ;
     RECT  69.3 23.741 69.318 23.933 ;
     RECT  71.532 23.885 72.558 23.933 ;
     RECT  73.692 23.729 74.502 23.933 ;
     RECT  77.364 23.729 82.062 23.933 ;
     RECT  82.98 23.729 84.006 23.933 ;
     RECT  84.816 23.885 86.058 23.933 ;
     RECT  86.796 23.885 101.718 23.933 ;
     RECT  104.976 23.729 105.354 23.933 ;
     RECT  107.388 23.741 107.406 23.933 ;
     RECT  109.764 23.621 112.77 23.933 ;
     RECT  114.624 23.885 127.638 23.933 ;
     RECT  128.7 23.885 132.174 23.933 ;
     RECT  133.308 23.729 136.206 23.933 ;
     RECT  136.98 23.621 142.506 23.933 ;
     RECT  3.456 23.933 3.474 23.981 ;
     RECT  7.776 23.933 8.478 23.981 ;
     RECT  9.72 23.933 9.774 23.981 ;
     RECT  24.876 23.933 25.578 23.981 ;
     RECT  34.704 23.933 34.722 23.981 ;
     RECT  39.888 23.933 40.374 23.981 ;
     RECT  66.6 23.933 67.158 23.981 ;
     RECT  72.36 23.933 72.378 23.981 ;
     RECT  73.908 23.933 74.502 23.981 ;
     RECT  88.524 23.933 88.794 23.981 ;
     RECT  91.512 23.933 91.53 23.981 ;
     RECT  102.852 23.729 104.238 23.981 ;
     RECT  128.7 23.933 128.718 23.981 ;
     RECT  131.976 23.933 132.174 23.981 ;
     RECT  137.844 23.933 137.862 23.981 ;
     RECT  138.996 23.933 139.014 23.981 ;
     RECT  43.2 23.933 43.218 24.029 ;
     RECT  56.34 23.933 56.358 24.029 ;
     RECT  35.676 23.933 35.694 24.509 ;
     RECT  131.976 23.981 131.994 24.509 ;
     RECT  6.768 23.933 6.786 24.557 ;
     RECT  15.948 23.933 15.966 24.557 ;
     RECT  19.404 23.933 19.422 24.557 ;
     RECT  23.292 23.777 23.31 24.557 ;
     RECT  25.164 23.981 25.578 24.557 ;
     RECT  27.216 23.933 27.234 24.557 ;
     RECT  38.736 23.933 38.754 24.557 ;
     RECT  48.348 23.933 49.014 24.557 ;
     RECT  51.588 23.933 52.254 24.557 ;
     RECT  58.068 23.693 58.626 24.557 ;
     RECT  60.264 23.933 61.506 24.557 ;
     RECT  96.228 23.933 96.246 24.557 ;
     RECT  97.272 23.933 97.578 24.557 ;
     RECT  110.556 23.933 110.574 24.557 ;
     RECT  117.828 23.933 118.098 24.557 ;
     RECT  122.436 23.933 122.454 24.557 ;
     RECT  123.588 23.933 124.146 24.557 ;
     RECT  140.508 23.933 140.814 24.557 ;
     RECT  39.888 23.981 39.906 25.085 ;
     RECT  48.996 24.557 49.014 25.085 ;
     RECT  51.66 24.557 52.002 25.085 ;
     RECT  70.128 23.741 70.146 25.085 ;
     RECT  73.908 23.981 73.926 25.085 ;
     RECT  75.636 23.729 75.654 25.085 ;
     RECT  92.88 23.933 92.898 25.085 ;
     RECT  100.98 23.933 100.998 25.085 ;
     RECT  106.272 23.729 106.542 25.085 ;
     RECT  115.056 23.933 115.074 25.085 ;
     RECT  130.716 23.933 130.842 25.085 ;
     RECT  71.532 23.933 71.55 25.099 ;
     RECT  15.156 23.933 15.174 25.133 ;
     RECT  22.176 23.729 22.446 25.133 ;
     RECT  28.404 23.933 28.926 25.133 ;
     RECT  32.4 23.933 32.418 25.133 ;
     RECT  46.548 23.933 46.566 25.133 ;
     RECT  54.072 23.933 54.09 25.133 ;
     RECT  58.068 24.557 58.086 25.133 ;
     RECT  60.876 24.557 60.894 25.133 ;
     RECT  64.872 23.933 64.89 25.133 ;
     RECT  68.328 23.885 68.346 25.133 ;
     RECT  83.988 23.933 84.006 25.133 ;
     RECT  85.896 23.933 85.914 25.133 ;
     RECT  88.524 23.981 88.542 25.133 ;
     RECT  102.852 23.981 102.942 25.133 ;
     RECT  104.22 23.981 104.238 25.133 ;
     RECT  106.272 25.085 106.47 25.133 ;
     RECT  108.648 23.885 108.666 25.133 ;
     RECT  111.708 23.933 111.726 25.133 ;
     RECT  118.98 23.933 118.998 25.133 ;
     RECT  120.6 23.933 121.158 25.133 ;
     RECT  135.864 23.933 135.99 25.757 ;
     RECT  5.652 23.933 5.67 25.805 ;
     RECT  9.756 23.981 9.774 25.805 ;
     RECT  25.164 24.557 25.182 25.805 ;
     RECT  43.956 23.933 43.974 25.805 ;
     RECT  45.252 23.933 45.27 25.805 ;
     RECT  51.984 25.085 52.002 25.805 ;
     RECT  55.512 23.933 55.53 25.805 ;
     RECT  71.532 25.099 71.91 25.805 ;
     RECT  81.324 23.933 81.342 25.805 ;
     RECT  82.98 23.933 82.998 25.805 ;
     RECT  97.56 24.557 97.578 25.805 ;
     RECT  102.852 25.133 102.87 25.805 ;
     RECT  106.272 25.133 106.29 25.805 ;
     RECT  118.08 24.557 118.098 25.805 ;
     RECT  120.6 25.133 120.618 25.805 ;
     RECT  125.496 23.933 125.514 25.805 ;
     RECT  129.708 23.933 129.87 25.805 ;
     RECT  130.824 25.085 130.842 25.805 ;
     RECT  134.604 23.933 134.622 25.805 ;
     RECT  135.972 25.757 135.99 25.805 ;
     RECT  140.508 24.557 140.526 25.805 ;
     RECT  141.588 23.933 142.506 25.805 ;
     RECT  71.892 25.805 71.91 25.901 ;
    LAYER M4 ;
     RECT  0.037 4.416 0.757 4.44 ;
     RECT  0.565 21.552 0.757 21.576 ;
     RECT  0.037 22.752 0.757 22.776 ;
     RECT  0.565 1.776 0.917 1.8 ;
     RECT  0.757 21.552 0.949 22.776 ;
     RECT  0.229 20.16 1.141 20.184 ;
     RECT  0.949 21.408 1.141 22.776 ;
     RECT  1.141 2.88 1.228 2.904 ;
     RECT  0.757 3.984 1.285 4.44 ;
     RECT  0.229 0.096 1.477 0.12 ;
     RECT  1.477 0.096 1.669 0.168 ;
     RECT  0.421 23.856 1.861 23.88 ;
     RECT  1.285 3.984 2.293 4.728 ;
     RECT  0.421 5.712 2.365 5.736 ;
     RECT  2.293 7.104 2.365 7.128 ;
     RECT  1.141 20.16 2.365 22.776 ;
     RECT  1.669 0.096 2.405 0.6 ;
     RECT  0.917 1.728 2.408 1.8 ;
     RECT  2.293 3.072 2.408 4.728 ;
     RECT  2.365 5.712 2.408 6.12 ;
     RECT  2.365 7.104 2.408 7.752 ;
     RECT  2.365 18.144 2.408 18.168 ;
     RECT  2.365 20.112 2.408 22.776 ;
     RECT  1.861 23.856 2.408 23.928 ;
     RECT  2.293 25.776 2.435 25.8 ;
     RECT  2.408 1.728 2.704 23.928 ;
     RECT  2.405 0.144 2.945 0.6 ;
     RECT  2.945 0.576 2.981 0.6 ;
     RECT  2.704 1.728 3.161 9.144 ;
     RECT  2.533 25.728 3.251 25.752 ;
     RECT  2.704 18.096 3.404 23.928 ;
     RECT  3.161 1.728 3.449 7.992 ;
     RECT  3.449 1.728 3.484 3.96 ;
     RECT  3.404 18.096 3.491 23.976 ;
     RECT  3.491 18.096 3.817 23.928 ;
     RECT  3.817 18.096 3.971 21.816 ;
     RECT  3.161 8.976 4.097 9.144 ;
     RECT  2.704 16.512 4.163 17.112 ;
     RECT  3.971 18.384 4.205 21.816 ;
     RECT  3.817 22.8 4.205 23.928 ;
     RECT  4.093 14.832 4.241 14.856 ;
     RECT  3.484 1.728 4.421 3.432 ;
     RECT  4.421 3.408 4.453 3.432 ;
     RECT  3.449 5.04 4.453 7.992 ;
     RECT  4.205 19.104 4.529 21.816 ;
     RECT  4.453 3.408 4.54 7.992 ;
     RECT  4.163 17.088 4.601 17.112 ;
     RECT  4.421 1.728 4.673 2.28 ;
     RECT  4.54 5.04 4.673 7.992 ;
     RECT  4.673 1.728 4.693 1.896 ;
     RECT  4.205 23.376 4.739 23.928 ;
     RECT  4.529 20.16 4.745 21.816 ;
     RECT  4.097 8.976 4.853 9 ;
     RECT  4.693 1.152 4.889 1.896 ;
     RECT  4.745 21.072 4.957 21.816 ;
     RECT  4.673 5.04 5.033 7.656 ;
     RECT  5.033 5.088 5.105 7.656 ;
     RECT  4.889 1.728 5.123 1.896 ;
     RECT  4.739 23.76 5.149 23.928 ;
     RECT  4.957 21.072 5.401 21.96 ;
     RECT  5.123 1.728 5.465 1.8 ;
     RECT  3.973 25.776 5.681 25.8 ;
     RECT  5.401 21.936 5.789 21.96 ;
     RECT  4.54 3.408 5.857 3.432 ;
     RECT  5.105 5.184 5.933 7.656 ;
     RECT  4.529 19.104 5.941 19.128 ;
     RECT  5.857 3.408 6.133 3.96 ;
     RECT  5.149 23.856 6.133 23.928 ;
     RECT  6.073 22.752 6.185 22.776 ;
     RECT  5.933 5.184 6.193 6.888 ;
     RECT  5.941 19.104 6.217 19.512 ;
     RECT  6.217 19.104 6.361 20.328 ;
     RECT  6.361 18.816 6.397 20.328 ;
     RECT  6.397 18.816 6.401 20.568 ;
     RECT  6.133 23.808 6.433 23.928 ;
     RECT  5.465 1.728 6.497 1.752 ;
     RECT  6.133 2.88 6.649 3.96 ;
     RECT  6.433 23.376 6.757 23.928 ;
     RECT  6.401 18.816 6.833 19.08 ;
     RECT  6.497 1.728 6.853 1.8 ;
     RECT  6.649 2.88 6.865 4.056 ;
     RECT  6.193 5.184 6.865 6.264 ;
     RECT  6.757 23.376 6.899 24.552 ;
     RECT  7.045 0.576 7.237 0.6 ;
     RECT  7.237 0.096 7.301 0.6 ;
     RECT  6.865 2.88 7.477 6.264 ;
     RECT  7.153 7.344 7.477 7.368 ;
     RECT  7.477 2.88 7.613 7.368 ;
     RECT  7.541 8.544 7.613 8.568 ;
     RECT  6.853 1.728 7.808 1.848 ;
     RECT  7.613 2.88 7.808 8.568 ;
     RECT  6.833 19.056 7.808 19.08 ;
     RECT  6.401 20.064 7.808 20.568 ;
     RECT  6.397 21.648 7.808 21.672 ;
     RECT  6.899 23.376 7.808 23.976 ;
     RECT  7.808 1.728 8.104 23.976 ;
     RECT  7.301 0.096 8.201 0.168 ;
     RECT  8.104 18.768 8.243 20.328 ;
     RECT  8.243 18.768 8.281 20.04 ;
     RECT  8.104 3.984 8.345 7.368 ;
     RECT  8.201 0.144 8.387 0.168 ;
     RECT  8.281 19.056 8.417 20.04 ;
     RECT  8.104 22.464 8.453 23.976 ;
     RECT  8.345 4.128 8.489 7.368 ;
     RECT  8.453 23.376 8.489 23.976 ;
     RECT  8.104 1.728 8.569 2.28 ;
     RECT  8.417 19.248 9.457 20.04 ;
     RECT  9.277 3.024 9.461 3.048 ;
     RECT  8.569 1.728 9.541 1.8 ;
     RECT  8.489 23.376 9.709 23.928 ;
     RECT  9.637 21.648 9.721 21.672 ;
     RECT  8.489 4.128 9.788 6.6 ;
     RECT  9.349 25.776 9.82 25.8 ;
     RECT  9.541 1.728 9.857 2.184 ;
     RECT  9.788 4.128 9.875 7.032 ;
     RECT  9.457 19.248 9.925 20.088 ;
     RECT  9.875 4.128 10.069 6.312 ;
     RECT  9.709 23.376 10.115 23.976 ;
     RECT  9.733 0.576 10.181 0.6 ;
     RECT  10.069 3.936 10.451 6.312 ;
     RECT  9.925 19.248 10.453 20.76 ;
     RECT  10.393 8.544 10.477 8.568 ;
     RECT  10.412 17.472 10.499 17.496 ;
     RECT  10.453 18.864 10.645 20.76 ;
     RECT  10.645 18.192 10.729 20.76 ;
     RECT  10.115 23.376 10.793 23.928 ;
     RECT  10.729 18.816 11.005 20.76 ;
     RECT  10.451 4.512 11.009 6.312 ;
     RECT  11.009 4.512 11.267 5.208 ;
     RECT  9.857 1.728 11.365 1.944 ;
     RECT  11.365 1.728 11.585 2.184 ;
     RECT  11.66 17.376 11.701 17.4 ;
     RECT  11.005 18.816 11.701 21.096 ;
     RECT  11.701 17.376 11.747 21.096 ;
     RECT  10.793 23.424 11.761 23.928 ;
     RECT  11.747 18.192 11.869 21.096 ;
     RECT  11.267 4.512 11.905 4.68 ;
     RECT  11.869 18.192 11.909 21.72 ;
     RECT  11.905 3.984 11.977 4.68 ;
     RECT  11.009 6.24 11.989 6.312 ;
     RECT  11.977 3.936 12.035 4.68 ;
     RECT  12.035 3.936 12.061 4.008 ;
     RECT  11.909 21.648 13.052 21.72 ;
     RECT  11.989 5.712 13.057 6.312 ;
     RECT  12.061 3.984 13.093 4.008 ;
     RECT  13.057 5.712 13.093 6.6 ;
     RECT  11.585 1.728 13.208 1.8 ;
     RECT  13.093 3.312 13.208 4.728 ;
     RECT  13.093 5.712 13.208 6.84 ;
     RECT  11.909 18.192 13.208 20.568 ;
     RECT  13.052 21.648 13.208 22.152 ;
     RECT  11.761 23.376 13.208 23.928 ;
     RECT  13.093 25.728 13.379 25.752 ;
     RECT  13.208 1.728 13.504 23.928 ;
     RECT  12.229 0.096 13.673 0.12 ;
     RECT  13.504 18.816 13.853 23.928 ;
     RECT  13.504 17.472 13.907 17.64 ;
     RECT  13.853 18.816 13.997 21.72 ;
     RECT  13.997 21.12 14.033 21.72 ;
     RECT  13.853 22.752 14.177 23.928 ;
     RECT  13.504 1.728 14.249 2.28 ;
     RECT  14.033 21.12 14.357 21.24 ;
     RECT  13.907 17.616 14.473 17.64 ;
     RECT  13.997 18.816 14.753 20.136 ;
     RECT  14.177 23.376 14.819 23.928 ;
     RECT  14.773 0.096 14.917 0.12 ;
     RECT  14.917 0.096 15.149 0.6 ;
     RECT  14.753 18.816 15.253 19.128 ;
     RECT  14.249 1.728 15.301 1.8 ;
     RECT  14.569 4.512 15.325 4.536 ;
     RECT  13.504 6 15.325 6.84 ;
     RECT  14.357 21.216 15.349 21.24 ;
     RECT  14.753 20.112 15.505 20.136 ;
     RECT  15.349 21.12 15.505 21.24 ;
     RECT  15.301 1.728 15.581 2.184 ;
     RECT  15.581 1.728 15.637 1.8 ;
     RECT  15.145 25.104 15.683 25.128 ;
     RECT  15.253 18.192 15.781 19.128 ;
     RECT  15.505 20.112 15.781 21.24 ;
     RECT  14.819 23.808 15.788 23.928 ;
     RECT  15.637 1.152 15.905 1.8 ;
     RECT  15.788 23.376 15.937 23.928 ;
     RECT  15.781 18.192 15.973 21.24 ;
     RECT  15.937 23.376 16.067 24.552 ;
     RECT  15.149 0.096 16.357 0.12 ;
     RECT  15.325 4.512 16.357 6.84 ;
     RECT  16.357 0.096 16.445 0.6 ;
     RECT  15.973 18.192 16.657 21.624 ;
     RECT  16.657 18.144 16.849 21.624 ;
     RECT  16.357 3.936 17.017 6.84 ;
     RECT  17.017 3.936 17.237 6.888 ;
     RECT  16.067 23.376 17.315 23.928 ;
     RECT  16.849 18.816 17.341 21.624 ;
     RECT  17.276 17.616 17.363 17.64 ;
     RECT  17.341 18.816 17.411 21.672 ;
     RECT  17.411 19.968 17.485 21.672 ;
     RECT  17.237 3.936 17.489 6.552 ;
     RECT  15.905 1.728 17.585 1.8 ;
     RECT  17.737 3.312 17.797 3.336 ;
     RECT  16.445 0.096 17.921 0.12 ;
     RECT  17.585 1.728 17.989 1.896 ;
     RECT  17.797 2.88 17.989 3.336 ;
     RECT  17.411 18.816 18.085 18.84 ;
     RECT  17.989 1.728 18.313 3.336 ;
     RECT  18.085 18.24 18.38 18.84 ;
     RECT  18.313 1.152 18.397 3.336 ;
     RECT  18.38 18.192 18.469 18.84 ;
     RECT  17.485 19.968 18.469 21.96 ;
     RECT  18.397 1.728 18.608 3.336 ;
     RECT  17.489 4.512 18.608 6.552 ;
     RECT  18.044 17.088 18.608 17.112 ;
     RECT  18.469 18.192 18.608 21.96 ;
     RECT  17.315 23.856 18.608 23.928 ;
     RECT  18.608 1.728 18.904 23.928 ;
     RECT  18.904 17.088 19.091 21 ;
     RECT  18.904 23.376 19.091 23.928 ;
     RECT  19.091 17.472 19.235 21 ;
     RECT  19.091 23.856 19.393 23.928 ;
     RECT  18.904 1.728 19.429 2.856 ;
     RECT  19.235 18.24 19.505 21 ;
     RECT  19.429 1.152 19.577 2.856 ;
     RECT  18.904 4.512 19.829 6.552 ;
     RECT  19.829 4.512 19.897 4.536 ;
     RECT  19.577 1.728 19.973 2.856 ;
     RECT  19.393 23.856 20.003 24.552 ;
     RECT  20.003 23.856 20.252 23.928 ;
     RECT  20.3 17.088 20.387 17.112 ;
     RECT  19.505 18.816 20.437 21 ;
     RECT  19.829 5.712 20.585 6.552 ;
     RECT  20.437 18.816 20.585 21.672 ;
     RECT  19.973 1.728 20.837 2.76 ;
     RECT  20.869 0.096 21.013 0.12 ;
     RECT  19.897 3.936 21.017 4.536 ;
     RECT  20.252 23.376 21.049 23.928 ;
     RECT  21.049 22.848 21.053 23.928 ;
     RECT  21.053 22.848 21.089 23.832 ;
     RECT  21.089 22.848 21.341 23.448 ;
     RECT  20.585 5.712 21.481 6.024 ;
     RECT  21.308 17.616 21.529 17.64 ;
     RECT  20.837 1.728 21.845 2.184 ;
     RECT  21.481 5.088 21.881 6.024 ;
     RECT  21.881 5.712 21.949 6.024 ;
     RECT  20.585 19.392 21.949 21.672 ;
     RECT  21.341 23.376 21.971 23.448 ;
     RECT  21.949 5.712 21.985 6.6 ;
     RECT  21.949 18.768 22.033 21.672 ;
     RECT  21.017 3.936 22.057 3.96 ;
     RECT  21.013 0.096 22.076 0.168 ;
     RECT  22.076 0.096 22.163 0.552 ;
     RECT  22.165 25.104 22.201 25.128 ;
     RECT  22.057 3.936 22.237 4.344 ;
     RECT  22.033 19.392 22.277 21.672 ;
     RECT  21.985 5.712 22.597 6.696 ;
     RECT  22.277 19.632 22.643 21.672 ;
     RECT  22.201 24.528 22.883 25.128 ;
     RECT  22.643 19.776 22.889 21.672 ;
     RECT  22.889 20.16 22.925 21.672 ;
     RECT  22.921 8.544 23.005 8.568 ;
     RECT  22.237 3.312 23.137 4.344 ;
     RECT  22.597 5.712 23.245 6.888 ;
     RECT  21.971 23.376 23.356 23.4 ;
     RECT  23.245 5.712 23.389 7.464 ;
     RECT  22.883 24.528 23.603 24.552 ;
     RECT  23.137 3.312 23.653 4.392 ;
     RECT  23.389 5.712 23.653 7.992 ;
     RECT  23.356 23.376 23.701 23.448 ;
     RECT  23.653 3.312 23.713 7.992 ;
     RECT  22.163 0.096 23.789 0.12 ;
     RECT  21.845 1.728 24.008 1.752 ;
     RECT  23.713 2.832 24.008 7.992 ;
     RECT  22.925 20.16 24.008 21.384 ;
     RECT  23.701 22.752 24.008 23.448 ;
     RECT  24.008 1.728 24.304 23.928 ;
     RECT  24.304 5.472 24.419 6.744 ;
     RECT  24.304 17.088 24.419 17.112 ;
     RECT  24.304 1.728 24.473 4.44 ;
     RECT  24.304 22.656 24.509 23.928 ;
     RECT  24.304 18.816 24.581 18.84 ;
     RECT  24.509 23.376 24.865 23.928 ;
     RECT  24.473 2.736 24.869 2.76 ;
     RECT  24.865 23.376 24.995 23.976 ;
     RECT  24.805 0.096 25.141 0.12 ;
     RECT  24.473 3.792 25.445 4.44 ;
     RECT  24.995 23.904 25.549 23.976 ;
     RECT  24.304 20.16 25.697 21.144 ;
     RECT  25.549 23.904 25.715 24.552 ;
     RECT  25.445 3.792 25.801 4.296 ;
     RECT  25.141 0.096 25.861 0.168 ;
     RECT  24.419 5.952 26.089 6.744 ;
     RECT  25.109 25.776 26.099 25.8 ;
     RECT  26.089 5.664 26.125 6.744 ;
     RECT  26.06 17.616 26.147 17.64 ;
     RECT  25.715 23.904 26.389 23.928 ;
     RECT  25.861 0.096 26.417 0.216 ;
     RECT  26.417 0.192 26.453 0.216 ;
     RECT  25.801 3.552 26.489 4.296 ;
     RECT  26.389 23.856 26.56 23.928 ;
     RECT  24.473 1.728 26.581 1.752 ;
     RECT  26.581 1.728 26.593 2.184 ;
     RECT  26.125 5.664 26.621 6.84 ;
     RECT  26.489 3.792 26.701 4.296 ;
     RECT  26.621 5.664 26.701 7.464 ;
     RECT  26.701 3.792 26.705 7.464 ;
     RECT  26.101 18.816 26.741 18.84 ;
     RECT  25.697 20.16 26.773 20.856 ;
     RECT  26.773 20.16 26.801 22.44 ;
     RECT  26.705 3.792 26.849 7.224 ;
     RECT  26.801 19.392 26.857 22.44 ;
     RECT  26.857 19.392 26.885 21.672 ;
     RECT  26.809 18.192 26.893 18.216 ;
     RECT  26.593 1.728 27.011 2.28 ;
     RECT  26.849 3.792 27.173 3.96 ;
     RECT  26.56 23.808 27.205 23.928 ;
     RECT  27.205 23.808 27.26 24.552 ;
     RECT  26.885 20.16 27.317 21.672 ;
     RECT  27.26 23.376 27.347 24.552 ;
     RECT  27.173 3.936 27.353 3.96 ;
     RECT  27.317 20.496 27.353 21.672 ;
     RECT  27.493 0.096 27.713 0.12 ;
     RECT  27.347 23.856 27.731 24.552 ;
     RECT  27.011 1.728 27.893 1.848 ;
     RECT  27.353 20.496 28.037 21.336 ;
     RECT  28.076 17.088 28.163 17.112 ;
     RECT  27.731 23.856 28.289 23.928 ;
     RECT  28.117 18.24 28.357 18.264 ;
     RECT  28.316 16.944 28.403 16.968 ;
     RECT  26.849 5.136 28.537 7.224 ;
     RECT  28.268 3.744 28.549 3.768 ;
     RECT  28.549 3.408 28.789 3.768 ;
     RECT  28.537 4.752 28.789 7.224 ;
     RECT  28.393 25.104 29.123 25.128 ;
     RECT  28.393 21.84 29.221 21.864 ;
     RECT  28.037 20.496 29.249 20.856 ;
     RECT  27.893 1.728 29.269 1.8 ;
     RECT  29.269 1.728 29.408 2.328 ;
     RECT  28.789 3.408 29.408 7.224 ;
     RECT  28.357 18.24 29.408 18.84 ;
     RECT  29.249 20.16 29.408 20.856 ;
     RECT  29.221 21.84 29.408 22.776 ;
     RECT  28.289 23.904 29.408 23.928 ;
     RECT  29.221 25.728 29.507 25.752 ;
     RECT  29.408 1.728 29.704 23.928 ;
     RECT  29.704 16.944 29.939 17.64 ;
     RECT  29.704 4.224 29.981 7.224 ;
     RECT  29.981 4.224 30.025 6.984 ;
     RECT  29.704 18.816 30.089 21 ;
     RECT  29.704 22.176 30.233 23.928 ;
     RECT  29.939 17.616 30.565 17.64 ;
     RECT  30.089 19.392 30.797 21 ;
     RECT  30.797 19.392 30.881 21.096 ;
     RECT  30.025 4.224 30.917 6.6 ;
     RECT  30.917 4.464 31.004 6.6 ;
     RECT  31.004 4.464 31.045 6.84 ;
     RECT  30.881 19.392 31.285 20.904 ;
     RECT  31.244 17.088 31.331 17.112 ;
     RECT  31.285 18.816 31.601 20.904 ;
     RECT  30.233 22.176 31.633 22.2 ;
     RECT  30.233 23.376 31.633 23.928 ;
     RECT  31.633 22.176 31.637 23.928 ;
     RECT  31.628 3.168 31.715 3.192 ;
     RECT  31.601 18.816 31.781 19.416 ;
     RECT  31.849 3.216 31.885 3.24 ;
     RECT  31.045 4.464 31.885 6.936 ;
     RECT  31.561 17.616 32.003 17.64 ;
     RECT  29.704 1.728 32.033 2.184 ;
     RECT  31.885 3.216 32.105 6.936 ;
     RECT  32.105 3.216 32.291 3.96 ;
     RECT  31.453 8.544 32.329 8.568 ;
     RECT  31.957 0.096 32.464 0.12 ;
     RECT  32.033 1.728 32.501 1.8 ;
     RECT  32.389 25.104 32.531 25.128 ;
     RECT  31.781 18.816 32.573 19.368 ;
     RECT  32.291 3.216 32.627 3.432 ;
     RECT  32.569 7.968 32.653 7.992 ;
     RECT  31.637 22.416 32.753 23.928 ;
     RECT  32.105 5.04 33.005 6.936 ;
     RECT  33.073 18.192 33.157 18.216 ;
     RECT  33.005 5.04 33.289 6.6 ;
     RECT  32.627 3.408 33.401 3.432 ;
     RECT  33.109 19.392 33.637 19.416 ;
     RECT  31.601 20.544 33.637 20.904 ;
     RECT  33.605 22.272 33.689 22.296 ;
     RECT  33.613 17.616 33.697 17.64 ;
     RECT  33.637 19.392 33.724 20.904 ;
     RECT  33.724 19.392 33.725 19.464 ;
     RECT  33.289 4.512 33.779 6.6 ;
     RECT  33.721 8.544 33.805 8.568 ;
     RECT  33.725 19.44 33.833 19.464 ;
     RECT  32.753 23.376 34.693 23.928 ;
     RECT  32.464 0.096 34.733 0.168 ;
     RECT  34.733 0.144 34.765 0.168 ;
     RECT  32.501 1.728 34.765 1.752 ;
     RECT  34.765 0.144 34.808 1.752 ;
     RECT  34.261 2.832 34.808 2.856 ;
     RECT  33.779 4.704 34.808 6.6 ;
     RECT  33.724 20.592 34.808 20.904 ;
     RECT  33.793 22.032 34.808 22.056 ;
     RECT  34.693 23.376 34.808 23.976 ;
     RECT  34.808 0.144 35.075 23.976 ;
     RECT  35.075 1.728 35.104 23.976 ;
     RECT  35.104 1.728 35.237 1.8 ;
     RECT  35.104 3.936 35.267 6.648 ;
     RECT  35.104 18.192 35.315 22.248 ;
     RECT  35.173 25.776 35.315 25.8 ;
     RECT  35.315 22.08 35.345 22.248 ;
     RECT  35.075 0.144 35.425 0.6 ;
     RECT  35.104 16.944 35.459 17.112 ;
     RECT  35.315 18.192 35.533 20.904 ;
     RECT  35.104 23.376 35.603 23.976 ;
     RECT  35.459 17.088 35.641 17.112 ;
     RECT  35.533 18.816 35.651 20.904 ;
     RECT  35.603 23.856 35.665 23.976 ;
     RECT  35.651 18.816 35.777 19.416 ;
     RECT  35.345 22.176 36.133 22.248 ;
     RECT  35.777 18.816 36.179 19.128 ;
     RECT  35.267 3.936 36.201 6.6 ;
     RECT  36.179 18.816 36.245 18.84 ;
     RECT  36.133 22.176 36.245 22.728 ;
     RECT  35.237 1.728 36.277 1.752 ;
     RECT  35.665 23.856 36.515 24.504 ;
     RECT  35.893 0.096 36.569 0.12 ;
     RECT  36.201 3.936 36.569 4.536 ;
     RECT  36.201 5.664 36.605 6.6 ;
     RECT  35.104 2.88 36.641 2.904 ;
     RECT  35.651 20.544 36.749 20.904 ;
     RECT  36.277 1.728 36.956 1.8 ;
     RECT  36.245 22.176 37.037 22.2 ;
     RECT  36.956 1.728 37.043 2.28 ;
     RECT  36.956 16.944 37.043 16.968 ;
     RECT  37.043 1.728 37.141 2.184 ;
     RECT  36.997 18.24 37.181 18.264 ;
     RECT  37.141 1.68 37.235 2.184 ;
     RECT  36.515 23.856 37.493 23.928 ;
     RECT  37.493 23.76 37.609 23.928 ;
     RECT  36.605 5.808 37.685 6.6 ;
     RECT  36.749 20.592 37.717 20.904 ;
     RECT  37.717 18.192 37.801 18.216 ;
     RECT  37.82 17.616 37.907 17.64 ;
     RECT  37.861 19.392 38.041 19.416 ;
     RECT  37.717 20.592 38.041 21.144 ;
     RECT  38.041 19.392 38.077 21.144 ;
     RECT  37.609 22.992 38.221 23.928 ;
     RECT  36.569 3.936 38.245 3.96 ;
     RECT  37.235 1.728 38.261 2.184 ;
     RECT  38.149 11.376 38.291 11.4 ;
     RECT  38.221 22.656 38.333 23.928 ;
     RECT  38.333 22.992 38.477 23.928 ;
     RECT  38.245 3.936 38.509 4.008 ;
     RECT  37.685 5.808 38.509 6.312 ;
     RECT  38.245 13.056 38.533 13.896 ;
     RECT  38.533 13.056 38.62 14.04 ;
     RECT  38.509 3.936 38.689 6.312 ;
     RECT  38.477 23.808 38.712 23.928 ;
     RECT  38.689 3.936 38.725 7.224 ;
     RECT  38.712 23.808 38.819 24.552 ;
     RECT  38.077 19.392 38.917 21.192 ;
     RECT  38.917 19.344 38.924 21.192 ;
     RECT  38.924 18.768 39.005 21.192 ;
     RECT  39.005 18.768 39.011 21.672 ;
     RECT  38.941 17.472 39.059 17.496 ;
     RECT  39.011 18.864 39.089 21.672 ;
     RECT  38.581 0.096 39.125 0.12 ;
     RECT  39.089 18.864 39.161 18.888 ;
     RECT  39.013 2.88 39.205 2.904 ;
     RECT  38.725 3.888 39.205 7.224 ;
     RECT  39.205 2.88 39.265 7.224 ;
     RECT  38.261 1.728 39.301 1.848 ;
     RECT  39.265 2.88 39.301 7.992 ;
     RECT  39.877 25.056 39.961 25.08 ;
     RECT  39.877 0.144 40.133 0.6 ;
     RECT  38.819 23.808 40.204 23.928 ;
     RECT  39.301 1.728 40.208 7.992 ;
     RECT  39.697 10.848 40.208 10.872 ;
     RECT  38.62 13.056 40.208 13.08 ;
     RECT  39.089 19.968 40.208 21.192 ;
     RECT  40.204 23.808 40.208 23.976 ;
     RECT  40.133 0.144 40.259 0.168 ;
     RECT  40.208 1.728 40.385 23.976 ;
     RECT  40.385 1.728 40.504 23.928 ;
     RECT  40.504 17.472 40.739 17.496 ;
     RECT  40.504 6.672 40.889 7.08 ;
     RECT  40.504 18.816 40.931 19.368 ;
     RECT  40.931 18.816 41.069 18.84 ;
     RECT  40.504 20.544 41.141 20.952 ;
     RECT  40.504 23.376 41.171 23.928 ;
     RECT  40.504 1.728 41.429 2.904 ;
     RECT  41.093 0.096 41.461 0.12 ;
     RECT  41.429 1.728 41.653 2.328 ;
     RECT  40.504 3.888 41.789 3.912 ;
     RECT  40.889 6.864 41.929 7.08 ;
     RECT  41.653 1.152 42.041 2.328 ;
     RECT  41.141 20.592 42.077 20.952 ;
     RECT  40.504 5.232 42.181 5.496 ;
     RECT  42.181 4.656 42.289 5.496 ;
     RECT  41.929 6.816 42.289 7.08 ;
     RECT  42.077 20.592 42.325 20.904 ;
     RECT  42.289 4.656 42.373 7.08 ;
     RECT  42.041 1.728 42.473 2.328 ;
     RECT  41.171 23.856 42.677 23.928 ;
     RECT  42.668 17.616 42.755 17.64 ;
     RECT  42.693 18.816 42.797 18.84 ;
     RECT  42.373 4.656 42.865 5.496 ;
     RECT  42.677 23.712 42.901 23.928 ;
     RECT  42.373 6.672 43.049 7.08 ;
     RECT  42.325 20.448 43.121 20.904 ;
     RECT  42.901 23.376 43.189 23.928 ;
     RECT  41.461 0.096 43.265 0.168 ;
     RECT  43.189 23.376 43.331 24.024 ;
     RECT  43.331 23.808 43.475 24.024 ;
     RECT  43.121 20.832 43.585 20.904 ;
     RECT  42.865 4.56 43.765 5.496 ;
     RECT  42.473 1.728 43.859 2.28 ;
     RECT  43.765 4.56 43.916 5.688 ;
     RECT  43.916 4.272 43.949 5.688 ;
     RECT  43.949 4.272 43.957 4.296 ;
     RECT  43.957 3.936 44.003 4.296 ;
     RECT  43.859 1.728 44.345 1.8 ;
     RECT  43.585 20.832 44.525 20.952 ;
     RECT  43.981 17.616 44.531 17.64 ;
     RECT  44.449 22.224 44.533 22.248 ;
     RECT  43.949 5.472 44.581 5.688 ;
     RECT  43.049 6.672 44.581 6.936 ;
     RECT  44.525 20.832 44.593 20.904 ;
     RECT  44.533 2.88 44.657 2.904 ;
     RECT  44.581 5.472 45.025 6.936 ;
     RECT  43.475 23.808 45.061 23.928 ;
     RECT  43.813 25.776 45.281 25.8 ;
     RECT  44.345 1.728 45.397 1.752 ;
     RECT  45.397 1.728 45.608 1.8 ;
     RECT  44.657 2.88 45.608 2.952 ;
     RECT  44.003 3.936 45.608 3.96 ;
     RECT  45.025 5.04 45.608 6.936 ;
     RECT  40.504 13.056 45.608 13.08 ;
     RECT  44.593 20.304 45.608 20.904 ;
     RECT  45.061 23.376 45.608 23.928 ;
     RECT  45.608 1.728 45.635 23.928 ;
     RECT  43.265 0.096 45.781 0.12 ;
     RECT  45.635 1.728 45.904 23.88 ;
     RECT  45.781 0.096 45.965 0.168 ;
     RECT  45.904 17.088 46.019 23.88 ;
     RECT  45.904 1.728 46.145 6.936 ;
     RECT  46.145 5.04 46.163 6.936 ;
     RECT  46.019 22.752 46.289 23.88 ;
     RECT  45.904 8.544 46.441 8.568 ;
     RECT  46.019 17.088 46.451 21.672 ;
     RECT  46.163 5.472 46.499 6.936 ;
     RECT  46.451 17.088 46.54 17.64 ;
     RECT  46.54 17.472 46.547 17.64 ;
     RECT  46.289 22.8 46.547 23.88 ;
     RECT  46.547 23.376 46.681 23.88 ;
     RECT  46.451 18.816 46.685 21.672 ;
     RECT  46.537 25.104 46.883 25.128 ;
     RECT  46.145 3.408 47.009 3.96 ;
     RECT  46.685 19.344 47.089 21.672 ;
     RECT  46.499 5.472 47.149 6.84 ;
     RECT  47.149 5.088 47.189 6.84 ;
     RECT  46.145 1.728 47.261 2.328 ;
     RECT  47.089 19.392 47.369 21.672 ;
     RECT  46.547 17.616 47.411 17.64 ;
     RECT  46.681 23.376 47.693 23.928 ;
     RECT  47.261 1.728 47.801 1.848 ;
     RECT  47.009 3.408 48.017 3.432 ;
     RECT  47.189 5.088 48.409 5.496 ;
     RECT  47.189 6.528 48.409 6.84 ;
     RECT  47.369 19.392 48.557 21.096 ;
     RECT  48.409 5.088 48.593 6.84 ;
     RECT  48.524 17.616 48.611 17.64 ;
     RECT  45.965 0.096 48.629 0.12 ;
     RECT  48.557 20.544 48.773 21.096 ;
     RECT  48.593 5.088 48.844 6.552 ;
     RECT  48.557 19.392 48.881 19.416 ;
     RECT  48.844 5.088 48.913 5.112 ;
     RECT  48.661 0.576 48.953 0.6 ;
     RECT  48.913 4.656 48.953 5.112 ;
     RECT  48.337 24.528 48.956 24.552 ;
     RECT  47.693 23.376 48.985 23.496 ;
     RECT  48.956 24.528 48.985 25.08 ;
     RECT  48.985 23.376 49.043 25.08 ;
     RECT  48.953 4.656 49.165 4.68 ;
     RECT  49.043 23.376 49.235 24.552 ;
     RECT  47.801 1.728 49.373 1.8 ;
     RECT  49.235 23.376 49.427 23.928 ;
     RECT  49.373 1.728 49.525 1.848 ;
     RECT  48.805 21.936 49.633 21.96 ;
     RECT  48.773 20.544 49.637 20.952 ;
     RECT  49.525 1.728 49.745 2.184 ;
     RECT  49.637 20.832 49.745 20.952 ;
     RECT  49.633 21.936 49.889 22.248 ;
     RECT  49.165 3.936 49.916 4.68 ;
     RECT  50.204 0.528 50.291 0.552 ;
     RECT  49.745 1.728 50.396 1.848 ;
     RECT  49.916 3.936 50.425 5.208 ;
     RECT  50.396 1.104 50.483 1.848 ;
     RECT  49.427 23.808 50.78 23.928 ;
     RECT  50.425 3.936 50.869 5.304 ;
     RECT  50.483 1.68 51.008 1.848 ;
     RECT  50.869 3.696 51.008 5.304 ;
     RECT  48.844 6.528 51.008 6.552 ;
     RECT  50.849 8.544 51.008 8.568 ;
     RECT  45.904 13.056 51.008 13.08 ;
     RECT  49.745 20.928 51.008 20.952 ;
     RECT  49.889 22.224 51.008 22.248 ;
     RECT  50.78 23.376 51.008 23.928 ;
     RECT  51.008 1.68 51.304 23.928 ;
     RECT  51.304 17.616 51.577 23.928 ;
     RECT  51.577 17.616 51.649 24.552 ;
     RECT  51.349 25.776 51.649 25.8 ;
     RECT  51.649 17.616 51.875 25.8 ;
     RECT  51.304 1.68 51.877 1.848 ;
     RECT  51.875 18.192 51.941 25.8 ;
     RECT  51.941 19.392 52.013 25.8 ;
     RECT  51.941 18.192 52.057 18.216 ;
     RECT  52.013 19.392 52.115 25.08 ;
     RECT  52.115 19.392 52.193 22.776 ;
     RECT  52.115 23.808 52.259 25.08 ;
     RECT  51.304 4.224 52.265 6.792 ;
     RECT  52.193 20.208 52.265 22.776 ;
     RECT  50.821 0.096 52.337 0.12 ;
     RECT  51.877 1.152 52.405 1.848 ;
     RECT  52.405 1.152 52.441 2.184 ;
     RECT  52.265 22.176 52.553 22.776 ;
     RECT  52.265 4.944 52.597 6.792 ;
     RECT  52.441 1.104 52.625 2.184 ;
     RECT  52.625 1.104 52.643 1.896 ;
     RECT  52.597 4.944 52.643 6.888 ;
     RECT  52.259 23.808 52.643 24.552 ;
     RECT  52.643 23.808 53.021 23.928 ;
     RECT  52.945 17.616 53.029 17.64 ;
     RECT  52.981 18.816 53.273 18.84 ;
     RECT  52.643 6.528 53.341 6.888 ;
     RECT  52.265 20.208 53.461 20.856 ;
     RECT  52.553 22.176 53.461 22.2 ;
     RECT  53.317 25.728 53.507 25.752 ;
     RECT  53.461 20.208 53.561 22.2 ;
     RECT  52.643 1.728 53.597 1.896 ;
     RECT  53.561 20.208 53.605 21.096 ;
     RECT  53.341 6.528 53.921 7.32 ;
     RECT  53.653 0.096 53.957 0.12 ;
     RECT  53.605 19.92 54.101 21.096 ;
     RECT  53.597 1.728 54.229 1.8 ;
     RECT  54.061 25.104 54.275 25.128 ;
     RECT  54.133 14.832 54.317 14.856 ;
     RECT  53.561 22.176 54.317 22.2 ;
     RECT  52.643 4.944 54.421 5.496 ;
     RECT  54.421 4.272 54.508 5.496 ;
     RECT  54.508 5.184 54.529 5.496 ;
     RECT  53.921 6.528 54.529 6.648 ;
     RECT  53.125 23.376 54.565 23.496 ;
     RECT  54.229 1.152 54.605 1.8 ;
     RECT  54.529 5.184 54.641 6.648 ;
     RECT  54.605 1.2 54.947 1.8 ;
     RECT  54.101 20.496 55.093 21.096 ;
     RECT  54.565 3.792 55.393 4.104 ;
     RECT  55.093 20.496 55.393 21.144 ;
     RECT  55.393 20.496 55.433 22.056 ;
     RECT  55.433 20.496 55.501 20.856 ;
     RECT  54.641 6.24 55.537 6.648 ;
     RECT  55.457 25.776 55.541 25.8 ;
     RECT  54.947 1.728 55.621 1.8 ;
     RECT  55.393 2.832 55.621 4.104 ;
     RECT  55.621 1.728 55.645 4.104 ;
     RECT  55.645 1.728 55.717 4.152 ;
     RECT  55.717 1.728 55.765 4.2 ;
     RECT  54.641 5.184 55.765 5.208 ;
     RECT  55.537 6.24 55.765 6.84 ;
     RECT  55.889 8.544 55.972 8.568 ;
     RECT  54.565 23.376 56.329 23.928 ;
     RECT  55.765 1.728 56.408 6.84 ;
     RECT  55.972 8.544 56.408 8.616 ;
     RECT  51.304 13.056 56.408 13.08 ;
     RECT  56.293 17.616 56.408 17.64 ;
     RECT  56.293 18.96 56.408 18.984 ;
     RECT  55.501 20.4 56.408 20.856 ;
     RECT  55.433 22.032 56.408 22.056 ;
     RECT  56.329 23.376 56.408 24.024 ;
     RECT  56.197 0.096 56.533 0.12 ;
     RECT  56.408 1.728 56.704 24.024 ;
     RECT  56.704 5.28 56.765 6.84 ;
     RECT  56.704 23.28 56.771 24.024 ;
     RECT  56.533 0.096 56.819 0.168 ;
     RECT  56.533 25.728 56.819 25.752 ;
     RECT  56.704 20.592 56.867 21.672 ;
     RECT  56.771 23.28 56.867 23.448 ;
     RECT  56.819 0.096 56.945 0.12 ;
     RECT  56.704 2.736 57.305 4.152 ;
     RECT  56.704 17.472 57.347 17.496 ;
     RECT  56.704 18.816 57.347 19.368 ;
     RECT  57.305 3.408 57.413 4.152 ;
     RECT  56.867 20.592 57.593 21.24 ;
     RECT  57.413 3.84 57.737 4.152 ;
     RECT  56.704 1.728 57.781 1.752 ;
     RECT  56.765 5.28 57.949 5.304 ;
     RECT  56.765 6.288 57.949 6.84 ;
     RECT  57.949 5.28 57.989 6.84 ;
     RECT  57.98 17.616 58.067 17.64 ;
     RECT  58.057 25.104 58.211 25.128 ;
     RECT  56.867 23.376 58.453 23.448 ;
     RECT  57.347 18.816 58.46 18.84 ;
     RECT  57.781 1.728 58.481 1.8 ;
     RECT  57.737 3.84 58.489 3.96 ;
     RECT  58.453 23.376 58.489 23.928 ;
     RECT  58.481 1.728 58.565 1.848 ;
     RECT  58.489 23.376 58.597 24.024 ;
     RECT  57.593 20.592 58.705 21.144 ;
     RECT  58.565 1.728 58.709 1.8 ;
     RECT  58.597 23.376 58.739 24.552 ;
     RECT  58.705 20.544 58.741 21.144 ;
     RECT  58.489 3.744 58.777 3.96 ;
     RECT  58.777 3.744 58.885 4.392 ;
     RECT  58.46 18.816 58.885 19.368 ;
     RECT  58.885 18.768 58.988 19.368 ;
     RECT  58.741 20.544 59.029 21.288 ;
     RECT  58.739 23.376 59.075 24.024 ;
     RECT  58.988 18.72 59.132 19.368 ;
     RECT  59.132 18.192 59.173 19.368 ;
     RECT  59.029 20.544 59.357 22.248 ;
     RECT  58.885 3.696 59.389 4.392 ;
     RECT  57.989 5.664 59.389 6.84 ;
     RECT  59.389 3.696 59.429 6.84 ;
     RECT  58.693 0.096 59.605 0.12 ;
     RECT  59.075 23.376 59.795 23.928 ;
     RECT  59.173 18.192 59.861 19.464 ;
     RECT  59.861 19.392 59.893 19.464 ;
     RECT  59.357 20.544 59.893 21.288 ;
     RECT  59.605 0.096 60.041 0.168 ;
     RECT  60.181 9.12 60.265 9.144 ;
     RECT  58.709 1.728 60.325 1.752 ;
     RECT  59.429 3.696 60.397 5.208 ;
     RECT  59.429 6.24 60.397 6.84 ;
     RECT  60.325 1.728 60.409 1.848 ;
     RECT  60.373 17.088 60.428 17.112 ;
     RECT  59.861 18.192 60.428 18.264 ;
     RECT  60.041 0.096 60.437 0.12 ;
     RECT  60.397 3.696 60.437 6.84 ;
     RECT  60.428 17.088 60.46 18.264 ;
     RECT  60.46 17.616 60.515 18.264 ;
     RECT  60.253 24.528 60.515 24.552 ;
     RECT  60.409 1.728 60.541 1.8 ;
     RECT  59.795 23.376 60.853 23.448 ;
     RECT  60.541 1.68 60.899 1.8 ;
     RECT  60.437 3.696 60.997 6.648 ;
     RECT  60.865 25.104 61.043 25.128 ;
     RECT  59.893 19.392 61.141 21.288 ;
     RECT  60.515 18.192 61.484 18.264 ;
     RECT  61.484 17.616 61.525 18.264 ;
     RECT  61.141 19.392 61.525 21.432 ;
     RECT  61.477 24.528 61.619 24.552 ;
     RECT  60.899 1.728 61.657 1.8 ;
     RECT  60.997 2.88 61.657 6.648 ;
     RECT  61.525 17.616 61.669 21.432 ;
     RECT  60.853 23.376 61.717 23.496 ;
     RECT  61.657 1.728 61.808 6.648 ;
     RECT  56.704 13.056 61.808 13.08 ;
     RECT  61.669 17.616 61.808 22.248 ;
     RECT  61.717 23.376 61.808 23.928 ;
     RECT  61.808 1.728 62.104 23.928 ;
     RECT  62.104 23.376 62.173 23.928 ;
     RECT  62.173 23.376 62.675 23.496 ;
     RECT  62.104 1.728 62.705 2.28 ;
     RECT  62.104 17.088 62.771 21.192 ;
     RECT  62.771 17.088 62.956 17.112 ;
     RECT  62.104 5.136 63.068 7.416 ;
     RECT  62.771 18.576 63.101 21.192 ;
     RECT  63.068 5.088 63.281 7.416 ;
     RECT  61.573 0.096 63.673 0.12 ;
     RECT  63.281 5.088 63.677 5.784 ;
     RECT  63.101 18.576 63.731 18.6 ;
     RECT  62.675 23.376 63.733 23.448 ;
     RECT  63.673 0.096 63.779 0.216 ;
     RECT  63.281 6.816 63.827 7.416 ;
     RECT  62.104 3.84 63.877 3.864 ;
     RECT  63.733 23.376 64.069 23.496 ;
     RECT  63.877 2.88 64.073 3.864 ;
     RECT  63.101 19.776 64.105 21.192 ;
     RECT  64.073 3.84 64.177 3.864 ;
     RECT  63.677 5.088 64.177 5.112 ;
     RECT  64.177 3.84 64.307 5.112 ;
     RECT  64.307 3.936 64.348 5.112 ;
     RECT  64.105 19.776 64.789 21.528 ;
     RECT  64.748 18.192 64.835 18.216 ;
     RECT  64.069 23.376 64.835 23.928 ;
     RECT  64.348 4.56 64.933 5.112 ;
     RECT  64.835 23.376 64.973 23.496 ;
     RECT  64.933 4.56 64.979 5.208 ;
     RECT  62.705 1.728 64.981 1.8 ;
     RECT  64.861 25.104 65.027 25.128 ;
     RECT  64.789 19.392 65.125 21.528 ;
     RECT  64.979 5.088 65.257 5.208 ;
     RECT  65.125 18.768 65.413 21.528 ;
     RECT  64.981 1.728 65.441 2.328 ;
     RECT  63.779 0.096 65.701 0.12 ;
     RECT  65.708 17.616 65.941 17.64 ;
     RECT  65.413 18.768 65.941 21.672 ;
     RECT  65.701 0.096 66.005 0.168 ;
     RECT  65.941 17.472 66.037 21.672 ;
     RECT  66.037 17.472 66.083 22.104 ;
     RECT  66.005 0.096 66.089 0.6 ;
     RECT  65.257 5.088 66.121 5.688 ;
     RECT  64.973 23.376 66.121 23.448 ;
     RECT  66.083 17.472 66.131 17.496 ;
     RECT  66.083 18.816 66.161 22.104 ;
     RECT  66.121 4.944 66.337 5.688 ;
     RECT  65.441 1.728 66.545 1.8 ;
     RECT  66.161 19.392 66.565 22.104 ;
     RECT  63.827 6.816 66.589 7.368 ;
     RECT  66.121 23.376 66.589 23.928 ;
     RECT  66.545 1.728 67.208 1.848 ;
     RECT  66.445 3.84 67.208 3.864 ;
     RECT  66.337 4.944 67.208 5.784 ;
     RECT  66.589 6.768 67.208 7.368 ;
     RECT  62.104 13.056 67.208 13.08 ;
     RECT  66.565 19.392 67.208 22.2 ;
     RECT  66.589 23.376 67.208 23.976 ;
     RECT  66.089 0.096 67.285 0.12 ;
     RECT  67.208 1.728 67.331 23.976 ;
     RECT  67.285 0.096 67.385 0.552 ;
     RECT  67.331 1.728 67.504 23.88 ;
     RECT  67.504 3.84 67.601 4.968 ;
     RECT  67.504 18.816 67.619 21.72 ;
     RECT  67.619 21.696 67.645 21.72 ;
     RECT  67.504 23.376 67.817 23.88 ;
     RECT  67.385 0.096 67.853 0.12 ;
     RECT  67.619 18.816 67.997 20.52 ;
     RECT  67.504 1.728 68.317 1.8 ;
     RECT  68.317 25.104 68.435 25.128 ;
     RECT  68.317 1.104 68.579 1.8 ;
     RECT  67.817 23.376 68.876 23.448 ;
     RECT  68.579 1.68 68.885 1.8 ;
     RECT  67.504 17.616 68.915 17.64 ;
     RECT  67.997 18.816 69.005 18.84 ;
     RECT  67.997 20.16 69.061 20.52 ;
     RECT  69.02 18 69.107 18.024 ;
     RECT  68.876 23.376 69.245 23.496 ;
     RECT  68.885 1.68 69.253 1.896 ;
     RECT  69.245 23.376 69.329 23.928 ;
     RECT  69.253 1.68 69.361 2.184 ;
     RECT  69.061 19.392 69.397 20.52 ;
     RECT  69.397 19.392 69.401 20.568 ;
     RECT  69.253 21.648 69.437 21.672 ;
     RECT  69.361 1.68 69.491 2.28 ;
     RECT  67.504 6.288 69.617 7.368 ;
     RECT  69.401 20.16 69.617 20.568 ;
     RECT  69.491 1.68 69.683 2.184 ;
     RECT  69.683 1.728 69.689 2.184 ;
     RECT  67.601 4.128 70.009 4.968 ;
     RECT  69.329 23.376 70.019 23.736 ;
     RECT  70.019 23.376 70.085 23.496 ;
     RECT  70.009 3.408 70.117 4.968 ;
     RECT  70.117 25.056 70.403 25.08 ;
     RECT  70.441 22.08 70.513 22.104 ;
     RECT  69.973 0.096 70.549 0.12 ;
     RECT  69.617 20.544 70.553 20.568 ;
     RECT  70.513 21.696 70.585 22.104 ;
     RECT  70.117 3.408 70.693 5.352 ;
     RECT  69.617 6.816 70.693 7.368 ;
     RECT  70.585 21.072 70.697 22.104 ;
     RECT  70.549 0.096 70.876 0.168 ;
     RECT  70.693 3.408 70.877 5.64 ;
     RECT  70.085 23.376 71.161 23.448 ;
     RECT  69.689 1.728 71.197 1.8 ;
     RECT  70.693 19.776 71.221 19.8 ;
     RECT  70.877 3.408 71.237 5.352 ;
     RECT  71.18 18 71.267 18.024 ;
     RECT  71.237 5.328 71.273 5.352 ;
     RECT  71.197 1.728 71.281 2.28 ;
     RECT  70.876 0.096 71.381 0.216 ;
     RECT  70.693 6.624 71.381 7.368 ;
     RECT  71.237 3.408 71.413 3.864 ;
     RECT  71.381 0.192 71.525 0.216 ;
     RECT  71.221 19.392 71.561 19.8 ;
     RECT  70.697 21.696 71.701 22.104 ;
     RECT  67.504 13.056 71.749 13.08 ;
     RECT  71.281 1.728 71.797 1.8 ;
     RECT  70.885 25.776 71.797 25.8 ;
     RECT  71.797 25.584 71.837 25.8 ;
     RECT  71.161 23.376 71.845 23.496 ;
     RECT  71.701 21.696 71.917 22.248 ;
     RECT  71.837 25.104 71.921 25.8 ;
     RECT  71.921 25.584 71.987 25.8 ;
     RECT  71.797 1.152 71.993 1.8 ;
     RECT  71.987 25.776 72.083 25.8 ;
     RECT  71.381 6.624 72.169 6.888 ;
     RECT  71.845 23.376 72.349 23.928 ;
     RECT  72.229 5.04 72.38 5.064 ;
     RECT  72.169 6.288 72.38 6.888 ;
     RECT  71.917 21.12 72.385 22.248 ;
     RECT  72.349 23.376 72.385 23.976 ;
     RECT  72.517 0.096 72.605 0.12 ;
     RECT  71.993 1.728 72.608 1.8 ;
     RECT  71.413 3.312 72.608 3.864 ;
     RECT  72.38 5.04 72.608 6.888 ;
     RECT  71.621 8.544 72.608 8.568 ;
     RECT  71.749 12.864 72.608 13.08 ;
     RECT  71.561 19.776 72.608 19.8 ;
     RECT  72.385 21.12 72.608 23.976 ;
     RECT  72.608 1.728 72.904 23.976 ;
     RECT  72.904 19.776 73.037 20.952 ;
     RECT  72.904 22.224 73.091 23.976 ;
     RECT  72.904 1.728 73.237 3.864 ;
     RECT  73.237 1.152 73.397 3.864 ;
     RECT  72.904 5.04 73.397 6.84 ;
     RECT  72.904 12.864 73.433 13.08 ;
     RECT  73.037 20.544 73.757 20.952 ;
     RECT  73.091 22.224 73.901 23.928 ;
     RECT  73.397 1.728 73.969 3.864 ;
     RECT  73.397 5.04 73.969 6.696 ;
     RECT  73.897 25.056 74.147 25.08 ;
     RECT  73.969 1.728 74.369 6.696 ;
     RECT  73.901 22.464 74.473 23.928 ;
     RECT  74.369 1.728 74.477 6.6 ;
     RECT  73.757 20.544 74.485 20.616 ;
     RECT  74.477 1.728 74.693 6.552 ;
     RECT  74.693 4.128 74.945 6.552 ;
     RECT  74.473 22.464 74.945 23.976 ;
     RECT  74.485 20.448 74.977 20.616 ;
     RECT  74.945 5.136 75.017 6.552 ;
     RECT  74.945 23.376 75.059 23.976 ;
     RECT  74.977 20.448 75.093 21.144 ;
     RECT  75.093 19.968 75.155 21.144 ;
     RECT  74.693 1.728 75.251 2.952 ;
     RECT  75.509 0.576 75.593 0.6 ;
     RECT  75.541 25.776 75.625 25.8 ;
     RECT  75.625 25.056 75.683 25.8 ;
     RECT  75.251 2.928 75.845 2.952 ;
     RECT  75.017 6 76.021 6.552 ;
     RECT  76.021 5.376 76.061 6.84 ;
     RECT  75.683 25.056 76.115 25.08 ;
     RECT  75.251 1.728 76.261 1.8 ;
     RECT  75.059 23.376 76.261 23.4 ;
     RECT  76.061 5.376 76.741 5.4 ;
     RECT  75.155 19.968 76.789 20.952 ;
     RECT  75.913 21.936 76.92 21.96 ;
     RECT  76.261 23.376 76.92 23.496 ;
     RECT  76.92 21.936 77.027 23.496 ;
     RECT  76.061 6.816 77.137 6.84 ;
     RECT  76.261 1.728 77.173 1.848 ;
     RECT  77.027 23.376 77.309 23.496 ;
     RECT  74.945 4.128 77.353 4.152 ;
     RECT  76.741 5.184 77.353 5.4 ;
     RECT  75.733 0.096 77.429 0.12 ;
     RECT  77.353 4.128 77.489 5.4 ;
     RECT  77.669 0.576 77.753 0.6 ;
     RECT  77.137 6.816 77.785 7.464 ;
     RECT  77.173 1.728 78.008 2.328 ;
     RECT  77.489 3.408 78.008 5.4 ;
     RECT  77.785 6.384 78.008 7.464 ;
     RECT  73.433 13.056 78.008 13.08 ;
     RECT  76.789 19.92 78.008 20.952 ;
     RECT  77.027 21.936 78.008 21.96 ;
     RECT  77.309 23.376 78.008 23.928 ;
     RECT  78.008 1.728 78.304 23.928 ;
     RECT  78.304 4.128 78.473 6.84 ;
     RECT  78.304 8.928 78.481 8.952 ;
     RECT  78.473 4.272 78.563 6.84 ;
     RECT  78.563 4.704 78.611 6.84 ;
     RECT  78.304 1.728 79.193 1.896 ;
     RECT  78.304 19.92 79.301 23.928 ;
     RECT  78.611 5.136 79.337 6.84 ;
     RECT  79.301 19.92 79.481 21.096 ;
     RECT  79.337 5.184 79.841 6.84 ;
     RECT  79.481 20.208 79.859 21.096 ;
     RECT  79.301 22.128 80.099 23.928 ;
     RECT  79.841 5.184 80.341 5.208 ;
     RECT  80.341 4.896 80.377 5.208 ;
     RECT  80.099 22.128 80.453 22.824 ;
     RECT  80.377 4.656 80.485 5.208 ;
     RECT  80.485 3.936 80.633 5.208 ;
     RECT  79.859 20.592 80.665 21.096 ;
     RECT  79.841 6.24 80.669 6.84 ;
     RECT  79.193 1.728 80.725 1.8 ;
     RECT  80.725 1.728 80.957 1.896 ;
     RECT  80.453 22.8 81.059 22.824 ;
     RECT  80.917 25.056 81.059 25.08 ;
     RECT  80.045 0.096 81.109 0.12 ;
     RECT  80.099 23.856 81.109 23.928 ;
     RECT  81.269 25.776 81.353 25.8 ;
     RECT  80.665 20.592 81.461 21.672 ;
     RECT  81.109 0.096 81.637 0.168 ;
     RECT  80.669 6.816 81.637 6.84 ;
     RECT  80.957 1.728 81.961 1.8 ;
     RECT  80.633 4.272 81.98 5.208 ;
     RECT  81.98 4.272 82.021 5.256 ;
     RECT  81.637 6.816 82.021 6.888 ;
     RECT  81.637 0.096 82.037 0.6 ;
     RECT  82.021 4.272 82.067 6.888 ;
     RECT  81.109 23.376 82.073 23.928 ;
     RECT  82.037 0.096 82.469 0.12 ;
     RECT  81.461 20.592 82.537 20.856 ;
     RECT  81.961 1.728 82.549 2.088 ;
     RECT  82.357 25.776 82.885 25.8 ;
     RECT  82.537 20.592 82.988 21.528 ;
     RECT  82.885 25.728 83.009 25.8 ;
     RECT  83.009 25.728 83.075 25.752 ;
     RECT  82.073 23.376 83.077 23.4 ;
     RECT  82.988 20.592 83.221 21.816 ;
     RECT  82.067 4.272 83.269 6.84 ;
     RECT  82.549 1.728 83.408 2.184 ;
     RECT  83.269 3.936 83.408 6.84 ;
     RECT  78.304 13.056 83.408 13.08 ;
     RECT  83.221 20.592 83.408 21.96 ;
     RECT  83.077 23.376 83.408 23.928 ;
     RECT  83.408 1.728 83.704 23.928 ;
     RECT  83.797 0.096 83.989 0.12 ;
     RECT  83.948 25.104 84.035 25.128 ;
     RECT  83.704 20.592 84.089 21.528 ;
     RECT  83.704 3.36 84.769 3.96 ;
     RECT  83.704 4.944 84.769 6.312 ;
     RECT  84.769 3.36 84.901 6.312 ;
     RECT  84.901 3.36 84.913 6.6 ;
     RECT  84.913 3.36 84.947 6.84 ;
     RECT  84.947 5.184 85.133 6.84 ;
     RECT  83.704 7.968 85.189 7.992 ;
     RECT  84.947 3.36 85.235 3.912 ;
     RECT  85.189 7.968 85.349 8.568 ;
     RECT  85.235 3.36 85.427 3.864 ;
     RECT  83.704 23.376 85.429 23.928 ;
     RECT  85.349 7.968 85.465 7.992 ;
     RECT  83.989 0.096 85.601 0.168 ;
     RECT  83.704 1.728 85.709 2.184 ;
     RECT  84.089 20.832 85.777 21.528 ;
     RECT  85.429 22.752 85.777 23.928 ;
     RECT  85.427 3.696 85.781 3.864 ;
     RECT  85.709 1.728 86.069 1.944 ;
     RECT  85.777 20.16 86.099 23.928 ;
     RECT  85.885 25.104 86.195 25.128 ;
     RECT  85.133 5.184 86.317 6.6 ;
     RECT  86.317 5.136 86.357 6.6 ;
     RECT  85.781 3.696 86.461 3.768 ;
     RECT  86.461 3.36 86.531 3.768 ;
     RECT  86.444 17.472 86.531 17.496 ;
     RECT  86.461 8.544 86.545 8.568 ;
     RECT  86.357 6.576 86.857 6.6 ;
     RECT  86.099 22.464 86.861 23.928 ;
     RECT  86.749 14.832 86.897 14.856 ;
     RECT  86.485 19.008 87.005 19.032 ;
     RECT  86.861 23.376 87.059 23.928 ;
     RECT  86.357 5.136 87.217 5.208 ;
     RECT  85.601 0.096 87.221 0.12 ;
     RECT  87.217 5.04 87.329 5.208 ;
     RECT  87.329 5.136 87.397 5.208 ;
     RECT  86.857 6.576 87.397 6.84 ;
     RECT  86.069 1.728 87.508 1.8 ;
     RECT  86.531 3.36 87.683 3.72 ;
     RECT  87.605 7.968 87.689 7.992 ;
     RECT  87.397 5.136 87.761 6.84 ;
     RECT  87.059 23.808 87.779 23.928 ;
     RECT  87.721 18.192 87.805 18.216 ;
     RECT  87.733 19.392 88.045 19.416 ;
     RECT  86.099 20.544 88.045 21.432 ;
     RECT  87.683 3.696 88.081 3.72 ;
     RECT  87.508 1.728 88.261 1.848 ;
     RECT  88.045 19.392 88.693 21.528 ;
     RECT  88.693 18.816 88.729 21.528 ;
     RECT  87.779 23.904 88.732 23.928 ;
     RECT  88.453 0.096 88.805 0.12 ;
     RECT  88.261 1.728 88.808 2.184 ;
     RECT  88.081 3.696 88.808 3.864 ;
     RECT  87.761 5.184 88.808 6.84 ;
     RECT  83.704 13.056 88.808 13.08 ;
     RECT  88.693 17.472 88.808 17.496 ;
     RECT  88.729 18.816 88.808 22.008 ;
     RECT  88.732 23.904 88.808 23.976 ;
     RECT  88.808 1.728 88.883 23.976 ;
     RECT  88.513 25.104 89.027 25.128 ;
     RECT  88.883 1.728 89.104 23.928 ;
     RECT  89.104 20.16 89.165 22.248 ;
     RECT  89.104 3.84 89.267 6.12 ;
     RECT  89.104 7.968 89.267 7.992 ;
     RECT  88.981 0.576 89.309 0.6 ;
     RECT  89.165 21.984 89.309 22.248 ;
     RECT  89.309 22.08 89.315 22.248 ;
     RECT  89.315 22.224 89.381 22.248 ;
     RECT  89.269 25.728 89.411 25.8 ;
     RECT  89.267 4.656 89.453 6.12 ;
     RECT  89.165 20.16 89.597 20.712 ;
     RECT  89.453 5.088 89.641 6.12 ;
     RECT  89.411 25.728 89.747 25.752 ;
     RECT  89.881 0.096 89.965 0.12 ;
     RECT  89.597 20.16 90.245 20.616 ;
     RECT  90.097 22.272 90.349 22.296 ;
     RECT  89.104 1.728 90.421 1.8 ;
     RECT  90.349 22.128 90.533 22.296 ;
     RECT  89.641 5.088 90.637 6.024 ;
     RECT  90.637 5.04 90.785 6.024 ;
     RECT  89.104 23.856 90.889 23.928 ;
     RECT  90.785 5.088 90.925 6.024 ;
     RECT  90.889 23.712 90.995 23.928 ;
     RECT  90.421 1.728 91.141 1.896 ;
     RECT  91.1 17.616 91.187 17.64 ;
     RECT  90.421 3.984 91.217 4.008 ;
     RECT  91.141 1.728 91.324 2.184 ;
     RECT  90.995 23.856 91.501 23.928 ;
     RECT  90.245 20.592 91.681 20.616 ;
     RECT  90.925 5.088 91.745 6.312 ;
     RECT  91.745 5.088 91.829 6.888 ;
     RECT  91.324 1.728 91.865 2.232 ;
     RECT  91.82 17.472 91.907 17.496 ;
     RECT  91.501 23.856 91.907 23.976 ;
     RECT  91.829 5.088 92.009 6.312 ;
     RECT  91.907 23.856 92.245 23.928 ;
     RECT  91.141 19.392 92.261 19.416 ;
     RECT  91.865 1.728 92.333 1.848 ;
     RECT  92.245 23.808 92.333 23.928 ;
     RECT  91.249 21.888 92.369 21.912 ;
     RECT  90.949 0.096 92.389 0.12 ;
     RECT  92.389 0.096 92.513 0.168 ;
     RECT  92.009 5.088 92.545 6.216 ;
     RECT  92.513 0.144 92.837 0.168 ;
     RECT  91.681 20.544 92.965 20.616 ;
     RECT  92.924 18.192 93.011 18.216 ;
     RECT  92.869 25.056 93.011 25.08 ;
     RECT  92.941 2.976 93.013 3 ;
     RECT  93.013 2.88 93.049 3 ;
     RECT  92.545 4.512 93.053 6.216 ;
     RECT  93.301 22.032 93.337 22.776 ;
     RECT  92.333 23.856 93.337 23.928 ;
     RECT  92.965 19.968 93.445 20.616 ;
     RECT  93.337 22.032 93.445 23.928 ;
     RECT  93.049 2.88 93.637 3.24 ;
     RECT  92.333 1.728 93.98 1.8 ;
     RECT  93.637 2.88 93.98 3.432 ;
     RECT  93.445 19.968 94.069 23.928 ;
     RECT  93.053 5.232 94.165 6.216 ;
     RECT  93.98 1.728 94.208 3.432 ;
     RECT  94.165 5.232 94.208 6.888 ;
     RECT  89.104 13.056 94.208 13.08 ;
     RECT  94.069 19.776 94.208 23.928 ;
     RECT  94.208 1.728 94.504 23.928 ;
     RECT  94.504 19.776 94.565 19.8 ;
     RECT  94.504 20.928 94.565 23.928 ;
     RECT  94.504 1.728 94.781 7.464 ;
     RECT  95.036 0.528 95.123 0.552 ;
     RECT  94.781 5.616 95.219 7.464 ;
     RECT  94.781 1.728 95.321 4.536 ;
     RECT  95.321 2.88 95.501 4.536 ;
     RECT  95.219 5.616 95.501 6.024 ;
     RECT  94.565 22.416 95.507 23.928 ;
     RECT  95.501 2.928 95.548 4.536 ;
     RECT  94.565 20.928 95.569 21.432 ;
     RECT  95.507 22.704 95.573 23.928 ;
     RECT  95.321 1.728 95.717 1.848 ;
     RECT  95.548 2.928 95.753 3.864 ;
     RECT  95.501 5.712 95.861 6.024 ;
     RECT  95.753 3.216 95.969 3.864 ;
     RECT  95.573 23.376 96.035 23.928 ;
     RECT  95.957 0.096 96.041 0.12 ;
     RECT  96.035 23.856 96.217 23.928 ;
     RECT  95.569 20.928 96.505 21.624 ;
     RECT  96.217 23.856 96.725 24.552 ;
     RECT  95.219 7.44 96.833 7.464 ;
     RECT  95.717 1.728 96.86 1.8 ;
     RECT  95.969 3.408 96.941 3.864 ;
     RECT  96.86 1.104 96.947 1.8 ;
     RECT  95.861 5.808 96.973 6.024 ;
     RECT  96.947 1.728 97.397 1.8 ;
     RECT  96.397 14.832 97.409 14.856 ;
     RECT  97.397 1.728 97.549 2.28 ;
     RECT  96.941 3.408 97.549 3.432 ;
     RECT  97.429 25.776 97.589 25.8 ;
     RECT  96.505 20.592 97.621 21.96 ;
     RECT  96.973 5.808 97.657 6.264 ;
     RECT  96.725 23.904 97.811 24.552 ;
     RECT  97.811 23.904 97.937 23.928 ;
     RECT  97.549 1.728 98.053 3.432 ;
     RECT  97.657 5.088 98.053 6.264 ;
     RECT  97.045 0.096 98.149 0.12 ;
     RECT  97.937 23.808 98.341 23.928 ;
     RECT  98.149 0.096 98.345 0.168 ;
     RECT  98.053 1.728 98.413 6.264 ;
     RECT  98.345 0.096 98.417 0.12 ;
     RECT  98.413 1.728 98.453 6.84 ;
     RECT  97.621 20.592 98.485 22.248 ;
     RECT  98.341 23.376 98.597 23.928 ;
     RECT  98.453 1.728 99.457 2.184 ;
     RECT  98.453 3.36 99.457 6.84 ;
     RECT  99.397 0.576 99.529 0.6 ;
     RECT  99.529 0.48 99.605 0.6 ;
     RECT  99.457 1.728 99.608 6.84 ;
     RECT  99.205 7.968 99.608 7.992 ;
     RECT  94.504 13.056 99.608 13.08 ;
     RECT  99.385 14.832 99.608 14.856 ;
     RECT  98.485 20.304 99.608 22.248 ;
     RECT  98.597 23.856 99.608 23.928 ;
     RECT  99.605 0.48 99.635 0.504 ;
     RECT  99.608 1.728 99.904 23.928 ;
     RECT  99.904 1.728 100.181 7.272 ;
     RECT  100.181 1.728 100.289 4.008 ;
     RECT  100.181 5.04 100.307 7.272 ;
     RECT  100.289 2.736 100.685 3 ;
     RECT  99.904 19.392 100.969 20.952 ;
     RECT  99.904 22.128 100.969 22.152 ;
     RECT  100.307 5.232 101.009 7.272 ;
     RECT  100.105 0.096 101.029 0.12 ;
     RECT  100.289 1.728 101.365 1.752 ;
     RECT  100.685 2.736 101.365 2.904 ;
     RECT  100.969 19.392 101.413 22.152 ;
     RECT  101.365 1.728 101.477 2.904 ;
     RECT  101.477 1.728 101.549 2.184 ;
     RECT  99.904 23.376 101.729 23.928 ;
     RECT  99.904 18.192 101.747 18.216 ;
     RECT  100.969 25.056 101.795 25.08 ;
     RECT  101.413 19.392 101.945 22.248 ;
     RECT  101.729 23.376 102.131 23.496 ;
     RECT  101.029 0.096 102.161 0.168 ;
     RECT  100.289 3.984 102.197 4.008 ;
     RECT  102.373 4.224 102.517 4.248 ;
     RECT  101.009 6 102.517 7.272 ;
     RECT  102.161 0.096 102.809 0.12 ;
     RECT  102.469 25.776 102.881 25.8 ;
     RECT  102.949 17.616 102.997 18.216 ;
     RECT  101.945 19.392 102.997 21.912 ;
     RECT  102.997 17.616 103.043 21.912 ;
     RECT  103.043 18.096 103.205 21.912 ;
     RECT  102.913 25.104 103.235 25.128 ;
     RECT  102.517 4.224 103.313 7.272 ;
     RECT  103.313 5.088 103.453 7.272 ;
     RECT  101.549 1.728 103.525 1.8 ;
     RECT  102.131 23.376 103.633 23.448 ;
     RECT  103.453 5.088 103.763 7.608 ;
     RECT  103.633 23.376 103.763 23.976 ;
     RECT  103.717 0.144 103.859 0.168 ;
     RECT  103.205 18.096 103.897 18.12 ;
     RECT  103.813 2.88 103.961 2.904 ;
     RECT  103.205 19.776 104.353 20.952 ;
     RECT  104.317 22.032 104.353 22.056 ;
     RECT  104.396 0.528 104.483 0.552 ;
     RECT  104.209 25.104 104.483 25.128 ;
     RECT  104.353 19.776 104.869 22.056 ;
     RECT  103.763 23.376 104.869 23.496 ;
     RECT  103.763 5.088 104.893 7.128 ;
     RECT  104.869 19.776 104.924 23.496 ;
     RECT  103.525 1.728 105.008 1.848 ;
     RECT  104.893 4.512 105.008 7.128 ;
     RECT  99.904 13.056 105.008 13.08 ;
     RECT  104.677 18.192 105.008 18.216 ;
     RECT  104.924 19.776 105.008 23.928 ;
     RECT  105.008 1.728 105.304 23.928 ;
     RECT  105.304 23.376 105.365 23.928 ;
     RECT  105.304 1.728 105.437 1.8 ;
     RECT  105.304 2.832 105.443 5.112 ;
     RECT  105.304 6.096 105.443 7.128 ;
     RECT  105.304 11.904 105.443 13.08 ;
     RECT  105.304 14.64 105.443 14.808 ;
     RECT  105.443 6.096 105.501 6.84 ;
     RECT  105.443 14.784 105.553 14.808 ;
     RECT  105.443 4.512 105.653 5.112 ;
     RECT  105.443 11.904 105.653 12.552 ;
     RECT  105.443 2.832 105.869 3.528 ;
     RECT  105.869 2.832 105.905 3.432 ;
     RECT  105.877 0.096 106.021 0.12 ;
     RECT  105.304 18 106.067 18.024 ;
     RECT  105.304 19.392 106.229 22.248 ;
     RECT  106.229 19.392 106.301 19.464 ;
     RECT  105.157 25.776 106.301 25.8 ;
     RECT  106.229 20.592 106.307 22.248 ;
     RECT  106.021 0.096 106.337 0.168 ;
     RECT  105.905 2.832 106.337 2.856 ;
     RECT  106.307 22.032 106.373 22.248 ;
     RECT  105.437 1.728 106.405 1.752 ;
     RECT  106.373 22.032 106.409 22.056 ;
     RECT  106.307 20.592 106.445 20.952 ;
     RECT  106.441 25.104 106.513 25.128 ;
     RECT  106.513 25.056 106.643 25.128 ;
     RECT  105.501 6.528 106.657 6.84 ;
     RECT  105.653 5.04 106.733 5.112 ;
     RECT  106.643 25.056 106.787 25.08 ;
     RECT  105.365 23.376 107.084 23.448 ;
     RECT  106.405 1.728 107.089 1.8 ;
     RECT  107.089 1.728 107.173 1.944 ;
     RECT  107.084 23.376 107.269 23.496 ;
     RECT  107.269 23.376 107.377 23.736 ;
     RECT  106.657 6.144 107.413 6.84 ;
     RECT  106.445 20.592 107.42 20.616 ;
     RECT  106.301 19.44 107.441 19.464 ;
     RECT  107.42 20.592 107.449 20.808 ;
     RECT  107.413 6.144 107.453 7.368 ;
     RECT  105.653 11.904 107.459 11.928 ;
     RECT  107.377 23.376 107.507 23.928 ;
     RECT  107.441 19.344 107.525 19.464 ;
     RECT  107.173 1.728 107.705 1.848 ;
     RECT  107.507 23.376 107.741 23.736 ;
     RECT  107.449 20.592 107.773 21.192 ;
     RECT  107.729 3.984 107.813 4.008 ;
     RECT  106.733 5.04 108.061 5.064 ;
     RECT  106.337 0.096 108.137 0.12 ;
     RECT  107.773 19.68 108.601 21.192 ;
     RECT  108.061 4.992 108.673 5.064 ;
     RECT  107.453 6.528 108.673 7.368 ;
     RECT  107.705 1.728 108.709 1.8 ;
     RECT  107.741 23.376 108.709 23.448 ;
     RECT  108.601 19.68 108.785 21.672 ;
     RECT  108.709 23.376 108.901 23.544 ;
     RECT  108.673 4.224 108.957 5.064 ;
     RECT  108.637 25.104 109.139 25.128 ;
     RECT  108.709 1.728 109.285 2.184 ;
     RECT  108.957 4.224 109.321 4.824 ;
     RECT  108.785 20.592 109.393 21.672 ;
     RECT  108.901 23.376 109.429 23.88 ;
     RECT  109.421 0.096 109.505 0.12 ;
     RECT  108.673 6.288 109.565 7.368 ;
     RECT  109.393 20.592 109.573 22.008 ;
     RECT  109.429 23.376 109.573 23.928 ;
     RECT  109.321 3.936 109.753 4.824 ;
     RECT  109.285 1.728 110.149 2.904 ;
     RECT  109.717 19.344 110.293 19.368 ;
     RECT  109.573 20.592 110.293 23.928 ;
     RECT  110.149 1.68 110.408 2.904 ;
     RECT  109.753 3.888 110.408 4.824 ;
     RECT  109.565 6.288 110.408 7.992 ;
     RECT  110.293 19.344 110.408 23.928 ;
     RECT  110.408 1.68 110.545 23.928 ;
     RECT  110.293 25.728 110.579 25.752 ;
     RECT  110.545 1.68 110.585 24.552 ;
     RECT  110.585 1.728 110.704 24.552 ;
     RECT  110.704 19.344 110.723 24.552 ;
     RECT  110.723 19.344 110.819 23.928 ;
     RECT  110.819 19.824 110.915 23.928 ;
     RECT  110.704 3.408 111.125 5.448 ;
     RECT  110.704 6.432 111.197 7.368 ;
     RECT  110.915 19.824 111.269 21.144 ;
     RECT  110.869 0.576 111.635 0.6 ;
     RECT  110.915 22.704 111.701 23.928 ;
     RECT  110.704 1.728 111.733 2.184 ;
     RECT  111.697 25.104 111.827 25.128 ;
     RECT  111.125 4.224 111.925 5.448 ;
     RECT  111.197 6.432 111.925 7.32 ;
     RECT  111.925 4.224 111.971 7.32 ;
     RECT  111.733 1.728 112.457 2.328 ;
     RECT  111.701 23.328 112.457 23.928 ;
     RECT  112.457 23.376 112.781 23.928 ;
     RECT  112.457 1.728 112.796 1.752 ;
     RECT  111.269 20.544 112.849 21.144 ;
     RECT  112.796 1.152 112.917 1.752 ;
     RECT  112.837 25.056 112.979 25.08 ;
     RECT  111.971 4.224 113.177 4.248 ;
     RECT  112.849 20.16 113.177 21.144 ;
     RECT  112.813 2.88 113.213 2.904 ;
     RECT  111.971 5.664 113.281 7.32 ;
     RECT  112.917 1.728 113.605 1.752 ;
     RECT  112.781 23.376 113.9 23.496 ;
     RECT  113.177 20.16 114.113 21.048 ;
     RECT  113.281 5.04 114.323 7.32 ;
     RECT  113.353 3.936 114.565 3.96 ;
     RECT  114.323 5.04 114.565 6.648 ;
     RECT  113.9 23.376 114.613 23.544 ;
     RECT  113.605 1.728 114.661 2.28 ;
     RECT  111.877 22.176 114.805 22.2 ;
     RECT  114.613 23.376 114.805 23.928 ;
     RECT  112.481 0.096 115.049 0.12 ;
     RECT  115.045 25.056 115.427 25.08 ;
     RECT  114.661 1.728 115.808 2.328 ;
     RECT  114.565 3.936 115.808 6.648 ;
     RECT  115.297 8.544 115.808 8.568 ;
     RECT  114.113 20.592 115.808 21.048 ;
     RECT  114.805 22.176 115.808 23.928 ;
     RECT  115.808 1.728 116.104 23.928 ;
     RECT  116.104 1.728 116.243 7.32 ;
     RECT  116.101 25.728 116.243 25.752 ;
     RECT  116.243 3.408 116.281 7.32 ;
     RECT  116.281 3.408 116.525 6.648 ;
     RECT  116.525 4.272 116.597 6.648 ;
     RECT  116.104 23.376 116.597 23.928 ;
     RECT  116.437 0.096 116.732 0.12 ;
     RECT  116.597 23.424 116.741 23.928 ;
     RECT  116.732 0.096 116.819 0.552 ;
     RECT  116.597 6.528 116.849 6.648 ;
     RECT  116.243 1.728 117.011 2.28 ;
     RECT  116.104 20.16 117.677 22.2 ;
     RECT  116.741 23.856 117.817 23.928 ;
     RECT  116.597 4.272 117.961 5.496 ;
     RECT  116.849 6.528 117.961 6.6 ;
     RECT  117.961 4.272 118.097 6.6 ;
     RECT  116.965 25.776 118.109 25.8 ;
     RECT  118.097 4.272 118.181 6.888 ;
     RECT  117.817 23.856 118.259 24.552 ;
     RECT  116.819 0.096 118.573 0.12 ;
     RECT  118.181 4.272 118.717 6.552 ;
     RECT  118.573 0.096 118.979 0.552 ;
     RECT  118.969 25.104 119.171 25.128 ;
     RECT  118.259 23.856 119.185 23.928 ;
     RECT  119.185 23.376 119.363 23.928 ;
     RECT  117.677 20.304 119.509 22.2 ;
     RECT  119.509 20.112 119.555 22.2 ;
     RECT  118.717 3.936 119.653 6.552 ;
     RECT  117.011 1.728 119.725 1.8 ;
     RECT  119.363 23.808 119.737 23.928 ;
     RECT  119.725 1.728 119.761 2.712 ;
     RECT  119.653 3.936 119.761 6.84 ;
     RECT  119.701 8.544 119.801 8.568 ;
     RECT  119.761 1.728 119.873 6.84 ;
     RECT  119.873 2.928 119.909 6.84 ;
     RECT  120.545 25.776 120.629 25.8 ;
     RECT  119.555 21.504 120.757 22.2 ;
     RECT  119.909 2.928 121.093 6.552 ;
     RECT  118.979 0.096 121.205 0.168 ;
     RECT  119.873 1.728 121.208 1.848 ;
     RECT  121.093 2.928 121.208 6.648 ;
     RECT  119.555 20.112 121.208 20.52 ;
     RECT  120.757 21.504 121.208 22.776 ;
     RECT  119.737 23.856 121.208 23.928 ;
     RECT  121.208 1.728 121.504 23.928 ;
     RECT  121.129 25.104 121.523 25.128 ;
     RECT  121.504 22.752 121.565 22.776 ;
     RECT  121.205 0.144 121.619 0.168 ;
     RECT  121.504 20.016 121.637 21.528 ;
     RECT  121.504 3.936 122.249 6.84 ;
     RECT  121.504 23.856 122.425 23.928 ;
     RECT  122.249 3.936 122.533 4.008 ;
     RECT  122.425 23.856 122.579 24.552 ;
     RECT  122.533 3.696 122.62 4.008 ;
     RECT  122.341 0.096 122.725 0.12 ;
     RECT  121.637 20.016 122.753 20.856 ;
     RECT  122.249 5.088 122.825 6.84 ;
     RECT  122.62 3.696 122.893 3.96 ;
     RECT  122.579 23.856 122.917 23.928 ;
     RECT  122.917 23.808 123.001 23.928 ;
     RECT  121.504 1.728 123.061 1.8 ;
     RECT  122.893 3.552 123.113 3.96 ;
     RECT  123.001 23.76 123.212 23.928 ;
     RECT  122.725 0.096 123.257 0.168 ;
     RECT  122.825 5.472 123.361 6.84 ;
     RECT  123.061 1.728 123.397 2.184 ;
     RECT  123.361 5.472 123.445 6.888 ;
     RECT  123.212 23.376 123.577 23.928 ;
     RECT  123.577 23.376 123.634 24.552 ;
     RECT  123.445 5.472 123.653 6.84 ;
     RECT  122.677 22.176 123.653 22.2 ;
     RECT  122.753 20.016 123.761 20.616 ;
     RECT  123.397 1.728 123.793 2.232 ;
     RECT  123.653 6.528 123.977 6.84 ;
     RECT  123.685 25.776 124.019 25.8 ;
     RECT  123.113 3.888 124.081 3.96 ;
     RECT  124.009 8.544 124.093 8.568 ;
     RECT  124.081 3.888 124.157 5.448 ;
     RECT  123.634 23.328 124.193 24.552 ;
     RECT  124.157 4.512 124.259 5.448 ;
     RECT  124.193 23.376 124.355 24.552 ;
     RECT  124.355 23.376 124.547 23.928 ;
     RECT  123.761 20.016 124.873 20.568 ;
     RECT  124.873 20.016 124.985 21.096 ;
     RECT  123.793 1.728 125.017 2.904 ;
     RECT  124.259 5.424 125.461 5.448 ;
     RECT  125.413 25.776 125.525 25.8 ;
     RECT  125.461 5.376 125.548 5.448 ;
     RECT  123.977 6.528 125.701 6.744 ;
     RECT  124.985 21.024 125.804 21.096 ;
     RECT  124.729 22.176 125.804 22.2 ;
     RECT  125.804 21.024 125.845 22.2 ;
     RECT  125.548 5.424 125.881 5.448 ;
     RECT  125.701 6.528 125.881 7.464 ;
     RECT  124.985 20.016 125.893 20.04 ;
     RECT  125.017 1.728 126.097 3.096 ;
     RECT  123.257 0.096 126.385 0.12 ;
     RECT  124.547 23.808 126.449 23.928 ;
     RECT  126.097 1.728 126.493 3.864 ;
     RECT  126.493 1.728 126.608 3.912 ;
     RECT  125.881 5.424 126.608 7.464 ;
     RECT  125.893 19.68 126.608 20.04 ;
     RECT  125.845 21.024 126.608 22.44 ;
     RECT  126.449 23.712 126.608 23.928 ;
     RECT  126.608 1.728 126.904 23.928 ;
     RECT  126.385 0.096 127.043 0.552 ;
     RECT  126.904 2.832 127.043 6.552 ;
     RECT  127.043 3.552 127.091 3.864 ;
     RECT  126.904 7.968 127.091 8.184 ;
     RECT  126.904 20.016 127.109 21.144 ;
     RECT  127.109 20.016 127.132 21.048 ;
     RECT  127.043 5.568 127.505 6.552 ;
     RECT  127.091 7.968 127.721 7.992 ;
     RECT  126.904 1.728 127.9 1.752 ;
     RECT  126.904 22.128 127.955 23.928 ;
     RECT  127.132 20.016 128.053 20.76 ;
     RECT  127.9 1.728 128.101 1.8 ;
     RECT  128.053 19.68 128.149 20.76 ;
     RECT  127.955 22.128 128.149 22.824 ;
     RECT  128.149 19.68 128.189 22.824 ;
     RECT  128.189 21.504 128.225 22.824 ;
     RECT  128.101 1.728 128.257 2.184 ;
     RECT  127.091 3.552 128.257 3.768 ;
     RECT  128.225 21.504 128.339 22.2 ;
     RECT  127.505 5.664 128.621 6.552 ;
     RECT  127.955 23.856 128.689 23.928 ;
     RECT  127.043 0.096 128.821 0.12 ;
     RECT  128.689 23.856 128.867 23.976 ;
     RECT  128.339 21.504 129.053 22.152 ;
     RECT  128.257 1.728 129.089 3.864 ;
     RECT  129.089 3.84 129.193 3.864 ;
     RECT  128.821 0.096 129.233 0.6 ;
     RECT  128.867 23.856 129.308 23.928 ;
     RECT  129.193 3.84 129.341 4.68 ;
     RECT  128.621 6.528 129.697 6.552 ;
     RECT  129.233 0.096 129.881 0.12 ;
     RECT  129.308 23.376 129.923 23.928 ;
     RECT  129.341 3.888 130.067 4.68 ;
     RECT  129.985 8.544 130.069 8.568 ;
     RECT  129.089 1.728 130.097 2.184 ;
     RECT  129.053 21.504 130.169 22.056 ;
     RECT  130.067 4.512 130.201 4.68 ;
     RECT  128.189 19.68 130.237 20.04 ;
     RECT  130.169 21.504 130.313 21.912 ;
     RECT  130.237 19.392 130.453 20.04 ;
     RECT  129.697 6.48 130.525 6.552 ;
     RECT  129.157 25.776 130.705 25.8 ;
     RECT  130.705 25.056 130.853 25.8 ;
     RECT  129.923 23.904 130.94 23.928 ;
     RECT  130.885 2.88 130.997 2.904 ;
     RECT  130.94 23.376 131.027 23.928 ;
     RECT  130.853 25.056 131.363 25.08 ;
     RECT  131.093 0.096 131.393 0.12 ;
     RECT  130.313 21.888 131.425 21.912 ;
     RECT  130.201 4.512 131.468 5.112 ;
     RECT  131.425 21.888 131.497 22.056 ;
     RECT  130.097 1.728 131.509 1.848 ;
     RECT  131.389 2.832 131.509 2.856 ;
     RECT  130.525 6.48 131.893 6.84 ;
     RECT  130.453 19.392 131.893 20.856 ;
     RECT  131.497 21.888 131.893 22.776 ;
     RECT  131.027 23.76 131.965 23.928 ;
     RECT  131.509 1.728 132.008 2.856 ;
     RECT  131.468 3.936 132.008 5.112 ;
     RECT  131.893 6.48 132.008 6.936 ;
     RECT  131.893 17.616 132.008 17.64 ;
     RECT  131.893 19.392 132.008 22.776 ;
     RECT  131.965 23.76 132.008 24.504 ;
     RECT  131.893 25.728 132.083 25.752 ;
     RECT  131.701 0.576 132.185 0.6 ;
     RECT  132.008 1.728 132.304 24.504 ;
     RECT  132.304 18.768 132.365 24.504 ;
     RECT  132.304 17.616 132.419 17.64 ;
     RECT  132.365 18.768 132.445 21.672 ;
     RECT  132.445 18.768 132.509 21.432 ;
     RECT  132.365 22.752 132.611 24.504 ;
     RECT  132.509 18.768 132.707 20.76 ;
     RECT  132.304 1.728 132.803 2.28 ;
     RECT  132.611 22.752 132.905 23.928 ;
     RECT  132.905 23.376 133.139 23.928 ;
     RECT  132.304 3.408 133.477 5.208 ;
     RECT  132.803 1.728 133.553 2.184 ;
     RECT  132.707 19.344 133.585 20.76 ;
     RECT  134.06 18 134.147 18.024 ;
     RECT  133.139 23.712 134.156 23.928 ;
     RECT  133.477 3.264 134.237 5.208 ;
     RECT  134.156 23.376 134.243 23.928 ;
     RECT  134.237 3.84 134.245 5.208 ;
     RECT  134.245 3.84 134.332 5.736 ;
     RECT  132.304 6.816 134.377 7.032 ;
     RECT  134.3 13.632 134.387 13.656 ;
     RECT  134.377 6.24 134.389 7.032 ;
     RECT  133.585 19.344 134.413 21.192 ;
     RECT  134.389 6.24 134.461 7.656 ;
     RECT  134.341 18.24 134.525 18.264 ;
     RECT  134.413 19.248 134.633 21.192 ;
     RECT  134.633 21.168 134.665 21.192 ;
     RECT  134.665 21.168 134.705 21.672 ;
     RECT  134.332 3.84 135.137 5.208 ;
     RECT  133.553 1.728 135.445 1.8 ;
     RECT  134.005 25.776 135.637 25.8 ;
     RECT  135.445 1.728 135.677 1.896 ;
     RECT  134.461 6.864 135.709 7.656 ;
     RECT  134.705 21.648 135.749 21.672 ;
     RECT  134.243 23.808 135.788 23.928 ;
     RECT  135.137 3.84 135.821 3.864 ;
     RECT  135.637 0.576 136.001 0.6 ;
     RECT  134.633 19.248 136.213 20.04 ;
     RECT  136.213 19.248 136.22 20.568 ;
     RECT  136.22 19.248 136.307 21 ;
     RECT  135.137 5.184 136.393 5.208 ;
     RECT  135.709 6.24 136.393 7.656 ;
     RECT  136.307 19.248 136.453 20.568 ;
     RECT  135.637 25.728 136.595 25.8 ;
     RECT  135.677 1.728 136.673 1.8 ;
     RECT  136.595 25.776 136.739 25.8 ;
     RECT  136.165 0.096 137.117 0.216 ;
     RECT  137.117 0.144 137.225 0.216 ;
     RECT  136.673 1.728 137.408 1.848 ;
     RECT  136.393 5.184 137.408 7.656 ;
     RECT  136.453 18.576 137.408 20.568 ;
     RECT  135.788 23.376 137.408 23.928 ;
     RECT  137.225 0.192 137.413 0.216 ;
     RECT  137.408 1.728 137.413 23.928 ;
     RECT  137.413 1.728 137.704 23.976 ;
     RECT  137.704 1.728 137.843 6.84 ;
     RECT  137.843 1.728 137.873 6.024 ;
     RECT  137.704 23.328 137.909 23.976 ;
     RECT  137.413 0.192 137.941 0.312 ;
     RECT  137.941 0.192 138.025 0.6 ;
     RECT  137.704 17.616 138.349 21 ;
     RECT  137.909 23.328 138.563 23.928 ;
     RECT  137.873 3.36 138.805 6.024 ;
     RECT  138.805 3.36 138.877 6.888 ;
     RECT  138.349 18.192 138.947 21 ;
     RECT  138.877 3.36 138.953 7.224 ;
     RECT  138.563 23.376 138.985 23.928 ;
     RECT  138.947 20.976 138.989 21 ;
     RECT  138.953 3.84 139.021 7.224 ;
     RECT  137.704 8.544 139.097 8.568 ;
     RECT  137.873 1.728 139.129 2.328 ;
     RECT  139.021 3.84 139.129 7.416 ;
     RECT  139.129 3.84 139.205 8.472 ;
     RECT  139.129 1.728 139.213 2.856 ;
     RECT  139.205 3.84 139.277 3.96 ;
     RECT  138.985 23.376 139.283 23.976 ;
     RECT  139.213 1.728 139.385 2.28 ;
     RECT  139.205 5.184 139.523 8.472 ;
     RECT  138.661 0.096 139.849 0.168 ;
     RECT  139.523 6.672 139.925 8.472 ;
     RECT  138.947 19.872 140.249 19.896 ;
     RECT  139.849 0.096 140.453 0.552 ;
     RECT  139.925 6.816 140.453 8.472 ;
     RECT  139.277 3.936 140.461 3.96 ;
     RECT  139.523 5.184 140.461 5.208 ;
     RECT  140.461 3.888 140.485 5.208 ;
     RECT  140.101 25.776 140.537 25.8 ;
     RECT  140.485 3.888 140.581 5.304 ;
     RECT  140.453 6.816 140.609 8.568 ;
     RECT  140.029 17.616 140.609 18.264 ;
     RECT  140.581 3.12 140.627 5.304 ;
     RECT  140.561 9.696 140.645 9.72 ;
     RECT  140.609 6.864 140.653 8.568 ;
     RECT  139.283 23.376 140.785 23.928 ;
     RECT  139.385 1.728 140.789 1.8 ;
     RECT  140.653 8.544 140.929 8.568 ;
     RECT  140.627 3.12 140.933 4.632 ;
     RECT  140.785 23.376 140.965 24.552 ;
     RECT  140.453 0.096 140.969 0.6 ;
     RECT  140.965 22.8 141.059 24.552 ;
     RECT  140.969 0.144 141.109 0.6 ;
     RECT  140.789 1.728 141.109 1.752 ;
     RECT  140.929 8.544 141.121 9.144 ;
     RECT  141.121 9.12 141.155 9.144 ;
     RECT  140.933 3.408 141.251 4.632 ;
     RECT  141.059 22.8 141.251 23.928 ;
     RECT  140.653 6.864 141.265 7.464 ;
     RECT  141.265 6.864 141.329 6.888 ;
     RECT  141.251 23.904 141.437 23.928 ;
     RECT  141.251 4.608 141.473 4.632 ;
     RECT  141.109 0.144 141.509 1.752 ;
     RECT  141.251 3.408 141.779 3.432 ;
     RECT  141.251 22.8 141.779 22.824 ;
     RECT  141.509 0.144 141.977 1.176 ;
     RECT  141.977 0.144 142.253 0.6 ;
     RECT  142.253 0.096 142.337 0.6 ;
     RECT  142.337 0.576 142.499 0.6 ;
     RECT  141.533 25.776 142.517 25.8 ;
    LAYER M5 ;
     RECT  0.048 0.016 142.488 0.611 ;
     RECT  0.048 0.611 141.96 1.187 ;
     RECT  0.048 1.187 141.768 1.763 ;
     RECT  2.4 1.763 11.928 1.811 ;
     RECT  12.96 1.763 21.576 1.811 ;
     RECT  26.592 1.763 33.24 1.811 ;
     RECT  34.8 1.763 53.544 1.811 ;
     RECT  54.576 1.763 58.536 1.811 ;
     RECT  60.336 1.763 84.168 1.811 ;
     RECT  85.44 1.763 99.96 1.811 ;
     RECT  101.184 1.763 112.344 1.811 ;
     RECT  113.76 1.763 119.16 1.811 ;
     RECT  127.92 1.763 128.664 1.811 ;
     RECT  129.888 1.763 138.84 1.811 ;
     RECT  140.304 1.763 140.568 1.811 ;
     RECT  6.144 1.811 8.52 1.859 ;
     RECT  10.656 1.811 11.4 1.859 ;
     RECT  17.616 1.811 21.576 1.859 ;
     RECT  24 1.763 24.456 1.859 ;
     RECT  26.592 1.811 31.656 1.859 ;
     RECT  37.008 1.811 47.784 1.859 ;
     RECT  49.392 1.811 53.544 1.859 ;
     RECT  58.512 1.811 58.536 1.859 ;
     RECT  60.336 1.811 62.664 1.859 ;
     RECT  66.576 1.811 67.512 1.859 ;
     RECT  76.272 1.811 79.176 1.859 ;
     RECT  87.552 1.811 89.112 1.859 ;
     RECT  90.432 1.811 92.28 1.859 ;
     RECT  93.648 1.811 96.408 1.859 ;
     RECT  98.496 1.811 99.96 1.859 ;
     RECT  103.536 1.811 105.72 1.859 ;
     RECT  120.192 1.763 126.912 1.859 ;
     RECT  129.888 1.811 133.32 1.859 ;
     RECT  136.704 1.811 138.84 1.859 ;
     RECT  2.4 1.811 4.008 1.907 ;
     RECT  5.088 1.811 5.112 1.907 ;
     RECT  17.616 1.859 20.52 1.907 ;
     RECT  28.56 1.859 31.656 1.907 ;
     RECT  53.52 1.859 53.544 1.907 ;
     RECT  68.928 1.811 69.48 1.907 ;
     RECT  77.184 1.859 79.176 1.907 ;
     RECT  80.736 1.811 80.76 1.907 ;
     RECT  90.432 1.859 91.368 1.907 ;
     RECT  98.496 1.859 99.912 1.907 ;
     RECT  131.52 1.859 132.984 1.907 ;
     RECT  135.456 1.811 135.48 1.907 ;
     RECT  10.8 1.859 11.4 1.955 ;
     RECT  37.008 1.859 47.064 1.955 ;
     RECT  85.44 1.811 85.992 1.955 ;
     RECT  107.136 1.811 112.344 1.955 ;
     RECT  82.032 1.811 84.168 2.099 ;
     RECT  9.552 1.811 9.576 2.195 ;
     RECT  11.376 1.955 11.4 2.195 ;
     RECT  15.312 1.811 15.336 2.195 ;
     RECT  21.552 1.859 21.576 2.195 ;
     RECT  26.592 1.859 27 2.195 ;
     RECT  28.56 1.907 30.552 2.195 ;
     RECT  31.632 1.907 31.656 2.195 ;
     RECT  37.008 1.955 38.808 2.195 ;
     RECT  49.536 1.859 49.56 2.195 ;
     RECT  52.416 1.859 52.44 2.195 ;
     RECT  69.264 1.907 69.48 2.195 ;
     RECT  82.56 2.099 84.168 2.195 ;
     RECT  85.44 1.955 85.464 2.195 ;
     RECT  88.272 1.859 89.112 2.195 ;
     RECT  91.152 1.907 91.368 2.195 ;
     RECT  98.496 1.907 98.52 2.195 ;
     RECT  101.184 1.811 101.4 2.195 ;
     RECT  107.76 1.955 112.344 2.195 ;
     RECT  128.112 1.811 128.664 2.195 ;
     RECT  129.888 1.859 129.912 2.195 ;
     RECT  132 1.907 132.984 2.195 ;
     RECT  91.344 2.195 91.368 2.243 ;
     RECT  7.8 1.859 8.52 2.291 ;
     RECT  13.2 1.811 14.232 2.291 ;
     RECT  17.808 1.907 20.52 2.291 ;
     RECT  26.64 2.195 27 2.291 ;
     RECT  37.008 2.195 37.032 2.291 ;
     RECT  40.08 1.955 47.064 2.291 ;
     RECT  55.632 1.811 57.288 2.291 ;
     RECT  61.008 1.859 62.664 2.291 ;
     RECT  69.456 2.195 69.48 2.291 ;
     RECT  71.232 1.811 71.256 2.291 ;
     RECT  72.6 1.811 75.24 2.291 ;
     RECT  97.44 1.811 97.464 2.291 ;
     RECT  113.952 1.811 117 2.291 ;
     RECT  121.2 1.859 126.912 2.291 ;
     RECT  132 2.195 132.792 2.291 ;
     RECT  17.808 2.291 19.608 2.339 ;
     RECT  40.08 2.291 42.36 2.339 ;
     RECT  44.544 2.291 47.064 2.339 ;
     RECT  64.992 1.811 65.016 2.339 ;
     RECT  77.184 1.907 78.312 2.339 ;
     RECT  110.4 2.195 112.344 2.339 ;
     RECT  114.672 2.291 116.232 2.339 ;
     RECT  137.4 1.859 138.84 2.339 ;
     RECT  34.8 1.811 35.784 2.821 ;
     RECT  125.712 2.291 126.912 2.821 ;
     RECT  138.816 2.339 138.84 2.821 ;
     RECT  6.144 1.859 6.168 2.915 ;
     RECT  17.808 2.339 18.912 2.915 ;
     RECT  34.272 2.821 35.784 2.915 ;
     RECT  44.544 2.339 45.912 2.915 ;
     RECT  56.4 2.291 57.288 2.915 ;
     RECT  61.008 2.291 62.112 2.915 ;
     RECT  63.888 1.811 63.912 2.915 ;
     RECT  72.6 2.291 75.048 2.915 ;
     RECT  93.648 1.859 95.304 2.915 ;
     RECT  101.184 2.195 101.208 2.915 ;
     RECT  103.824 1.859 103.848 2.915 ;
     RECT  109.296 2.195 109.32 2.915 ;
     RECT  44.688 2.915 45.912 2.963 ;
     RECT  75.024 2.915 75.048 2.963 ;
     RECT  2.4 1.907 3.864 3.061 ;
     RECT  140.544 1.811 140.568 3.109 ;
     RECT  38.256 2.195 38.808 3.157 ;
     RECT  40.08 2.339 41.352 3.157 ;
     RECT  31.68 3.157 31.704 3.205 ;
     RECT  33.216 1.811 33.24 3.205 ;
     RECT  105 1.859 105.72 3.205 ;
     RECT  121.2 2.291 123.432 3.301 ;
     RECT  137.4 2.339 137.832 3.349 ;
     RECT  138.816 2.821 139.176 3.349 ;
     RECT  2.304 3.061 3.864 3.397 ;
     RECT  7.8 2.291 8.424 3.397 ;
     RECT  24 1.859 24.312 3.397 ;
     RECT  72.6 2.915 72.912 3.397 ;
     RECT  83.4 2.195 83.712 3.397 ;
     RECT  98.448 3.349 98.472 3.397 ;
     RECT  99.6 1.907 99.912 3.397 ;
     RECT  132 2.291 132.312 3.397 ;
     RECT  140.544 3.109 140.616 3.397 ;
     RECT  141.744 1.763 141.768 3.397 ;
     RECT  28.56 2.195 29.712 3.443 ;
     RECT  31.68 3.205 33.24 3.443 ;
     RECT  47.04 2.339 47.064 3.443 ;
     RECT  56.4 2.915 57.096 3.443 ;
     RECT  77.52 2.339 78.312 3.443 ;
     RECT  93.648 2.915 94.512 3.443 ;
     RECT  96.384 1.859 96.408 3.443 ;
     RECT  110.4 2.339 111.096 3.443 ;
     RECT  140.544 3.397 141.768 3.443 ;
     RECT  51 1.859 51.312 3.685 ;
     RECT  45.6 2.963 45.912 3.733 ;
     RECT  125.712 2.821 127.032 3.733 ;
     RECT  23.28 3.397 24.312 3.781 ;
     RECT  56.4 3.443 56.712 3.781 ;
     RECT  88.8 2.195 89.112 3.829 ;
     RECT  83.4 3.397 84.12 3.877 ;
     RECT  85.392 3.349 85.416 3.877 ;
     RECT  120.336 3.301 123.432 3.877 ;
     RECT  26.64 2.291 26.664 3.925 ;
     RECT  83.4 3.877 85.416 3.925 ;
     RECT  110.4 3.443 110.712 3.925 ;
     RECT  132 3.397 133.176 3.925 ;
     RECT  38.256 3.157 41.352 4.019 ;
     RECT  107.76 2.195 107.784 4.019 ;
     RECT  120.336 3.877 124.056 4.019 ;
     RECT  23.28 3.781 24.456 4.163 ;
     RECT  7.632 3.397 8.424 4.261 ;
     RECT  26.64 3.925 27.336 4.261 ;
     RECT  78 3.443 78.312 4.261 ;
     RECT  23.28 4.163 24.408 4.309 ;
     RECT  0.048 1.763 1.32 4.451 ;
     RECT  31.68 3.443 32.616 4.453 ;
     RECT  10.416 3.925 10.44 4.501 ;
     RECT  12 3.925 12.024 4.501 ;
     RECT  34.272 2.915 35.256 4.501 ;
     RECT  50.88 3.685 51.312 4.501 ;
     RECT  59.808 3.685 59.832 4.501 ;
     RECT  94.2 3.443 94.512 4.501 ;
     RECT  114.576 3.925 114.6 4.501 ;
     RECT  115.8 2.339 116.232 4.501 ;
     RECT  120.336 4.019 121.992 4.501 ;
     RECT  123.408 4.019 124.056 4.501 ;
     RECT  131.52 3.925 133.176 4.547 ;
     RECT  64.272 3.829 64.296 4.549 ;
     RECT  98.448 3.397 99.912 4.595 ;
     RECT  132 4.547 133.176 4.691 ;
     RECT  13.2 2.291 13.512 4.693 ;
     RECT  78 4.261 78.552 4.693 ;
     RECT  0.432 4.451 1.32 4.739 ;
     RECT  80.496 3.925 80.52 4.885 ;
     RECT  119.712 4.501 121.992 4.931 ;
     RECT  114.576 4.501 116.232 4.979 ;
     RECT  98.592 4.595 99.912 5.029 ;
     RECT  109.584 3.925 110.712 5.029 ;
     RECT  80.352 4.885 80.52 5.075 ;
     RECT  105 3.205 105.864 5.075 ;
     RECT  64.272 4.549 64.968 5.123 ;
     RECT  28.32 3.733 28.344 5.125 ;
     RECT  29.4 3.443 29.712 5.125 ;
     RECT  103.92 5.077 103.944 5.125 ;
     RECT  26.4 4.261 27.336 5.171 ;
     RECT  81.984 4.261 82.008 5.171 ;
     RECT  134.4 1.811 134.424 5.171 ;
     RECT  80.352 5.075 80.424 5.173 ;
     RECT  49.968 4.501 51.312 5.219 ;
     RECT  59.808 4.501 60.216 5.219 ;
     RECT  64.896 5.123 64.968 5.219 ;
     RECT  61.8 2.915 62.112 5.221 ;
     RECT  140.544 3.443 141.24 5.269 ;
     RECT  28.32 5.125 29.712 5.315 ;
     RECT  33.744 4.501 36.168 5.315 ;
     RECT  91.824 5.077 91.848 5.317 ;
     RECT  61.68 5.221 62.112 5.365 ;
     RECT  63.12 5.077 63.144 5.365 ;
     RECT  87.648 3.349 87.672 5.365 ;
     RECT  88.8 3.829 89.256 5.365 ;
     RECT  114.576 4.979 116.112 5.365 ;
     RECT  125.712 3.733 127.704 5.365 ;
     RECT  16.368 3.925 16.392 5.459 ;
     RECT  123.408 4.501 124.248 5.459 ;
     RECT  43.968 3.925 43.992 5.461 ;
     RECT  90.624 3.973 90.648 5.461 ;
     RECT  91.776 5.317 91.848 5.461 ;
     RECT  54.432 4.261 54.456 5.507 ;
     RECT  90.624 5.461 91.848 5.507 ;
     RECT  18.144 2.915 18.912 5.605 ;
     RECT  71.664 3.397 72.912 5.605 ;
     RECT  123.408 5.459 124.056 5.605 ;
     RECT  137.4 3.349 139.176 5.605 ;
     RECT  43.968 5.461 44.616 5.653 ;
     RECT  45.6 3.733 46.392 5.653 ;
     RECT  50.88 5.219 51.312 5.653 ;
     RECT  52.608 4.933 52.632 5.653 ;
     RECT  103.2 5.125 103.944 5.653 ;
     RECT  105 5.075 105.432 5.653 ;
     RECT  34.8 5.315 36.072 5.699 ;
     RECT  43.968 5.653 46.728 5.699 ;
     RECT  111.936 5.029 111.96 5.699 ;
     RECT  114.288 5.365 116.112 5.699 ;
     RECT  0.432 4.739 0.456 5.747 ;
     RECT  10.416 4.501 12.024 5.747 ;
     RECT  38.784 4.019 41.352 5.747 ;
     RECT  48.768 5.077 48.792 5.747 ;
     RECT  90.864 5.507 91.848 5.747 ;
     RECT  134.256 5.173 134.28 5.747 ;
     RECT  87.648 5.365 89.256 5.797 ;
     RECT  94.2 4.501 95.496 5.843 ;
     RECT  26.4 5.171 26.664 5.891 ;
     RECT  2.304 3.397 4.488 5.941 ;
     RECT  6.096 5.605 6.12 5.941 ;
     RECT  2.304 5.941 6.12 5.987 ;
     RECT  22.944 4.309 24.408 5.987 ;
     RECT  103.2 5.653 105.432 5.987 ;
     RECT  10.416 5.747 11.256 5.989 ;
     RECT  136.704 5.605 139.176 5.989 ;
     RECT  44.592 5.699 46.728 6.035 ;
     RECT  87.648 5.797 89.592 6.035 ;
     RECT  61.68 5.365 63.144 6.131 ;
     RECT  88.8 6.035 89.592 6.131 ;
     RECT  104.88 5.987 105.432 6.131 ;
     RECT  5.28 5.987 6.12 6.229 ;
     RECT  98.592 5.029 100.296 6.229 ;
     RECT  55.776 3.781 56.712 6.275 ;
     RECT  80.304 5.173 80.424 6.275 ;
     RECT  136.704 5.989 139.512 6.275 ;
     RECT  7.584 4.261 8.424 6.323 ;
     RECT  9.84 5.989 11.256 6.323 ;
     RECT  42.336 2.339 42.36 6.323 ;
     RECT  44.88 6.035 46.728 6.323 ;
     RECT  74.976 5.989 75 6.323 ;
     RECT  78 4.693 78.6 6.323 ;
     RECT  119.712 4.931 121.512 6.323 ;
     RECT  61.68 6.131 62.232 6.371 ;
     RECT  28.512 5.315 29.712 6.419 ;
     RECT  132 4.691 132.312 6.469 ;
     RECT  50.88 5.653 52.632 6.515 ;
     RECT  80.304 6.275 80.328 6.515 ;
     RECT  17.616 5.605 18.912 6.563 ;
     RECT  20.496 4.501 20.52 6.563 ;
     RECT  108.864 5.029 110.712 6.563 ;
     RECT  22.944 5.987 24.312 6.565 ;
     RECT  29.4 6.419 29.712 6.565 ;
     RECT  115.344 5.699 116.112 6.565 ;
     RECT  34.8 5.699 35.256 6.659 ;
     RECT  136.8 6.275 139.512 6.661 ;
     RECT  140.496 5.269 141.24 6.661 ;
     RECT  103.2 5.987 103.752 6.707 ;
     RECT  125.472 5.365 127.704 6.755 ;
     RECT  31.488 4.453 32.616 6.805 ;
     RECT  13.104 4.693 13.512 6.851 ;
     RECT  15.936 5.461 15.96 6.851 ;
     RECT  44.88 6.323 46.488 6.851 ;
     RECT  70.704 5.605 72.912 6.851 ;
     RECT  83.28 3.925 85.416 6.851 ;
     RECT  98.592 6.229 101.016 6.851 ;
     RECT  122.832 5.605 124.056 6.851 ;
     RECT  94.2 5.843 94.512 6.853 ;
     RECT  5.28 6.229 6.168 6.899 ;
     RECT  22.608 6.565 24.312 6.899 ;
     RECT  39.312 5.747 41.352 6.899 ;
     RECT  52.608 6.515 52.632 6.899 ;
     RECT  68.928 4.933 68.952 6.899 ;
     RECT  82.032 5.221 82.056 6.899 ;
     RECT  91.776 5.747 91.8 6.899 ;
     RECT  118.128 5.029 118.152 6.899 ;
     RECT  123.408 6.851 124.056 6.899 ;
     RECT  31.056 6.805 32.616 6.947 ;
     RECT  45.6 6.851 46.488 6.947 ;
     RECT  64.896 5.219 64.92 6.947 ;
     RECT  131.904 6.469 132.312 6.947 ;
     RECT  29.4 6.565 29.976 6.995 ;
     RECT  9.84 6.323 10.44 7.043 ;
     RECT  136.8 6.661 141.24 7.091 ;
     RECT  2.304 5.987 4.008 7.139 ;
     RECT  105 6.131 105.432 7.139 ;
     RECT  99.216 6.851 100.296 7.283 ;
     RECT  114.288 5.699 114.312 7.331 ;
     RECT  115.344 6.565 116.232 7.331 ;
     RECT  61.8 6.371 62.232 7.379 ;
     RECT  63.792 6.853 63.816 7.427 ;
     RECT  26.64 5.891 26.664 7.475 ;
     RECT  94.2 6.853 95.208 7.475 ;
     RECT  125.712 6.755 127.704 7.475 ;
     RECT  137.4 7.091 141.24 7.475 ;
     RECT  103.728 6.707 103.752 7.619 ;
     RECT  5.28 6.899 5.304 7.667 ;
     RECT  134.4 6.229 134.424 7.667 ;
     RECT  22.944 6.899 24.312 8.003 ;
     RECT  31.488 6.947 32.616 8.003 ;
     RECT  39.312 6.899 40.512 8.003 ;
     RECT  83.4 6.851 85.416 8.003 ;
     RECT  87.648 6.035 87.672 8.003 ;
     RECT  88.8 6.131 89.256 8.003 ;
     RECT  99.216 7.283 99.912 8.003 ;
     RECT  109.584 6.563 110.712 8.003 ;
     RECT  126.6 7.475 127.704 8.003 ;
     RECT  137.4 7.475 141.144 8.003 ;
     RECT  137.4 8.003 139.512 8.147 ;
     RECT  126.6 8.003 127.08 8.195 ;
     RECT  7.584 6.323 8.112 8.579 ;
     RECT  10.416 7.043 10.44 8.579 ;
     RECT  22.944 8.003 22.968 8.579 ;
     RECT  31.488 8.003 32.28 8.579 ;
     RECT  33.744 5.315 33.768 8.579 ;
     RECT  45.6 6.947 46.392 8.579 ;
     RECT  50.88 6.515 51.312 8.579 ;
     RECT  55.92 6.275 56.712 8.579 ;
     RECT  71.664 6.851 72.912 8.579 ;
     RECT  85.2 8.003 85.224 8.579 ;
     RECT  86.496 3.733 86.52 8.579 ;
     RECT  115.344 7.331 116.112 8.579 ;
     RECT  119.712 6.323 119.736 8.579 ;
     RECT  124.032 6.899 124.056 8.579 ;
     RECT  130.032 3.877 130.056 8.579 ;
     RECT  137.4 8.147 139.08 8.579 ;
     RECT  140.496 8.003 141.144 8.579 ;
     RECT  56.016 8.579 56.712 8.627 ;
     RECT  78 6.323 78.456 8.963 ;
     RECT  2.4 7.139 4.008 9.011 ;
     RECT  2.4 9.011 3.48 9.155 ;
     RECT  60.192 5.219 60.216 9.155 ;
     RECT  140.592 8.579 141.144 9.155 ;
     RECT  140.592 9.155 140.616 9.731 ;
     RECT  39.744 8.003 40.512 10.883 ;
     RECT  107.424 6.805 107.448 11.939 ;
     RECT  105 7.139 105.312 12.517 ;
     RECT  72.6 8.579 72.912 12.853 ;
     RECT  71.76 12.853 72.912 13.091 ;
     RECT  38.256 11.365 38.28 13.907 ;
     RECT  105 12.517 105.432 14.773 ;
     RECT  29.4 6.995 29.712 16.933 ;
     RECT  34.8 6.659 35.112 16.933 ;
     RECT  2.4 9.155 2.712 17.077 ;
     RECT  4.128 16.501 4.152 17.077 ;
     RECT  18.6 6.563 18.912 17.077 ;
     RECT  24 8.003 24.312 17.077 ;
     RECT  28.368 16.933 28.392 17.077 ;
     RECT  34.8 16.933 35.448 17.077 ;
     RECT  45.6 8.579 45.912 17.077 ;
     RECT  61.8 7.379 62.112 17.077 ;
     RECT  13.2 6.851 13.512 17.461 ;
     RECT  18.096 17.077 19.08 17.461 ;
     RECT  38.544 14.005 38.568 17.461 ;
     RECT  40.2 10.883 40.512 17.461 ;
     RECT  45.6 17.077 46.488 17.461 ;
     RECT  56.4 8.627 56.712 17.461 ;
     RECT  88.8 8.003 89.112 17.461 ;
     RECT  13.2 17.461 13.896 17.605 ;
     RECT  18.096 17.461 19.224 17.605 ;
     RECT  29.4 16.933 29.928 17.605 ;
     RECT  31.296 17.077 31.32 17.605 ;
     RECT  37.008 16.933 37.032 17.605 ;
     RECT  38.544 17.461 39.048 17.605 ;
     RECT  45.6 17.461 46.536 17.605 ;
     RECT  51 8.579 51.312 17.605 ;
     RECT  56.4 17.461 57.336 17.605 ;
     RECT  60.384 17.077 60.408 17.605 ;
     RECT  61.8 17.077 62.904 17.605 ;
     RECT  66.096 17.461 66.12 17.605 ;
     RECT  67.2 1.859 67.512 17.605 ;
     RECT  91.872 17.461 91.896 17.605 ;
     RECT  132 6.947 132.312 17.605 ;
     RECT  137.4 8.579 137.712 17.605 ;
     RECT  67.2 17.605 68.904 17.989 ;
     RECT  71.856 13.091 72.912 17.989 ;
     RECT  105 14.773 105.528 17.989 ;
     RECT  134.352 13.621 134.376 17.989 ;
     RECT  103.008 17.605 103.032 18.085 ;
     RECT  2.4 17.077 4.152 18.131 ;
     RECT  17.328 17.605 19.224 18.133 ;
     RECT  10.464 17.461 10.488 18.181 ;
     RECT  11.712 17.365 11.736 18.181 ;
     RECT  13.2 17.605 14.424 18.181 ;
     RECT  16.704 18.133 19.224 18.181 ;
     RECT  26.112 17.605 26.136 18.181 ;
     RECT  33.648 17.605 33.672 18.181 ;
     RECT  51 17.605 51.864 18.181 ;
     RECT  60.384 17.605 60.504 18.181 ;
     RECT  61.536 17.605 62.904 18.181 ;
     RECT  65.76 17.605 66.12 18.181 ;
     RECT  88.704 17.461 89.112 18.181 ;
     RECT  99.6 8.003 99.912 18.181 ;
     RECT  103.008 18.085 103.848 18.181 ;
     RECT  105 17.989 106.056 18.181 ;
     RECT  137.4 17.605 138.312 18.181 ;
     RECT  11.712 18.181 19.224 18.275 ;
     RECT  28.128 17.077 28.392 18.275 ;
     RECT  37.008 17.605 39.048 18.275 ;
     RECT  134.112 17.989 134.376 18.275 ;
     RECT  59.184 18.181 62.904 18.565 ;
     RECT  137.4 18.181 138.936 18.565 ;
     RECT  59.184 18.565 63.72 18.709 ;
     RECT  7.8 8.579 8.112 18.757 ;
     RECT  21.36 17.605 21.48 18.757 ;
     RECT  132 17.605 132.408 18.757 ;
     RECT  11.856 18.275 17.352 18.851 ;
     RECT  18.432 18.275 19.224 18.851 ;
     RECT  20.352 17.077 20.376 18.851 ;
     RECT  24 17.077 24.408 18.851 ;
     RECT  26.112 18.181 26.856 18.851 ;
     RECT  28.368 18.275 28.392 18.851 ;
     RECT  29.4 17.605 31.992 18.851 ;
     RECT  42.72 17.605 42.744 18.851 ;
     RECT  52.992 17.605 53.016 18.851 ;
     RECT  56.304 17.605 58.056 18.851 ;
     RECT  67.2 17.989 69.096 18.851 ;
     RECT  87.744 18.181 89.112 18.851 ;
     RECT  10.464 18.181 10.68 18.899 ;
     RECT  56.304 18.851 57.336 18.995 ;
     RECT  86.496 17.461 86.52 19.043 ;
     RECT  34.8 17.077 35.592 19.093 ;
     RECT  10.656 18.899 10.68 19.237 ;
     RECT  10.656 19.237 10.824 19.333 ;
     RECT  11.856 18.851 14.136 19.333 ;
     RECT  15.36 18.851 17.352 19.333 ;
     RECT  18.48 18.851 19.224 19.333 ;
     RECT  31.584 18.851 31.992 19.333 ;
     RECT  33.12 18.181 33.672 19.333 ;
     RECT  40.2 17.461 40.728 19.333 ;
     RECT  59.04 18.709 63.72 19.333 ;
     RECT  110.4 8.003 110.712 19.333 ;
     RECT  134.112 18.275 134.136 19.381 ;
     RECT  26.832 18.851 26.856 19.427 ;
     RECT  29.4 18.851 30.552 19.427 ;
     RECT  31.584 19.333 33.672 19.427 ;
     RECT  45.6 17.605 47.4 19.427 ;
     RECT  48.576 17.605 48.6 19.427 ;
     RECT  58.512 19.333 63.72 19.427 ;
     RECT  64.8 18.181 66.12 19.427 ;
     RECT  69.072 18.851 69.096 19.427 ;
     RECT  71.232 17.989 72.912 19.427 ;
     RECT  87.744 18.851 87.768 19.427 ;
     RECT  91.152 17.605 91.896 19.427 ;
     RECT  99.6 18.181 101.736 19.427 ;
     RECT  102.96 18.181 106.056 19.427 ;
     RECT  103.008 19.427 106.056 19.429 ;
     RECT  58.512 19.427 59.208 19.475 ;
     RECT  2.4 18.131 2.808 19.477 ;
     RECT  3.936 18.131 4.152 19.477 ;
     RECT  2.4 19.477 4.152 19.523 ;
     RECT  5.952 19.093 5.976 19.523 ;
     RECT  21.36 18.757 22.008 19.621 ;
     RECT  51 18.181 52.008 19.621 ;
     RECT  126.6 8.195 126.912 19.669 ;
     RECT  94.2 7.475 94.512 19.765 ;
     RECT  110.4 19.333 110.808 19.861 ;
     RECT  10.656 19.333 14.136 19.909 ;
     RECT  65.136 19.427 66.12 19.909 ;
     RECT  67.2 18.851 67.512 19.909 ;
     RECT  110.304 19.861 110.808 19.909 ;
     RECT  15.36 19.333 17.4 20.003 ;
     RECT  21.36 19.621 22.632 20.003 ;
     RECT  60.384 19.427 63.72 20.003 ;
     RECT  92.976 18.181 93 20.003 ;
     RECT  133.92 19.381 134.136 20.003 ;
     RECT  103.008 19.429 106.296 20.051 ;
     RECT  104.688 20.051 106.296 20.099 ;
     RECT  29.4 19.427 29.712 20.149 ;
     RECT  22.08 20.003 22.632 20.195 ;
     RECT  65.136 19.909 67.512 20.291 ;
     RECT  136.464 18.565 138.936 20.291 ;
     RECT  2.4 19.523 3.672 20.293 ;
     RECT  7.8 18.757 8.232 20.339 ;
     RECT  103.008 20.051 103.128 20.339 ;
     RECT  75.12 19.957 75.144 20.437 ;
     RECT  88.8 18.851 89.112 20.437 ;
     RECT  1.68 20.293 3.672 20.485 ;
     RECT  10.656 19.909 14.232 20.579 ;
     RECT  18.48 19.333 19.32 20.579 ;
     RECT  32.448 19.427 32.472 20.579 ;
     RECT  34.8 19.093 36.168 20.579 ;
     RECT  40.2 19.333 40.92 20.579 ;
     RECT  132 18.757 132.696 20.579 ;
     RECT  110.304 19.909 111.24 20.581 ;
     RECT  37.728 18.275 39.048 20.627 ;
     RECT  60.384 20.003 62.112 20.627 ;
     RECT  110.304 20.581 111.72 20.627 ;
     RECT  99.6 19.427 99.912 20.677 ;
     RECT  33.648 19.427 33.672 20.725 ;
     RECT  34.8 20.579 35.64 20.725 ;
     RECT  83.4 8.003 83.712 20.725 ;
     RECT  88.8 20.437 89.64 20.725 ;
     RECT  125.904 19.669 126.912 20.725 ;
     RECT  128.064 19.669 128.088 20.725 ;
     RECT  10.8 20.579 10.824 20.771 ;
     RECT  125.904 20.725 128.088 20.771 ;
     RECT  53.616 19.909 53.64 20.819 ;
     RECT  107.472 19.333 107.496 20.819 ;
     RECT  119.52 20.101 119.544 20.819 ;
     RECT  78 8.963 78.312 20.821 ;
     RECT  38.736 20.627 39.048 20.867 ;
     RECT  65.424 20.291 67.512 20.867 ;
     RECT  111.696 20.627 111.72 20.867 ;
     RECT  78 20.821 78.408 20.963 ;
     RECT  94.08 19.765 94.512 20.963 ;
     RECT  0.24 20.149 0.264 20.965 ;
     RECT  1.68 20.485 4.488 20.965 ;
     RECT  115.8 8.579 116.112 20.965 ;
     RECT  136.464 20.291 138.168 20.965 ;
     RECT  79.824 20.197 79.848 21.011 ;
     RECT  67.056 20.867 67.512 21.013 ;
     RECT  0.24 20.965 4.488 21.061 ;
     RECT  94.2 20.963 94.512 21.109 ;
     RECT  12.48 20.579 14.232 21.155 ;
     RECT  15.36 20.003 15.384 21.155 ;
     RECT  18.48 20.579 18.912 21.155 ;
     RECT  37.728 20.627 37.752 21.155 ;
     RECT  55.104 20.485 55.128 21.155 ;
     RECT  56.4 18.995 57.336 21.155 ;
     RECT  58.512 19.475 59.064 21.155 ;
     RECT  63.12 20.003 63.72 21.155 ;
     RECT  74.496 20.437 75.672 21.155 ;
     RECT  101.088 19.427 101.112 21.155 ;
     RECT  108.672 19.669 108.696 21.155 ;
     RECT  38.784 20.867 39.048 21.203 ;
     RECT  63.12 21.155 63.144 21.203 ;
     RECT  133.92 20.003 133.944 21.203 ;
     RECT  88.464 20.725 89.64 21.349 ;
     RECT  105 20.099 106.296 21.395 ;
     RECT  132 20.579 132.408 21.397 ;
     RECT  61.152 20.627 62.112 21.443 ;
     RECT  86.064 20.149 86.088 21.539 ;
     RECT  16.512 20.003 17.4 21.635 ;
     RECT  25.968 20.437 25.992 21.637 ;
     RECT  125.904 20.771 127.704 21.637 ;
     RECT  12.48 21.155 13.512 21.683 ;
     RECT  17.376 21.635 17.4 21.683 ;
     RECT  22.08 20.195 22.152 21.683 ;
     RECT  39.024 21.203 39.048 21.683 ;
     RECT  45.6 19.427 47.064 21.683 ;
     RECT  65.424 20.867 65.736 21.683 ;
     RECT  69.264 19.909 69.288 21.683 ;
     RECT  103.008 20.339 103.032 21.683 ;
     RECT  131.904 21.397 132.408 21.683 ;
     RECT  51 19.621 52.056 21.731 ;
     RECT  67.056 21.013 67.608 21.731 ;
     RECT  83.232 20.725 83.712 21.781 ;
     RECT  110.304 20.627 110.712 22.021 ;
     RECT  33.648 20.725 35.64 22.067 ;
     RECT  65.712 21.683 65.736 22.069 ;
     RECT  99.6 20.677 100.008 22.163 ;
     RECT  125.856 21.637 127.704 22.163 ;
     RECT  65.712 22.069 66.072 22.165 ;
     RECT  67.056 21.731 67.512 22.165 ;
     RECT  30.816 21.061 30.84 22.211 ;
     RECT  118.32 20.965 118.344 22.211 ;
     RECT  34.8 22.067 35.64 22.259 ;
     RECT  44.496 17.605 44.52 22.259 ;
     RECT  59.04 21.155 59.064 22.259 ;
     RECT  61.68 21.443 62.112 22.259 ;
     RECT  101.424 21.541 101.448 22.259 ;
     RECT  105 21.395 106.152 22.259 ;
     RECT  33.648 22.067 33.672 22.307 ;
     RECT  25.968 21.637 26.808 22.451 ;
     RECT  94.2 21.109 95.496 22.451 ;
     RECT  125.856 22.163 127.08 22.451 ;
     RECT  105 22.259 105.312 22.501 ;
     RECT  0.24 21.061 5.352 22.741 ;
     RECT  24 18.851 24.312 22.741 ;
     RECT  29.28 20.149 29.712 22.741 ;
     RECT  45.6 21.683 46.008 22.741 ;
     RECT  51 21.731 51.312 22.741 ;
     RECT  94.2 22.451 94.968 22.741 ;
     RECT  115.8 20.965 116.28 22.741 ;
     RECT  121.2 6.323 121.512 22.741 ;
     RECT  131.904 21.683 132.312 22.741 ;
     RECT  45.6 22.741 46.152 22.789 ;
     RECT  76.8 19.909 76.824 22.789 ;
     RECT  71.856 19.427 72.912 23.317 ;
     RECT  74.496 21.155 74.664 23.317 ;
     RECT  136.272 20.965 138.168 23.317 ;
     RECT  7.8 20.339 8.112 23.365 ;
     RECT  9.648 21.637 9.672 23.365 ;
     RECT  13.104 21.683 13.512 23.365 ;
     RECT  18.6 21.155 18.912 23.365 ;
     RECT  22.128 21.683 22.152 23.365 ;
     RECT  23.712 22.741 24.312 23.365 ;
     RECT  29.232 22.741 29.712 23.365 ;
     RECT  34.8 22.259 35.304 23.365 ;
     RECT  40.2 20.579 40.512 23.365 ;
     RECT  45.6 22.789 46.536 23.365 ;
     RECT  51 22.741 51.72 23.365 ;
     RECT  53.472 21.541 53.496 23.365 ;
     RECT  56.4 21.155 56.856 23.365 ;
     RECT  61.8 22.259 62.112 23.365 ;
     RECT  65.712 22.165 67.512 23.365 ;
     RECT  71.856 23.317 74.664 23.365 ;
     RECT  75.648 21.155 75.672 23.365 ;
     RECT  76.8 22.789 77.016 23.365 ;
     RECT  78 20.963 78.312 23.365 ;
     RECT  81.024 22.789 81.048 23.365 ;
     RECT  83.04 21.781 83.712 23.365 ;
     RECT  85.44 22.741 85.464 23.365 ;
     RECT  99.6 22.163 99.912 23.365 ;
     RECT  104.88 22.501 105.312 23.365 ;
     RECT  110.304 22.021 110.904 23.365 ;
     RECT  114.816 22.741 116.28 23.365 ;
     RECT  123.696 20.485 123.72 23.365 ;
     RECT  126.6 22.451 127.08 23.365 ;
     RECT  128.304 22.165 128.328 23.365 ;
     RECT  131.904 22.741 132.792 23.365 ;
     RECT  136.272 23.317 138.552 23.365 ;
     RECT  141.744 22.789 141.768 23.365 ;
     RECT  7.584 23.365 10.68 23.413 ;
     RECT  98.352 23.365 98.376 23.413 ;
     RECT  112.944 23.365 116.472 23.413 ;
     RECT  139.584 23.365 139.608 23.413 ;
     RECT  140.64 23.365 141.768 23.413 ;
     RECT  43.296 23.365 43.32 23.701 ;
     RECT  126.6 23.365 128.328 23.701 ;
     RECT  130.992 23.365 133.128 23.701 ;
     RECT  134.208 23.365 134.232 23.701 ;
     RECT  7.584 23.413 10.824 23.749 ;
     RECT  11.904 23.365 14.808 23.749 ;
     RECT  123.264 23.365 124.536 23.749 ;
     RECT  135.84 23.365 138.552 23.749 ;
     RECT  139.584 23.413 141.768 23.749 ;
     RECT  0.048 22.741 5.352 23.797 ;
     RECT  6.528 23.365 6.552 23.797 ;
     RECT  7.584 23.749 14.808 23.797 ;
     RECT  15.84 23.365 17.304 23.797 ;
     RECT  25.968 22.451 25.992 23.797 ;
     RECT  27.312 23.365 27.336 23.797 ;
     RECT  40.2 23.365 41.16 23.797 ;
     RECT  45.072 23.365 49.416 23.797 ;
     RECT  50.832 23.365 52.104 23.797 ;
     RECT  53.136 23.365 87.048 23.797 ;
     RECT  88.128 21.349 89.64 23.797 ;
     RECT  93.312 22.741 94.968 23.797 ;
     RECT  96 23.365 96.024 23.797 ;
     RECT  98.352 23.413 98.52 23.797 ;
     RECT  99.6 23.365 110.904 23.797 ;
     RECT  119.328 23.365 119.352 23.797 ;
     RECT  123.072 23.749 124.536 23.797 ;
     RECT  126.48 23.701 128.328 23.797 ;
     RECT  130.992 23.701 134.232 23.797 ;
     RECT  0.048 23.797 6.552 23.845 ;
     RECT  7.584 23.797 17.304 23.845 ;
     RECT  18.6 23.365 19.08 23.845 ;
     RECT  20.304 23.365 24.984 23.845 ;
     RECT  25.968 23.797 27.336 23.845 ;
     RECT  29.232 23.365 35.592 23.845 ;
     RECT  37.536 23.749 37.56 23.845 ;
     RECT  38.592 23.797 41.16 23.845 ;
     RECT  42.72 23.701 43.32 23.845 ;
     RECT  44.352 23.797 89.64 23.845 ;
     RECT  90.96 23.701 90.984 23.845 ;
     RECT  92.256 23.797 92.28 23.845 ;
     RECT  93.312 23.797 96.024 23.845 ;
     RECT  97.968 23.797 98.52 23.845 ;
     RECT  99.6 23.797 111.432 23.845 ;
     RECT  112.944 23.413 116.664 23.845 ;
     RECT  119.328 23.797 119.688 23.845 ;
     RECT  120.768 22.741 121.512 23.845 ;
     RECT  122.928 23.797 128.328 23.845 ;
     RECT  129.36 23.365 129.912 23.845 ;
     RECT  0.048 23.845 24.984 23.893 ;
     RECT  25.968 23.845 28.248 23.893 ;
     RECT  29.232 23.845 96.552 23.893 ;
     RECT  97.968 23.845 116.664 23.893 ;
     RECT  117.696 23.845 117.72 23.893 ;
     RECT  118.8 23.845 129.912 23.893 ;
     RECT  130.992 23.797 134.568 23.893 ;
     RECT  135.84 23.749 141.768 23.893 ;
     RECT  0.048 23.893 141.768 25.765 ;
     RECT  0.048 25.765 142.488 25.872 ;
  END
END ot_s81_hc_ctfnq3
END LIBRARY
